VERSION 5.8 ;
BUSBITCHARS "[]" ;
DIVIDERCHAR "/" ;
UNITS
    DATABASE MICRONS 1000 ;
END UNITS

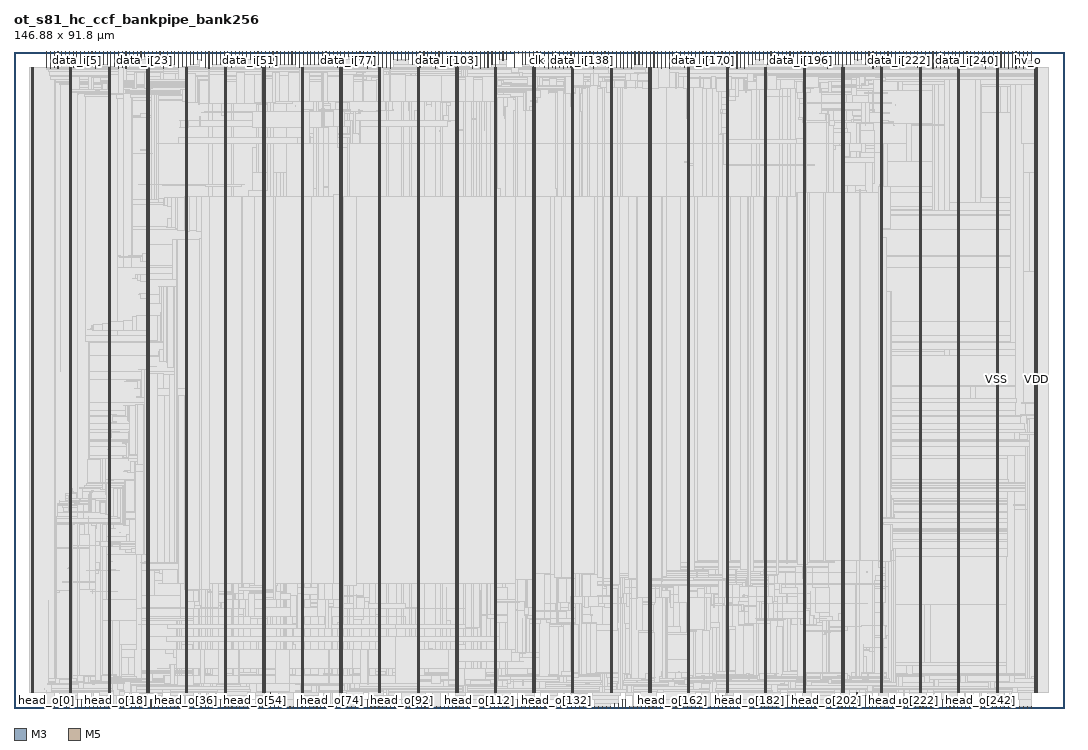
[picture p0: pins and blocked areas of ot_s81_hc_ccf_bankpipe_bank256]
MACRO ot_s81_hc_ccf_bankpipe_bank256
  FOREIGN ot_s81_hc_ccf_bankpipe_bank256 0 0 ;
  CLASS BLOCK ;
  SIZE 146.88 BY 91.8 ;
  PIN clk
    DIRECTION INPUT ;
    USE SIGNAL ;
    PORT
      LAYER M3 ;
        RECT  73.152 91.656 73.17 91.8 ;
    END
    PORT
      LAYER M3 ;
        RECT  73.152 91.579 73.17 91.692 ;
    END
  END clk
  PIN data_i[0]
    DIRECTION INPUT ;
    USE SIGNAL ;
    PORT
      LAYER M5 ;
        RECT  6.144 91.608 6.168 91.8 ;
    END
    PORT
      LAYER M5 ;
        RECT  6.144 89.509 6.168 91.664 ;
    END
  END data_i[0]
  PIN data_i[100]
    DIRECTION INPUT ;
    USE SIGNAL ;
    PORT
      LAYER M5 ;
        RECT  58.896 91.608 58.92 91.8 ;
    END
    PORT
      LAYER M5 ;
        RECT  58.896 89.509 58.92 91.664 ;
    END
  END data_i[100]
  PIN data_i[101]
    DIRECTION INPUT ;
    USE SIGNAL ;
    PORT
      LAYER M3 ;
        RECT  59.436 91.656 59.454 91.8 ;
    END
    PORT
      LAYER M3 ;
        RECT  59.436 90.077 59.454 91.692 ;
    END
  END data_i[101]
  PIN data_i[102]
    DIRECTION INPUT ;
    USE SIGNAL ;
    PORT
      LAYER M5 ;
        RECT  59.952 91.608 59.976 91.8 ;
    END
    PORT
      LAYER M5 ;
        RECT  59.952 90.037 59.976 91.664 ;
    END
  END data_i[102]
  PIN data_i[103]
    DIRECTION INPUT ;
    USE SIGNAL ;
    PORT
      LAYER M3 ;
        RECT  60.516 91.656 60.534 91.8 ;
    END
    PORT
      LAYER M3 ;
        RECT  60.516 90.653 60.534 91.692 ;
    END
  END data_i[103]
  PIN data_i[104]
    DIRECTION INPUT ;
    USE SIGNAL ;
    PORT
      LAYER M5 ;
        RECT  61.008 91.608 61.032 91.8 ;
    END
    PORT
      LAYER M5 ;
        RECT  61.008 90.613 61.032 91.664 ;
    END
  END data_i[104]
  PIN data_i[105]
    DIRECTION INPUT ;
    USE SIGNAL ;
    PORT
      LAYER M3 ;
        RECT  61.56 91.656 61.578 91.8 ;
    END
    PORT
      LAYER M3 ;
        RECT  61.56 90.653 61.578 91.692 ;
    END
  END data_i[105]
  PIN data_i[106]
    DIRECTION INPUT ;
    USE SIGNAL ;
    PORT
      LAYER M5 ;
        RECT  62.064 91.608 62.088 91.8 ;
    END
    PORT
      LAYER M5 ;
        RECT  62.064 89.663 62.088 91.664 ;
    END
  END data_i[106]
  PIN data_i[107]
    DIRECTION INPUT ;
    USE SIGNAL ;
    PORT
      LAYER M3 ;
        RECT  62.604 91.656 62.622 91.8 ;
    END
    PORT
      LAYER M3 ;
        RECT  62.604 90.077 62.622 91.692 ;
    END
  END data_i[107]
  PIN data_i[108]
    DIRECTION INPUT ;
    USE SIGNAL ;
    PORT
      LAYER M5 ;
        RECT  63.12 91.608 63.144 91.8 ;
    END
    PORT
      LAYER M5 ;
        RECT  63.12 90.037 63.144 91.664 ;
    END
  END data_i[108]
  PIN data_i[109]
    DIRECTION INPUT ;
    USE SIGNAL ;
    PORT
      LAYER M3 ;
        RECT  63.684 91.656 63.702 91.8 ;
    END
    PORT
      LAYER M3 ;
        RECT  63.684 90.077 63.702 91.692 ;
    END
  END data_i[109]
  PIN data_i[10]
    DIRECTION INPUT ;
    USE SIGNAL ;
    PORT
      LAYER M5 ;
        RECT  11.424 91.608 11.448 91.8 ;
    END
    PORT
      LAYER M5 ;
        RECT  11.424 89.509 11.448 91.664 ;
    END
  END data_i[10]
  PIN data_i[110]
    DIRECTION INPUT ;
    USE SIGNAL ;
    PORT
      LAYER M5 ;
        RECT  64.176 91.608 64.2 91.8 ;
    END
    PORT
      LAYER M5 ;
        RECT  64.176 89.509 64.2 91.664 ;
    END
  END data_i[110]
  PIN data_i[111]
    DIRECTION INPUT ;
    USE SIGNAL ;
    PORT
      LAYER M3 ;
        RECT  64.728 91.656 64.746 91.8 ;
    END
    PORT
      LAYER M3 ;
        RECT  64.728 89.549 64.746 91.692 ;
    END
  END data_i[111]
  PIN data_i[112]
    DIRECTION INPUT ;
    USE SIGNAL ;
    PORT
      LAYER M5 ;
        RECT  65.232 91.608 65.256 91.8 ;
    END
    PORT
      LAYER M5 ;
        RECT  65.232 89.509 65.256 91.664 ;
    END
  END data_i[112]
  PIN data_i[113]
    DIRECTION INPUT ;
    USE SIGNAL ;
    PORT
      LAYER M3 ;
        RECT  65.772 91.656 65.79 91.8 ;
    END
    PORT
      LAYER M3 ;
        RECT  65.772 89.549 65.79 91.692 ;
    END
  END data_i[113]
  PIN data_i[114]
    DIRECTION INPUT ;
    USE SIGNAL ;
    PORT
      LAYER M5 ;
        RECT  66.288 91.608 66.312 91.8 ;
    END
    PORT
      LAYER M5 ;
        RECT  66.288 89.663 66.312 91.664 ;
    END
  END data_i[114]
  PIN data_i[115]
    DIRECTION INPUT ;
    USE SIGNAL ;
    PORT
      LAYER M3 ;
        RECT  66.852 91.656 66.87 91.8 ;
    END
    PORT
      LAYER M3 ;
        RECT  66.852 90.077 66.87 91.692 ;
    END
  END data_i[115]
  PIN data_i[116]
    DIRECTION INPUT ;
    USE SIGNAL ;
    PORT
      LAYER M5 ;
        RECT  67.344 91.608 67.368 91.8 ;
    END
    PORT
      LAYER M5 ;
        RECT  67.344 89.663 67.368 91.664 ;
    END
  END data_i[116]
  PIN data_i[117]
    DIRECTION INPUT ;
    USE SIGNAL ;
    PORT
      LAYER M3 ;
        RECT  67.896 91.656 67.914 91.8 ;
    END
    PORT
      LAYER M3 ;
        RECT  67.896 90.653 67.914 91.692 ;
    END
  END data_i[117]
  PIN data_i[118]
    DIRECTION INPUT ;
    USE SIGNAL ;
    PORT
      LAYER M5 ;
        RECT  68.4 91.608 68.424 91.8 ;
    END
    PORT
      LAYER M5 ;
        RECT  68.4 90.613 68.424 91.664 ;
    END
  END data_i[118]
  PIN data_i[119]
    DIRECTION INPUT ;
    USE SIGNAL ;
    PORT
      LAYER M3 ;
        RECT  68.94 91.656 68.958 91.8 ;
    END
    PORT
      LAYER M3 ;
        RECT  68.94 90.653 68.958 91.692 ;
    END
  END data_i[119]
  PIN data_i[11]
    DIRECTION INPUT ;
    USE SIGNAL ;
    PORT
      LAYER M3 ;
        RECT  11.952 91.656 11.97 91.8 ;
    END
    PORT
      LAYER M3 ;
        RECT  11.952 90.077 11.97 91.692 ;
    END
  END data_i[11]
  PIN data_i[120]
    DIRECTION INPUT ;
    USE SIGNAL ;
    PORT
      LAYER M5 ;
        RECT  69.456 91.608 69.48 91.8 ;
    END
    PORT
      LAYER M5 ;
        RECT  69.456 91.619 69.48 91.664 ;
    END
  END data_i[120]
  PIN data_i[121]
    DIRECTION INPUT ;
    USE SIGNAL ;
    PORT
      LAYER M3 ;
        RECT  69.984 91.656 70.002 91.8 ;
    END
    PORT
      LAYER M3 ;
        RECT  69.984 89.549 70.002 91.692 ;
    END
  END data_i[121]
  PIN data_i[122]
    DIRECTION INPUT ;
    USE SIGNAL ;
    PORT
      LAYER M5 ;
        RECT  70.512 91.608 70.536 91.8 ;
    END
    PORT
      LAYER M5 ;
        RECT  70.512 91.619 70.536 91.664 ;
    END
  END data_i[122]
  PIN data_i[123]
    DIRECTION INPUT ;
    USE SIGNAL ;
    PORT
      LAYER M3 ;
        RECT  71.064 91.656 71.082 91.8 ;
    END
    PORT
      LAYER M3 ;
        RECT  71.064 90.077 71.082 91.692 ;
    END
  END data_i[123]
  PIN data_i[124]
    DIRECTION INPUT ;
    USE SIGNAL ;
    PORT
      LAYER M5 ;
        RECT  71.568 91.608 71.592 91.8 ;
    END
    PORT
      LAYER M5 ;
        RECT  71.568 90.037 71.592 91.664 ;
    END
  END data_i[124]
  PIN data_i[125]
    DIRECTION INPUT ;
    USE SIGNAL ;
    PORT
      LAYER M3 ;
        RECT  72.108 91.656 72.126 91.8 ;
    END
    PORT
      LAYER M3 ;
        RECT  72.108 90.077 72.126 91.692 ;
    END
  END data_i[125]
  PIN data_i[126]
    DIRECTION INPUT ;
    USE SIGNAL ;
    PORT
      LAYER M5 ;
        RECT  72.624 91.608 72.648 91.8 ;
    END
    PORT
      LAYER M5 ;
        RECT  72.624 89.663 72.648 91.664 ;
    END
  END data_i[126]
  PIN data_i[127]
    DIRECTION INPUT ;
    USE SIGNAL ;
    PORT
      LAYER M5 ;
        RECT  73.68 91.608 73.704 91.8 ;
    END
    PORT
      LAYER M5 ;
        RECT  73.68 90.613 73.704 91.664 ;
    END
  END data_i[127]
  PIN data_i[128]
    DIRECTION INPUT ;
    USE SIGNAL ;
    PORT
      LAYER M3 ;
        RECT  74.232 91.656 74.25 91.8 ;
    END
    PORT
      LAYER M3 ;
        RECT  74.232 89.549 74.25 91.692 ;
    END
  END data_i[128]
  PIN data_i[129]
    DIRECTION INPUT ;
    USE SIGNAL ;
    PORT
      LAYER M5 ;
        RECT  74.736 91.608 74.76 91.8 ;
    END
    PORT
      LAYER M5 ;
        RECT  74.736 89.509 74.76 91.664 ;
    END
  END data_i[129]
  PIN data_i[12]
    DIRECTION INPUT ;
    USE SIGNAL ;
    PORT
      LAYER M5 ;
        RECT  12.48 91.608 12.504 91.8 ;
    END
    PORT
      LAYER M5 ;
        RECT  12.48 90.037 12.504 91.664 ;
    END
  END data_i[12]
  PIN data_i[130]
    DIRECTION INPUT ;
    USE SIGNAL ;
    PORT
      LAYER M3 ;
        RECT  75.276 91.656 75.294 91.8 ;
    END
    PORT
      LAYER M3 ;
        RECT  75.276 89.549 75.294 91.692 ;
    END
  END data_i[130]
  PIN data_i[131]
    DIRECTION INPUT ;
    USE SIGNAL ;
    PORT
      LAYER M5 ;
        RECT  75.792 91.608 75.816 91.8 ;
    END
    PORT
      LAYER M5 ;
        RECT  75.792 89.509 75.816 91.664 ;
    END
  END data_i[131]
  PIN data_i[132]
    DIRECTION INPUT ;
    USE SIGNAL ;
    PORT
      LAYER M3 ;
        RECT  76.32 91.656 76.338 91.8 ;
    END
    PORT
      LAYER M3 ;
        RECT  76.32 89.549 76.338 91.692 ;
    END
  END data_i[132]
  PIN data_i[133]
    DIRECTION INPUT ;
    USE SIGNAL ;
    PORT
      LAYER M5 ;
        RECT  76.848 91.608 76.872 91.8 ;
    END
    PORT
      LAYER M5 ;
        RECT  76.848 89.509 76.872 91.664 ;
    END
  END data_i[133]
  PIN data_i[134]
    DIRECTION INPUT ;
    USE SIGNAL ;
    PORT
      LAYER M3 ;
        RECT  77.4 91.656 77.418 91.8 ;
    END
    PORT
      LAYER M3 ;
        RECT  77.4 89.657 77.418 91.692 ;
    END
  END data_i[134]
  PIN data_i[135]
    DIRECTION INPUT ;
    USE SIGNAL ;
    PORT
      LAYER M5 ;
        RECT  77.904 91.608 77.928 91.8 ;
    END
    PORT
      LAYER M5 ;
        RECT  77.904 89.663 77.928 91.664 ;
    END
  END data_i[135]
  PIN data_i[136]
    DIRECTION INPUT ;
    USE SIGNAL ;
    PORT
      LAYER M3 ;
        RECT  78.444 91.656 78.462 91.8 ;
    END
    PORT
      LAYER M3 ;
        RECT  78.444 90.077 78.462 91.692 ;
    END
  END data_i[136]
  PIN data_i[137]
    DIRECTION INPUT ;
    USE SIGNAL ;
    PORT
      LAYER M5 ;
        RECT  78.96 91.608 78.984 91.8 ;
    END
    PORT
      LAYER M5 ;
        RECT  78.96 90.037 78.984 91.664 ;
    END
  END data_i[137]
  PIN data_i[138]
    DIRECTION INPUT ;
    USE SIGNAL ;
    PORT
      LAYER M3 ;
        RECT  79.488 91.656 79.506 91.8 ;
    END
    PORT
      LAYER M3 ;
        RECT  79.488 90.077 79.506 91.692 ;
    END
  END data_i[138]
  PIN data_i[139]
    DIRECTION INPUT ;
    USE SIGNAL ;
    PORT
      LAYER M5 ;
        RECT  80.016 91.608 80.04 91.8 ;
    END
    PORT
      LAYER M5 ;
        RECT  80.016 90.037 80.04 91.664 ;
    END
  END data_i[139]
  PIN data_i[13]
    DIRECTION INPUT ;
    USE SIGNAL ;
    PORT
      LAYER M3 ;
        RECT  13.032 91.656 13.05 91.8 ;
    END
    PORT
      LAYER M3 ;
        RECT  13.032 90.077 13.05 91.692 ;
    END
  END data_i[13]
  PIN data_i[140]
    DIRECTION INPUT ;
    USE SIGNAL ;
    PORT
      LAYER M3 ;
        RECT  80.568 91.656 80.586 91.8 ;
    END
    PORT
      LAYER M3 ;
        RECT  80.568 90.077 80.586 91.692 ;
    END
  END data_i[140]
  PIN data_i[141]
    DIRECTION INPUT ;
    USE SIGNAL ;
    PORT
      LAYER M5 ;
        RECT  81.072 91.608 81.096 91.8 ;
    END
    PORT
      LAYER M5 ;
        RECT  81.072 89.509 81.096 91.664 ;
    END
  END data_i[141]
  PIN data_i[142]
    DIRECTION INPUT ;
    USE SIGNAL ;
    PORT
      LAYER M3 ;
        RECT  81.612 91.656 81.63 91.8 ;
    END
    PORT
      LAYER M3 ;
        RECT  81.612 90.077 81.63 91.692 ;
    END
  END data_i[142]
  PIN data_i[143]
    DIRECTION INPUT ;
    USE SIGNAL ;
    PORT
      LAYER M5 ;
        RECT  82.128 91.608 82.152 91.8 ;
    END
    PORT
      LAYER M5 ;
        RECT  82.128 90.037 82.152 91.664 ;
    END
  END data_i[143]
  PIN data_i[144]
    DIRECTION INPUT ;
    USE SIGNAL ;
    PORT
      LAYER M3 ;
        RECT  82.656 91.656 82.674 91.8 ;
    END
    PORT
      LAYER M3 ;
        RECT  82.656 90.077 82.674 91.692 ;
    END
  END data_i[144]
  PIN data_i[145]
    DIRECTION INPUT ;
    USE SIGNAL ;
    PORT
      LAYER M5 ;
        RECT  83.184 91.608 83.208 91.8 ;
    END
    PORT
      LAYER M5 ;
        RECT  83.184 89.663 83.208 91.664 ;
    END
  END data_i[145]
  PIN data_i[146]
    DIRECTION INPUT ;
    USE SIGNAL ;
    PORT
      LAYER M3 ;
        RECT  83.736 91.656 83.754 91.8 ;
    END
    PORT
      LAYER M3 ;
        RECT  83.736 89.657 83.754 91.692 ;
    END
  END data_i[146]
  PIN data_i[147]
    DIRECTION INPUT ;
    USE SIGNAL ;
    PORT
      LAYER M5 ;
        RECT  84.24 91.608 84.264 91.8 ;
    END
    PORT
      LAYER M5 ;
        RECT  84.24 89.663 84.264 91.664 ;
    END
  END data_i[147]
  PIN data_i[148]
    DIRECTION INPUT ;
    USE SIGNAL ;
    PORT
      LAYER M3 ;
        RECT  84.78 91.656 84.798 91.8 ;
    END
    PORT
      LAYER M3 ;
        RECT  84.78 89.549 84.798 91.692 ;
    END
  END data_i[148]
  PIN data_i[149]
    DIRECTION INPUT ;
    USE SIGNAL ;
    PORT
      LAYER M5 ;
        RECT  85.296 91.608 85.32 91.8 ;
    END
    PORT
      LAYER M5 ;
        RECT  85.296 89.509 85.32 91.664 ;
    END
  END data_i[149]
  PIN data_i[14]
    DIRECTION INPUT ;
    USE SIGNAL ;
    PORT
      LAYER M5 ;
        RECT  13.536 91.608 13.56 91.8 ;
    END
    PORT
      LAYER M5 ;
        RECT  13.536 89.749 13.56 91.664 ;
    END
  END data_i[14]
  PIN data_i[150]
    DIRECTION INPUT ;
    USE SIGNAL ;
    PORT
      LAYER M3 ;
        RECT  85.824 91.656 85.842 91.8 ;
    END
    PORT
      LAYER M3 ;
        RECT  85.824 89.549 85.842 91.692 ;
    END
  END data_i[150]
  PIN data_i[151]
    DIRECTION INPUT ;
    USE SIGNAL ;
    PORT
      LAYER M5 ;
        RECT  86.352 91.608 86.376 91.8 ;
    END
    PORT
      LAYER M5 ;
        RECT  86.352 89.509 86.376 91.664 ;
    END
  END data_i[151]
  PIN data_i[152]
    DIRECTION INPUT ;
    USE SIGNAL ;
    PORT
      LAYER M3 ;
        RECT  86.868 91.656 86.886 91.8 ;
    END
    PORT
      LAYER M3 ;
        RECT  86.868 90.077 86.886 91.692 ;
    END
  END data_i[152]
  PIN data_i[153]
    DIRECTION INPUT ;
    USE SIGNAL ;
    PORT
      LAYER M5 ;
        RECT  87.408 91.608 87.432 91.8 ;
    END
    PORT
      LAYER M5 ;
        RECT  87.408 90.037 87.432 91.664 ;
    END
  END data_i[153]
  PIN data_i[154]
    DIRECTION INPUT ;
    USE SIGNAL ;
    PORT
      LAYER M3 ;
        RECT  87.948 91.656 87.966 91.8 ;
    END
    PORT
      LAYER M3 ;
        RECT  87.948 90.077 87.966 91.692 ;
    END
  END data_i[154]
  PIN data_i[155]
    DIRECTION INPUT ;
    USE SIGNAL ;
    PORT
      LAYER M5 ;
        RECT  88.464 91.608 88.488 91.8 ;
    END
    PORT
      LAYER M5 ;
        RECT  88.464 89.663 88.488 91.664 ;
    END
  END data_i[155]
  PIN data_i[156]
    DIRECTION INPUT ;
    USE SIGNAL ;
    PORT
      LAYER M3 ;
        RECT  88.992 91.656 89.01 91.8 ;
    END
    PORT
      LAYER M3 ;
        RECT  88.992 89.657 89.01 91.692 ;
    END
  END data_i[156]
  PIN data_i[157]
    DIRECTION INPUT ;
    USE SIGNAL ;
    PORT
      LAYER M5 ;
        RECT  89.52 91.608 89.544 91.8 ;
    END
    PORT
      LAYER M5 ;
        RECT  89.52 89.663 89.544 91.664 ;
    END
  END data_i[157]
  PIN data_i[158]
    DIRECTION INPUT ;
    USE SIGNAL ;
    PORT
      LAYER M3 ;
        RECT  90.036 91.656 90.054 91.8 ;
    END
    PORT
      LAYER M3 ;
        RECT  90.036 89.549 90.054 91.692 ;
    END
  END data_i[158]
  PIN data_i[159]
    DIRECTION INPUT ;
    USE SIGNAL ;
    PORT
      LAYER M5 ;
        RECT  90.576 91.608 90.6 91.8 ;
    END
    PORT
      LAYER M5 ;
        RECT  90.576 89.509 90.6 91.664 ;
    END
  END data_i[159]
  PIN data_i[15]
    DIRECTION INPUT ;
    USE SIGNAL ;
    PORT
      LAYER M3 ;
        RECT  14.076 91.656 14.094 91.8 ;
    END
    PORT
      LAYER M3 ;
        RECT  14.076 89.789 14.094 91.692 ;
    END
  END data_i[15]
  PIN data_i[160]
    DIRECTION INPUT ;
    USE SIGNAL ;
    PORT
      LAYER M3 ;
        RECT  91.116 91.656 91.134 91.8 ;
    END
    PORT
      LAYER M3 ;
        RECT  91.116 89.549 91.134 91.692 ;
    END
  END data_i[160]
  PIN data_i[161]
    DIRECTION INPUT ;
    USE SIGNAL ;
    PORT
      LAYER M5 ;
        RECT  91.632 91.608 91.656 91.8 ;
    END
    PORT
      LAYER M5 ;
        RECT  91.632 89.509 91.656 91.664 ;
    END
  END data_i[161]
  PIN data_i[162]
    DIRECTION INPUT ;
    USE SIGNAL ;
    PORT
      LAYER M3 ;
        RECT  92.16 91.656 92.178 91.8 ;
    END
    PORT
      LAYER M3 ;
        RECT  92.16 90.077 92.178 91.692 ;
    END
  END data_i[162]
  PIN data_i[163]
    DIRECTION INPUT ;
    USE SIGNAL ;
    PORT
      LAYER M5 ;
        RECT  92.688 91.608 92.712 91.8 ;
    END
    PORT
      LAYER M5 ;
        RECT  92.688 90.037 92.712 91.664 ;
    END
  END data_i[163]
  PIN data_i[164]
    DIRECTION INPUT ;
    USE SIGNAL ;
    PORT
      LAYER M3 ;
        RECT  93.204 91.656 93.222 91.8 ;
    END
    PORT
      LAYER M3 ;
        RECT  93.204 90.077 93.222 91.692 ;
    END
  END data_i[164]
  PIN data_i[165]
    DIRECTION INPUT ;
    USE SIGNAL ;
    PORT
      LAYER M5 ;
        RECT  93.744 91.608 93.768 91.8 ;
    END
    PORT
      LAYER M5 ;
        RECT  93.744 89.663 93.768 91.664 ;
    END
  END data_i[165]
  PIN data_i[166]
    DIRECTION INPUT ;
    USE SIGNAL ;
    PORT
      LAYER M3 ;
        RECT  94.284 91.656 94.302 91.8 ;
    END
    PORT
      LAYER M3 ;
        RECT  94.284 90.077 94.302 91.692 ;
    END
  END data_i[166]
  PIN data_i[167]
    DIRECTION INPUT ;
    USE SIGNAL ;
    PORT
      LAYER M5 ;
        RECT  94.8 91.608 94.824 91.8 ;
    END
    PORT
      LAYER M5 ;
        RECT  94.8 90.037 94.824 91.664 ;
    END
  END data_i[167]
  PIN data_i[168]
    DIRECTION INPUT ;
    USE SIGNAL ;
    PORT
      LAYER M3 ;
        RECT  95.328 91.656 95.346 91.8 ;
    END
    PORT
      LAYER M3 ;
        RECT  95.328 90.077 95.346 91.692 ;
    END
  END data_i[168]
  PIN data_i[169]
    DIRECTION INPUT ;
    USE SIGNAL ;
    PORT
      LAYER M5 ;
        RECT  95.856 91.608 95.88 91.8 ;
    END
    PORT
      LAYER M5 ;
        RECT  95.856 89.509 95.88 91.664 ;
    END
  END data_i[169]
  PIN data_i[16]
    DIRECTION INPUT ;
    USE SIGNAL ;
    PORT
      LAYER M5 ;
        RECT  14.592 91.608 14.616 91.8 ;
    END
    PORT
      LAYER M5 ;
        RECT  14.592 89.509 14.616 91.664 ;
    END
  END data_i[16]
  PIN data_i[170]
    DIRECTION INPUT ;
    USE SIGNAL ;
    PORT
      LAYER M3 ;
        RECT  96.372 91.656 96.39 91.8 ;
    END
    PORT
      LAYER M3 ;
        RECT  96.372 90.653 96.39 91.692 ;
    END
  END data_i[170]
  PIN data_i[171]
    DIRECTION INPUT ;
    USE SIGNAL ;
    PORT
      LAYER M5 ;
        RECT  96.912 91.608 96.936 91.8 ;
    END
    PORT
      LAYER M5 ;
        RECT  96.912 90.613 96.936 91.664 ;
    END
  END data_i[171]
  PIN data_i[172]
    DIRECTION INPUT ;
    USE SIGNAL ;
    PORT
      LAYER M3 ;
        RECT  97.452 91.656 97.47 91.8 ;
    END
    PORT
      LAYER M3 ;
        RECT  97.452 90.653 97.47 91.692 ;
    END
  END data_i[172]
  PIN data_i[173]
    DIRECTION INPUT ;
    USE SIGNAL ;
    PORT
      LAYER M5 ;
        RECT  97.968 91.608 97.992 91.8 ;
    END
    PORT
      LAYER M5 ;
        RECT  97.968 90.037 97.992 91.664 ;
    END
  END data_i[173]
  PIN data_i[174]
    DIRECTION INPUT ;
    USE SIGNAL ;
    PORT
      LAYER M3 ;
        RECT  98.496 91.656 98.514 91.8 ;
    END
    PORT
      LAYER M3 ;
        RECT  98.496 90.077 98.514 91.692 ;
    END
  END data_i[174]
  PIN data_i[175]
    DIRECTION INPUT ;
    USE SIGNAL ;
    PORT
      LAYER M5 ;
        RECT  99.024 91.608 99.048 91.8 ;
    END
    PORT
      LAYER M5 ;
        RECT  99.024 90.037 99.048 91.664 ;
    END
  END data_i[175]
  PIN data_i[176]
    DIRECTION INPUT ;
    USE SIGNAL ;
    PORT
      LAYER M3 ;
        RECT  99.54 91.656 99.558 91.8 ;
    END
    PORT
      LAYER M3 ;
        RECT  99.54 90.077 99.558 91.692 ;
    END
  END data_i[176]
  PIN data_i[177]
    DIRECTION INPUT ;
    USE SIGNAL ;
    PORT
      LAYER M5 ;
        RECT  100.08 91.608 100.104 91.8 ;
    END
    PORT
      LAYER M5 ;
        RECT  100.08 89.663 100.104 91.664 ;
    END
  END data_i[177]
  PIN data_i[178]
    DIRECTION INPUT ;
    USE SIGNAL ;
    PORT
      LAYER M3 ;
        RECT  100.62 91.656 100.638 91.8 ;
    END
    PORT
      LAYER M3 ;
        RECT  100.62 89.549 100.638 91.692 ;
    END
  END data_i[178]
  PIN data_i[179]
    DIRECTION INPUT ;
    USE SIGNAL ;
    PORT
      LAYER M5 ;
        RECT  101.136 91.608 101.16 91.8 ;
    END
    PORT
      LAYER M5 ;
        RECT  101.136 89.509 101.16 91.664 ;
    END
  END data_i[179]
  PIN data_i[17]
    DIRECTION INPUT ;
    USE SIGNAL ;
    PORT
      LAYER M3 ;
        RECT  15.12 91.656 15.138 91.8 ;
    END
    PORT
      LAYER M3 ;
        RECT  15.12 89.549 15.138 91.692 ;
    END
  END data_i[17]
  PIN data_i[180]
    DIRECTION INPUT ;
    USE SIGNAL ;
    PORT
      LAYER M3 ;
        RECT  101.664 91.656 101.682 91.8 ;
    END
    PORT
      LAYER M3 ;
        RECT  101.664 89.549 101.682 91.692 ;
    END
  END data_i[180]
  PIN data_i[181]
    DIRECTION INPUT ;
    USE SIGNAL ;
    PORT
      LAYER M5 ;
        RECT  102.192 91.608 102.216 91.8 ;
    END
    PORT
      LAYER M5 ;
        RECT  102.192 89.509 102.216 91.664 ;
    END
  END data_i[181]
  PIN data_i[182]
    DIRECTION INPUT ;
    USE SIGNAL ;
    PORT
      LAYER M3 ;
        RECT  102.708 91.656 102.726 91.8 ;
    END
    PORT
      LAYER M3 ;
        RECT  102.708 90.077 102.726 91.692 ;
    END
  END data_i[182]
  PIN data_i[183]
    DIRECTION INPUT ;
    USE SIGNAL ;
    PORT
      LAYER M5 ;
        RECT  103.248 91.608 103.272 91.8 ;
    END
    PORT
      LAYER M5 ;
        RECT  103.248 90.037 103.272 91.664 ;
    END
  END data_i[183]
  PIN data_i[184]
    DIRECTION INPUT ;
    USE SIGNAL ;
    PORT
      LAYER M3 ;
        RECT  103.752 91.656 103.77 91.8 ;
    END
    PORT
      LAYER M3 ;
        RECT  103.752 90.653 103.77 91.692 ;
    END
  END data_i[184]
  PIN data_i[185]
    DIRECTION INPUT ;
    USE SIGNAL ;
    PORT
      LAYER M5 ;
        RECT  104.304 91.608 104.328 91.8 ;
    END
    PORT
      LAYER M5 ;
        RECT  104.304 90.613 104.328 91.664 ;
    END
  END data_i[185]
  PIN data_i[186]
    DIRECTION INPUT ;
    USE SIGNAL ;
    PORT
      LAYER M3 ;
        RECT  104.832 91.656 104.85 91.8 ;
    END
    PORT
      LAYER M3 ;
        RECT  104.832 90.653 104.85 91.692 ;
    END
  END data_i[186]
  PIN data_i[187]
    DIRECTION INPUT ;
    USE SIGNAL ;
    PORT
      LAYER M5 ;
        RECT  105.36 91.608 105.384 91.8 ;
    END
    PORT
      LAYER M5 ;
        RECT  105.36 90.037 105.384 91.664 ;
    END
  END data_i[187]
  PIN data_i[188]
    DIRECTION INPUT ;
    USE SIGNAL ;
    PORT
      LAYER M3 ;
        RECT  105.876 91.656 105.894 91.8 ;
    END
    PORT
      LAYER M3 ;
        RECT  105.876 90.077 105.894 91.692 ;
    END
  END data_i[188]
  PIN data_i[189]
    DIRECTION INPUT ;
    USE SIGNAL ;
    PORT
      LAYER M5 ;
        RECT  106.416 91.608 106.44 91.8 ;
    END
    PORT
      LAYER M5 ;
        RECT  106.416 90.037 106.44 91.664 ;
    END
  END data_i[189]
  PIN data_i[18]
    DIRECTION INPUT ;
    USE SIGNAL ;
    PORT
      LAYER M5 ;
        RECT  15.648 91.608 15.672 91.8 ;
    END
    PORT
      LAYER M5 ;
        RECT  15.648 89.509 15.672 91.664 ;
    END
  END data_i[18]
  PIN data_i[190]
    DIRECTION INPUT ;
    USE SIGNAL ;
    PORT
      LAYER M3 ;
        RECT  106.92 91.656 106.938 91.8 ;
    END
    PORT
      LAYER M3 ;
        RECT  106.92 90.077 106.938 91.692 ;
    END
  END data_i[190]
  PIN data_i[191]
    DIRECTION INPUT ;
    USE SIGNAL ;
    PORT
      LAYER M5 ;
        RECT  107.472 91.608 107.496 91.8 ;
    END
    PORT
      LAYER M5 ;
        RECT  107.472 90.037 107.496 91.664 ;
    END
  END data_i[191]
  PIN data_i[192]
    DIRECTION INPUT ;
    USE SIGNAL ;
    PORT
      LAYER M3 ;
        RECT  108 91.656 108.018 91.8 ;
    END
    PORT
      LAYER M3 ;
        RECT  108 90.077 108.018 91.692 ;
    END
  END data_i[192]
  PIN data_i[193]
    DIRECTION INPUT ;
    USE SIGNAL ;
    PORT
      LAYER M5 ;
        RECT  108.528 91.608 108.552 91.8 ;
    END
    PORT
      LAYER M5 ;
        RECT  108.528 90.037 108.552 91.664 ;
    END
  END data_i[193]
  PIN data_i[194]
    DIRECTION INPUT ;
    USE SIGNAL ;
    PORT
      LAYER M3 ;
        RECT  109.044 91.656 109.062 91.8 ;
    END
    PORT
      LAYER M3 ;
        RECT  109.044 90.077 109.062 91.692 ;
    END
  END data_i[194]
  PIN data_i[195]
    DIRECTION INPUT ;
    USE SIGNAL ;
    PORT
      LAYER M5 ;
        RECT  109.584 91.608 109.608 91.8 ;
    END
    PORT
      LAYER M5 ;
        RECT  109.584 89.663 109.608 91.664 ;
    END
  END data_i[195]
  PIN data_i[196]
    DIRECTION INPUT ;
    USE SIGNAL ;
    PORT
      LAYER M3 ;
        RECT  110.088 91.656 110.106 91.8 ;
    END
    PORT
      LAYER M3 ;
        RECT  110.088 91.181 110.106 91.692 ;
    END
  END data_i[196]
  PIN data_i[197]
    DIRECTION INPUT ;
    USE SIGNAL ;
    PORT
      LAYER M5 ;
        RECT  110.64 91.608 110.664 91.8 ;
    END
    PORT
      LAYER M5 ;
        RECT  110.64 91.141 110.664 91.664 ;
    END
  END data_i[197]
  PIN data_i[198]
    DIRECTION INPUT ;
    USE SIGNAL ;
    PORT
      LAYER M3 ;
        RECT  111.168 91.656 111.186 91.8 ;
    END
    PORT
      LAYER M3 ;
        RECT  111.168 91.181 111.186 91.692 ;
    END
  END data_i[198]
  PIN data_i[199]
    DIRECTION INPUT ;
    USE SIGNAL ;
    PORT
      LAYER M5 ;
        RECT  111.696 91.608 111.72 91.8 ;
    END
    PORT
      LAYER M5 ;
        RECT  111.696 90.037 111.72 91.664 ;
    END
  END data_i[199]
  PIN data_i[19]
    DIRECTION INPUT ;
    USE SIGNAL ;
    PORT
      LAYER M3 ;
        RECT  16.2 91.656 16.218 91.8 ;
    END
    PORT
      LAYER M3 ;
        RECT  16.2 90.077 16.218 91.692 ;
    END
  END data_i[19]
  PIN data_i[1]
    DIRECTION INPUT ;
    USE SIGNAL ;
    PORT
      LAYER M3 ;
        RECT  6.696 91.656 6.714 91.8 ;
    END
    PORT
      LAYER M3 ;
        RECT  6.696 90.077 6.714 91.692 ;
    END
  END data_i[1]
  PIN data_i[200]
    DIRECTION INPUT ;
    USE SIGNAL ;
    PORT
      LAYER M3 ;
        RECT  112.212 91.656 112.23 91.8 ;
    END
    PORT
      LAYER M3 ;
        RECT  112.212 90.077 112.23 91.692 ;
    END
  END data_i[200]
  PIN data_i[201]
    DIRECTION INPUT ;
    USE SIGNAL ;
    PORT
      LAYER M5 ;
        RECT  112.752 91.608 112.776 91.8 ;
    END
    PORT
      LAYER M5 ;
        RECT  112.752 90.037 112.776 91.664 ;
    END
  END data_i[201]
  PIN data_i[202]
    DIRECTION INPUT ;
    USE SIGNAL ;
    PORT
      LAYER M3 ;
        RECT  113.256 91.656 113.274 91.8 ;
    END
    PORT
      LAYER M3 ;
        RECT  113.256 90.077 113.274 91.692 ;
    END
  END data_i[202]
  PIN data_i[203]
    DIRECTION INPUT ;
    USE SIGNAL ;
    PORT
      LAYER M5 ;
        RECT  113.808 91.608 113.832 91.8 ;
    END
    PORT
      LAYER M5 ;
        RECT  113.808 89.509 113.832 91.664 ;
    END
  END data_i[203]
  PIN data_i[204]
    DIRECTION INPUT ;
    USE SIGNAL ;
    PORT
      LAYER M3 ;
        RECT  114.336 91.656 114.354 91.8 ;
    END
    PORT
      LAYER M3 ;
        RECT  114.336 90.077 114.354 91.692 ;
    END
  END data_i[204]
  PIN data_i[205]
    DIRECTION INPUT ;
    USE SIGNAL ;
    PORT
      LAYER M5 ;
        RECT  114.864 91.608 114.888 91.8 ;
    END
    PORT
      LAYER M5 ;
        RECT  114.864 90.037 114.888 91.664 ;
    END
  END data_i[205]
  PIN data_i[206]
    DIRECTION INPUT ;
    USE SIGNAL ;
    PORT
      LAYER M3 ;
        RECT  115.38 91.656 115.398 91.8 ;
    END
    PORT
      LAYER M3 ;
        RECT  115.38 90.077 115.398 91.692 ;
    END
  END data_i[206]
  PIN data_i[207]
    DIRECTION INPUT ;
    USE SIGNAL ;
    PORT
      LAYER M5 ;
        RECT  115.92 91.608 115.944 91.8 ;
    END
    PORT
      LAYER M5 ;
        RECT  115.92 89.663 115.944 91.664 ;
    END
  END data_i[207]
  PIN data_i[208]
    DIRECTION INPUT ;
    USE SIGNAL ;
    PORT
      LAYER M3 ;
        RECT  116.424 91.656 116.442 91.8 ;
    END
    PORT
      LAYER M3 ;
        RECT  116.424 90.077 116.442 91.692 ;
    END
  END data_i[208]
  PIN data_i[209]
    DIRECTION INPUT ;
    USE SIGNAL ;
    PORT
      LAYER M5 ;
        RECT  116.976 91.608 117 91.8 ;
    END
    PORT
      LAYER M5 ;
        RECT  116.976 90.037 117 91.664 ;
    END
  END data_i[209]
  PIN data_i[20]
    DIRECTION INPUT ;
    USE SIGNAL ;
    PORT
      LAYER M5 ;
        RECT  16.704 91.608 16.728 91.8 ;
    END
    PORT
      LAYER M5 ;
        RECT  16.704 90.037 16.728 91.664 ;
    END
  END data_i[20]
  PIN data_i[210]
    DIRECTION INPUT ;
    USE SIGNAL ;
    PORT
      LAYER M3 ;
        RECT  117.504 91.656 117.522 91.8 ;
    END
    PORT
      LAYER M3 ;
        RECT  117.504 90.653 117.522 91.692 ;
    END
  END data_i[210]
  PIN data_i[211]
    DIRECTION INPUT ;
    USE SIGNAL ;
    PORT
      LAYER M5 ;
        RECT  118.032 91.608 118.056 91.8 ;
    END
    PORT
      LAYER M5 ;
        RECT  118.032 90.613 118.056 91.664 ;
    END
  END data_i[211]
  PIN data_i[212]
    DIRECTION INPUT ;
    USE SIGNAL ;
    PORT
      LAYER M3 ;
        RECT  118.548 91.656 118.566 91.8 ;
    END
    PORT
      LAYER M3 ;
        RECT  118.548 90.653 118.566 91.692 ;
    END
  END data_i[212]
  PIN data_i[213]
    DIRECTION INPUT ;
    USE SIGNAL ;
    PORT
      LAYER M5 ;
        RECT  119.088 91.608 119.112 91.8 ;
    END
    PORT
      LAYER M5 ;
        RECT  119.088 90.037 119.112 91.664 ;
    END
  END data_i[213]
  PIN data_i[214]
    DIRECTION INPUT ;
    USE SIGNAL ;
    PORT
      LAYER M3 ;
        RECT  119.592 91.656 119.61 91.8 ;
    END
    PORT
      LAYER M3 ;
        RECT  119.592 90.077 119.61 91.692 ;
    END
  END data_i[214]
  PIN data_i[215]
    DIRECTION INPUT ;
    USE SIGNAL ;
    PORT
      LAYER M5 ;
        RECT  120.144 91.608 120.168 91.8 ;
    END
    PORT
      LAYER M5 ;
        RECT  120.144 89.509 120.168 91.664 ;
    END
  END data_i[215]
  PIN data_i[216]
    DIRECTION INPUT ;
    USE SIGNAL ;
    PORT
      LAYER M3 ;
        RECT  120.672 91.656 120.69 91.8 ;
    END
    PORT
      LAYER M3 ;
        RECT  120.672 89.789 120.69 91.692 ;
    END
  END data_i[216]
  PIN data_i[217]
    DIRECTION INPUT ;
    USE SIGNAL ;
    PORT
      LAYER M5 ;
        RECT  121.2 91.608 121.224 91.8 ;
    END
    PORT
      LAYER M5 ;
        RECT  121.2 89.663 121.224 91.664 ;
    END
  END data_i[217]
  PIN data_i[218]
    DIRECTION INPUT ;
    USE SIGNAL ;
    PORT
      LAYER M3 ;
        RECT  121.716 91.656 121.734 91.8 ;
    END
    PORT
      LAYER M3 ;
        RECT  121.716 90.077 121.734 91.692 ;
    END
  END data_i[218]
  PIN data_i[219]
    DIRECTION INPUT ;
    USE SIGNAL ;
    PORT
      LAYER M5 ;
        RECT  122.256 91.608 122.28 91.8 ;
    END
    PORT
      LAYER M5 ;
        RECT  122.256 90.037 122.28 91.664 ;
    END
  END data_i[219]
  PIN data_i[21]
    DIRECTION INPUT ;
    USE SIGNAL ;
    PORT
      LAYER M3 ;
        RECT  17.244 91.656 17.262 91.8 ;
    END
    PORT
      LAYER M3 ;
        RECT  17.244 90.653 17.262 91.692 ;
    END
  END data_i[21]
  PIN data_i[220]
    DIRECTION INPUT ;
    USE SIGNAL ;
    PORT
      LAYER M3 ;
        RECT  122.76 91.656 122.778 91.8 ;
    END
    PORT
      LAYER M3 ;
        RECT  122.76 90.077 122.778 91.692 ;
    END
  END data_i[220]
  PIN data_i[221]
    DIRECTION INPUT ;
    USE SIGNAL ;
    PORT
      LAYER M5 ;
        RECT  123.312 91.608 123.336 91.8 ;
    END
    PORT
      LAYER M5 ;
        RECT  123.312 89.509 123.336 91.664 ;
    END
  END data_i[221]
  PIN data_i[222]
    DIRECTION INPUT ;
    USE SIGNAL ;
    PORT
      LAYER M3 ;
        RECT  123.804 91.656 123.822 91.8 ;
    END
    PORT
      LAYER M3 ;
        RECT  123.804 90.653 123.822 91.692 ;
    END
  END data_i[222]
  PIN data_i[223]
    DIRECTION INPUT ;
    USE SIGNAL ;
    PORT
      LAYER M5 ;
        RECT  124.368 91.608 124.392 91.8 ;
    END
    PORT
      LAYER M5 ;
        RECT  124.368 90.613 124.392 91.664 ;
    END
  END data_i[223]
  PIN data_i[224]
    DIRECTION INPUT ;
    USE SIGNAL ;
    PORT
      LAYER M3 ;
        RECT  124.884 91.656 124.902 91.8 ;
    END
    PORT
      LAYER M3 ;
        RECT  124.884 90.653 124.902 91.692 ;
    END
  END data_i[224]
  PIN data_i[225]
    DIRECTION INPUT ;
    USE SIGNAL ;
    PORT
      LAYER M5 ;
        RECT  125.376 91.608 125.4 91.8 ;
    END
    PORT
      LAYER M5 ;
        RECT  125.376 90.037 125.4 91.664 ;
    END
  END data_i[225]
  PIN data_i[226]
    DIRECTION INPUT ;
    USE SIGNAL ;
    PORT
      LAYER M3 ;
        RECT  125.928 91.656 125.946 91.8 ;
    END
    PORT
      LAYER M3 ;
        RECT  125.928 90.077 125.946 91.692 ;
    END
  END data_i[226]
  PIN data_i[227]
    DIRECTION INPUT ;
    USE SIGNAL ;
    PORT
      LAYER M5 ;
        RECT  126.432 91.608 126.456 91.8 ;
    END
    PORT
      LAYER M5 ;
        RECT  126.432 89.663 126.456 91.664 ;
    END
  END data_i[227]
  PIN data_i[228]
    DIRECTION INPUT ;
    USE SIGNAL ;
    PORT
      LAYER M3 ;
        RECT  126.972 91.656 126.99 91.8 ;
    END
    PORT
      LAYER M3 ;
        RECT  126.972 90.077 126.99 91.692 ;
    END
  END data_i[228]
  PIN data_i[229]
    DIRECTION INPUT ;
    USE SIGNAL ;
    PORT
      LAYER M5 ;
        RECT  127.488 91.608 127.512 91.8 ;
    END
    PORT
      LAYER M5 ;
        RECT  127.488 90.037 127.512 91.664 ;
    END
  END data_i[229]
  PIN data_i[22]
    DIRECTION INPUT ;
    USE SIGNAL ;
    PORT
      LAYER M5 ;
        RECT  17.76 91.608 17.784 91.8 ;
    END
    PORT
      LAYER M5 ;
        RECT  17.76 90.613 17.784 91.664 ;
    END
  END data_i[22]
  PIN data_i[230]
    DIRECTION INPUT ;
    USE SIGNAL ;
    PORT
      LAYER M3 ;
        RECT  128.052 91.656 128.07 91.8 ;
    END
    PORT
      LAYER M3 ;
        RECT  128.052 90.077 128.07 91.692 ;
    END
  END data_i[230]
  PIN data_i[231]
    DIRECTION INPUT ;
    USE SIGNAL ;
    PORT
      LAYER M5 ;
        RECT  128.544 91.608 128.568 91.8 ;
    END
    PORT
      LAYER M5 ;
        RECT  128.544 89.509 128.568 91.664 ;
    END
  END data_i[231]
  PIN data_i[232]
    DIRECTION INPUT ;
    USE SIGNAL ;
    PORT
      LAYER M3 ;
        RECT  129.096 91.656 129.114 91.8 ;
    END
    PORT
      LAYER M3 ;
        RECT  129.096 89.549 129.114 91.692 ;
    END
  END data_i[232]
  PIN data_i[233]
    DIRECTION INPUT ;
    USE SIGNAL ;
    PORT
      LAYER M5 ;
        RECT  129.6 91.608 129.624 91.8 ;
    END
    PORT
      LAYER M5 ;
        RECT  129.6 89.509 129.624 91.664 ;
    END
  END data_i[233]
  PIN data_i[234]
    DIRECTION INPUT ;
    USE SIGNAL ;
    PORT
      LAYER M3 ;
        RECT  130.14 91.656 130.158 91.8 ;
    END
    PORT
      LAYER M3 ;
        RECT  130.14 89.549 130.158 91.692 ;
    END
  END data_i[234]
  PIN data_i[235]
    DIRECTION INPUT ;
    USE SIGNAL ;
    PORT
      LAYER M5 ;
        RECT  130.656 91.608 130.68 91.8 ;
    END
    PORT
      LAYER M5 ;
        RECT  130.656 89.509 130.68 91.664 ;
    END
  END data_i[235]
  PIN data_i[236]
    DIRECTION INPUT ;
    USE SIGNAL ;
    PORT
      LAYER M3 ;
        RECT  131.22 91.656 131.238 91.8 ;
    END
    PORT
      LAYER M3 ;
        RECT  131.22 90.077 131.238 91.692 ;
    END
  END data_i[236]
  PIN data_i[237]
    DIRECTION INPUT ;
    USE SIGNAL ;
    PORT
      LAYER M5 ;
        RECT  131.712 91.608 131.736 91.8 ;
    END
    PORT
      LAYER M5 ;
        RECT  131.712 90.037 131.736 91.664 ;
    END
  END data_i[237]
  PIN data_i[238]
    DIRECTION INPUT ;
    USE SIGNAL ;
    PORT
      LAYER M3 ;
        RECT  132.264 91.656 132.282 91.8 ;
    END
    PORT
      LAYER M3 ;
        RECT  132.264 90.077 132.282 91.692 ;
    END
  END data_i[238]
  PIN data_i[239]
    DIRECTION INPUT ;
    USE SIGNAL ;
    PORT
      LAYER M5 ;
        RECT  132.768 91.608 132.792 91.8 ;
    END
    PORT
      LAYER M5 ;
        RECT  132.768 89.663 132.792 91.664 ;
    END
  END data_i[239]
  PIN data_i[23]
    DIRECTION INPUT ;
    USE SIGNAL ;
    PORT
      LAYER M3 ;
        RECT  18.288 91.656 18.306 91.8 ;
    END
    PORT
      LAYER M3 ;
        RECT  18.288 91.181 18.306 91.692 ;
    END
  END data_i[23]
  PIN data_i[240]
    DIRECTION INPUT ;
    USE SIGNAL ;
    PORT
      LAYER M3 ;
        RECT  133.308 91.656 133.326 91.8 ;
    END
    PORT
      LAYER M3 ;
        RECT  133.308 90.077 133.326 91.692 ;
    END
  END data_i[240]
  PIN data_i[241]
    DIRECTION INPUT ;
    USE SIGNAL ;
    PORT
      LAYER M5 ;
        RECT  133.824 91.608 133.848 91.8 ;
    END
    PORT
      LAYER M5 ;
        RECT  133.824 90.037 133.848 91.664 ;
    END
  END data_i[241]
  PIN data_i[242]
    DIRECTION INPUT ;
    USE SIGNAL ;
    PORT
      LAYER M3 ;
        RECT  134.388 91.656 134.406 91.8 ;
    END
    PORT
      LAYER M3 ;
        RECT  134.388 90.077 134.406 91.692 ;
    END
  END data_i[242]
  PIN data_i[243]
    DIRECTION INPUT ;
    USE SIGNAL ;
    PORT
      LAYER M5 ;
        RECT  134.88 91.608 134.904 91.8 ;
    END
    PORT
      LAYER M5 ;
        RECT  134.88 90.037 134.904 91.664 ;
    END
  END data_i[243]
  PIN data_i[244]
    DIRECTION INPUT ;
    USE SIGNAL ;
    PORT
      LAYER M3 ;
        RECT  135.432 91.656 135.45 91.8 ;
    END
    PORT
      LAYER M3 ;
        RECT  135.432 90.077 135.45 91.692 ;
    END
  END data_i[244]
  PIN data_i[245]
    DIRECTION INPUT ;
    USE SIGNAL ;
    PORT
      LAYER M5 ;
        RECT  135.936 91.608 135.96 91.8 ;
    END
    PORT
      LAYER M5 ;
        RECT  135.936 89.509 135.96 91.664 ;
    END
  END data_i[245]
  PIN data_i[246]
    DIRECTION INPUT ;
    USE SIGNAL ;
    PORT
      LAYER M3 ;
        RECT  136.476 91.656 136.494 91.8 ;
    END
    PORT
      LAYER M3 ;
        RECT  136.476 90.077 136.494 91.692 ;
    END
  END data_i[246]
  PIN data_i[247]
    DIRECTION INPUT ;
    USE SIGNAL ;
    PORT
      LAYER M5 ;
        RECT  136.992 91.608 137.016 91.8 ;
    END
    PORT
      LAYER M5 ;
        RECT  136.992 90.037 137.016 91.664 ;
    END
  END data_i[247]
  PIN data_i[248]
    DIRECTION INPUT ;
    USE SIGNAL ;
    PORT
      LAYER M3 ;
        RECT  137.556 91.656 137.574 91.8 ;
    END
    PORT
      LAYER M3 ;
        RECT  137.556 90.077 137.574 91.692 ;
    END
  END data_i[248]
  PIN data_i[249]
    DIRECTION INPUT ;
    USE SIGNAL ;
    PORT
      LAYER M5 ;
        RECT  138.048 91.608 138.072 91.8 ;
    END
    PORT
      LAYER M5 ;
        RECT  138.048 89.663 138.072 91.664 ;
    END
  END data_i[249]
  PIN data_i[24]
    DIRECTION INPUT ;
    USE SIGNAL ;
    PORT
      LAYER M5 ;
        RECT  18.816 91.608 18.84 91.8 ;
    END
    PORT
      LAYER M5 ;
        RECT  18.816 91.141 18.84 91.664 ;
    END
  END data_i[24]
  PIN data_i[250]
    DIRECTION INPUT ;
    USE SIGNAL ;
    PORT
      LAYER M3 ;
        RECT  138.6 91.656 138.618 91.8 ;
    END
    PORT
      LAYER M3 ;
        RECT  138.6 89.549 138.618 91.692 ;
    END
  END data_i[250]
  PIN data_i[251]
    DIRECTION INPUT ;
    USE SIGNAL ;
    PORT
      LAYER M5 ;
        RECT  139.104 91.608 139.128 91.8 ;
    END
    PORT
      LAYER M5 ;
        RECT  139.104 89.509 139.128 91.664 ;
    END
  END data_i[251]
  PIN data_i[252]
    DIRECTION INPUT ;
    USE SIGNAL ;
    PORT
      LAYER M3 ;
        RECT  139.644 91.656 139.662 91.8 ;
    END
    PORT
      LAYER M3 ;
        RECT  139.644 89.549 139.662 91.692 ;
    END
  END data_i[252]
  PIN data_i[253]
    DIRECTION INPUT ;
    USE SIGNAL ;
    PORT
      LAYER M5 ;
        RECT  140.16 91.608 140.184 91.8 ;
    END
    PORT
      LAYER M5 ;
        RECT  140.16 89.509 140.184 91.664 ;
    END
  END data_i[253]
  PIN data_i[254]
    DIRECTION INPUT ;
    USE SIGNAL ;
    PORT
      LAYER M3 ;
        RECT  140.688 91.656 140.706 91.8 ;
    END
    PORT
      LAYER M3 ;
        RECT  140.688 89.549 140.706 91.692 ;
    END
  END data_i[254]
  PIN data_i[255]
    DIRECTION INPUT ;
    USE SIGNAL ;
    PORT
      LAYER M5 ;
        RECT  141.216 91.608 141.24 91.8 ;
    END
    PORT
      LAYER M5 ;
        RECT  141.216 89.509 141.24 91.664 ;
    END
  END data_i[255]
  PIN data_i[25]
    DIRECTION INPUT ;
    USE SIGNAL ;
    PORT
      LAYER M3 ;
        RECT  19.332 91.656 19.35 91.8 ;
    END
    PORT
      LAYER M3 ;
        RECT  19.332 91.181 19.35 91.692 ;
    END
  END data_i[25]
  PIN data_i[26]
    DIRECTION INPUT ;
    USE SIGNAL ;
    PORT
      LAYER M5 ;
        RECT  19.872 91.608 19.896 91.8 ;
    END
    PORT
      LAYER M5 ;
        RECT  19.872 90.037 19.896 91.664 ;
    END
  END data_i[26]
  PIN data_i[27]
    DIRECTION INPUT ;
    USE SIGNAL ;
    PORT
      LAYER M3 ;
        RECT  20.412 91.656 20.43 91.8 ;
    END
    PORT
      LAYER M3 ;
        RECT  20.412 90.077 20.43 91.692 ;
    END
  END data_i[27]
  PIN data_i[28]
    DIRECTION INPUT ;
    USE SIGNAL ;
    PORT
      LAYER M5 ;
        RECT  20.928 91.608 20.952 91.8 ;
    END
    PORT
      LAYER M5 ;
        RECT  20.928 89.509 20.952 91.664 ;
    END
  END data_i[28]
  PIN data_i[29]
    DIRECTION INPUT ;
    USE SIGNAL ;
    PORT
      LAYER M3 ;
        RECT  21.456 91.656 21.474 91.8 ;
    END
    PORT
      LAYER M3 ;
        RECT  21.456 90.077 21.474 91.692 ;
    END
  END data_i[29]
  PIN data_i[2]
    DIRECTION INPUT ;
    USE SIGNAL ;
    PORT
      LAYER M5 ;
        RECT  7.2 91.608 7.224 91.8 ;
    END
    PORT
      LAYER M5 ;
        RECT  7.2 90.037 7.224 91.664 ;
    END
  END data_i[2]
  PIN data_i[30]
    DIRECTION INPUT ;
    USE SIGNAL ;
    PORT
      LAYER M5 ;
        RECT  21.984 91.608 22.008 91.8 ;
    END
    PORT
      LAYER M5 ;
        RECT  21.984 90.037 22.008 91.664 ;
    END
  END data_i[30]
  PIN data_i[31]
    DIRECTION INPUT ;
    USE SIGNAL ;
    PORT
      LAYER M3 ;
        RECT  22.5 91.656 22.518 91.8 ;
    END
    PORT
      LAYER M3 ;
        RECT  22.5 90.077 22.518 91.692 ;
    END
  END data_i[31]
  PIN data_i[32]
    DIRECTION INPUT ;
    USE SIGNAL ;
    PORT
      LAYER M5 ;
        RECT  23.04 91.608 23.064 91.8 ;
    END
    PORT
      LAYER M5 ;
        RECT  23.04 89.663 23.064 91.664 ;
    END
  END data_i[32]
  PIN data_i[33]
    DIRECTION INPUT ;
    USE SIGNAL ;
    PORT
      LAYER M3 ;
        RECT  23.58 91.656 23.598 91.8 ;
    END
    PORT
      LAYER M3 ;
        RECT  23.58 89.789 23.598 91.692 ;
    END
  END data_i[33]
  PIN data_i[34]
    DIRECTION INPUT ;
    USE SIGNAL ;
    PORT
      LAYER M5 ;
        RECT  24.096 91.608 24.12 91.8 ;
    END
    PORT
      LAYER M5 ;
        RECT  24.096 89.663 24.12 91.664 ;
    END
  END data_i[34]
  PIN data_i[35]
    DIRECTION INPUT ;
    USE SIGNAL ;
    PORT
      LAYER M3 ;
        RECT  24.624 91.656 24.642 91.8 ;
    END
    PORT
      LAYER M3 ;
        RECT  24.624 90.077 24.642 91.692 ;
    END
  END data_i[35]
  PIN data_i[36]
    DIRECTION INPUT ;
    USE SIGNAL ;
    PORT
      LAYER M5 ;
        RECT  25.152 91.608 25.176 91.8 ;
    END
    PORT
      LAYER M5 ;
        RECT  25.152 90.037 25.176 91.664 ;
    END
  END data_i[36]
  PIN data_i[37]
    DIRECTION INPUT ;
    USE SIGNAL ;
    PORT
      LAYER M3 ;
        RECT  25.668 91.656 25.686 91.8 ;
    END
    PORT
      LAYER M3 ;
        RECT  25.668 90.653 25.686 91.692 ;
    END
  END data_i[37]
  PIN data_i[38]
    DIRECTION INPUT ;
    USE SIGNAL ;
    PORT
      LAYER M5 ;
        RECT  26.208 91.608 26.232 91.8 ;
    END
    PORT
      LAYER M5 ;
        RECT  26.208 90.613 26.232 91.664 ;
    END
  END data_i[38]
  PIN data_i[39]
    DIRECTION INPUT ;
    USE SIGNAL ;
    PORT
      LAYER M3 ;
        RECT  26.748 91.656 26.766 91.8 ;
    END
    PORT
      LAYER M3 ;
        RECT  26.748 89.549 26.766 91.692 ;
    END
  END data_i[39]
  PIN data_i[3]
    DIRECTION INPUT ;
    USE SIGNAL ;
    PORT
      LAYER M3 ;
        RECT  7.74 91.656 7.758 91.8 ;
    END
    PORT
      LAYER M3 ;
        RECT  7.74 90.077 7.758 91.692 ;
    END
  END data_i[3]
  PIN data_i[40]
    DIRECTION INPUT ;
    USE SIGNAL ;
    PORT
      LAYER M5 ;
        RECT  27.264 91.608 27.288 91.8 ;
    END
    PORT
      LAYER M5 ;
        RECT  27.264 89.509 27.288 91.664 ;
    END
  END data_i[40]
  PIN data_i[41]
    DIRECTION INPUT ;
    USE SIGNAL ;
    PORT
      LAYER M3 ;
        RECT  27.792 91.656 27.81 91.8 ;
    END
    PORT
      LAYER M3 ;
        RECT  27.792 90.077 27.81 91.692 ;
    END
  END data_i[41]
  PIN data_i[42]
    DIRECTION INPUT ;
    USE SIGNAL ;
    PORT
      LAYER M5 ;
        RECT  28.32 91.608 28.344 91.8 ;
    END
    PORT
      LAYER M5 ;
        RECT  28.32 90.037 28.344 91.664 ;
    END
  END data_i[42]
  PIN data_i[43]
    DIRECTION INPUT ;
    USE SIGNAL ;
    PORT
      LAYER M3 ;
        RECT  28.836 91.656 28.854 91.8 ;
    END
    PORT
      LAYER M3 ;
        RECT  28.836 90.077 28.854 91.692 ;
    END
  END data_i[43]
  PIN data_i[44]
    DIRECTION INPUT ;
    USE SIGNAL ;
    PORT
      LAYER M5 ;
        RECT  29.376 91.608 29.4 91.8 ;
    END
    PORT
      LAYER M5 ;
        RECT  29.376 90.037 29.4 91.664 ;
    END
  END data_i[44]
  PIN data_i[45]
    DIRECTION INPUT ;
    USE SIGNAL ;
    PORT
      LAYER M3 ;
        RECT  29.916 91.656 29.934 91.8 ;
    END
    PORT
      LAYER M3 ;
        RECT  29.916 90.077 29.934 91.692 ;
    END
  END data_i[45]
  PIN data_i[46]
    DIRECTION INPUT ;
    USE SIGNAL ;
    PORT
      LAYER M5 ;
        RECT  30.432 91.608 30.456 91.8 ;
    END
    PORT
      LAYER M5 ;
        RECT  30.432 89.663 30.456 91.664 ;
    END
  END data_i[46]
  PIN data_i[47]
    DIRECTION INPUT ;
    USE SIGNAL ;
    PORT
      LAYER M3 ;
        RECT  30.96 91.656 30.978 91.8 ;
    END
    PORT
      LAYER M3 ;
        RECT  30.96 90.077 30.978 91.692 ;
    END
  END data_i[47]
  PIN data_i[48]
    DIRECTION INPUT ;
    USE SIGNAL ;
    PORT
      LAYER M5 ;
        RECT  31.488 91.608 31.512 91.8 ;
    END
    PORT
      LAYER M5 ;
        RECT  31.488 90.037 31.512 91.664 ;
    END
  END data_i[48]
  PIN data_i[49]
    DIRECTION INPUT ;
    USE SIGNAL ;
    PORT
      LAYER M3 ;
        RECT  32.004 91.656 32.022 91.8 ;
    END
    PORT
      LAYER M3 ;
        RECT  32.004 90.653 32.022 91.692 ;
    END
  END data_i[49]
  PIN data_i[4]
    DIRECTION INPUT ;
    USE SIGNAL ;
    PORT
      LAYER M5 ;
        RECT  8.256 91.608 8.28 91.8 ;
    END
    PORT
      LAYER M5 ;
        RECT  8.256 89.663 8.28 91.664 ;
    END
  END data_i[4]
  PIN data_i[50]
    DIRECTION INPUT ;
    USE SIGNAL ;
    PORT
      LAYER M5 ;
        RECT  32.544 91.608 32.568 91.8 ;
    END
    PORT
      LAYER M5 ;
        RECT  32.544 90.613 32.568 91.664 ;
    END
  END data_i[50]
  PIN data_i[51]
    DIRECTION INPUT ;
    USE SIGNAL ;
    PORT
      LAYER M3 ;
        RECT  33.084 91.656 33.102 91.8 ;
    END
    PORT
      LAYER M3 ;
        RECT  33.084 90.653 33.102 91.692 ;
    END
  END data_i[51]
  PIN data_i[52]
    DIRECTION INPUT ;
    USE SIGNAL ;
    PORT
      LAYER M5 ;
        RECT  33.6 91.608 33.624 91.8 ;
    END
    PORT
      LAYER M5 ;
        RECT  33.6 90.037 33.624 91.664 ;
    END
  END data_i[52]
  PIN data_i[53]
    DIRECTION INPUT ;
    USE SIGNAL ;
    PORT
      LAYER M3 ;
        RECT  34.128 91.656 34.146 91.8 ;
    END
    PORT
      LAYER M3 ;
        RECT  34.128 90.077 34.146 91.692 ;
    END
  END data_i[53]
  PIN data_i[54]
    DIRECTION INPUT ;
    USE SIGNAL ;
    PORT
      LAYER M5 ;
        RECT  34.656 91.608 34.68 91.8 ;
    END
    PORT
      LAYER M5 ;
        RECT  34.656 89.663 34.68 91.664 ;
    END
  END data_i[54]
  PIN data_i[55]
    DIRECTION INPUT ;
    USE SIGNAL ;
    PORT
      LAYER M3 ;
        RECT  35.172 91.656 35.19 91.8 ;
    END
    PORT
      LAYER M3 ;
        RECT  35.172 89.657 35.19 91.692 ;
    END
  END data_i[55]
  PIN data_i[56]
    DIRECTION INPUT ;
    USE SIGNAL ;
    PORT
      LAYER M5 ;
        RECT  35.712 91.608 35.736 91.8 ;
    END
    PORT
      LAYER M5 ;
        RECT  35.712 89.663 35.736 91.664 ;
    END
  END data_i[56]
  PIN data_i[57]
    DIRECTION INPUT ;
    USE SIGNAL ;
    PORT
      LAYER M3 ;
        RECT  36.216 91.656 36.234 91.8 ;
    END
    PORT
      LAYER M3 ;
        RECT  36.216 90.077 36.234 91.692 ;
    END
  END data_i[57]
  PIN data_i[58]
    DIRECTION INPUT ;
    USE SIGNAL ;
    PORT
      LAYER M5 ;
        RECT  36.768 91.608 36.792 91.8 ;
    END
    PORT
      LAYER M5 ;
        RECT  36.768 90.037 36.792 91.664 ;
    END
  END data_i[58]
  PIN data_i[59]
    DIRECTION INPUT ;
    USE SIGNAL ;
    PORT
      LAYER M3 ;
        RECT  37.296 91.656 37.314 91.8 ;
    END
    PORT
      LAYER M3 ;
        RECT  37.296 90.077 37.314 91.692 ;
    END
  END data_i[59]
  PIN data_i[5]
    DIRECTION INPUT ;
    USE SIGNAL ;
    PORT
      LAYER M3 ;
        RECT  8.784 91.656 8.802 91.8 ;
    END
    PORT
      LAYER M3 ;
        RECT  8.784 90.077 8.802 91.692 ;
    END
  END data_i[5]
  PIN data_i[60]
    DIRECTION INPUT ;
    USE SIGNAL ;
    PORT
      LAYER M5 ;
        RECT  37.824 91.608 37.848 91.8 ;
    END
    PORT
      LAYER M5 ;
        RECT  37.824 90.037 37.848 91.664 ;
    END
  END data_i[60]
  PIN data_i[61]
    DIRECTION INPUT ;
    USE SIGNAL ;
    PORT
      LAYER M3 ;
        RECT  38.34 91.656 38.358 91.8 ;
    END
    PORT
      LAYER M3 ;
        RECT  38.34 90.077 38.358 91.692 ;
    END
  END data_i[61]
  PIN data_i[62]
    DIRECTION INPUT ;
    USE SIGNAL ;
    PORT
      LAYER M5 ;
        RECT  38.88 91.608 38.904 91.8 ;
    END
    PORT
      LAYER M5 ;
        RECT  38.88 90.037 38.904 91.664 ;
    END
  END data_i[62]
  PIN data_i[63]
    DIRECTION INPUT ;
    USE SIGNAL ;
    PORT
      LAYER M3 ;
        RECT  39.384 91.656 39.402 91.8 ;
    END
    PORT
      LAYER M3 ;
        RECT  39.384 90.077 39.402 91.692 ;
    END
  END data_i[63]
  PIN data_i[64]
    DIRECTION INPUT ;
    USE SIGNAL ;
    PORT
      LAYER M5 ;
        RECT  39.936 91.608 39.96 91.8 ;
    END
    PORT
      LAYER M5 ;
        RECT  39.936 89.663 39.96 91.664 ;
    END
  END data_i[64]
  PIN data_i[65]
    DIRECTION INPUT ;
    USE SIGNAL ;
    PORT
      LAYER M3 ;
        RECT  40.464 91.656 40.482 91.8 ;
    END
    PORT
      LAYER M3 ;
        RECT  40.464 90.077 40.482 91.692 ;
    END
  END data_i[65]
  PIN data_i[66]
    DIRECTION INPUT ;
    USE SIGNAL ;
    PORT
      LAYER M5 ;
        RECT  40.992 91.608 41.016 91.8 ;
    END
    PORT
      LAYER M5 ;
        RECT  40.992 90.037 41.016 91.664 ;
    END
  END data_i[66]
  PIN data_i[67]
    DIRECTION INPUT ;
    USE SIGNAL ;
    PORT
      LAYER M3 ;
        RECT  41.508 91.656 41.526 91.8 ;
    END
    PORT
      LAYER M3 ;
        RECT  41.508 90.077 41.526 91.692 ;
    END
  END data_i[67]
  PIN data_i[68]
    DIRECTION INPUT ;
    USE SIGNAL ;
    PORT
      LAYER M5 ;
        RECT  42.048 91.608 42.072 91.8 ;
    END
    PORT
      LAYER M5 ;
        RECT  42.048 90.037 42.072 91.664 ;
    END
  END data_i[68]
  PIN data_i[69]
    DIRECTION INPUT ;
    USE SIGNAL ;
    PORT
      LAYER M3 ;
        RECT  42.552 91.656 42.57 91.8 ;
    END
    PORT
      LAYER M3 ;
        RECT  42.552 90.077 42.57 91.692 ;
    END
  END data_i[69]
  PIN data_i[6]
    DIRECTION INPUT ;
    USE SIGNAL ;
    PORT
      LAYER M5 ;
        RECT  9.312 91.608 9.336 91.8 ;
    END
    PORT
      LAYER M5 ;
        RECT  9.312 90.037 9.336 91.664 ;
    END
  END data_i[6]
  PIN data_i[70]
    DIRECTION INPUT ;
    USE SIGNAL ;
    PORT
      LAYER M5 ;
        RECT  43.104 91.608 43.128 91.8 ;
    END
    PORT
      LAYER M5 ;
        RECT  43.104 90.037 43.128 91.664 ;
    END
  END data_i[70]
  PIN data_i[71]
    DIRECTION INPUT ;
    USE SIGNAL ;
    PORT
      LAYER M3 ;
        RECT  43.632 91.656 43.65 91.8 ;
    END
    PORT
      LAYER M3 ;
        RECT  43.632 90.077 43.65 91.692 ;
    END
  END data_i[71]
  PIN data_i[72]
    DIRECTION INPUT ;
    USE SIGNAL ;
    PORT
      LAYER M5 ;
        RECT  44.16 91.608 44.184 91.8 ;
    END
    PORT
      LAYER M5 ;
        RECT  44.16 90.037 44.184 91.664 ;
    END
  END data_i[72]
  PIN data_i[73]
    DIRECTION INPUT ;
    USE SIGNAL ;
    PORT
      LAYER M3 ;
        RECT  44.676 91.656 44.694 91.8 ;
    END
    PORT
      LAYER M3 ;
        RECT  44.676 90.077 44.694 91.692 ;
    END
  END data_i[73]
  PIN data_i[74]
    DIRECTION INPUT ;
    USE SIGNAL ;
    PORT
      LAYER M5 ;
        RECT  45.216 91.608 45.24 91.8 ;
    END
    PORT
      LAYER M5 ;
        RECT  45.216 89.663 45.24 91.664 ;
    END
  END data_i[74]
  PIN data_i[75]
    DIRECTION INPUT ;
    USE SIGNAL ;
    PORT
      LAYER M3 ;
        RECT  45.72 91.656 45.738 91.8 ;
    END
    PORT
      LAYER M3 ;
        RECT  45.72 90.653 45.738 91.692 ;
    END
  END data_i[75]
  PIN data_i[76]
    DIRECTION INPUT ;
    USE SIGNAL ;
    PORT
      LAYER M5 ;
        RECT  46.272 91.608 46.296 91.8 ;
    END
    PORT
      LAYER M5 ;
        RECT  46.272 90.613 46.296 91.664 ;
    END
  END data_i[76]
  PIN data_i[77]
    DIRECTION INPUT ;
    USE SIGNAL ;
    PORT
      LAYER M3 ;
        RECT  46.8 91.656 46.818 91.8 ;
    END
    PORT
      LAYER M3 ;
        RECT  46.8 91.181 46.818 91.692 ;
    END
  END data_i[77]
  PIN data_i[78]
    DIRECTION INPUT ;
    USE SIGNAL ;
    PORT
      LAYER M5 ;
        RECT  47.328 91.608 47.352 91.8 ;
    END
    PORT
      LAYER M5 ;
        RECT  47.328 91.141 47.352 91.664 ;
    END
  END data_i[78]
  PIN data_i[79]
    DIRECTION INPUT ;
    USE SIGNAL ;
    PORT
      LAYER M3 ;
        RECT  47.844 91.656 47.862 91.8 ;
    END
    PORT
      LAYER M3 ;
        RECT  47.844 91.181 47.862 91.692 ;
    END
  END data_i[79]
  PIN data_i[7]
    DIRECTION INPUT ;
    USE SIGNAL ;
    PORT
      LAYER M3 ;
        RECT  9.864 91.656 9.882 91.8 ;
    END
    PORT
      LAYER M3 ;
        RECT  9.864 90.077 9.882 91.692 ;
    END
  END data_i[7]
  PIN data_i[80]
    DIRECTION INPUT ;
    USE SIGNAL ;
    PORT
      LAYER M5 ;
        RECT  48.384 91.608 48.408 91.8 ;
    END
    PORT
      LAYER M5 ;
        RECT  48.384 90.037 48.408 91.664 ;
    END
  END data_i[80]
  PIN data_i[81]
    DIRECTION INPUT ;
    USE SIGNAL ;
    PORT
      LAYER M3 ;
        RECT  48.888 91.656 48.906 91.8 ;
    END
    PORT
      LAYER M3 ;
        RECT  48.888 90.077 48.906 91.692 ;
    END
  END data_i[81]
  PIN data_i[82]
    DIRECTION INPUT ;
    USE SIGNAL ;
    PORT
      LAYER M5 ;
        RECT  49.44 91.608 49.464 91.8 ;
    END
    PORT
      LAYER M5 ;
        RECT  49.44 89.509 49.464 91.664 ;
    END
  END data_i[82]
  PIN data_i[83]
    DIRECTION INPUT ;
    USE SIGNAL ;
    PORT
      LAYER M3 ;
        RECT  49.968 91.656 49.986 91.8 ;
    END
    PORT
      LAYER M3 ;
        RECT  49.968 90.077 49.986 91.692 ;
    END
  END data_i[83]
  PIN data_i[84]
    DIRECTION INPUT ;
    USE SIGNAL ;
    PORT
      LAYER M5 ;
        RECT  50.496 91.608 50.52 91.8 ;
    END
    PORT
      LAYER M5 ;
        RECT  50.496 90.037 50.52 91.664 ;
    END
  END data_i[84]
  PIN data_i[85]
    DIRECTION INPUT ;
    USE SIGNAL ;
    PORT
      LAYER M3 ;
        RECT  51.012 91.656 51.03 91.8 ;
    END
    PORT
      LAYER M3 ;
        RECT  51.012 90.077 51.03 91.692 ;
    END
  END data_i[85]
  PIN data_i[86]
    DIRECTION INPUT ;
    USE SIGNAL ;
    PORT
      LAYER M5 ;
        RECT  51.552 91.608 51.576 91.8 ;
    END
    PORT
      LAYER M5 ;
        RECT  51.552 89.663 51.576 91.664 ;
    END
  END data_i[86]
  PIN data_i[87]
    DIRECTION INPUT ;
    USE SIGNAL ;
    PORT
      LAYER M3 ;
        RECT  52.056 91.656 52.074 91.8 ;
    END
    PORT
      LAYER M3 ;
        RECT  52.056 89.549 52.074 91.692 ;
    END
  END data_i[87]
  PIN data_i[88]
    DIRECTION INPUT ;
    USE SIGNAL ;
    PORT
      LAYER M5 ;
        RECT  52.608 91.608 52.632 91.8 ;
    END
    PORT
      LAYER M5 ;
        RECT  52.608 89.509 52.632 91.664 ;
    END
  END data_i[88]
  PIN data_i[89]
    DIRECTION INPUT ;
    USE SIGNAL ;
    PORT
      LAYER M3 ;
        RECT  53.1 91.656 53.118 91.8 ;
    END
    PORT
      LAYER M3 ;
        RECT  53.1 90.653 53.118 91.692 ;
    END
  END data_i[89]
  PIN data_i[8]
    DIRECTION INPUT ;
    USE SIGNAL ;
    PORT
      LAYER M5 ;
        RECT  10.368 91.608 10.392 91.8 ;
    END
    PORT
      LAYER M5 ;
        RECT  10.368 90.037 10.392 91.664 ;
    END
  END data_i[8]
  PIN data_i[90]
    DIRECTION INPUT ;
    USE SIGNAL ;
    PORT
      LAYER M5 ;
        RECT  53.664 91.608 53.688 91.8 ;
    END
    PORT
      LAYER M5 ;
        RECT  53.664 90.613 53.688 91.664 ;
    END
  END data_i[90]
  PIN data_i[91]
    DIRECTION INPUT ;
    USE SIGNAL ;
    PORT
      LAYER M3 ;
        RECT  54.18 91.656 54.198 91.8 ;
    END
    PORT
      LAYER M3 ;
        RECT  54.18 90.653 54.198 91.692 ;
    END
  END data_i[91]
  PIN data_i[92]
    DIRECTION INPUT ;
    USE SIGNAL ;
    PORT
      LAYER M5 ;
        RECT  54.72 91.608 54.744 91.8 ;
    END
    PORT
      LAYER M5 ;
        RECT  54.72 90.613 54.744 91.664 ;
    END
  END data_i[92]
  PIN data_i[93]
    DIRECTION INPUT ;
    USE SIGNAL ;
    PORT
      LAYER M3 ;
        RECT  55.224 91.656 55.242 91.8 ;
    END
    PORT
      LAYER M3 ;
        RECT  55.224 90.653 55.242 91.692 ;
    END
  END data_i[93]
  PIN data_i[94]
    DIRECTION INPUT ;
    USE SIGNAL ;
    PORT
      LAYER M5 ;
        RECT  55.776 91.608 55.8 91.8 ;
    END
    PORT
      LAYER M5 ;
        RECT  55.776 90.037 55.8 91.664 ;
    END
  END data_i[94]
  PIN data_i[95]
    DIRECTION INPUT ;
    USE SIGNAL ;
    PORT
      LAYER M3 ;
        RECT  56.268 91.656 56.286 91.8 ;
    END
    PORT
      LAYER M3 ;
        RECT  56.268 90.077 56.286 91.692 ;
    END
  END data_i[95]
  PIN data_i[96]
    DIRECTION INPUT ;
    USE SIGNAL ;
    PORT
      LAYER M5 ;
        RECT  56.784 91.608 56.808 91.8 ;
    END
    PORT
      LAYER M5 ;
        RECT  56.784 89.663 56.808 91.664 ;
    END
  END data_i[96]
  PIN data_i[97]
    DIRECTION INPUT ;
    USE SIGNAL ;
    PORT
      LAYER M3 ;
        RECT  57.348 91.656 57.366 91.8 ;
    END
    PORT
      LAYER M3 ;
        RECT  57.348 90.077 57.366 91.692 ;
    END
  END data_i[97]
  PIN data_i[98]
    DIRECTION INPUT ;
    USE SIGNAL ;
    PORT
      LAYER M5 ;
        RECT  57.84 91.608 57.864 91.8 ;
    END
    PORT
      LAYER M5 ;
        RECT  57.84 90.037 57.864 91.664 ;
    END
  END data_i[98]
  PIN data_i[99]
    DIRECTION INPUT ;
    USE SIGNAL ;
    PORT
      LAYER M3 ;
        RECT  58.392 91.656 58.41 91.8 ;
    END
    PORT
      LAYER M3 ;
        RECT  58.392 90.077 58.41 91.692 ;
    END
  END data_i[99]
  PIN data_i[9]
    DIRECTION INPUT ;
    USE SIGNAL ;
    PORT
      LAYER M3 ;
        RECT  10.908 91.656 10.926 91.8 ;
    END
    PORT
      LAYER M3 ;
        RECT  10.908 90.077 10.926 91.692 ;
    END
  END data_i[9]
  PIN head_o[0]
    DIRECTION OUTPUT ;
    USE SIGNAL ;
    PORT
      LAYER M3 ;
        RECT  4.572 0 4.59 0.144 ;
    END
    PORT
      LAYER M3 ;
        RECT  4.572 0.108 4.59 0.187 ;
    END
  END head_o[0]
  PIN head_o[100]
    DIRECTION OUTPUT ;
    USE SIGNAL ;
    PORT
      LAYER M3 ;
        RECT  58.572 0 58.59 0.144 ;
    END
    PORT
      LAYER M3 ;
        RECT  58.572 0.108 58.59 0.187 ;
    END
  END head_o[100]
  PIN head_o[101]
    DIRECTION OUTPUT ;
    USE SIGNAL ;
    PORT
      LAYER M5 ;
        RECT  59.136 0 59.16 0.192 ;
    END
    PORT
      LAYER M5 ;
        RECT  59.136 0.144 59.16 0.227 ;
    END
  END head_o[101]
  PIN head_o[102]
    DIRECTION OUTPUT ;
    USE SIGNAL ;
    PORT
      LAYER M3 ;
        RECT  59.652 0 59.67 0.144 ;
    END
    PORT
      LAYER M3 ;
        RECT  59.652 0.108 59.67 0.187 ;
    END
  END head_o[102]
  PIN head_o[103]
    DIRECTION OUTPUT ;
    USE SIGNAL ;
    PORT
      LAYER M5 ;
        RECT  60.192 0 60.216 0.192 ;
    END
    PORT
      LAYER M5 ;
        RECT  60.192 0.144 60.216 1.187 ;
    END
  END head_o[103]
  PIN head_o[104]
    DIRECTION OUTPUT ;
    USE SIGNAL ;
    PORT
      LAYER M3 ;
        RECT  60.732 0 60.75 0.144 ;
    END
    PORT
      LAYER M3 ;
        RECT  60.732 0.108 60.75 1.147 ;
    END
  END head_o[104]
  PIN head_o[105]
    DIRECTION OUTPUT ;
    USE SIGNAL ;
    PORT
      LAYER M5 ;
        RECT  61.296 0 61.32 0.192 ;
    END
    PORT
      LAYER M5 ;
        RECT  61.296 0.144 61.32 1.187 ;
    END
  END head_o[105]
  PIN head_o[106]
    DIRECTION OUTPUT ;
    USE SIGNAL ;
    PORT
      LAYER M3 ;
        RECT  61.812 0 61.83 0.144 ;
    END
    PORT
      LAYER M3 ;
        RECT  61.812 0.108 61.83 0.187 ;
    END
  END head_o[106]
  PIN head_o[107]
    DIRECTION OUTPUT ;
    USE SIGNAL ;
    PORT
      LAYER M5 ;
        RECT  62.352 0 62.376 0.192 ;
    END
    PORT
      LAYER M5 ;
        RECT  62.352 0.144 62.376 0.227 ;
    END
  END head_o[107]
  PIN head_o[108]
    DIRECTION OUTPUT ;
    USE SIGNAL ;
    PORT
      LAYER M3 ;
        RECT  62.892 0 62.91 0.144 ;
    END
    PORT
      LAYER M3 ;
        RECT  62.892 0.108 62.91 0.187 ;
    END
  END head_o[108]
  PIN head_o[109]
    DIRECTION OUTPUT ;
    USE SIGNAL ;
    PORT
      LAYER M5 ;
        RECT  63.456 0 63.48 0.192 ;
    END
    PORT
      LAYER M5 ;
        RECT  63.456 0.144 63.48 1.187 ;
    END
  END head_o[109]
  PIN head_o[10]
    DIRECTION OUTPUT ;
    USE SIGNAL ;
    PORT
      LAYER M3 ;
        RECT  9.972 0 9.99 0.144 ;
    END
    PORT
      LAYER M3 ;
        RECT  9.972 0.108 9.99 1.147 ;
    END
  END head_o[10]
  PIN head_o[110]
    DIRECTION OUTPUT ;
    USE SIGNAL ;
    PORT
      LAYER M3 ;
        RECT  63.972 0 63.99 0.144 ;
    END
    PORT
      LAYER M3 ;
        RECT  63.972 0.108 63.99 0.187 ;
    END
  END head_o[110]
  PIN head_o[111]
    DIRECTION OUTPUT ;
    USE SIGNAL ;
    PORT
      LAYER M5 ;
        RECT  64.512 0 64.536 0.192 ;
    END
    PORT
      LAYER M5 ;
        RECT  64.512 0.144 64.536 0.227 ;
    END
  END head_o[111]
  PIN head_o[112]
    DIRECTION OUTPUT ;
    USE SIGNAL ;
    PORT
      LAYER M3 ;
        RECT  65.052 0 65.07 0.144 ;
    END
    PORT
      LAYER M3 ;
        RECT  65.052 0.108 65.07 0.187 ;
    END
  END head_o[112]
  PIN head_o[113]
    DIRECTION OUTPUT ;
    USE SIGNAL ;
    PORT
      LAYER M5 ;
        RECT  65.616 0 65.64 0.192 ;
    END
    PORT
      LAYER M5 ;
        RECT  65.616 0.144 65.64 0.227 ;
    END
  END head_o[113]
  PIN head_o[114]
    DIRECTION OUTPUT ;
    USE SIGNAL ;
    PORT
      LAYER M3 ;
        RECT  66.132 0 66.15 0.144 ;
    END
    PORT
      LAYER M3 ;
        RECT  66.132 0.108 66.15 0.187 ;
    END
  END head_o[114]
  PIN head_o[115]
    DIRECTION OUTPUT ;
    USE SIGNAL ;
    PORT
      LAYER M5 ;
        RECT  66.672 0 66.696 0.192 ;
    END
    PORT
      LAYER M5 ;
        RECT  66.672 0.144 66.696 1.763 ;
    END
  END head_o[115]
  PIN head_o[116]
    DIRECTION OUTPUT ;
    USE SIGNAL ;
    PORT
      LAYER M3 ;
        RECT  67.212 0 67.23 0.144 ;
    END
    PORT
      LAYER M3 ;
        RECT  67.212 0.108 67.23 1.723 ;
    END
  END head_o[116]
  PIN head_o[117]
    DIRECTION OUTPUT ;
    USE SIGNAL ;
    PORT
      LAYER M5 ;
        RECT  67.776 0 67.8 0.192 ;
    END
    PORT
      LAYER M5 ;
        RECT  67.776 0.144 67.8 1.187 ;
    END
  END head_o[117]
  PIN head_o[118]
    DIRECTION OUTPUT ;
    USE SIGNAL ;
    PORT
      LAYER M3 ;
        RECT  68.292 0 68.31 0.144 ;
    END
    PORT
      LAYER M3 ;
        RECT  68.292 0.108 68.31 0.187 ;
    END
  END head_o[118]
  PIN head_o[119]
    DIRECTION OUTPUT ;
    USE SIGNAL ;
    PORT
      LAYER M5 ;
        RECT  68.832 0 68.856 0.192 ;
    END
    PORT
      LAYER M5 ;
        RECT  68.832 0.144 68.856 0.227 ;
    END
  END head_o[119]
  PIN head_o[11]
    DIRECTION OUTPUT ;
    USE SIGNAL ;
    PORT
      LAYER M5 ;
        RECT  10.512 0 10.536 0.192 ;
    END
    PORT
      LAYER M5 ;
        RECT  10.512 0.144 10.536 1.187 ;
    END
  END head_o[11]
  PIN head_o[120]
    DIRECTION OUTPUT ;
    USE SIGNAL ;
    PORT
      LAYER M3 ;
        RECT  69.372 0 69.39 0.144 ;
    END
    PORT
      LAYER M3 ;
        RECT  69.372 0.108 69.39 0.187 ;
    END
  END head_o[120]
  PIN head_o[121]
    DIRECTION OUTPUT ;
    USE SIGNAL ;
    PORT
      LAYER M5 ;
        RECT  69.936 0 69.96 0.192 ;
    END
    PORT
      LAYER M5 ;
        RECT  69.936 0.144 69.96 1.187 ;
    END
  END head_o[121]
  PIN head_o[122]
    DIRECTION OUTPUT ;
    USE SIGNAL ;
    PORT
      LAYER M3 ;
        RECT  70.452 0 70.47 0.144 ;
    END
    PORT
      LAYER M3 ;
        RECT  70.452 0.108 70.47 1.147 ;
    END
  END head_o[122]
  PIN head_o[123]
    DIRECTION OUTPUT ;
    USE SIGNAL ;
    PORT
      LAYER M5 ;
        RECT  70.992 0 71.016 0.192 ;
    END
    PORT
      LAYER M5 ;
        RECT  70.992 0.144 71.016 0.227 ;
    END
  END head_o[123]
  PIN head_o[124]
    DIRECTION OUTPUT ;
    USE SIGNAL ;
    PORT
      LAYER M3 ;
        RECT  71.532 0 71.55 0.144 ;
    END
    PORT
      LAYER M3 ;
        RECT  71.532 0.108 71.55 0.187 ;
    END
  END head_o[124]
  PIN head_o[125]
    DIRECTION OUTPUT ;
    USE SIGNAL ;
    PORT
      LAYER M5 ;
        RECT  72.096 0 72.12 0.192 ;
    END
    PORT
      LAYER M5 ;
        RECT  72.096 0.144 72.12 1.187 ;
    END
  END head_o[125]
  PIN head_o[126]
    DIRECTION OUTPUT ;
    USE SIGNAL ;
    PORT
      LAYER M3 ;
        RECT  72.612 0 72.63 0.144 ;
    END
    PORT
      LAYER M3 ;
        RECT  72.612 0.108 72.63 0.139 ;
    END
    PORT
      LAYER M3 ;
        RECT  72.612 0.139 72.774 0.167 ;
    END
  END head_o[126]
  PIN head_o[127]
    DIRECTION OUTPUT ;
    USE SIGNAL ;
    PORT
      LAYER M5 ;
        RECT  73.152 0 73.176 0.192 ;
    END
    PORT
      LAYER M5 ;
        RECT  73.152 0.144 73.176 1.187 ;
    END
  END head_o[127]
  PIN head_o[128]
    DIRECTION OUTPUT ;
    USE SIGNAL ;
    PORT
      LAYER M3 ;
        RECT  73.692 0 73.71 0.144 ;
    END
    PORT
      LAYER M3 ;
        RECT  73.692 0.108 73.71 1.147 ;
    END
  END head_o[128]
  PIN head_o[129]
    DIRECTION OUTPUT ;
    USE SIGNAL ;
    PORT
      LAYER M5 ;
        RECT  74.256 0 74.28 0.192 ;
    END
    PORT
      LAYER M5 ;
        RECT  74.256 0.144 74.28 1.187 ;
    END
  END head_o[129]
  PIN head_o[12]
    DIRECTION OUTPUT ;
    USE SIGNAL ;
    PORT
      LAYER M3 ;
        RECT  11.052 0 11.07 0.144 ;
    END
    PORT
      LAYER M3 ;
        RECT  11.052 0.108 11.07 1.147 ;
    END
  END head_o[12]
  PIN head_o[130]
    DIRECTION OUTPUT ;
    USE SIGNAL ;
    PORT
      LAYER M3 ;
        RECT  74.772 0 74.79 0.144 ;
    END
    PORT
      LAYER M3 ;
        RECT  74.772 0.108 74.79 1.147 ;
    END
  END head_o[130]
  PIN head_o[131]
    DIRECTION OUTPUT ;
    USE SIGNAL ;
    PORT
      LAYER M5 ;
        RECT  75.312 0 75.336 0.192 ;
    END
    PORT
      LAYER M5 ;
        RECT  75.312 0.144 75.336 0.227 ;
    END
  END head_o[131]
  PIN head_o[132]
    DIRECTION OUTPUT ;
    USE SIGNAL ;
    PORT
      LAYER M3 ;
        RECT  75.852 0 75.87 0.144 ;
    END
    PORT
      LAYER M3 ;
        RECT  75.852 0.108 75.87 0.187 ;
    END
  END head_o[132]
  PIN head_o[133]
    DIRECTION OUTPUT ;
    USE SIGNAL ;
    PORT
      LAYER M5 ;
        RECT  76.416 0 76.44 0.192 ;
    END
    PORT
      LAYER M5 ;
        RECT  76.416 0.144 76.44 1.187 ;
    END
  END head_o[133]
  PIN head_o[134]
    DIRECTION OUTPUT ;
    USE SIGNAL ;
    PORT
      LAYER M3 ;
        RECT  76.932 0 76.95 0.144 ;
    END
    PORT
      LAYER M3 ;
        RECT  76.932 0.108 76.95 1.147 ;
    END
  END head_o[134]
  PIN head_o[135]
    DIRECTION OUTPUT ;
    USE SIGNAL ;
    PORT
      LAYER M5 ;
        RECT  77.472 0 77.496 0.192 ;
    END
    PORT
      LAYER M5 ;
        RECT  77.472 0.144 77.496 1.187 ;
    END
  END head_o[135]
  PIN head_o[136]
    DIRECTION OUTPUT ;
    USE SIGNAL ;
    PORT
      LAYER M3 ;
        RECT  78.012 0 78.03 0.144 ;
    END
    PORT
      LAYER M3 ;
        RECT  78.012 0.108 78.03 1.147 ;
    END
  END head_o[136]
  PIN head_o[137]
    DIRECTION OUTPUT ;
    USE SIGNAL ;
    PORT
      LAYER M5 ;
        RECT  78.576 0 78.6 0.192 ;
    END
    PORT
      LAYER M5 ;
        RECT  78.576 0.144 78.6 1.187 ;
    END
  END head_o[137]
  PIN head_o[138]
    DIRECTION OUTPUT ;
    USE SIGNAL ;
    PORT
      LAYER M3 ;
        RECT  79.092 0 79.11 0.144 ;
    END
    PORT
      LAYER M3 ;
        RECT  79.092 0.108 79.11 0.187 ;
    END
  END head_o[138]
  PIN head_o[139]
    DIRECTION OUTPUT ;
    USE SIGNAL ;
    PORT
      LAYER M5 ;
        RECT  79.632 0 79.656 0.192 ;
    END
    PORT
      LAYER M5 ;
        RECT  79.632 0.144 79.656 0.227 ;
    END
  END head_o[139]
  PIN head_o[13]
    DIRECTION OUTPUT ;
    USE SIGNAL ;
    PORT
      LAYER M5 ;
        RECT  11.616 0 11.64 0.192 ;
    END
    PORT
      LAYER M5 ;
        RECT  11.616 0.144 11.64 1.187 ;
    END
  END head_o[13]
  PIN head_o[140]
    DIRECTION OUTPUT ;
    USE SIGNAL ;
    PORT
      LAYER M3 ;
        RECT  80.172 0 80.19 0.144 ;
    END
    PORT
      LAYER M3 ;
        RECT  80.172 0.108 80.19 0.187 ;
    END
  END head_o[140]
  PIN head_o[141]
    DIRECTION OUTPUT ;
    USE SIGNAL ;
    PORT
      LAYER M5 ;
        RECT  80.736 0 80.76 0.192 ;
    END
    PORT
      LAYER M5 ;
        RECT  80.736 0.144 80.76 1.187 ;
    END
  END head_o[141]
  PIN head_o[142]
    DIRECTION OUTPUT ;
    USE SIGNAL ;
    PORT
      LAYER M3 ;
        RECT  81.252 0 81.27 0.144 ;
    END
    PORT
      LAYER M3 ;
        RECT  81.252 0.108 81.27 0.187 ;
    END
  END head_o[142]
  PIN head_o[143]
    DIRECTION OUTPUT ;
    USE SIGNAL ;
    PORT
      LAYER M5 ;
        RECT  81.792 0 81.816 0.192 ;
    END
    PORT
      LAYER M5 ;
        RECT  81.792 0.144 81.816 0.227 ;
    END
  END head_o[143]
  PIN head_o[144]
    DIRECTION OUTPUT ;
    USE SIGNAL ;
    PORT
      LAYER M3 ;
        RECT  82.332 0 82.35 0.144 ;
    END
    PORT
      LAYER M3 ;
        RECT  82.332 0.108 82.35 0.187 ;
    END
  END head_o[144]
  PIN head_o[145]
    DIRECTION OUTPUT ;
    USE SIGNAL ;
    PORT
      LAYER M5 ;
        RECT  82.896 0 82.92 0.192 ;
    END
    PORT
      LAYER M5 ;
        RECT  82.896 0.144 82.92 0.227 ;
    END
  END head_o[145]
  PIN head_o[146]
    DIRECTION OUTPUT ;
    USE SIGNAL ;
    PORT
      LAYER M3 ;
        RECT  83.412 0 83.43 0.144 ;
    END
    PORT
      LAYER M3 ;
        RECT  83.412 0.108 83.43 0.187 ;
    END
  END head_o[146]
  PIN head_o[147]
    DIRECTION OUTPUT ;
    USE SIGNAL ;
    PORT
      LAYER M5 ;
        RECT  83.952 0 83.976 0.192 ;
    END
    PORT
      LAYER M5 ;
        RECT  83.952 0.144 83.976 0.611 ;
    END
  END head_o[147]
  PIN head_o[148]
    DIRECTION OUTPUT ;
    USE SIGNAL ;
    PORT
      LAYER M3 ;
        RECT  84.492 0 84.51 0.144 ;
    END
    PORT
      LAYER M3 ;
        RECT  84.492 0.108 84.51 0.571 ;
    END
  END head_o[148]
  PIN head_o[149]
    DIRECTION OUTPUT ;
    USE SIGNAL ;
    PORT
      LAYER M5 ;
        RECT  85.056 0 85.08 0.192 ;
    END
    PORT
      LAYER M5 ;
        RECT  85.056 0.144 85.08 1.187 ;
    END
  END head_o[149]
  PIN head_o[14]
    DIRECTION OUTPUT ;
    USE SIGNAL ;
    PORT
      LAYER M3 ;
        RECT  12.132 0 12.15 0.144 ;
    END
    PORT
      LAYER M3 ;
        RECT  12.132 0.108 12.15 1.147 ;
    END
  END head_o[14]
  PIN head_o[150]
    DIRECTION OUTPUT ;
    USE SIGNAL ;
    PORT
      LAYER M3 ;
        RECT  85.572 0 85.59 0.144 ;
    END
    PORT
      LAYER M3 ;
        RECT  85.572 0.108 85.59 1.147 ;
    END
  END head_o[150]
  PIN head_o[151]
    DIRECTION OUTPUT ;
    USE SIGNAL ;
    PORT
      LAYER M5 ;
        RECT  86.112 0 86.136 0.192 ;
    END
    PORT
      LAYER M5 ;
        RECT  86.112 0.144 86.136 0.227 ;
    END
  END head_o[151]
  PIN head_o[152]
    DIRECTION OUTPUT ;
    USE SIGNAL ;
    PORT
      LAYER M3 ;
        RECT  86.652 0 86.67 0.144 ;
    END
    PORT
      LAYER M3 ;
        RECT  86.652 0.108 86.67 0.187 ;
    END
  END head_o[152]
  PIN head_o[153]
    DIRECTION OUTPUT ;
    USE SIGNAL ;
    PORT
      LAYER M5 ;
        RECT  87.216 0 87.24 0.192 ;
    END
    PORT
      LAYER M5 ;
        RECT  87.216 0.144 87.24 0.227 ;
    END
  END head_o[153]
  PIN head_o[154]
    DIRECTION OUTPUT ;
    USE SIGNAL ;
    PORT
      LAYER M3 ;
        RECT  87.732 0 87.75 0.144 ;
    END
    PORT
      LAYER M3 ;
        RECT  87.732 0.108 87.75 0.187 ;
    END
  END head_o[154]
  PIN head_o[155]
    DIRECTION OUTPUT ;
    USE SIGNAL ;
    PORT
      LAYER M5 ;
        RECT  88.272 0 88.296 0.192 ;
    END
    PORT
      LAYER M5 ;
        RECT  88.272 0.144 88.296 1.187 ;
    END
  END head_o[155]
  PIN head_o[156]
    DIRECTION OUTPUT ;
    USE SIGNAL ;
    PORT
      LAYER M3 ;
        RECT  88.812 0 88.83 0.144 ;
    END
    PORT
      LAYER M3 ;
        RECT  88.812 0.108 88.83 0.139 ;
    END
    PORT
      LAYER M3 ;
        RECT  88.74 0.139 88.83 0.187 ;
    END
  END head_o[156]
  PIN head_o[157]
    DIRECTION OUTPUT ;
    USE SIGNAL ;
    PORT
      LAYER M5 ;
        RECT  89.376 0 89.4 0.192 ;
    END
    PORT
      LAYER M5 ;
        RECT  89.376 0.144 89.4 0.227 ;
    END
  END head_o[157]
  PIN head_o[158]
    DIRECTION OUTPUT ;
    USE SIGNAL ;
    PORT
      LAYER M3 ;
        RECT  89.892 0 89.91 0.144 ;
    END
    PORT
      LAYER M3 ;
        RECT  89.892 0.108 89.91 0.187 ;
    END
  END head_o[158]
  PIN head_o[159]
    DIRECTION OUTPUT ;
    USE SIGNAL ;
    PORT
      LAYER M5 ;
        RECT  90.432 0 90.456 0.192 ;
    END
    PORT
      LAYER M5 ;
        RECT  90.432 0.144 90.456 1.187 ;
    END
  END head_o[159]
  PIN head_o[15]
    DIRECTION OUTPUT ;
    USE SIGNAL ;
    PORT
      LAYER M5 ;
        RECT  12.672 0 12.696 0.192 ;
    END
    PORT
      LAYER M5 ;
        RECT  12.672 0.144 12.696 0.227 ;
    END
  END head_o[15]
  PIN head_o[160]
    DIRECTION OUTPUT ;
    USE SIGNAL ;
    PORT
      LAYER M3 ;
        RECT  90.972 0 90.99 0.144 ;
    END
    PORT
      LAYER M3 ;
        RECT  90.972 0.108 90.99 0.187 ;
    END
  END head_o[160]
  PIN head_o[161]
    DIRECTION OUTPUT ;
    USE SIGNAL ;
    PORT
      LAYER M5 ;
        RECT  91.536 0 91.56 0.192 ;
    END
    PORT
      LAYER M5 ;
        RECT  91.536 0.144 91.56 0.227 ;
    END
  END head_o[161]
  PIN head_o[162]
    DIRECTION OUTPUT ;
    USE SIGNAL ;
    PORT
      LAYER M3 ;
        RECT  92.052 0 92.07 0.144 ;
    END
    PORT
      LAYER M3 ;
        RECT  92.052 0.108 92.07 0.187 ;
    END
  END head_o[162]
  PIN head_o[163]
    DIRECTION OUTPUT ;
    USE SIGNAL ;
    PORT
      LAYER M5 ;
        RECT  92.592 0 92.616 0.192 ;
    END
    PORT
      LAYER M5 ;
        RECT  92.592 0.144 92.616 0.227 ;
    END
  END head_o[163]
  PIN head_o[164]
    DIRECTION OUTPUT ;
    USE SIGNAL ;
    PORT
      LAYER M3 ;
        RECT  93.132 0 93.15 0.144 ;
    END
    PORT
      LAYER M3 ;
        RECT  93.132 0.108 93.15 0.187 ;
    END
  END head_o[164]
  PIN head_o[165]
    DIRECTION OUTPUT ;
    USE SIGNAL ;
    PORT
      LAYER M5 ;
        RECT  93.696 0 93.72 0.192 ;
    END
    PORT
      LAYER M5 ;
        RECT  93.696 0.144 93.72 0.227 ;
    END
  END head_o[165]
  PIN head_o[166]
    DIRECTION OUTPUT ;
    USE SIGNAL ;
    PORT
      LAYER M3 ;
        RECT  94.212 0 94.23 0.144 ;
    END
    PORT
      LAYER M3 ;
        RECT  94.212 0.108 94.23 0.187 ;
    END
  END head_o[166]
  PIN head_o[167]
    DIRECTION OUTPUT ;
    USE SIGNAL ;
    PORT
      LAYER M5 ;
        RECT  94.752 0 94.776 0.192 ;
    END
    PORT
      LAYER M5 ;
        RECT  94.752 0.144 94.776 0.227 ;
    END
  END head_o[167]
  PIN head_o[168]
    DIRECTION OUTPUT ;
    USE SIGNAL ;
    PORT
      LAYER M3 ;
        RECT  95.292 0 95.31 0.144 ;
    END
    PORT
      LAYER M3 ;
        RECT  95.292 0.108 95.31 0.187 ;
    END
  END head_o[168]
  PIN head_o[169]
    DIRECTION OUTPUT ;
    USE SIGNAL ;
    PORT
      LAYER M5 ;
        RECT  95.856 0 95.88 0.192 ;
    END
    PORT
      LAYER M5 ;
        RECT  95.856 0.144 95.88 0.227 ;
    END
  END head_o[169]
  PIN head_o[16]
    DIRECTION OUTPUT ;
    USE SIGNAL ;
    PORT
      LAYER M3 ;
        RECT  13.212 0 13.23 0.144 ;
    END
    PORT
      LAYER M3 ;
        RECT  13.212 0.108 13.23 0.187 ;
    END
  END head_o[16]
  PIN head_o[170]
    DIRECTION OUTPUT ;
    USE SIGNAL ;
    PORT
      LAYER M3 ;
        RECT  96.372 0 96.39 0.144 ;
    END
    PORT
      LAYER M3 ;
        RECT  96.372 0.108 96.39 0.187 ;
    END
  END head_o[170]
  PIN head_o[171]
    DIRECTION OUTPUT ;
    USE SIGNAL ;
    PORT
      LAYER M5 ;
        RECT  96.912 0 96.936 0.192 ;
    END
    PORT
      LAYER M5 ;
        RECT  96.912 0.144 96.936 0.227 ;
    END
  END head_o[171]
  PIN head_o[172]
    DIRECTION OUTPUT ;
    USE SIGNAL ;
    PORT
      LAYER M3 ;
        RECT  97.452 0 97.47 0.144 ;
    END
    PORT
      LAYER M3 ;
        RECT  97.452 0.108 97.47 0.187 ;
    END
  END head_o[172]
  PIN head_o[173]
    DIRECTION OUTPUT ;
    USE SIGNAL ;
    PORT
      LAYER M5 ;
        RECT  98.016 0 98.04 0.192 ;
    END
    PORT
      LAYER M5 ;
        RECT  98.016 0.144 98.04 1.187 ;
    END
  END head_o[173]
  PIN head_o[174]
    DIRECTION OUTPUT ;
    USE SIGNAL ;
    PORT
      LAYER M3 ;
        RECT  98.532 0 98.55 0.144 ;
    END
    PORT
      LAYER M3 ;
        RECT  98.532 0.108 98.55 1.147 ;
    END
  END head_o[174]
  PIN head_o[175]
    DIRECTION OUTPUT ;
    USE SIGNAL ;
    PORT
      LAYER M5 ;
        RECT  99.072 0 99.096 0.192 ;
    END
    PORT
      LAYER M5 ;
        RECT  99.072 0.144 99.096 1.763 ;
    END
  END head_o[175]
  PIN head_o[176]
    DIRECTION OUTPUT ;
    USE SIGNAL ;
    PORT
      LAYER M3 ;
        RECT  99.612 0 99.63 0.144 ;
    END
    PORT
      LAYER M3 ;
        RECT  99.612 0.108 99.63 0.139 ;
    END
    PORT
      LAYER M3 ;
        RECT  99.54 0.139 99.63 0.167 ;
    END
  END head_o[176]
  PIN head_o[177]
    DIRECTION OUTPUT ;
    USE SIGNAL ;
    PORT
      LAYER M5 ;
        RECT  100.176 0 100.2 0.192 ;
    END
    PORT
      LAYER M5 ;
        RECT  100.176 0.144 100.2 1.187 ;
    END
  END head_o[177]
  PIN head_o[178]
    DIRECTION OUTPUT ;
    USE SIGNAL ;
    PORT
      LAYER M3 ;
        RECT  100.692 0 100.71 0.144 ;
    END
    PORT
      LAYER M3 ;
        RECT  100.692 0.108 100.71 1.147 ;
    END
  END head_o[178]
  PIN head_o[179]
    DIRECTION OUTPUT ;
    USE SIGNAL ;
    PORT
      LAYER M5 ;
        RECT  101.232 0 101.256 0.192 ;
    END
    PORT
      LAYER M5 ;
        RECT  101.232 0.144 101.256 1.187 ;
    END
  END head_o[179]
  PIN head_o[17]
    DIRECTION OUTPUT ;
    USE SIGNAL ;
    PORT
      LAYER M5 ;
        RECT  13.776 0 13.8 0.192 ;
    END
    PORT
      LAYER M5 ;
        RECT  13.776 0.144 13.8 0.227 ;
    END
  END head_o[17]
  PIN head_o[180]
    DIRECTION OUTPUT ;
    USE SIGNAL ;
    PORT
      LAYER M3 ;
        RECT  101.772 0 101.79 0.144 ;
    END
    PORT
      LAYER M3 ;
        RECT  101.772 0.108 101.79 0.187 ;
    END
  END head_o[180]
  PIN head_o[181]
    DIRECTION OUTPUT ;
    USE SIGNAL ;
    PORT
      LAYER M5 ;
        RECT  102.336 0 102.36 0.192 ;
    END
    PORT
      LAYER M5 ;
        RECT  102.336 0.144 102.36 0.227 ;
    END
  END head_o[181]
  PIN head_o[182]
    DIRECTION OUTPUT ;
    USE SIGNAL ;
    PORT
      LAYER M3 ;
        RECT  102.852 0 102.87 0.144 ;
    END
    PORT
      LAYER M3 ;
        RECT  102.852 0.108 102.87 0.187 ;
    END
  END head_o[182]
  PIN head_o[183]
    DIRECTION OUTPUT ;
    USE SIGNAL ;
    PORT
      LAYER M5 ;
        RECT  103.392 0 103.416 0.192 ;
    END
    PORT
      LAYER M5 ;
        RECT  103.392 0.144 103.416 0.227 ;
    END
  END head_o[183]
  PIN head_o[184]
    DIRECTION OUTPUT ;
    USE SIGNAL ;
    PORT
      LAYER M3 ;
        RECT  103.932 0 103.95 0.144 ;
    END
    PORT
      LAYER M3 ;
        RECT  103.932 0.108 103.95 0.187 ;
    END
  END head_o[184]
  PIN head_o[185]
    DIRECTION OUTPUT ;
    USE SIGNAL ;
    PORT
      LAYER M5 ;
        RECT  104.496 0 104.52 0.192 ;
    END
    PORT
      LAYER M5 ;
        RECT  104.496 0.144 104.52 0.227 ;
    END
  END head_o[185]
  PIN head_o[186]
    DIRECTION OUTPUT ;
    USE SIGNAL ;
    PORT
      LAYER M3 ;
        RECT  105.012 0 105.03 0.144 ;
    END
    PORT
      LAYER M3 ;
        RECT  105.012 0.108 105.03 0.187 ;
    END
  END head_o[186]
  PIN head_o[187]
    DIRECTION OUTPUT ;
    USE SIGNAL ;
    PORT
      LAYER M5 ;
        RECT  105.552 0 105.576 0.192 ;
    END
    PORT
      LAYER M5 ;
        RECT  105.552 0.144 105.576 0.227 ;
    END
  END head_o[187]
  PIN head_o[188]
    DIRECTION OUTPUT ;
    USE SIGNAL ;
    PORT
      LAYER M3 ;
        RECT  106.092 0 106.11 0.144 ;
    END
    PORT
      LAYER M3 ;
        RECT  106.092 0.108 106.11 0.187 ;
    END
  END head_o[188]
  PIN head_o[189]
    DIRECTION OUTPUT ;
    USE SIGNAL ;
    PORT
      LAYER M5 ;
        RECT  106.656 0 106.68 0.192 ;
    END
    PORT
      LAYER M5 ;
        RECT  106.656 0.144 106.68 0.227 ;
    END
  END head_o[189]
  PIN head_o[18]
    DIRECTION OUTPUT ;
    USE SIGNAL ;
    PORT
      LAYER M3 ;
        RECT  14.292 0 14.31 0.144 ;
    END
    PORT
      LAYER M3 ;
        RECT  14.292 0.108 14.31 0.187 ;
    END
  END head_o[18]
  PIN head_o[190]
    DIRECTION OUTPUT ;
    USE SIGNAL ;
    PORT
      LAYER M3 ;
        RECT  107.172 0 107.19 0.144 ;
    END
    PORT
      LAYER M3 ;
        RECT  107.172 0.108 107.19 0.187 ;
    END
  END head_o[190]
  PIN head_o[191]
    DIRECTION OUTPUT ;
    USE SIGNAL ;
    PORT
      LAYER M5 ;
        RECT  107.712 0 107.736 0.192 ;
    END
    PORT
      LAYER M5 ;
        RECT  107.712 0.144 107.736 1.763 ;
    END
  END head_o[191]
  PIN head_o[192]
    DIRECTION OUTPUT ;
    USE SIGNAL ;
    PORT
      LAYER M3 ;
        RECT  108.252 0 108.27 0.144 ;
    END
    PORT
      LAYER M3 ;
        RECT  108.252 0.108 108.27 1.723 ;
    END
  END head_o[192]
  PIN head_o[193]
    DIRECTION OUTPUT ;
    USE SIGNAL ;
    PORT
      LAYER M5 ;
        RECT  108.816 0 108.84 0.192 ;
    END
    PORT
      LAYER M5 ;
        RECT  108.816 0.144 108.84 1.187 ;
    END
  END head_o[193]
  PIN head_o[194]
    DIRECTION OUTPUT ;
    USE SIGNAL ;
    PORT
      LAYER M3 ;
        RECT  109.332 0 109.35 0.144 ;
    END
    PORT
      LAYER M3 ;
        RECT  109.332 0.108 109.35 1.147 ;
    END
  END head_o[194]
  PIN head_o[195]
    DIRECTION OUTPUT ;
    USE SIGNAL ;
    PORT
      LAYER M5 ;
        RECT  109.872 0 109.896 0.192 ;
    END
    PORT
      LAYER M5 ;
        RECT  109.872 0.144 109.896 1.187 ;
    END
  END head_o[195]
  PIN head_o[196]
    DIRECTION OUTPUT ;
    USE SIGNAL ;
    PORT
      LAYER M3 ;
        RECT  110.412 0 110.43 0.144 ;
    END
    PORT
      LAYER M3 ;
        RECT  110.412 0.108 110.43 0.571 ;
    END
  END head_o[196]
  PIN head_o[197]
    DIRECTION OUTPUT ;
    USE SIGNAL ;
    PORT
      LAYER M5 ;
        RECT  110.976 0 111 0.192 ;
    END
    PORT
      LAYER M5 ;
        RECT  110.976 0.144 111 0.611 ;
    END
  END head_o[197]
  PIN head_o[198]
    DIRECTION OUTPUT ;
    USE SIGNAL ;
    PORT
      LAYER M3 ;
        RECT  111.492 0 111.51 0.144 ;
    END
    PORT
      LAYER M3 ;
        RECT  111.492 0.108 111.51 0.571 ;
    END
  END head_o[198]
  PIN head_o[199]
    DIRECTION OUTPUT ;
    USE SIGNAL ;
    PORT
      LAYER M5 ;
        RECT  112.032 0 112.056 0.192 ;
    END
    PORT
      LAYER M5 ;
        RECT  112.032 0.144 112.056 1.187 ;
    END
  END head_o[199]
  PIN head_o[19]
    DIRECTION OUTPUT ;
    USE SIGNAL ;
    PORT
      LAYER M5 ;
        RECT  14.832 0 14.856 0.192 ;
    END
    PORT
      LAYER M5 ;
        RECT  14.832 0.144 14.856 0.227 ;
    END
  END head_o[19]
  PIN head_o[1]
    DIRECTION OUTPUT ;
    USE SIGNAL ;
    PORT
      LAYER M5 ;
        RECT  5.136 0 5.16 0.192 ;
    END
    PORT
      LAYER M5 ;
        RECT  5.136 0.144 5.16 0.227 ;
    END
  END head_o[1]
  PIN head_o[200]
    DIRECTION OUTPUT ;
    USE SIGNAL ;
    PORT
      LAYER M3 ;
        RECT  112.572 0 112.59 0.144 ;
    END
    PORT
      LAYER M3 ;
        RECT  112.572 0.108 112.59 0.187 ;
    END
  END head_o[200]
  PIN head_o[201]
    DIRECTION OUTPUT ;
    USE SIGNAL ;
    PORT
      LAYER M5 ;
        RECT  113.136 0 113.16 0.192 ;
    END
    PORT
      LAYER M5 ;
        RECT  113.136 0.144 113.16 0.227 ;
    END
  END head_o[201]
  PIN head_o[202]
    DIRECTION OUTPUT ;
    USE SIGNAL ;
    PORT
      LAYER M3 ;
        RECT  113.652 0 113.67 0.144 ;
    END
    PORT
      LAYER M3 ;
        RECT  113.652 0.108 113.67 0.187 ;
    END
  END head_o[202]
  PIN head_o[203]
    DIRECTION OUTPUT ;
    USE SIGNAL ;
    PORT
      LAYER M5 ;
        RECT  114.192 0 114.216 0.192 ;
    END
    PORT
      LAYER M5 ;
        RECT  114.192 0.144 114.216 0.227 ;
    END
  END head_o[203]
  PIN head_o[204]
    DIRECTION OUTPUT ;
    USE SIGNAL ;
    PORT
      LAYER M3 ;
        RECT  114.732 0 114.75 0.144 ;
    END
    PORT
      LAYER M3 ;
        RECT  114.732 0.108 114.75 0.187 ;
    END
  END head_o[204]
  PIN head_o[205]
    DIRECTION OUTPUT ;
    USE SIGNAL ;
    PORT
      LAYER M5 ;
        RECT  115.296 0 115.32 0.192 ;
    END
    PORT
      LAYER M5 ;
        RECT  115.296 0.144 115.32 0.227 ;
    END
  END head_o[205]
  PIN head_o[206]
    DIRECTION OUTPUT ;
    USE SIGNAL ;
    PORT
      LAYER M3 ;
        RECT  115.812 0 115.83 0.144 ;
    END
    PORT
      LAYER M3 ;
        RECT  115.812 0.108 115.83 0.187 ;
    END
  END head_o[206]
  PIN head_o[207]
    DIRECTION OUTPUT ;
    USE SIGNAL ;
    PORT
      LAYER M5 ;
        RECT  116.352 0 116.376 0.192 ;
    END
    PORT
      LAYER M5 ;
        RECT  116.352 0.144 116.376 0.611 ;
    END
  END head_o[207]
  PIN head_o[208]
    DIRECTION OUTPUT ;
    USE SIGNAL ;
    PORT
      LAYER M3 ;
        RECT  116.892 0 116.91 0.144 ;
    END
    PORT
      LAYER M3 ;
        RECT  116.892 0.108 116.91 0.571 ;
    END
  END head_o[208]
  PIN head_o[209]
    DIRECTION OUTPUT ;
    USE SIGNAL ;
    PORT
      LAYER M5 ;
        RECT  117.456 0 117.48 0.192 ;
    END
    PORT
      LAYER M5 ;
        RECT  117.456 0.144 117.48 0.323 ;
    END
  END head_o[209]
  PIN head_o[20]
    DIRECTION OUTPUT ;
    USE SIGNAL ;
    PORT
      LAYER M3 ;
        RECT  15.372 0 15.39 0.144 ;
    END
    PORT
      LAYER M3 ;
        RECT  15.372 0.108 15.39 0.187 ;
    END
  END head_o[20]
  PIN head_o[210]
    DIRECTION OUTPUT ;
    USE SIGNAL ;
    PORT
      LAYER M3 ;
        RECT  117.972 0 117.99 0.144 ;
    END
    PORT
      LAYER M3 ;
        RECT  117.972 0.108 117.99 0.139 ;
    END
    PORT
      LAYER M3 ;
        RECT  117.9 0.139 117.99 2.101 ;
    END
  END head_o[210]
  PIN head_o[211]
    DIRECTION OUTPUT ;
    USE SIGNAL ;
    PORT
      LAYER M5 ;
        RECT  118.512 0 118.536 0.192 ;
    END
    PORT
      LAYER M5 ;
        RECT  118.512 0.144 118.536 1.763 ;
    END
  END head_o[211]
  PIN head_o[212]
    DIRECTION OUTPUT ;
    USE SIGNAL ;
    PORT
      LAYER M3 ;
        RECT  119.052 0 119.07 0.144 ;
    END
    PORT
      LAYER M3 ;
        RECT  119.052 0.108 119.07 1.723 ;
    END
  END head_o[212]
  PIN head_o[213]
    DIRECTION OUTPUT ;
    USE SIGNAL ;
    PORT
      LAYER M5 ;
        RECT  119.616 0 119.64 0.192 ;
    END
    PORT
      LAYER M5 ;
        RECT  119.616 0.144 119.64 1.187 ;
    END
  END head_o[213]
  PIN head_o[214]
    DIRECTION OUTPUT ;
    USE SIGNAL ;
    PORT
      LAYER M3 ;
        RECT  120.132 0 120.15 0.144 ;
    END
    PORT
      LAYER M3 ;
        RECT  120.132 0.108 120.15 1.147 ;
    END
  END head_o[214]
  PIN head_o[215]
    DIRECTION OUTPUT ;
    USE SIGNAL ;
    PORT
      LAYER M5 ;
        RECT  120.672 0 120.696 0.192 ;
    END
    PORT
      LAYER M5 ;
        RECT  120.672 0.144 120.696 1.187 ;
    END
  END head_o[215]
  PIN head_o[216]
    DIRECTION OUTPUT ;
    USE SIGNAL ;
    PORT
      LAYER M3 ;
        RECT  121.212 0 121.23 0.144 ;
    END
    PORT
      LAYER M3 ;
        RECT  121.212 0.108 121.23 0.187 ;
    END
  END head_o[216]
  PIN head_o[217]
    DIRECTION OUTPUT ;
    USE SIGNAL ;
    PORT
      LAYER M5 ;
        RECT  121.776 0 121.8 0.192 ;
    END
    PORT
      LAYER M5 ;
        RECT  121.776 0.144 121.8 0.227 ;
    END
  END head_o[217]
  PIN head_o[218]
    DIRECTION OUTPUT ;
    USE SIGNAL ;
    PORT
      LAYER M3 ;
        RECT  122.292 0 122.31 0.144 ;
    END
    PORT
      LAYER M3 ;
        RECT  122.292 0.108 122.31 0.187 ;
    END
  END head_o[218]
  PIN head_o[219]
    DIRECTION OUTPUT ;
    USE SIGNAL ;
    PORT
      LAYER M5 ;
        RECT  122.832 0 122.856 0.192 ;
    END
    PORT
      LAYER M5 ;
        RECT  122.832 0.144 122.856 1.187 ;
    END
  END head_o[219]
  PIN head_o[21]
    DIRECTION OUTPUT ;
    USE SIGNAL ;
    PORT
      LAYER M5 ;
        RECT  15.936 0 15.96 0.192 ;
    END
    PORT
      LAYER M5 ;
        RECT  15.936 0.144 15.96 1.187 ;
    END
  END head_o[21]
  PIN head_o[220]
    DIRECTION OUTPUT ;
    USE SIGNAL ;
    PORT
      LAYER M3 ;
        RECT  123.372 0 123.39 0.144 ;
    END
    PORT
      LAYER M3 ;
        RECT  123.372 0.108 123.39 1.147 ;
    END
  END head_o[220]
  PIN head_o[221]
    DIRECTION OUTPUT ;
    USE SIGNAL ;
    PORT
      LAYER M5 ;
        RECT  123.936 0 123.96 0.192 ;
    END
    PORT
      LAYER M5 ;
        RECT  123.936 0.144 123.96 1.187 ;
    END
  END head_o[221]
  PIN head_o[222]
    DIRECTION OUTPUT ;
    USE SIGNAL ;
    PORT
      LAYER M3 ;
        RECT  124.452 0 124.47 0.144 ;
    END
    PORT
      LAYER M3 ;
        RECT  124.452 0.108 124.47 0.139 ;
    END
    PORT
      LAYER M3 ;
        RECT  124.452 0.139 124.542 0.167 ;
    END
  END head_o[222]
  PIN head_o[223]
    DIRECTION OUTPUT ;
    USE SIGNAL ;
    PORT
      LAYER M5 ;
        RECT  124.992 0 125.016 0.192 ;
    END
    PORT
      LAYER M5 ;
        RECT  124.992 0.144 125.016 0.611 ;
    END
  END head_o[223]
  PIN head_o[224]
    DIRECTION OUTPUT ;
    USE SIGNAL ;
    PORT
      LAYER M3 ;
        RECT  125.532 0 125.55 0.144 ;
    END
    PORT
      LAYER M3 ;
        RECT  125.532 0.108 125.55 0.187 ;
    END
  END head_o[224]
  PIN head_o[225]
    DIRECTION OUTPUT ;
    USE SIGNAL ;
    PORT
      LAYER M5 ;
        RECT  126.096 0 126.12 0.192 ;
    END
    PORT
      LAYER M5 ;
        RECT  126.096 0.144 126.12 0.227 ;
    END
  END head_o[225]
  PIN head_o[226]
    DIRECTION OUTPUT ;
    USE SIGNAL ;
    PORT
      LAYER M3 ;
        RECT  126.612 0 126.63 0.144 ;
    END
    PORT
      LAYER M3 ;
        RECT  126.612 0.108 126.63 0.139 ;
    END
    PORT
      LAYER M3 ;
        RECT  126.612 0.139 126.774 0.187 ;
    END
  END head_o[226]
  PIN head_o[227]
    DIRECTION OUTPUT ;
    USE SIGNAL ;
    PORT
      LAYER M5 ;
        RECT  127.152 0 127.176 0.192 ;
    END
    PORT
      LAYER M5 ;
        RECT  127.152 0.144 127.176 0.227 ;
    END
  END head_o[227]
  PIN head_o[228]
    DIRECTION OUTPUT ;
    USE SIGNAL ;
    PORT
      LAYER M3 ;
        RECT  127.692 0 127.71 0.144 ;
    END
    PORT
      LAYER M3 ;
        RECT  127.692 0.108 127.71 0.187 ;
    END
  END head_o[228]
  PIN head_o[229]
    DIRECTION OUTPUT ;
    USE SIGNAL ;
    PORT
      LAYER M5 ;
        RECT  128.256 0 128.28 0.192 ;
    END
    PORT
      LAYER M5 ;
        RECT  128.256 0.144 128.28 0.227 ;
    END
  END head_o[229]
  PIN head_o[22]
    DIRECTION OUTPUT ;
    USE SIGNAL ;
    PORT
      LAYER M3 ;
        RECT  16.452 0 16.47 0.144 ;
    END
    PORT
      LAYER M3 ;
        RECT  16.452 0.108 16.47 1.147 ;
    END
  END head_o[22]
  PIN head_o[230]
    DIRECTION OUTPUT ;
    USE SIGNAL ;
    PORT
      LAYER M3 ;
        RECT  128.772 0 128.79 0.144 ;
    END
    PORT
      LAYER M3 ;
        RECT  128.772 0.108 128.79 0.187 ;
    END
  END head_o[230]
  PIN head_o[231]
    DIRECTION OUTPUT ;
    USE SIGNAL ;
    PORT
      LAYER M5 ;
        RECT  129.312 0 129.336 0.192 ;
    END
    PORT
      LAYER M5 ;
        RECT  129.312 0.144 129.336 1.187 ;
    END
  END head_o[231]
  PIN head_o[232]
    DIRECTION OUTPUT ;
    USE SIGNAL ;
    PORT
      LAYER M3 ;
        RECT  129.852 0 129.87 0.144 ;
    END
    PORT
      LAYER M3 ;
        RECT  129.852 0.108 129.87 1.147 ;
    END
  END head_o[232]
  PIN head_o[233]
    DIRECTION OUTPUT ;
    USE SIGNAL ;
    PORT
      LAYER M5 ;
        RECT  130.416 0 130.44 0.192 ;
    END
    PORT
      LAYER M5 ;
        RECT  130.416 0.144 130.44 1.187 ;
    END
  END head_o[233]
  PIN head_o[234]
    DIRECTION OUTPUT ;
    USE SIGNAL ;
    PORT
      LAYER M3 ;
        RECT  130.932 0 130.95 0.144 ;
    END
    PORT
      LAYER M3 ;
        RECT  130.932 0.108 130.95 0.571 ;
    END
  END head_o[234]
  PIN head_o[235]
    DIRECTION OUTPUT ;
    USE SIGNAL ;
    PORT
      LAYER M5 ;
        RECT  131.472 0 131.496 0.192 ;
    END
    PORT
      LAYER M5 ;
        RECT  131.472 0.144 131.496 0.611 ;
    END
  END head_o[235]
  PIN head_o[236]
    DIRECTION OUTPUT ;
    USE SIGNAL ;
    PORT
      LAYER M3 ;
        RECT  132.012 0 132.03 0.144 ;
    END
    PORT
      LAYER M3 ;
        RECT  132.012 0.108 132.03 0.571 ;
    END
  END head_o[236]
  PIN head_o[237]
    DIRECTION OUTPUT ;
    USE SIGNAL ;
    PORT
      LAYER M5 ;
        RECT  132.576 0 132.6 0.192 ;
    END
    PORT
      LAYER M5 ;
        RECT  132.576 0.144 132.6 1.187 ;
    END
  END head_o[237]
  PIN head_o[238]
    DIRECTION OUTPUT ;
    USE SIGNAL ;
    PORT
      LAYER M3 ;
        RECT  133.092 0 133.11 0.144 ;
    END
    PORT
      LAYER M3 ;
        RECT  133.092 0.108 133.11 1.147 ;
    END
  END head_o[238]
  PIN head_o[239]
    DIRECTION OUTPUT ;
    USE SIGNAL ;
    PORT
      LAYER M5 ;
        RECT  133.632 0 133.656 0.192 ;
    END
    PORT
      LAYER M5 ;
        RECT  133.632 0.144 133.656 1.187 ;
    END
  END head_o[239]
  PIN head_o[23]
    DIRECTION OUTPUT ;
    USE SIGNAL ;
    PORT
      LAYER M5 ;
        RECT  16.992 0 17.016 0.192 ;
    END
    PORT
      LAYER M5 ;
        RECT  16.992 0.144 17.016 1.187 ;
    END
  END head_o[23]
  PIN head_o[240]
    DIRECTION OUTPUT ;
    USE SIGNAL ;
    PORT
      LAYER M3 ;
        RECT  134.172 0 134.19 0.144 ;
    END
    PORT
      LAYER M3 ;
        RECT  134.172 0.108 134.19 1.147 ;
    END
  END head_o[240]
  PIN head_o[241]
    DIRECTION OUTPUT ;
    USE SIGNAL ;
    PORT
      LAYER M5 ;
        RECT  134.736 0 134.76 0.192 ;
    END
    PORT
      LAYER M5 ;
        RECT  134.736 0.144 134.76 0.227 ;
    END
  END head_o[241]
  PIN head_o[242]
    DIRECTION OUTPUT ;
    USE SIGNAL ;
    PORT
      LAYER M3 ;
        RECT  135.252 0 135.27 0.144 ;
    END
    PORT
      LAYER M3 ;
        RECT  135.252 0.108 135.27 0.187 ;
    END
  END head_o[242]
  PIN head_o[243]
    DIRECTION OUTPUT ;
    USE SIGNAL ;
    PORT
      LAYER M5 ;
        RECT  135.792 0 135.816 0.192 ;
    END
    PORT
      LAYER M5 ;
        RECT  135.792 0.144 135.816 0.227 ;
    END
  END head_o[243]
  PIN head_o[244]
    DIRECTION OUTPUT ;
    USE SIGNAL ;
    PORT
      LAYER M3 ;
        RECT  136.332 0 136.35 0.144 ;
    END
    PORT
      LAYER M3 ;
        RECT  136.332 0.108 136.35 0.187 ;
    END
  END head_o[244]
  PIN head_o[245]
    DIRECTION OUTPUT ;
    USE SIGNAL ;
    PORT
      LAYER M5 ;
        RECT  136.896 0 136.92 0.192 ;
    END
    PORT
      LAYER M5 ;
        RECT  136.896 0.144 136.92 0.227 ;
    END
  END head_o[245]
  PIN head_o[246]
    DIRECTION OUTPUT ;
    USE SIGNAL ;
    PORT
      LAYER M3 ;
        RECT  137.412 0 137.43 0.144 ;
    END
    PORT
      LAYER M3 ;
        RECT  137.412 0.108 137.43 0.187 ;
    END
  END head_o[246]
  PIN head_o[247]
    DIRECTION OUTPUT ;
    USE SIGNAL ;
    PORT
      LAYER M5 ;
        RECT  137.952 0 137.976 0.192 ;
    END
    PORT
      LAYER M5 ;
        RECT  137.952 0.144 137.976 0.227 ;
    END
  END head_o[247]
  PIN head_o[248]
    DIRECTION OUTPUT ;
    USE SIGNAL ;
    PORT
      LAYER M3 ;
        RECT  138.492 0 138.51 0.144 ;
    END
    PORT
      LAYER M3 ;
        RECT  138.492 0.108 138.51 0.187 ;
    END
  END head_o[248]
  PIN head_o[249]
    DIRECTION OUTPUT ;
    USE SIGNAL ;
    PORT
      LAYER M5 ;
        RECT  139.056 0 139.08 0.192 ;
    END
    PORT
      LAYER M5 ;
        RECT  139.056 0.144 139.08 1.187 ;
    END
  END head_o[249]
  PIN head_o[24]
    DIRECTION OUTPUT ;
    USE SIGNAL ;
    PORT
      LAYER M3 ;
        RECT  17.532 0 17.55 0.144 ;
    END
    PORT
      LAYER M3 ;
        RECT  17.532 0.108 17.55 0.187 ;
    END
  END head_o[24]
  PIN head_o[250]
    DIRECTION OUTPUT ;
    USE SIGNAL ;
    PORT
      LAYER M3 ;
        RECT  139.572 0 139.59 0.144 ;
    END
    PORT
      LAYER M3 ;
        RECT  139.572 0.108 139.59 1.147 ;
    END
  END head_o[250]
  PIN head_o[251]
    DIRECTION OUTPUT ;
    USE SIGNAL ;
    PORT
      LAYER M5 ;
        RECT  140.112 0 140.136 0.192 ;
    END
    PORT
      LAYER M5 ;
        RECT  140.112 0.144 140.136 1.187 ;
    END
  END head_o[251]
  PIN head_o[252]
    DIRECTION OUTPUT ;
    USE SIGNAL ;
    PORT
      LAYER M3 ;
        RECT  140.652 0 140.67 0.144 ;
    END
    PORT
      LAYER M3 ;
        RECT  140.652 0.108 140.67 0.187 ;
    END
  END head_o[252]
  PIN head_o[253]
    DIRECTION OUTPUT ;
    USE SIGNAL ;
    PORT
      LAYER M5 ;
        RECT  141.216 0 141.24 0.192 ;
    END
    PORT
      LAYER M5 ;
        RECT  141.216 0.144 141.24 0.227 ;
    END
  END head_o[253]
  PIN head_o[254]
    DIRECTION OUTPUT ;
    USE SIGNAL ;
    PORT
      LAYER M3 ;
        RECT  141.732 0 141.75 0.144 ;
    END
    PORT
      LAYER M3 ;
        RECT  141.732 0.108 141.75 0.187 ;
    END
  END head_o[254]
  PIN head_o[255]
    DIRECTION OUTPUT ;
    USE SIGNAL ;
    PORT
      LAYER M5 ;
        RECT  142.272 0 142.296 0.192 ;
    END
    PORT
      LAYER M5 ;
        RECT  142.272 0.144 142.296 0.227 ;
    END
  END head_o[255]
  PIN head_o[25]
    DIRECTION OUTPUT ;
    USE SIGNAL ;
    PORT
      LAYER M5 ;
        RECT  18.096 0 18.12 0.192 ;
    END
    PORT
      LAYER M5 ;
        RECT  18.096 0.144 18.12 0.227 ;
    END
  END head_o[25]
  PIN head_o[26]
    DIRECTION OUTPUT ;
    USE SIGNAL ;
    PORT
      LAYER M3 ;
        RECT  18.612 0 18.63 0.144 ;
    END
    PORT
      LAYER M3 ;
        RECT  18.612 0.108 18.63 0.187 ;
    END
  END head_o[26]
  PIN head_o[27]
    DIRECTION OUTPUT ;
    USE SIGNAL ;
    PORT
      LAYER M5 ;
        RECT  19.152 0 19.176 0.192 ;
    END
    PORT
      LAYER M5 ;
        RECT  19.152 0.144 19.176 1.187 ;
    END
  END head_o[27]
  PIN head_o[28]
    DIRECTION OUTPUT ;
    USE SIGNAL ;
    PORT
      LAYER M3 ;
        RECT  19.692 0 19.71 0.144 ;
    END
    PORT
      LAYER M3 ;
        RECT  19.692 0.108 19.71 1.147 ;
    END
  END head_o[28]
  PIN head_o[29]
    DIRECTION OUTPUT ;
    USE SIGNAL ;
    PORT
      LAYER M5 ;
        RECT  20.256 0 20.28 0.192 ;
    END
    PORT
      LAYER M5 ;
        RECT  20.256 0.144 20.28 1.187 ;
    END
  END head_o[29]
  PIN head_o[2]
    DIRECTION OUTPUT ;
    USE SIGNAL ;
    PORT
      LAYER M3 ;
        RECT  5.652 0 5.67 0.144 ;
    END
    PORT
      LAYER M3 ;
        RECT  5.652 0.108 5.67 0.187 ;
    END
  END head_o[2]
  PIN head_o[30]
    DIRECTION OUTPUT ;
    USE SIGNAL ;
    PORT
      LAYER M3 ;
        RECT  20.772 0 20.79 0.144 ;
    END
    PORT
      LAYER M3 ;
        RECT  20.772 0.108 20.79 1.147 ;
    END
  END head_o[30]
  PIN head_o[31]
    DIRECTION OUTPUT ;
    USE SIGNAL ;
    PORT
      LAYER M5 ;
        RECT  21.312 0 21.336 0.192 ;
    END
    PORT
      LAYER M5 ;
        RECT  21.312 0.144 21.336 1.187 ;
    END
  END head_o[31]
  PIN head_o[32]
    DIRECTION OUTPUT ;
    USE SIGNAL ;
    PORT
      LAYER M3 ;
        RECT  21.852 0 21.87 0.144 ;
    END
    PORT
      LAYER M3 ;
        RECT  21.852 0.108 21.87 0.187 ;
    END
  END head_o[32]
  PIN head_o[33]
    DIRECTION OUTPUT ;
    USE SIGNAL ;
    PORT
      LAYER M5 ;
        RECT  22.416 0 22.44 0.192 ;
    END
    PORT
      LAYER M5 ;
        RECT  22.416 0.144 22.44 0.227 ;
    END
  END head_o[33]
  PIN head_o[34]
    DIRECTION OUTPUT ;
    USE SIGNAL ;
    PORT
      LAYER M3 ;
        RECT  22.932 0 22.95 0.144 ;
    END
    PORT
      LAYER M3 ;
        RECT  22.932 0.108 22.95 0.187 ;
    END
  END head_o[34]
  PIN head_o[35]
    DIRECTION OUTPUT ;
    USE SIGNAL ;
    PORT
      LAYER M5 ;
        RECT  23.472 0 23.496 0.192 ;
    END
    PORT
      LAYER M5 ;
        RECT  23.472 0.144 23.496 0.227 ;
    END
  END head_o[35]
  PIN head_o[36]
    DIRECTION OUTPUT ;
    USE SIGNAL ;
    PORT
      LAYER M3 ;
        RECT  24.012 0 24.03 0.144 ;
    END
    PORT
      LAYER M3 ;
        RECT  24.012 0.108 24.03 0.187 ;
    END
  END head_o[36]
  PIN head_o[37]
    DIRECTION OUTPUT ;
    USE SIGNAL ;
    PORT
      LAYER M5 ;
        RECT  24.576 0 24.6 0.192 ;
    END
    PORT
      LAYER M5 ;
        RECT  24.576 0.144 24.6 0.227 ;
    END
  END head_o[37]
  PIN head_o[38]
    DIRECTION OUTPUT ;
    USE SIGNAL ;
    PORT
      LAYER M3 ;
        RECT  25.092 0 25.11 0.144 ;
    END
    PORT
      LAYER M3 ;
        RECT  25.092 0.108 25.11 0.187 ;
    END
  END head_o[38]
  PIN head_o[39]
    DIRECTION OUTPUT ;
    USE SIGNAL ;
    PORT
      LAYER M5 ;
        RECT  25.632 0 25.656 0.192 ;
    END
    PORT
      LAYER M5 ;
        RECT  25.632 0.144 25.656 1.187 ;
    END
  END head_o[39]
  PIN head_o[3]
    DIRECTION OUTPUT ;
    USE SIGNAL ;
    PORT
      LAYER M5 ;
        RECT  6.192 0 6.216 0.192 ;
    END
    PORT
      LAYER M5 ;
        RECT  6.192 0.144 6.216 1.187 ;
    END
  END head_o[3]
  PIN head_o[40]
    DIRECTION OUTPUT ;
    USE SIGNAL ;
    PORT
      LAYER M3 ;
        RECT  26.172 0 26.19 0.144 ;
    END
    PORT
      LAYER M3 ;
        RECT  26.172 0.108 26.19 0.139 ;
    END
    PORT
      LAYER M3 ;
        RECT  26.1 0.139 26.19 0.167 ;
    END
  END head_o[40]
  PIN head_o[41]
    DIRECTION OUTPUT ;
    USE SIGNAL ;
    PORT
      LAYER M5 ;
        RECT  26.736 0 26.76 0.192 ;
    END
    PORT
      LAYER M5 ;
        RECT  26.736 0.144 26.76 1.187 ;
    END
  END head_o[41]
  PIN head_o[42]
    DIRECTION OUTPUT ;
    USE SIGNAL ;
    PORT
      LAYER M3 ;
        RECT  27.252 0 27.27 0.144 ;
    END
    PORT
      LAYER M3 ;
        RECT  27.252 0.108 27.27 1.147 ;
    END
  END head_o[42]
  PIN head_o[43]
    DIRECTION OUTPUT ;
    USE SIGNAL ;
    PORT
      LAYER M5 ;
        RECT  27.792 0 27.816 0.192 ;
    END
    PORT
      LAYER M5 ;
        RECT  27.792 0.144 27.816 1.187 ;
    END
  END head_o[43]
  PIN head_o[44]
    DIRECTION OUTPUT ;
    USE SIGNAL ;
    PORT
      LAYER M3 ;
        RECT  28.332 0 28.35 0.144 ;
    END
    PORT
      LAYER M3 ;
        RECT  28.332 0.108 28.35 1.147 ;
    END
  END head_o[44]
  PIN head_o[45]
    DIRECTION OUTPUT ;
    USE SIGNAL ;
    PORT
      LAYER M5 ;
        RECT  28.896 0 28.92 0.192 ;
    END
    PORT
      LAYER M5 ;
        RECT  28.896 0.144 28.92 1.187 ;
    END
  END head_o[45]
  PIN head_o[46]
    DIRECTION OUTPUT ;
    USE SIGNAL ;
    PORT
      LAYER M3 ;
        RECT  29.412 0 29.43 0.144 ;
    END
    PORT
      LAYER M3 ;
        RECT  29.412 0.108 29.43 0.139 ;
    END
    PORT
      LAYER M3 ;
        RECT  29.412 0.139 29.574 0.167 ;
    END
  END head_o[46]
  PIN head_o[47]
    DIRECTION OUTPUT ;
    USE SIGNAL ;
    PORT
      LAYER M5 ;
        RECT  29.952 0 29.976 0.192 ;
    END
    PORT
      LAYER M5 ;
        RECT  29.952 0.144 29.976 0.227 ;
    END
  END head_o[47]
  PIN head_o[48]
    DIRECTION OUTPUT ;
    USE SIGNAL ;
    PORT
      LAYER M3 ;
        RECT  30.492 0 30.51 0.144 ;
    END
    PORT
      LAYER M3 ;
        RECT  30.492 0.108 30.51 0.187 ;
    END
  END head_o[48]
  PIN head_o[49]
    DIRECTION OUTPUT ;
    USE SIGNAL ;
    PORT
      LAYER M5 ;
        RECT  31.056 0 31.08 0.192 ;
    END
    PORT
      LAYER M5 ;
        RECT  31.056 0.144 31.08 0.227 ;
    END
  END head_o[49]
  PIN head_o[4]
    DIRECTION OUTPUT ;
    USE SIGNAL ;
    PORT
      LAYER M3 ;
        RECT  6.732 0 6.75 0.144 ;
    END
    PORT
      LAYER M3 ;
        RECT  6.732 0.108 6.75 1.147 ;
    END
  END head_o[4]
  PIN head_o[50]
    DIRECTION OUTPUT ;
    USE SIGNAL ;
    PORT
      LAYER M3 ;
        RECT  31.572 0 31.59 0.144 ;
    END
    PORT
      LAYER M3 ;
        RECT  31.572 0.108 31.59 0.187 ;
    END
  END head_o[50]
  PIN head_o[51]
    DIRECTION OUTPUT ;
    USE SIGNAL ;
    PORT
      LAYER M5 ;
        RECT  32.112 0 32.136 0.192 ;
    END
    PORT
      LAYER M5 ;
        RECT  32.112 0.144 32.136 0.227 ;
    END
  END head_o[51]
  PIN head_o[52]
    DIRECTION OUTPUT ;
    USE SIGNAL ;
    PORT
      LAYER M3 ;
        RECT  32.652 0 32.67 0.144 ;
    END
    PORT
      LAYER M3 ;
        RECT  32.652 0.108 32.67 0.187 ;
    END
  END head_o[52]
  PIN head_o[53]
    DIRECTION OUTPUT ;
    USE SIGNAL ;
    PORT
      LAYER M5 ;
        RECT  33.216 0 33.24 0.192 ;
    END
    PORT
      LAYER M5 ;
        RECT  33.216 0.144 33.24 1.187 ;
    END
  END head_o[53]
  PIN head_o[54]
    DIRECTION OUTPUT ;
    USE SIGNAL ;
    PORT
      LAYER M3 ;
        RECT  33.732 0 33.75 0.144 ;
    END
    PORT
      LAYER M3 ;
        RECT  33.732 0.108 33.75 0.187 ;
    END
  END head_o[54]
  PIN head_o[55]
    DIRECTION OUTPUT ;
    USE SIGNAL ;
    PORT
      LAYER M5 ;
        RECT  34.272 0 34.296 0.192 ;
    END
    PORT
      LAYER M5 ;
        RECT  34.272 0.144 34.296 0.227 ;
    END
  END head_o[55]
  PIN head_o[56]
    DIRECTION OUTPUT ;
    USE SIGNAL ;
    PORT
      LAYER M3 ;
        RECT  34.812 0 34.83 0.144 ;
    END
    PORT
      LAYER M3 ;
        RECT  34.812 0.108 34.83 0.187 ;
    END
  END head_o[56]
  PIN head_o[57]
    DIRECTION OUTPUT ;
    USE SIGNAL ;
    PORT
      LAYER M5 ;
        RECT  35.376 0 35.4 0.192 ;
    END
    PORT
      LAYER M5 ;
        RECT  35.376 0.144 35.4 0.323 ;
    END
  END head_o[57]
  PIN head_o[58]
    DIRECTION OUTPUT ;
    USE SIGNAL ;
    PORT
      LAYER M3 ;
        RECT  35.892 0 35.91 0.144 ;
    END
    PORT
      LAYER M3 ;
        RECT  35.892 0.108 35.91 0.139 ;
    END
    PORT
      LAYER M3 ;
        RECT  35.82 0.139 35.91 2.101 ;
    END
  END head_o[58]
  PIN head_o[59]
    DIRECTION OUTPUT ;
    USE SIGNAL ;
    PORT
      LAYER M5 ;
        RECT  36.432 0 36.456 0.192 ;
    END
    PORT
      LAYER M5 ;
        RECT  36.432 0.144 36.456 1.187 ;
    END
  END head_o[59]
  PIN head_o[5]
    DIRECTION OUTPUT ;
    USE SIGNAL ;
    PORT
      LAYER M5 ;
        RECT  7.296 0 7.32 0.192 ;
    END
    PORT
      LAYER M5 ;
        RECT  7.296 0.144 7.32 1.187 ;
    END
  END head_o[5]
  PIN head_o[60]
    DIRECTION OUTPUT ;
    USE SIGNAL ;
    PORT
      LAYER M3 ;
        RECT  36.972 0 36.99 0.144 ;
    END
    PORT
      LAYER M3 ;
        RECT  36.972 0.108 36.99 1.147 ;
    END
  END head_o[60]
  PIN head_o[61]
    DIRECTION OUTPUT ;
    USE SIGNAL ;
    PORT
      LAYER M5 ;
        RECT  37.536 0 37.56 0.192 ;
    END
    PORT
      LAYER M5 ;
        RECT  37.536 0.144 37.56 1.187 ;
    END
  END head_o[61]
  PIN head_o[62]
    DIRECTION OUTPUT ;
    USE SIGNAL ;
    PORT
      LAYER M3 ;
        RECT  38.052 0 38.07 0.144 ;
    END
    PORT
      LAYER M3 ;
        RECT  38.052 0.108 38.07 0.187 ;
    END
  END head_o[62]
  PIN head_o[63]
    DIRECTION OUTPUT ;
    USE SIGNAL ;
    PORT
      LAYER M5 ;
        RECT  38.592 0 38.616 0.192 ;
    END
    PORT
      LAYER M5 ;
        RECT  38.592 0.144 38.616 0.227 ;
    END
  END head_o[63]
  PIN head_o[64]
    DIRECTION OUTPUT ;
    USE SIGNAL ;
    PORT
      LAYER M3 ;
        RECT  39.132 0 39.15 0.144 ;
    END
    PORT
      LAYER M3 ;
        RECT  39.132 0.108 39.15 0.187 ;
    END
  END head_o[64]
  PIN head_o[65]
    DIRECTION OUTPUT ;
    USE SIGNAL ;
    PORT
      LAYER M5 ;
        RECT  39.696 0 39.72 0.192 ;
    END
    PORT
      LAYER M5 ;
        RECT  39.696 0.144 39.72 1.187 ;
    END
  END head_o[65]
  PIN head_o[66]
    DIRECTION OUTPUT ;
    USE SIGNAL ;
    PORT
      LAYER M3 ;
        RECT  40.212 0 40.23 0.144 ;
    END
    PORT
      LAYER M3 ;
        RECT  40.212 0.108 40.23 0.139 ;
    END
    PORT
      LAYER M3 ;
        RECT  40.212 0.139 40.374 0.167 ;
    END
  END head_o[66]
  PIN head_o[67]
    DIRECTION OUTPUT ;
    USE SIGNAL ;
    PORT
      LAYER M5 ;
        RECT  40.752 0 40.776 0.192 ;
    END
    PORT
      LAYER M5 ;
        RECT  40.752 0.144 40.776 0.611 ;
    END
  END head_o[67]
  PIN head_o[68]
    DIRECTION OUTPUT ;
    USE SIGNAL ;
    PORT
      LAYER M3 ;
        RECT  41.292 0 41.31 0.144 ;
    END
    PORT
      LAYER M3 ;
        RECT  41.292 0.108 41.31 0.187 ;
    END
  END head_o[68]
  PIN head_o[69]
    DIRECTION OUTPUT ;
    USE SIGNAL ;
    PORT
      LAYER M5 ;
        RECT  41.856 0 41.88 0.192 ;
    END
    PORT
      LAYER M5 ;
        RECT  41.856 0.144 41.88 0.227 ;
    END
  END head_o[69]
  PIN head_o[6]
    DIRECTION OUTPUT ;
    USE SIGNAL ;
    PORT
      LAYER M3 ;
        RECT  7.812 0 7.83 0.144 ;
    END
    PORT
      LAYER M3 ;
        RECT  7.812 0.108 7.83 1.147 ;
    END
  END head_o[6]
  PIN head_o[70]
    DIRECTION OUTPUT ;
    USE SIGNAL ;
    PORT
      LAYER M3 ;
        RECT  42.372 0 42.39 0.144 ;
    END
    PORT
      LAYER M3 ;
        RECT  42.372 0.108 42.39 0.187 ;
    END
  END head_o[70]
  PIN head_o[71]
    DIRECTION OUTPUT ;
    USE SIGNAL ;
    PORT
      LAYER M5 ;
        RECT  42.912 0 42.936 0.192 ;
    END
    PORT
      LAYER M5 ;
        RECT  42.912 0.144 42.936 1.187 ;
    END
  END head_o[71]
  PIN head_o[72]
    DIRECTION OUTPUT ;
    USE SIGNAL ;
    PORT
      LAYER M3 ;
        RECT  43.452 0 43.47 0.144 ;
    END
    PORT
      LAYER M3 ;
        RECT  43.452 0.108 43.47 1.147 ;
    END
  END head_o[72]
  PIN head_o[73]
    DIRECTION OUTPUT ;
    USE SIGNAL ;
    PORT
      LAYER M5 ;
        RECT  44.016 0 44.04 0.192 ;
    END
    PORT
      LAYER M5 ;
        RECT  44.016 0.144 44.04 0.227 ;
    END
  END head_o[73]
  PIN head_o[74]
    DIRECTION OUTPUT ;
    USE SIGNAL ;
    PORT
      LAYER M3 ;
        RECT  44.532 0 44.55 0.144 ;
    END
    PORT
      LAYER M3 ;
        RECT  44.532 0.108 44.55 0.187 ;
    END
  END head_o[74]
  PIN head_o[75]
    DIRECTION OUTPUT ;
    USE SIGNAL ;
    PORT
      LAYER M5 ;
        RECT  45.072 0 45.096 0.192 ;
    END
    PORT
      LAYER M5 ;
        RECT  45.072 0.144 45.096 0.611 ;
    END
  END head_o[75]
  PIN head_o[76]
    DIRECTION OUTPUT ;
    USE SIGNAL ;
    PORT
      LAYER M3 ;
        RECT  45.612 0 45.63 0.144 ;
    END
    PORT
      LAYER M3 ;
        RECT  45.612 0.108 45.63 0.139 ;
    END
    PORT
      LAYER M3 ;
        RECT  45.612 0.139 45.774 0.571 ;
    END
  END head_o[76]
  PIN head_o[77]
    DIRECTION OUTPUT ;
    USE SIGNAL ;
    PORT
      LAYER M5 ;
        RECT  46.176 0 46.2 0.192 ;
    END
    PORT
      LAYER M5 ;
        RECT  46.176 0.144 46.2 0.227 ;
    END
  END head_o[77]
  PIN head_o[78]
    DIRECTION OUTPUT ;
    USE SIGNAL ;
    PORT
      LAYER M3 ;
        RECT  46.692 0 46.71 0.144 ;
    END
    PORT
      LAYER M3 ;
        RECT  46.692 0.108 46.71 0.187 ;
    END
  END head_o[78]
  PIN head_o[79]
    DIRECTION OUTPUT ;
    USE SIGNAL ;
    PORT
      LAYER M5 ;
        RECT  47.232 0 47.256 0.192 ;
    END
    PORT
      LAYER M5 ;
        RECT  47.232 0.144 47.256 0.227 ;
    END
  END head_o[79]
  PIN head_o[7]
    DIRECTION OUTPUT ;
    USE SIGNAL ;
    PORT
      LAYER M5 ;
        RECT  8.352 0 8.376 0.192 ;
    END
    PORT
      LAYER M5 ;
        RECT  8.352 0.144 8.376 1.187 ;
    END
  END head_o[7]
  PIN head_o[80]
    DIRECTION OUTPUT ;
    USE SIGNAL ;
    PORT
      LAYER M3 ;
        RECT  47.772 0 47.79 0.144 ;
    END
    PORT
      LAYER M3 ;
        RECT  47.772 0.108 47.79 0.187 ;
    END
  END head_o[80]
  PIN head_o[81]
    DIRECTION OUTPUT ;
    USE SIGNAL ;
    PORT
      LAYER M5 ;
        RECT  48.336 0 48.36 0.192 ;
    END
    PORT
      LAYER M5 ;
        RECT  48.336 0.144 48.36 1.187 ;
    END
  END head_o[81]
  PIN head_o[82]
    DIRECTION OUTPUT ;
    USE SIGNAL ;
    PORT
      LAYER M3 ;
        RECT  48.852 0 48.87 0.144 ;
    END
    PORT
      LAYER M3 ;
        RECT  48.852 0.108 48.87 1.147 ;
    END
  END head_o[82]
  PIN head_o[83]
    DIRECTION OUTPUT ;
    USE SIGNAL ;
    PORT
      LAYER M5 ;
        RECT  49.392 0 49.416 0.192 ;
    END
    PORT
      LAYER M5 ;
        RECT  49.392 0.144 49.416 1.187 ;
    END
  END head_o[83]
  PIN head_o[84]
    DIRECTION OUTPUT ;
    USE SIGNAL ;
    PORT
      LAYER M3 ;
        RECT  49.932 0 49.95 0.144 ;
    END
    PORT
      LAYER M3 ;
        RECT  49.932 0.108 49.95 0.187 ;
    END
  END head_o[84]
  PIN head_o[85]
    DIRECTION OUTPUT ;
    USE SIGNAL ;
    PORT
      LAYER M5 ;
        RECT  50.496 0 50.52 0.192 ;
    END
    PORT
      LAYER M5 ;
        RECT  50.496 0.144 50.52 0.227 ;
    END
  END head_o[85]
  PIN head_o[86]
    DIRECTION OUTPUT ;
    USE SIGNAL ;
    PORT
      LAYER M3 ;
        RECT  51.012 0 51.03 0.144 ;
    END
    PORT
      LAYER M3 ;
        RECT  51.012 0.108 51.03 0.139 ;
    END
    PORT
      LAYER M3 ;
        RECT  51.012 0.139 51.174 0.187 ;
    END
  END head_o[86]
  PIN head_o[87]
    DIRECTION OUTPUT ;
    USE SIGNAL ;
    PORT
      LAYER M5 ;
        RECT  51.552 0 51.576 0.192 ;
    END
    PORT
      LAYER M5 ;
        RECT  51.552 0.144 51.576 0.227 ;
    END
  END head_o[87]
  PIN head_o[88]
    DIRECTION OUTPUT ;
    USE SIGNAL ;
    PORT
      LAYER M3 ;
        RECT  52.092 0 52.11 0.144 ;
    END
    PORT
      LAYER M3 ;
        RECT  52.092 0.108 52.11 0.187 ;
    END
  END head_o[88]
  PIN head_o[89]
    DIRECTION OUTPUT ;
    USE SIGNAL ;
    PORT
      LAYER M5 ;
        RECT  52.656 0 52.68 0.192 ;
    END
    PORT
      LAYER M5 ;
        RECT  52.656 0.144 52.68 1.187 ;
    END
  END head_o[89]
  PIN head_o[8]
    DIRECTION OUTPUT ;
    USE SIGNAL ;
    PORT
      LAYER M3 ;
        RECT  8.892 0 8.91 0.144 ;
    END
    PORT
      LAYER M3 ;
        RECT  8.892 0.108 8.91 1.147 ;
    END
  END head_o[8]
  PIN head_o[90]
    DIRECTION OUTPUT ;
    USE SIGNAL ;
    PORT
      LAYER M3 ;
        RECT  53.172 0 53.19 0.144 ;
    END
    PORT
      LAYER M3 ;
        RECT  53.172 0.108 53.19 1.147 ;
    END
  END head_o[90]
  PIN head_o[91]
    DIRECTION OUTPUT ;
    USE SIGNAL ;
    PORT
      LAYER M5 ;
        RECT  53.712 0 53.736 0.192 ;
    END
    PORT
      LAYER M5 ;
        RECT  53.712 0.144 53.736 1.187 ;
    END
  END head_o[91]
  PIN head_o[92]
    DIRECTION OUTPUT ;
    USE SIGNAL ;
    PORT
      LAYER M3 ;
        RECT  54.252 0 54.27 0.144 ;
    END
    PORT
      LAYER M3 ;
        RECT  54.252 0.108 54.27 0.187 ;
    END
  END head_o[92]
  PIN head_o[93]
    DIRECTION OUTPUT ;
    USE SIGNAL ;
    PORT
      LAYER M5 ;
        RECT  54.816 0 54.84 0.192 ;
    END
    PORT
      LAYER M5 ;
        RECT  54.816 0.144 54.84 0.227 ;
    END
  END head_o[93]
  PIN head_o[94]
    DIRECTION OUTPUT ;
    USE SIGNAL ;
    PORT
      LAYER M3 ;
        RECT  55.332 0 55.35 0.144 ;
    END
    PORT
      LAYER M3 ;
        RECT  55.332 0.108 55.35 0.187 ;
    END
  END head_o[94]
  PIN head_o[95]
    DIRECTION OUTPUT ;
    USE SIGNAL ;
    PORT
      LAYER M5 ;
        RECT  55.872 0 55.896 0.192 ;
    END
    PORT
      LAYER M5 ;
        RECT  55.872 0.144 55.896 0.611 ;
    END
  END head_o[95]
  PIN head_o[96]
    DIRECTION OUTPUT ;
    USE SIGNAL ;
    PORT
      LAYER M3 ;
        RECT  56.412 0 56.43 0.144 ;
    END
    PORT
      LAYER M3 ;
        RECT  56.412 0.108 56.43 0.571 ;
    END
  END head_o[96]
  PIN head_o[97]
    DIRECTION OUTPUT ;
    USE SIGNAL ;
    PORT
      LAYER M5 ;
        RECT  56.976 0 57 0.192 ;
    END
    PORT
      LAYER M5 ;
        RECT  56.976 0.144 57 1.187 ;
    END
  END head_o[97]
  PIN head_o[98]
    DIRECTION OUTPUT ;
    USE SIGNAL ;
    PORT
      LAYER M3 ;
        RECT  57.492 0 57.51 0.144 ;
    END
    PORT
      LAYER M3 ;
        RECT  57.492 0.108 57.51 1.147 ;
    END
  END head_o[98]
  PIN head_o[99]
    DIRECTION OUTPUT ;
    USE SIGNAL ;
    PORT
      LAYER M5 ;
        RECT  58.032 0 58.056 0.192 ;
    END
    PORT
      LAYER M5 ;
        RECT  58.032 0.144 58.056 1.763 ;
    END
  END head_o[99]
  PIN head_o[9]
    DIRECTION OUTPUT ;
    USE SIGNAL ;
    PORT
      LAYER M5 ;
        RECT  9.456 0 9.48 0.192 ;
    END
    PORT
      LAYER M5 ;
        RECT  9.456 0.144 9.48 1.187 ;
    END
  END head_o[9]
  PIN hv_o
    DIRECTION OUTPUT ;
    USE SIGNAL ;
    PORT
      LAYER M3 ;
        RECT  141.768 91.656 141.786 91.8 ;
    END
    PORT
      LAYER M3 ;
        RECT  141.768 90.605 141.786 91.692 ;
    END
  END hv_o
  PIN ovf_o
    DIRECTION OUTPUT ;
    USE SIGNAL ;
    PORT
      LAYER M5 ;
        RECT  142.272 91.608 142.296 91.8 ;
    END
    PORT
      LAYER M5 ;
        RECT  142.272 90.565 142.296 91.664 ;
    END
  END ovf_o
  PIN pop_i
    DIRECTION INPUT ;
    USE SIGNAL ;
    PORT
      LAYER M5 ;
        RECT  5.088 91.608 5.112 91.8 ;
    END
    PORT
      LAYER M5 ;
        RECT  5.088 89.509 5.112 91.664 ;
    END
  END pop_i
  PIN push_i
    DIRECTION INPUT ;
    USE SIGNAL ;
    PORT
      LAYER M3 ;
        RECT  5.616 91.656 5.634 91.8 ;
    END
    PORT
      LAYER M3 ;
        RECT  5.616 89.549 5.634 91.692 ;
    END
  END push_i
  PIN srs
    DIRECTION INPUT ;
    USE SIGNAL ;
    PORT
      LAYER M3 ;
        RECT  4.572 91.656 4.59 91.8 ;
    END
    PORT
      LAYER M3 ;
        RECT  4.572 89.549 4.59 91.692 ;
    END
  END srs
  PIN VDD
    DIRECTION INOUT ;
    USE POWER ;
    PORT
      LAYER M5 ;
        RECT  142.992 2.151 143.112 89.649 ;
        RECT  137.592 2.151 137.712 89.649 ;
        RECT  132.192 2.151 132.312 89.649 ;
        RECT  126.792 2.151 126.912 89.649 ;
        RECT  121.392 2.151 121.512 89.649 ;
        RECT  115.992 2.151 116.112 89.649 ;
        RECT  110.592 2.151 110.712 89.649 ;
        RECT  105.192 2.151 105.312 89.649 ;
        RECT  99.792 2.151 99.912 89.649 ;
        RECT  94.392 2.151 94.512 89.649 ;
        RECT  88.992 2.151 89.112 89.649 ;
        RECT  83.592 2.151 83.712 89.649 ;
        RECT  78.192 2.151 78.312 89.649 ;
        RECT  72.792 2.151 72.912 89.649 ;
        RECT  67.392 2.151 67.512 89.649 ;
        RECT  61.992 2.151 62.112 89.649 ;
        RECT  56.592 2.151 56.712 89.649 ;
        RECT  51.192 2.151 51.312 89.649 ;
        RECT  45.792 2.151 45.912 89.649 ;
        RECT  40.392 2.151 40.512 89.649 ;
        RECT  34.992 2.151 35.112 89.649 ;
        RECT  29.592 2.151 29.712 89.649 ;
        RECT  24.192 2.151 24.312 89.649 ;
        RECT  18.792 2.151 18.912 89.649 ;
        RECT  13.392 2.151 13.512 89.649 ;
        RECT  7.992 2.151 8.112 89.649 ;
        RECT  2.592 2.151 2.712 89.649 ;
    END
  END VDD
  PIN VSS
    DIRECTION INOUT ;
    USE GROUND ;
    PORT
      LAYER M5 ;
        RECT  142.8 2.137 142.92 89.663 ;
        RECT  137.4 2.137 137.52 89.663 ;
        RECT  132 2.137 132.12 89.663 ;
        RECT  126.6 2.137 126.72 89.663 ;
        RECT  121.2 2.137 121.32 89.663 ;
        RECT  115.8 2.137 115.92 89.663 ;
        RECT  110.4 2.137 110.52 89.663 ;
        RECT  105 2.137 105.12 89.663 ;
        RECT  99.6 2.137 99.72 89.663 ;
        RECT  94.2 2.137 94.32 89.663 ;
        RECT  88.8 2.137 88.92 89.663 ;
        RECT  83.4 2.137 83.52 89.663 ;
        RECT  78 2.137 78.12 89.663 ;
        RECT  72.6 2.137 72.72 89.663 ;
        RECT  67.2 2.137 67.32 89.663 ;
        RECT  61.8 2.137 61.92 89.663 ;
        RECT  56.4 2.137 56.52 89.663 ;
        RECT  51 2.137 51.12 89.663 ;
        RECT  45.6 2.137 45.72 89.663 ;
        RECT  40.2 2.137 40.32 89.663 ;
        RECT  34.8 2.137 34.92 89.663 ;
        RECT  29.4 2.137 29.52 89.663 ;
        RECT  24 2.137 24.12 89.663 ;
        RECT  18.6 2.137 18.72 89.663 ;
        RECT  13.2 2.137 13.32 89.663 ;
        RECT  7.8 2.137 7.92 89.663 ;
        RECT  2.4 2.137 2.52 89.663 ;
    END
  END VSS
  # OT_OBS_CLOSED layer=M5 d_um=1.536 added=349
  OBS
    LAYER RVTN ;
     RECT  2.16 2.16 144.72 2.295 ;
     RECT  2.16 2.565 144.72 2.835 ;
     RECT  2.16 3.105 144.72 3.375 ;
     RECT  2.16 3.645 144.72 3.915 ;
     RECT  2.16 4.185 144.72 4.455 ;
     RECT  2.16 4.725 144.72 4.995 ;
     RECT  2.16 5.265 144.72 5.535 ;
     RECT  2.16 5.805 144.72 6.075 ;
     RECT  2.16 6.345 144.72 6.615 ;
     RECT  2.16 6.885 144.72 7.155 ;
     RECT  2.16 7.425 144.72 7.695 ;
     RECT  2.16 7.965 144.72 8.235 ;
     RECT  2.16 8.505 144.72 8.775 ;
     RECT  2.16 9.045 144.72 9.315 ;
     RECT  2.16 9.585 144.72 9.855 ;
     RECT  2.16 10.125 144.72 10.395 ;
     RECT  2.16 10.665 144.72 10.935 ;
     RECT  2.16 11.205 144.72 11.475 ;
     RECT  2.16 11.745 144.72 12.015 ;
     RECT  2.16 12.285 144.72 12.555 ;
     RECT  2.16 12.825 144.72 13.095 ;
     RECT  2.16 13.365 144.72 13.635 ;
     RECT  2.16 13.905 144.72 14.175 ;
     RECT  2.16 14.445 144.72 14.715 ;
     RECT  2.16 14.985 144.72 15.255 ;
     RECT  2.16 15.525 144.72 15.795 ;
     RECT  2.16 16.065 144.72 16.335 ;
     RECT  2.16 16.605 144.72 16.875 ;
     RECT  2.16 17.145 144.72 17.415 ;
     RECT  2.16 17.685 144.72 17.955 ;
     RECT  2.16 18.225 144.72 18.495 ;
     RECT  2.16 18.765 144.72 19.035 ;
     RECT  2.16 19.305 144.72 19.575 ;
     RECT  2.16 19.845 144.72 20.115 ;
     RECT  2.16 20.385 144.72 20.655 ;
     RECT  2.16 20.925 144.72 21.195 ;
     RECT  2.16 21.465 144.72 21.735 ;
     RECT  2.16 22.005 144.72 22.275 ;
     RECT  2.16 22.545 144.72 22.815 ;
     RECT  2.16 23.085 144.72 23.355 ;
     RECT  2.16 23.625 144.72 23.76 ;
     RECT  2.16 23.76 24.732 23.895 ;
     RECT  123.66 23.76 144.72 23.895 ;
     RECT  2.16 24.165 24.732 24.435 ;
     RECT  123.66 24.165 144.72 24.435 ;
     RECT  2.16 24.705 24.732 24.975 ;
     RECT  123.66 24.705 144.72 24.975 ;
     RECT  2.16 25.245 24.732 25.515 ;
     RECT  123.66 25.245 144.72 25.515 ;
     RECT  2.16 25.785 24.732 26.055 ;
     RECT  123.66 25.785 144.72 26.055 ;
     RECT  2.16 26.325 24.732 26.595 ;
     RECT  123.66 26.325 144.72 26.595 ;
     RECT  2.16 26.865 24.732 27.135 ;
     RECT  123.66 26.865 144.72 27.135 ;
     RECT  2.16 27.405 24.732 27.675 ;
     RECT  123.66 27.405 144.72 27.675 ;
     RECT  2.16 27.945 24.732 28.215 ;
     RECT  123.66 27.945 144.72 28.215 ;
     RECT  2.16 28.485 24.732 28.755 ;
     RECT  123.66 28.485 144.72 28.755 ;
     RECT  2.16 29.025 24.732 29.295 ;
     RECT  123.66 29.025 144.72 29.295 ;
     RECT  2.16 29.565 24.732 29.835 ;
     RECT  123.66 29.565 144.72 29.835 ;
     RECT  2.16 30.105 24.732 30.375 ;
     RECT  123.66 30.105 144.72 30.375 ;
     RECT  2.16 30.645 24.732 30.915 ;
     RECT  123.66 30.645 144.72 30.915 ;
     RECT  2.16 31.185 24.732 31.455 ;
     RECT  123.66 31.185 144.72 31.455 ;
     RECT  2.16 31.725 24.732 31.995 ;
     RECT  123.66 31.725 144.72 31.995 ;
     RECT  2.16 32.265 24.732 32.535 ;
     RECT  123.66 32.265 144.72 32.535 ;
     RECT  2.16 32.805 24.732 33.075 ;
     RECT  123.66 32.805 144.72 33.075 ;
     RECT  2.16 33.345 24.732 33.615 ;
     RECT  123.66 33.345 144.72 33.615 ;
     RECT  2.16 33.885 24.732 34.155 ;
     RECT  123.66 33.885 144.72 34.155 ;
     RECT  2.16 34.425 24.732 34.695 ;
     RECT  123.66 34.425 144.72 34.695 ;
     RECT  2.16 34.965 24.732 35.235 ;
     RECT  123.66 34.965 144.72 35.235 ;
     RECT  2.16 35.505 24.732 35.775 ;
     RECT  123.66 35.505 144.72 35.775 ;
     RECT  2.16 36.045 24.732 36.315 ;
     RECT  123.66 36.045 144.72 36.315 ;
     RECT  2.16 36.585 24.732 36.855 ;
     RECT  123.66 36.585 144.72 36.855 ;
     RECT  2.16 37.125 24.732 37.395 ;
     RECT  123.66 37.125 144.72 37.395 ;
     RECT  2.16 37.665 24.732 37.935 ;
     RECT  123.66 37.665 144.72 37.935 ;
     RECT  2.16 38.205 24.732 38.475 ;
     RECT  123.66 38.205 144.72 38.475 ;
     RECT  2.16 38.745 24.732 39.015 ;
     RECT  123.66 38.745 144.72 39.015 ;
     RECT  2.16 39.285 24.732 39.555 ;
     RECT  123.66 39.285 144.72 39.555 ;
     RECT  2.16 39.825 24.732 40.095 ;
     RECT  123.66 39.825 144.72 40.095 ;
     RECT  2.16 40.365 24.732 40.635 ;
     RECT  123.66 40.365 144.72 40.635 ;
     RECT  2.16 40.905 24.732 41.175 ;
     RECT  123.66 40.905 144.72 41.175 ;
     RECT  2.16 41.445 24.732 41.715 ;
     RECT  123.66 41.445 144.72 41.715 ;
     RECT  2.16 41.985 24.732 42.255 ;
     RECT  123.66 41.985 144.72 42.255 ;
     RECT  2.16 42.525 24.732 42.795 ;
     RECT  123.66 42.525 144.72 42.795 ;
     RECT  2.16 43.065 24.732 43.335 ;
     RECT  123.66 43.065 144.72 43.335 ;
     RECT  2.16 43.605 24.732 43.875 ;
     RECT  123.66 43.605 144.72 43.875 ;
     RECT  2.16 44.145 24.732 44.415 ;
     RECT  123.66 44.145 144.72 44.415 ;
     RECT  2.16 44.685 24.732 44.955 ;
     RECT  123.66 44.685 144.72 44.955 ;
     RECT  2.16 45.225 24.732 45.495 ;
     RECT  123.66 45.225 144.72 45.495 ;
     RECT  2.16 45.765 24.732 46.035 ;
     RECT  123.66 45.765 144.72 46.035 ;
     RECT  2.16 46.305 24.732 46.575 ;
     RECT  123.66 46.305 144.72 46.575 ;
     RECT  2.16 46.845 24.732 47.115 ;
     RECT  123.66 46.845 144.72 47.115 ;
     RECT  2.16 47.385 24.732 47.655 ;
     RECT  123.66 47.385 144.72 47.655 ;
     RECT  2.16 47.925 24.732 48.195 ;
     RECT  123.66 47.925 144.72 48.195 ;
     RECT  2.16 48.465 24.732 48.735 ;
     RECT  123.66 48.465 144.72 48.735 ;
     RECT  2.16 49.005 24.732 49.275 ;
     RECT  123.66 49.005 144.72 49.275 ;
     RECT  2.16 49.545 24.732 49.815 ;
     RECT  123.66 49.545 144.72 49.815 ;
     RECT  2.16 50.085 24.732 50.355 ;
     RECT  123.66 50.085 144.72 50.355 ;
     RECT  2.16 50.625 24.732 50.895 ;
     RECT  123.66 50.625 144.72 50.895 ;
     RECT  2.16 51.165 24.732 51.435 ;
     RECT  123.66 51.165 144.72 51.435 ;
     RECT  2.16 51.705 24.732 51.975 ;
     RECT  123.66 51.705 144.72 51.975 ;
     RECT  2.16 52.245 24.732 52.515 ;
     RECT  123.66 52.245 144.72 52.515 ;
     RECT  2.16 52.785 24.732 53.055 ;
     RECT  123.66 52.785 144.72 53.055 ;
     RECT  2.16 53.325 24.732 53.595 ;
     RECT  123.66 53.325 144.72 53.595 ;
     RECT  2.16 53.865 24.732 54.135 ;
     RECT  123.66 53.865 144.72 54.135 ;
     RECT  2.16 54.405 24.732 54.675 ;
     RECT  123.66 54.405 144.72 54.675 ;
     RECT  2.16 54.945 24.732 55.215 ;
     RECT  123.66 54.945 144.72 55.215 ;
     RECT  2.16 55.485 24.732 55.755 ;
     RECT  123.66 55.485 144.72 55.755 ;
     RECT  2.16 56.025 24.732 56.295 ;
     RECT  123.66 56.025 144.72 56.295 ;
     RECT  2.16 56.565 24.732 56.835 ;
     RECT  123.66 56.565 144.72 56.835 ;
     RECT  2.16 57.105 24.732 57.375 ;
     RECT  123.66 57.105 144.72 57.375 ;
     RECT  2.16 57.645 24.732 57.915 ;
     RECT  123.66 57.645 144.72 57.915 ;
     RECT  2.16 58.185 24.732 58.455 ;
     RECT  123.66 58.185 144.72 58.455 ;
     RECT  2.16 58.725 24.732 58.995 ;
     RECT  123.66 58.725 144.72 58.995 ;
     RECT  2.16 59.265 24.732 59.535 ;
     RECT  123.66 59.265 144.72 59.535 ;
     RECT  2.16 59.805 24.732 60.075 ;
     RECT  123.66 59.805 144.72 60.075 ;
     RECT  2.16 60.345 24.732 60.615 ;
     RECT  123.66 60.345 144.72 60.615 ;
     RECT  2.16 60.885 24.732 61.155 ;
     RECT  123.66 60.885 144.72 61.155 ;
     RECT  2.16 61.425 24.732 61.695 ;
     RECT  123.66 61.425 144.72 61.695 ;
     RECT  2.16 61.965 24.732 62.235 ;
     RECT  123.66 61.965 144.72 62.235 ;
     RECT  2.16 62.505 24.732 62.775 ;
     RECT  123.66 62.505 144.72 62.775 ;
     RECT  2.16 63.045 24.732 63.315 ;
     RECT  123.66 63.045 144.72 63.315 ;
     RECT  2.16 63.585 24.732 63.855 ;
     RECT  123.66 63.585 144.72 63.855 ;
     RECT  2.16 64.125 24.732 64.395 ;
     RECT  123.66 64.125 144.72 64.395 ;
     RECT  2.16 64.665 24.732 64.935 ;
     RECT  123.66 64.665 144.72 64.935 ;
     RECT  2.16 65.205 24.732 65.475 ;
     RECT  123.66 65.205 144.72 65.475 ;
     RECT  2.16 65.745 24.732 66.015 ;
     RECT  123.66 65.745 144.72 66.015 ;
     RECT  2.16 66.285 24.732 66.555 ;
     RECT  123.66 66.285 144.72 66.555 ;
     RECT  2.16 66.825 24.732 67.095 ;
     RECT  123.66 66.825 144.72 67.095 ;
     RECT  2.16 67.365 24.732 67.635 ;
     RECT  123.66 67.365 144.72 67.635 ;
     RECT  2.16 67.905 24.732 68.175 ;
     RECT  123.66 67.905 144.72 68.175 ;
     RECT  2.16 68.445 24.732 68.715 ;
     RECT  123.66 68.445 144.72 68.715 ;
     RECT  2.16 68.985 24.732 69.12 ;
     RECT  123.66 68.985 144.72 69.12 ;
     RECT  2.16 69.12 144.72 69.255 ;
     RECT  2.16 69.525 144.72 69.795 ;
     RECT  2.16 70.065 144.72 70.335 ;
     RECT  2.16 70.605 144.72 70.875 ;
     RECT  2.16 71.145 144.72 71.415 ;
     RECT  2.16 71.685 144.72 71.955 ;
     RECT  2.16 72.225 144.72 72.495 ;
     RECT  2.16 72.765 144.72 73.035 ;
     RECT  2.16 73.305 144.72 73.575 ;
     RECT  2.16 73.845 144.72 74.115 ;
     RECT  2.16 74.385 144.72 74.655 ;
     RECT  2.16 74.925 144.72 75.195 ;
     RECT  2.16 75.465 144.72 75.735 ;
     RECT  2.16 76.005 144.72 76.275 ;
     RECT  2.16 76.545 144.72 76.815 ;
     RECT  2.16 77.085 144.72 77.355 ;
     RECT  2.16 77.625 144.72 77.895 ;
     RECT  2.16 78.165 144.72 78.435 ;
     RECT  2.16 78.705 144.72 78.975 ;
     RECT  2.16 79.245 144.72 79.515 ;
     RECT  2.16 79.785 144.72 80.055 ;
     RECT  2.16 80.325 144.72 80.595 ;
     RECT  2.16 80.865 144.72 81.135 ;
     RECT  2.16 81.405 144.72 81.675 ;
     RECT  2.16 81.945 144.72 82.215 ;
     RECT  2.16 82.485 144.72 82.755 ;
     RECT  2.16 83.025 144.72 83.295 ;
     RECT  2.16 83.565 144.72 83.835 ;
     RECT  2.16 84.105 144.72 84.375 ;
     RECT  2.16 84.645 144.72 84.915 ;
     RECT  2.16 85.185 144.72 85.455 ;
     RECT  2.16 85.725 144.72 85.995 ;
     RECT  2.16 86.265 144.72 86.535 ;
     RECT  2.16 86.805 144.72 87.075 ;
     RECT  2.16 87.345 144.72 87.615 ;
     RECT  2.16 87.885 144.72 88.155 ;
     RECT  2.16 88.425 144.72 88.695 ;
     RECT  2.16 88.965 144.72 89.235 ;
     RECT  2.16 89.505 144.72 89.64 ;
    LAYER RVTP ;
     RECT  2.16 2.295 144.72 2.565 ;
     RECT  2.16 2.835 144.72 3.105 ;
     RECT  2.16 3.375 144.72 3.645 ;
     RECT  2.16 3.915 144.72 4.185 ;
     RECT  2.16 4.455 144.72 4.725 ;
     RECT  2.16 4.995 144.72 5.265 ;
     RECT  2.16 5.535 144.72 5.805 ;
     RECT  2.16 6.075 144.72 6.345 ;
     RECT  2.16 6.615 144.72 6.885 ;
     RECT  2.16 7.155 144.72 7.425 ;
     RECT  2.16 7.695 144.72 7.965 ;
     RECT  2.16 8.235 144.72 8.505 ;
     RECT  2.16 8.775 144.72 9.045 ;
     RECT  2.16 9.315 144.72 9.585 ;
     RECT  2.16 9.855 144.72 10.125 ;
     RECT  2.16 10.395 144.72 10.665 ;
     RECT  2.16 10.935 144.72 11.205 ;
     RECT  2.16 11.475 144.72 11.745 ;
     RECT  2.16 12.015 144.72 12.285 ;
     RECT  2.16 12.555 144.72 12.825 ;
     RECT  2.16 13.095 144.72 13.365 ;
     RECT  2.16 13.635 144.72 13.905 ;
     RECT  2.16 14.175 144.72 14.445 ;
     RECT  2.16 14.715 144.72 14.985 ;
     RECT  2.16 15.255 144.72 15.525 ;
     RECT  2.16 15.795 144.72 16.065 ;
     RECT  2.16 16.335 144.72 16.605 ;
     RECT  2.16 16.875 144.72 17.145 ;
     RECT  2.16 17.415 144.72 17.685 ;
     RECT  2.16 17.955 144.72 18.225 ;
     RECT  2.16 18.495 144.72 18.765 ;
     RECT  2.16 19.035 144.72 19.305 ;
     RECT  2.16 19.575 144.72 19.845 ;
     RECT  2.16 20.115 144.72 20.385 ;
     RECT  2.16 20.655 144.72 20.925 ;
     RECT  2.16 21.195 144.72 21.465 ;
     RECT  2.16 21.735 144.72 22.005 ;
     RECT  2.16 22.275 144.72 22.545 ;
     RECT  2.16 22.815 144.72 23.085 ;
     RECT  2.16 23.355 144.72 23.625 ;
     RECT  2.16 23.895 24.732 24.165 ;
     RECT  123.66 23.895 144.72 24.165 ;
     RECT  2.16 24.435 24.732 24.705 ;
     RECT  123.66 24.435 144.72 24.705 ;
     RECT  2.16 24.975 24.732 25.245 ;
     RECT  123.66 24.975 144.72 25.245 ;
     RECT  2.16 25.515 24.732 25.785 ;
     RECT  123.66 25.515 144.72 25.785 ;
     RECT  2.16 26.055 24.732 26.325 ;
     RECT  123.66 26.055 144.72 26.325 ;
     RECT  2.16 26.595 24.732 26.865 ;
     RECT  123.66 26.595 144.72 26.865 ;
     RECT  2.16 27.135 24.732 27.405 ;
     RECT  123.66 27.135 144.72 27.405 ;
     RECT  2.16 27.675 24.732 27.945 ;
     RECT  123.66 27.675 144.72 27.945 ;
     RECT  2.16 28.215 24.732 28.485 ;
     RECT  123.66 28.215 144.72 28.485 ;
     RECT  2.16 28.755 24.732 29.025 ;
     RECT  123.66 28.755 144.72 29.025 ;
     RECT  2.16 29.295 24.732 29.565 ;
     RECT  123.66 29.295 144.72 29.565 ;
     RECT  2.16 29.835 24.732 30.105 ;
     RECT  123.66 29.835 144.72 30.105 ;
     RECT  2.16 30.375 24.732 30.645 ;
     RECT  123.66 30.375 144.72 30.645 ;
     RECT  2.16 30.915 24.732 31.185 ;
     RECT  123.66 30.915 144.72 31.185 ;
     RECT  2.16 31.455 24.732 31.725 ;
     RECT  123.66 31.455 144.72 31.725 ;
     RECT  2.16 31.995 24.732 32.265 ;
     RECT  123.66 31.995 144.72 32.265 ;
     RECT  2.16 32.535 24.732 32.805 ;
     RECT  123.66 32.535 144.72 32.805 ;
     RECT  2.16 33.075 24.732 33.345 ;
     RECT  123.66 33.075 144.72 33.345 ;
     RECT  2.16 33.615 24.732 33.885 ;
     RECT  123.66 33.615 144.72 33.885 ;
     RECT  2.16 34.155 24.732 34.425 ;
     RECT  123.66 34.155 144.72 34.425 ;
     RECT  2.16 34.695 24.732 34.965 ;
     RECT  123.66 34.695 144.72 34.965 ;
     RECT  2.16 35.235 24.732 35.505 ;
     RECT  123.66 35.235 144.72 35.505 ;
     RECT  2.16 35.775 24.732 36.045 ;
     RECT  123.66 35.775 144.72 36.045 ;
     RECT  2.16 36.315 24.732 36.585 ;
     RECT  123.66 36.315 144.72 36.585 ;
     RECT  2.16 36.855 24.732 37.125 ;
     RECT  123.66 36.855 144.72 37.125 ;
     RECT  2.16 37.395 24.732 37.665 ;
     RECT  123.66 37.395 144.72 37.665 ;
     RECT  2.16 37.935 24.732 38.205 ;
     RECT  123.66 37.935 144.72 38.205 ;
     RECT  2.16 38.475 24.732 38.745 ;
     RECT  123.66 38.475 144.72 38.745 ;
     RECT  2.16 39.015 24.732 39.285 ;
     RECT  123.66 39.015 144.72 39.285 ;
     RECT  2.16 39.555 24.732 39.825 ;
     RECT  123.66 39.555 144.72 39.825 ;
     RECT  2.16 40.095 24.732 40.365 ;
     RECT  123.66 40.095 144.72 40.365 ;
     RECT  2.16 40.635 24.732 40.905 ;
     RECT  123.66 40.635 144.72 40.905 ;
     RECT  2.16 41.175 24.732 41.445 ;
     RECT  123.66 41.175 144.72 41.445 ;
     RECT  2.16 41.715 24.732 41.985 ;
     RECT  123.66 41.715 144.72 41.985 ;
     RECT  2.16 42.255 24.732 42.525 ;
     RECT  123.66 42.255 144.72 42.525 ;
     RECT  2.16 42.795 24.732 43.065 ;
     RECT  123.66 42.795 144.72 43.065 ;
     RECT  2.16 43.335 24.732 43.605 ;
     RECT  123.66 43.335 144.72 43.605 ;
     RECT  2.16 43.875 24.732 44.145 ;
     RECT  123.66 43.875 144.72 44.145 ;
     RECT  2.16 44.415 24.732 44.685 ;
     RECT  123.66 44.415 144.72 44.685 ;
     RECT  2.16 44.955 24.732 45.225 ;
     RECT  123.66 44.955 144.72 45.225 ;
     RECT  2.16 45.495 24.732 45.765 ;
     RECT  123.66 45.495 144.72 45.765 ;
     RECT  2.16 46.035 24.732 46.305 ;
     RECT  123.66 46.035 144.72 46.305 ;
     RECT  2.16 46.575 24.732 46.845 ;
     RECT  123.66 46.575 144.72 46.845 ;
     RECT  2.16 47.115 24.732 47.385 ;
     RECT  123.66 47.115 144.72 47.385 ;
     RECT  2.16 47.655 24.732 47.925 ;
     RECT  123.66 47.655 144.72 47.925 ;
     RECT  2.16 48.195 24.732 48.465 ;
     RECT  123.66 48.195 144.72 48.465 ;
     RECT  2.16 48.735 24.732 49.005 ;
     RECT  123.66 48.735 144.72 49.005 ;
     RECT  2.16 49.275 24.732 49.545 ;
     RECT  123.66 49.275 144.72 49.545 ;
     RECT  2.16 49.815 24.732 50.085 ;
     RECT  123.66 49.815 144.72 50.085 ;
     RECT  2.16 50.355 24.732 50.625 ;
     RECT  123.66 50.355 144.72 50.625 ;
     RECT  2.16 50.895 24.732 51.165 ;
     RECT  123.66 50.895 144.72 51.165 ;
     RECT  2.16 51.435 24.732 51.705 ;
     RECT  123.66 51.435 144.72 51.705 ;
     RECT  2.16 51.975 24.732 52.245 ;
     RECT  123.66 51.975 144.72 52.245 ;
     RECT  2.16 52.515 24.732 52.785 ;
     RECT  123.66 52.515 144.72 52.785 ;
     RECT  2.16 53.055 24.732 53.325 ;
     RECT  123.66 53.055 144.72 53.325 ;
     RECT  2.16 53.595 24.732 53.865 ;
     RECT  123.66 53.595 144.72 53.865 ;
     RECT  2.16 54.135 24.732 54.405 ;
     RECT  123.66 54.135 144.72 54.405 ;
     RECT  2.16 54.675 24.732 54.945 ;
     RECT  123.66 54.675 144.72 54.945 ;
     RECT  2.16 55.215 24.732 55.485 ;
     RECT  123.66 55.215 144.72 55.485 ;
     RECT  2.16 55.755 24.732 56.025 ;
     RECT  123.66 55.755 144.72 56.025 ;
     RECT  2.16 56.295 24.732 56.565 ;
     RECT  123.66 56.295 144.72 56.565 ;
     RECT  2.16 56.835 24.732 57.105 ;
     RECT  123.66 56.835 144.72 57.105 ;
     RECT  2.16 57.375 24.732 57.645 ;
     RECT  123.66 57.375 144.72 57.645 ;
     RECT  2.16 57.915 24.732 58.185 ;
     RECT  123.66 57.915 144.72 58.185 ;
     RECT  2.16 58.455 24.732 58.725 ;
     RECT  123.66 58.455 144.72 58.725 ;
     RECT  2.16 58.995 24.732 59.265 ;
     RECT  123.66 58.995 144.72 59.265 ;
     RECT  2.16 59.535 24.732 59.805 ;
     RECT  123.66 59.535 144.72 59.805 ;
     RECT  2.16 60.075 24.732 60.345 ;
     RECT  123.66 60.075 144.72 60.345 ;
     RECT  2.16 60.615 24.732 60.885 ;
     RECT  123.66 60.615 144.72 60.885 ;
     RECT  2.16 61.155 24.732 61.425 ;
     RECT  123.66 61.155 144.72 61.425 ;
     RECT  2.16 61.695 24.732 61.965 ;
     RECT  123.66 61.695 144.72 61.965 ;
     RECT  2.16 62.235 24.732 62.505 ;
     RECT  123.66 62.235 144.72 62.505 ;
     RECT  2.16 62.775 24.732 63.045 ;
     RECT  123.66 62.775 144.72 63.045 ;
     RECT  2.16 63.315 24.732 63.585 ;
     RECT  123.66 63.315 144.72 63.585 ;
     RECT  2.16 63.855 24.732 64.125 ;
     RECT  123.66 63.855 144.72 64.125 ;
     RECT  2.16 64.395 24.732 64.665 ;
     RECT  123.66 64.395 144.72 64.665 ;
     RECT  2.16 64.935 24.732 65.205 ;
     RECT  123.66 64.935 144.72 65.205 ;
     RECT  2.16 65.475 24.732 65.745 ;
     RECT  123.66 65.475 144.72 65.745 ;
     RECT  2.16 66.015 24.732 66.285 ;
     RECT  123.66 66.015 144.72 66.285 ;
     RECT  2.16 66.555 24.732 66.825 ;
     RECT  123.66 66.555 144.72 66.825 ;
     RECT  2.16 67.095 24.732 67.365 ;
     RECT  123.66 67.095 144.72 67.365 ;
     RECT  2.16 67.635 24.732 67.905 ;
     RECT  123.66 67.635 144.72 67.905 ;
     RECT  2.16 68.175 24.732 68.445 ;
     RECT  123.66 68.175 144.72 68.445 ;
     RECT  2.16 68.715 24.732 68.985 ;
     RECT  123.66 68.715 144.72 68.985 ;
     RECT  2.16 69.255 144.72 69.525 ;
     RECT  2.16 69.795 144.72 70.065 ;
     RECT  2.16 70.335 144.72 70.605 ;
     RECT  2.16 70.875 144.72 71.145 ;
     RECT  2.16 71.415 144.72 71.685 ;
     RECT  2.16 71.955 144.72 72.225 ;
     RECT  2.16 72.495 144.72 72.765 ;
     RECT  2.16 73.035 144.72 73.305 ;
     RECT  2.16 73.575 144.72 73.845 ;
     RECT  2.16 74.115 144.72 74.385 ;
     RECT  2.16 74.655 144.72 74.925 ;
     RECT  2.16 75.195 144.72 75.465 ;
     RECT  2.16 75.735 144.72 76.005 ;
     RECT  2.16 76.275 144.72 76.545 ;
     RECT  2.16 76.815 144.72 77.085 ;
     RECT  2.16 77.355 144.72 77.625 ;
     RECT  2.16 77.895 144.72 78.165 ;
     RECT  2.16 78.435 144.72 78.705 ;
     RECT  2.16 78.975 144.72 79.245 ;
     RECT  2.16 79.515 144.72 79.785 ;
     RECT  2.16 80.055 144.72 80.325 ;
     RECT  2.16 80.595 144.72 80.865 ;
     RECT  2.16 81.135 144.72 81.405 ;
     RECT  2.16 81.675 144.72 81.945 ;
     RECT  2.16 82.215 144.72 82.485 ;
     RECT  2.16 82.755 144.72 83.025 ;
     RECT  2.16 83.295 144.72 83.565 ;
     RECT  2.16 83.835 144.72 84.105 ;
     RECT  2.16 84.375 144.72 84.645 ;
     RECT  2.16 84.915 144.72 85.185 ;
     RECT  2.16 85.455 144.72 85.725 ;
     RECT  2.16 85.995 144.72 86.265 ;
     RECT  2.16 86.535 144.72 86.805 ;
     RECT  2.16 87.075 144.72 87.345 ;
     RECT  2.16 87.615 144.72 87.885 ;
     RECT  2.16 88.155 144.72 88.425 ;
     RECT  2.16 88.695 144.72 88.965 ;
     RECT  2.16 89.235 144.72 89.505 ;
    LAYER M1 ;
     RECT  2.16 2.151 144.72 23.769 ;
     RECT  26.784 25.92 121.608 66.984 ;
     RECT  2.16 23.769 24.732 69.111 ;
     RECT  123.66 23.769 144.72 69.111 ;
     RECT  2.16 69.111 144.72 89.649 ;
    LAYER M2 ;
     RECT  2.16 2.151 5.647 89.649 ;
     RECT  5.647 2.106 5.855 89.649 ;
     RECT  5.855 2.151 7.807 89.649 ;
     RECT  7.807 1.728 7.979 89.649 ;
     RECT  7.979 2.151 8.887 89.649 ;
     RECT  8.887 2.106 10.391 89.649 ;
     RECT  10.391 2.151 12.127 89.649 ;
     RECT  12.127 1.728 12.335 89.649 ;
     RECT  12.335 2.151 13.207 89.649 ;
     RECT  13.207 1.728 14.819 89.649 ;
     RECT  14.819 2.151 16.447 89.649 ;
     RECT  16.447 2.106 17.771 89.649 ;
     RECT  17.771 2.151 18.607 89.649 ;
     RECT  18.607 2.07 19.687 89.649 ;
     RECT  19.687 1.728 19.931 89.649 ;
     RECT  19.931 2.151 21.847 89.649 ;
     RECT  21.847 1.728 22.199 89.649 ;
     RECT  22.199 2.151 22.927 89.649 ;
     RECT  22.927 1.728 23.171 89.649 ;
     RECT  23.171 2.151 24.007 89.649 ;
     RECT  24.007 1.728 24.179 89.649 ;
     RECT  24.179 2.151 24.732 89.649 ;
     RECT  24.732 2.151 24.791 31.482 ;
     RECT  24.732 34.056 24.791 34.182 ;
     RECT  24.732 62.208 24.791 62.226 ;
     RECT  24.732 42.192 24.863 42.21 ;
     RECT  24.732 45.306 24.899 45.324 ;
     RECT  24.732 66.636 25.079 89.649 ;
     RECT  24.791 2.151 25.087 30.636 ;
     RECT  25.087 2.106 25.115 30.636 ;
     RECT  24.732 36.558 25.115 39.204 ;
     RECT  24.732 57.276 25.295 58.986 ;
     RECT  24.791 31.464 25.331 31.482 ;
     RECT  24.732 44.226 25.367 44.244 ;
     RECT  24.732 40.032 25.403 41.094 ;
     RECT  25.115 36.864 25.483 39.204 ;
     RECT  25.403 40.032 25.483 40.734 ;
     RECT  24.732 60.696 25.547 60.714 ;
     RECT  24.732 52.722 25.555 52.812 ;
     RECT  24.732 63.054 25.555 63.072 ;
     RECT  25.483 36.864 25.583 40.734 ;
     RECT  25.115 29.916 25.619 30.636 ;
     RECT  25.583 36.864 25.619 39.204 ;
     RECT  25.555 50.751 25.655 50.769 ;
     RECT  25.555 52.722 25.655 52.884 ;
     RECT  25.555 63.054 25.655 63.189 ;
     RECT  25.619 36.864 25.691 38.934 ;
     RECT  25.583 40.032 25.691 40.734 ;
     RECT  25.619 30.618 25.735 30.636 ;
     RECT  24.732 64.791 25.763 64.809 ;
     RECT  25.295 58.968 25.799 58.986 ;
     RECT  25.115 2.106 25.871 29.016 ;
     RECT  25.871 2.106 25.907 28.512 ;
     RECT  25.907 2.106 25.943 27.162 ;
     RECT  25.907 28.026 25.943 28.512 ;
     RECT  25.295 57.276 25.951 58.176 ;
     RECT  24.732 49.284 25.979 49.302 ;
     RECT  25.951 56.961 26.015 58.176 ;
     RECT  25.735 30.618 26.051 30.789 ;
     RECT  24.791 34.164 26.051 34.182 ;
     RECT  25.951 56.151 26.051 56.169 ;
     RECT  26.095 0.144 26.195 0.162 ;
     RECT  25.943 2.106 26.195 27.009 ;
     RECT  26.195 2.151 26.784 27.009 ;
     RECT  25.943 28.026 26.784 28.044 ;
     RECT  26.051 30.69 26.784 30.789 ;
     RECT  25.691 36.864 26.784 36.882 ;
     RECT  25.691 37.836 26.784 38.934 ;
     RECT  25.691 40.716 26.784 40.734 ;
     RECT  26.015 57.582 26.784 58.176 ;
     RECT  26.311 60.354 26.784 60.372 ;
     RECT  25.655 63.054 26.784 63.072 ;
     RECT  25.771 63.936 26.784 63.954 ;
     RECT  25.079 67.032 26.784 89.649 ;
     RECT  26.784 2.151 27.247 89.649 ;
     RECT  27.247 2.106 27.707 89.649 ;
     RECT  29.407 0.144 29.579 0.162 ;
     RECT  27.707 2.151 30.487 89.649 ;
     RECT  30.487 1.728 30.731 89.649 ;
     RECT  30.731 2.151 34.195 89.649 ;
     RECT  34.195 2.106 34.807 89.649 ;
     RECT  34.807 1.728 34.979 89.649 ;
     RECT  34.979 2.151 35.815 89.649 ;
     RECT  35.815 0.144 35.915 0.162 ;
     RECT  35.815 2.106 37.319 89.649 ;
     RECT  37.319 2.151 38.047 89.649 ;
     RECT  38.047 1.728 38.183 89.649 ;
     RECT  40.207 0.144 40.379 0.162 ;
     RECT  38.183 2.151 42.367 89.649 ;
     RECT  42.367 1.728 42.575 89.649 ;
     RECT  42.575 2.151 45.715 89.649 ;
     RECT  45.607 0.144 45.779 0.162 ;
     RECT  45.715 2.151 45.815 89.766 ;
     RECT  45.815 2.151 46.687 89.649 ;
     RECT  46.687 2.106 46.895 89.649 ;
     RECT  46.895 2.151 50.935 89.649 ;
     RECT  50.935 2.151 51.035 89.73 ;
     RECT  51.007 0.144 51.179 0.162 ;
     RECT  51.035 2.151 52.087 89.649 ;
     RECT  52.087 1.728 52.403 89.649 ;
     RECT  52.403 2.151 54.247 89.649 ;
     RECT  54.247 1.728 54.455 89.649 ;
     RECT  54.455 2.151 55.327 89.649 ;
     RECT  55.327 1.728 55.535 89.649 ;
     RECT  55.535 2.151 56.407 89.649 ;
     RECT  56.407 2.07 56.759 89.649 ;
     RECT  56.759 2.151 57.487 89.649 ;
     RECT  57.487 2.106 58.919 89.649 ;
     RECT  58.919 2.151 59.647 89.649 ;
     RECT  59.647 2.106 59.999 89.649 ;
     RECT  59.999 2.151 61.807 89.649 ;
     RECT  61.807 1.728 62.051 89.649 ;
     RECT  62.051 2.151 62.887 89.649 ;
     RECT  62.887 1.728 63.203 89.649 ;
     RECT  63.203 2.151 63.967 89.649 ;
     RECT  63.967 1.728 64.211 89.649 ;
     RECT  64.211 2.151 65.047 89.649 ;
     RECT  65.047 1.728 65.363 89.649 ;
     RECT  65.363 2.151 66.127 89.649 ;
     RECT  66.127 1.728 66.695 89.649 ;
     RECT  66.695 2.07 67.631 89.649 ;
     RECT  67.631 2.106 68.711 89.649 ;
     RECT  68.711 2.151 70.447 89.649 ;
     RECT  70.447 2.106 71.527 89.649 ;
     RECT  71.527 1.728 71.735 89.649 ;
     RECT  72.607 0.144 72.779 0.162 ;
     RECT  71.735 2.151 75.847 89.649 ;
     RECT  75.847 1.728 76.055 89.649 ;
     RECT  76.055 2.151 76.927 89.649 ;
     RECT  76.927 2.106 78.007 89.649 ;
     RECT  78.007 2.07 78.215 89.649 ;
     RECT  78.215 2.151 79.087 89.649 ;
     RECT  79.087 2.106 79.439 89.649 ;
     RECT  79.439 2.151 80.167 89.649 ;
     RECT  80.167 2.106 80.483 89.649 ;
     RECT  80.483 2.151 82.327 89.649 ;
     RECT  82.327 1.728 82.643 89.649 ;
     RECT  82.643 2.151 83.407 89.649 ;
     RECT  83.407 2.07 84.487 89.649 ;
     RECT  84.487 1.728 84.803 89.649 ;
     RECT  84.803 2.151 85.163 89.649 ;
     RECT  85.163 2.151 85.567 23.922 ;
     RECT  85.567 1.728 85.811 23.922 ;
     RECT  85.811 2.151 86.351 23.922 ;
     RECT  88.735 0.144 88.835 0.162 ;
     RECT  86.351 2.151 91.147 23.814 ;
     RECT  91.147 2.151 91.327 23.85 ;
     RECT  85.163 24.786 91.327 89.649 ;
     RECT  91.327 2.151 94.171 89.649 ;
     RECT  94.171 2.151 94.207 89.73 ;
     RECT  94.207 2.07 94.307 89.73 ;
     RECT  94.307 2.07 95.099 89.649 ;
     RECT  95.099 2.151 96.367 89.649 ;
     RECT  96.367 1.728 96.827 89.649 ;
     RECT  96.827 2.106 97.655 89.649 ;
     RECT  97.655 2.151 98.527 89.649 ;
     RECT  98.527 2.106 99.167 89.649 ;
     RECT  99.535 0.144 99.635 0.162 ;
     RECT  99.167 2.151 103.927 89.649 ;
     RECT  103.927 1.728 104.243 89.649 ;
     RECT  104.243 2.151 105.007 89.649 ;
     RECT  105.007 1.728 105.323 89.649 ;
     RECT  105.323 2.151 108.247 89.649 ;
     RECT  108.247 2.106 108.599 89.649 ;
     RECT  108.599 2.151 109.327 89.649 ;
     RECT  109.327 2.106 110.407 89.649 ;
     RECT  110.407 2.07 110.831 89.649 ;
     RECT  110.831 2.151 113.647 89.649 ;
     RECT  113.647 1.728 113.999 89.649 ;
     RECT  113.999 2.151 115.807 89.649 ;
     RECT  115.807 1.728 116.123 89.649 ;
     RECT  116.123 2.151 117.895 89.649 ;
     RECT  117.895 0.144 117.995 0.162 ;
     RECT  117.895 2.106 118.319 89.649 ;
     RECT  118.319 2.151 120.127 89.649 ;
     RECT  120.127 2.106 121.207 89.649 ;
     RECT  121.207 1.728 121.379 89.649 ;
     RECT  121.379 2.151 121.608 89.649 ;
     RECT  121.608 36.594 121.955 36.684 ;
     RECT  121.608 2.151 122.287 25.884 ;
     RECT  121.608 30.114 122.467 34.884 ;
     RECT  121.955 36.666 122.467 36.684 ;
     RECT  122.359 26.802 122.495 26.82 ;
     RECT  122.467 29.808 122.503 34.884 ;
     RECT  121.608 40.032 122.539 65.844 ;
     RECT  121.608 67.032 122.539 89.649 ;
     RECT  122.539 40.032 122.575 66.006 ;
     RECT  122.539 66.834 122.575 89.649 ;
     RECT  122.287 2.106 122.791 25.884 ;
     RECT  122.359 27.612 122.791 27.63 ;
     RECT  122.503 29.808 122.791 35.424 ;
     RECT  122.791 27.612 122.863 27.774 ;
     RECT  122.791 29.808 122.935 35.874 ;
     RECT  122.791 2.106 123.071 26.514 ;
     RECT  121.608 38.214 123.115 39.204 ;
     RECT  122.575 40.032 123.115 89.649 ;
     RECT  122.935 29.07 123.511 35.874 ;
     RECT  123.071 2.151 123.66 26.514 ;
     RECT  122.863 27.576 123.66 27.774 ;
     RECT  123.511 28.926 123.66 35.874 ;
     RECT  122.467 36.666 123.66 37.224 ;
     RECT  123.115 38.214 123.66 89.649 ;
     RECT  124.447 0.144 124.547 0.162 ;
     RECT  126.607 0.144 126.779 0.162 ;
     RECT  123.66 2.151 128.767 89.649 ;
     RECT  128.767 2.106 130.055 89.649 ;
     RECT  130.055 2.151 130.927 89.649 ;
     RECT  130.927 2.106 131.899 89.649 ;
     RECT  131.899 1.728 132.035 89.649 ;
     RECT  132.035 2.151 133.087 89.649 ;
     RECT  133.087 2.106 133.547 89.649 ;
     RECT  133.547 2.151 135.247 89.649 ;
     RECT  135.247 2.106 136.327 89.649 ;
     RECT  136.327 1.728 136.535 89.649 ;
     RECT  136.535 2.151 137.407 89.649 ;
     RECT  137.407 1.728 137.939 89.649 ;
     RECT  137.939 2.151 141.727 89.649 ;
     RECT  141.727 2.106 142.043 89.649 ;
     RECT  142.043 2.151 144.72 89.649 ;
    LAYER M3 ;
     RECT  29.556 0.167 29.574 0.187 ;
     RECT  40.356 0.167 40.374 0.571 ;
     RECT  41.292 0.187 42.39 0.571 ;
     RECT  54.252 0.187 55.35 0.571 ;
     RECT  81.252 0.187 83.43 0.571 ;
     RECT  115.596 0.187 115.83 0.571 ;
     RECT  125.532 0.187 127.71 0.571 ;
     RECT  17.532 0.187 18.63 1.147 ;
     RECT  26.1 0.167 26.118 1.147 ;
     RECT  29.556 0.187 30.51 1.147 ;
     RECT  38.052 0.187 39.15 1.147 ;
     RECT  40.356 0.571 42.39 1.147 ;
     RECT  46.548 0.187 47.79 1.147 ;
     RECT  49.932 0.187 52.11 1.147 ;
     RECT  54.252 0.571 56.43 1.147 ;
     RECT  61.812 0.187 62.91 1.147 ;
     RECT  63.972 0.187 66.15 1.147 ;
     RECT  68.292 0.187 69.39 1.147 ;
     RECT  72.756 0.167 72.774 1.147 ;
     RECT  75.744 0.187 75.87 1.147 ;
     RECT  79.092 0.187 80.19 1.147 ;
     RECT  81.252 0.571 84.51 1.147 ;
     RECT  87.588 0.187 87.75 1.147 ;
     RECT  88.74 0.187 89.91 1.147 ;
     RECT  90.972 0.187 95.31 1.147 ;
     RECT  101.772 0.187 107.19 1.147 ;
     RECT  110.412 0.571 111.51 1.147 ;
     RECT  112.572 0.187 113.67 1.147 ;
     RECT  121.212 0.187 122.31 1.147 ;
     RECT  124.524 0.167 124.542 1.147 ;
     RECT  130.932 0.571 132.03 1.147 ;
     RECT  140.652 0.187 142.29 1.147 ;
     RECT  6.408 1.147 7.83 1.723 ;
     RECT  8.64 1.147 8.91 1.723 ;
     RECT  12.024 1.147 12.15 1.723 ;
     RECT  12.888 0.187 13.23 1.723 ;
     RECT  13.968 0.187 14.31 1.723 ;
     RECT  15.12 0.187 15.39 1.723 ;
     RECT  19.656 1.147 19.71 1.723 ;
     RECT  20.628 1.147 20.79 1.723 ;
     RECT  21.852 0.187 22.95 1.723 ;
     RECT  23.796 0.187 24.03 1.723 ;
     RECT  24.84 0.187 25.11 1.723 ;
     RECT  29.376 1.147 30.51 1.723 ;
     RECT  31.248 0.187 32.67 1.723 ;
     RECT  33.732 0.187 34.83 1.723 ;
     RECT  40.104 1.147 42.39 1.723 ;
     RECT  49.608 1.147 52.11 1.723 ;
     RECT  53.028 1.147 53.19 1.723 ;
     RECT  61.704 1.147 62.91 1.723 ;
     RECT  63.936 1.147 66.15 1.723 ;
     RECT  68.04 1.147 69.39 1.723 ;
     RECT  71.208 0.187 71.55 1.723 ;
     RECT  72.396 1.147 72.774 1.723 ;
     RECT  74.772 1.147 75.87 1.723 ;
     RECT  80.964 1.147 84.51 1.723 ;
     RECT  85.536 1.147 85.59 1.723 ;
     RECT  86.508 0.187 86.67 1.723 ;
     RECT  99.54 0.167 99.558 1.723 ;
     RECT  100.476 1.147 100.71 1.723 ;
     RECT  109.08 1.147 109.35 1.723 ;
     RECT  112.356 1.147 113.67 1.723 ;
     RECT  114.516 0.187 114.75 1.723 ;
     RECT  119.916 1.147 120.15 1.723 ;
     RECT  136.116 0.187 136.35 1.723 ;
     RECT  137.196 0.187 137.43 1.723 ;
     RECT  138.24 0.187 138.51 1.723 ;
     RECT  12.024 1.723 15.39 1.751 ;
     RECT  21.852 1.723 25.11 1.751 ;
     RECT  49.608 1.723 53.19 1.751 ;
     RECT  17.496 1.147 18.63 2.065 ;
     RECT  19.656 1.723 20.79 2.065 ;
     RECT  77.868 1.147 78.03 2.065 ;
     RECT  78.876 1.147 80.19 2.065 ;
     RECT  4.572 0.187 5.67 2.101 ;
     RECT  6.408 1.723 8.91 2.101 ;
     RECT  9.828 1.147 9.99 2.101 ;
     RECT  10.836 1.147 11.07 2.101 ;
     RECT  16.2 1.147 16.47 2.101 ;
     RECT  17.496 2.065 20.79 2.101 ;
     RECT  25.848 1.147 26.118 2.101 ;
     RECT  26.928 1.147 27.27 2.101 ;
     RECT  28.188 1.147 28.35 2.101 ;
     RECT  36.936 1.147 39.15 2.101 ;
     RECT  54.144 1.147 57.51 2.101 ;
     RECT  58.572 0.187 59.67 2.101 ;
     RECT  60.48 1.147 60.75 2.101 ;
     RECT  70.416 1.147 70.47 2.101 ;
     RECT  71.208 1.723 72.774 2.101 ;
     RECT  76.932 1.147 76.986 2.101 ;
     RECT  77.868 2.065 80.19 2.101 ;
     RECT  80.964 1.723 84.798 2.101 ;
     RECT  96.228 0.187 97.47 2.101 ;
     RECT  98.424 1.147 98.55 2.101 ;
     RECT  99.54 1.723 100.71 2.101 ;
     RECT  108.252 1.723 109.35 2.101 ;
     RECT  110.268 1.147 111.51 2.101 ;
     RECT  119.052 1.723 120.15 2.101 ;
     RECT  120.996 1.147 122.31 2.101 ;
     RECT  123.336 1.147 123.39 2.101 ;
     RECT  128.556 0.187 128.79 2.101 ;
     RECT  129.744 1.147 132.03 2.101 ;
     RECT  132.984 1.147 133.11 2.101 ;
     RECT  133.956 1.147 134.19 2.101 ;
     RECT  135 0.187 135.27 2.101 ;
     RECT  136.116 1.723 138.51 2.101 ;
     RECT  16.2 2.101 20.79 2.129 ;
     RECT  128.556 2.101 132.03 2.143 ;
     RECT  140.544 1.147 142.29 2.143 ;
     RECT  4.572 2.101 11.07 2.191 ;
     RECT  21.924 1.751 25.11 2.191 ;
     RECT  25.848 2.101 26.19 2.191 ;
     RECT  26.928 2.101 28.35 2.191 ;
     RECT  43.344 1.147 43.47 2.191 ;
     RECT  44.28 0.187 44.55 2.191 ;
     RECT  52.38 1.751 53.19 2.191 ;
     RECT  54.144 2.101 60.75 2.191 ;
     RECT  61.704 1.723 63.198 2.191 ;
     RECT  63.936 1.723 69.39 2.191 ;
     RECT  74.772 1.723 76.05 2.191 ;
     RECT  76.932 2.101 84.798 2.191 ;
     RECT  85.536 1.723 86.67 2.191 ;
     RECT  96.228 2.101 97.65 2.191 ;
     RECT  98.424 2.101 100.71 2.191 ;
     RECT  128.556 2.143 132.105 2.191 ;
     RECT  132.984 2.101 134.19 2.191 ;
     RECT  135 2.101 138.51 2.191 ;
     RECT  125.316 0.571 127.71 2.218 ;
     RECT  4.572 2.191 11.142 2.219 ;
     RECT  16.2 2.129 16.362 2.219 ;
     RECT  33.732 1.723 34.974 2.219 ;
     RECT  35.82 2.101 39.15 2.219 ;
     RECT  40.104 1.723 42.57 2.219 ;
     RECT  61.704 2.191 69.39 2.219 ;
     RECT  74.772 2.191 86.85 2.219 ;
     RECT  96.084 2.191 100.71 2.219 ;
     RECT  101.556 1.147 107.19 2.219 ;
     RECT  40.104 2.219 41.67 2.227 ;
     RECT  101.556 2.219 106.038 2.227 ;
     RECT  112.356 1.723 114.75 2.227 ;
     RECT  140.544 2.143 142.905 2.227 ;
     RECT  21.924 2.191 28.35 2.263 ;
     RECT  33.876 2.219 34.974 2.263 ;
     RECT  35.82 2.219 38.502 2.263 ;
     RECT  43.344 2.191 44.55 2.263 ;
     RECT  46.548 1.147 48.87 2.263 ;
     RECT  49.608 1.751 51.642 2.263 ;
     RECT  52.38 2.191 60.75 2.263 ;
     RECT  61.704 2.219 62.73 2.263 ;
     RECT  73.584 1.147 73.71 2.263 ;
     RECT  74.772 2.219 81.846 2.263 ;
     RECT  86.652 2.219 86.85 2.263 ;
     RECT  87.588 1.147 89.91 2.263 ;
     RECT  90.828 1.147 95.31 2.263 ;
     RECT  96.084 2.219 97.254 2.263 ;
     RECT  98.064 2.219 100.71 2.263 ;
     RECT  101.448 2.227 106.038 2.263 ;
     RECT  106.776 2.219 107.19 2.263 ;
     RECT  108.252 2.101 111.51 2.263 ;
     RECT  112.248 2.227 114.75 2.263 ;
     RECT  128.556 2.191 138.51 2.263 ;
     RECT  139.248 1.147 139.59 2.263 ;
     RECT  106.776 2.263 107.262 2.291 ;
     RECT  119.052 2.101 122.31 2.291 ;
     RECT  5.256 2.219 11.142 2.335 ;
     RECT  12.024 1.751 13.986 2.335 ;
     RECT  14.76 1.751 15.39 2.335 ;
     RECT  70.416 2.101 72.774 2.335 ;
     RECT  120.276 2.291 122.31 2.335 ;
     RECT  123.048 2.101 123.39 2.335 ;
     RECT  29.376 1.723 32.67 2.371 ;
     RECT  40.032 2.227 41.67 2.371 ;
     RECT  42.732 2.263 44.55 2.371 ;
     RECT  45.468 0.571 45.774 2.371 ;
     RECT  63.468 2.219 69.39 2.371 ;
     RECT  70.272 2.335 72.774 2.371 ;
     RECT  86.652 2.263 89.91 2.371 ;
     RECT  128.556 2.263 139.59 2.371 ;
     RECT  2.415 2.143 2.505 2.413 ;
     RECT  42.732 2.371 45.774 2.413 ;
     RECT  46.548 2.263 51.642 2.413 ;
     RECT  63.468 2.371 72.774 2.413 ;
     RECT  73.584 2.263 81.846 2.413 ;
     RECT  140.436 2.227 142.905 2.413 ;
     RECT  120.276 2.335 123.39 2.461 ;
     RECT  4.5 2.335 4.518 2.489 ;
     RECT  5.256 2.335 13.986 2.489 ;
     RECT  14.76 2.335 15.462 2.489 ;
     RECT  39.348 2.371 41.67 2.489 ;
     RECT  42.732 2.413 51.642 2.489 ;
     RECT  98.064 2.263 106.038 2.489 ;
     RECT  29.376 2.371 33.102 2.525 ;
     RECT  90.828 2.263 97.254 2.525 ;
     RECT  82.584 2.219 85.698 2.561 ;
     RECT  108.252 2.263 114.75 2.596 ;
     RECT  14.76 2.489 15.282 2.605 ;
     RECT  17.136 2.129 20.79 2.605 ;
     RECT  21.924 2.263 28.53 2.605 ;
     RECT  86.652 2.371 90.054 2.605 ;
     RECT  90.828 2.525 94.986 2.605 ;
     RECT  106.812 2.291 107.262 2.605 ;
     RECT  108.252 2.596 114.786 2.605 ;
     RECT  115.596 0.571 116.91 2.605 ;
     RECT  124.452 1.147 124.542 2.605 ;
     RECT  125.316 2.218 127.746 2.605 ;
     RECT  128.556 2.371 139.626 2.605 ;
     RECT  17.136 2.605 28.53 2.641 ;
     RECT  29.376 2.525 32.922 2.641 ;
     RECT  46.908 2.489 51.642 2.641 ;
     RECT  52.38 2.263 62.73 2.641 ;
     RECT  106.812 2.605 114.786 2.641 ;
     RECT  115.596 2.605 117.018 2.641 ;
     RECT  117.9 2.101 118.314 2.641 ;
     RECT  119.052 2.291 119.394 2.641 ;
     RECT  120.276 2.461 123.426 2.641 ;
     RECT  124.452 2.605 139.698 2.641 ;
     RECT  63.468 2.413 81.846 2.669 ;
     RECT  4.284 2.641 4.302 2.759 ;
     RECT  5.256 2.489 13.734 2.759 ;
     RECT  46.908 2.641 62.73 2.759 ;
     RECT  63.468 2.669 73.602 2.759 ;
     RECT  95.868 2.525 97.254 2.759 ;
     RECT  98.136 2.489 105.93 2.759 ;
     RECT  106.812 2.641 119.394 2.759 ;
     RECT  120.276 2.641 139.698 2.759 ;
     RECT  137.16 2.759 139.698 2.803 ;
     RECT  140.436 2.413 143.097 2.803 ;
     RECT  17.136 2.641 32.922 2.939 ;
     RECT  86.652 2.605 94.986 2.939 ;
     RECT  120.276 2.759 136.386 2.939 ;
     RECT  74.34 2.669 81.846 3.001 ;
     RECT  82.584 2.561 84.33 3.001 ;
     RECT  17.136 2.939 31.734 3.029 ;
     RECT  48.348 2.759 62.73 3.029 ;
     RECT  63.468 2.759 69.102 3.029 ;
     RECT  74.34 3.001 84.33 3.029 ;
     RECT  124.272 2.939 136.386 3.029 ;
     RECT  16.308 2.219 16.362 3.145 ;
     RECT  17.136 3.029 25.686 3.145 ;
     RECT  40.032 2.489 41.67 3.145 ;
     RECT  42.732 2.489 46.17 3.145 ;
     RECT  85.104 2.561 85.698 3.145 ;
     RECT  86.652 2.939 91.494 3.145 ;
     RECT  106.812 2.759 108.342 3.145 ;
     RECT  109.332 2.759 119.394 3.181 ;
     RECT  120.276 2.939 123.498 3.181 ;
     RECT  60.84 3.029 62.73 3.211 ;
     RECT  63.468 3.029 67.662 3.211 ;
     RECT  16.308 3.145 25.686 3.271 ;
     RECT  98.208 2.759 105.93 3.271 ;
     RECT  106.74 3.145 108.342 3.271 ;
     RECT  28.26 3.029 31.734 3.299 ;
     RECT  74.34 3.029 82.278 3.299 ;
     RECT  5.256 2.759 9.018 3.307 ;
     RECT  40.032 3.145 46.17 3.335 ;
     RECT  60.84 3.211 67.662 3.335 ;
     RECT  85.104 3.145 91.494 3.335 ;
     RECT  40.032 3.335 43.434 3.343 ;
     RECT  14.544 2.605 15.282 3.379 ;
     RECT  33.876 2.263 38.502 3.379 ;
     RECT  39.384 3.343 43.434 3.379 ;
     RECT  83.088 3.029 84.33 3.403 ;
     RECT  44.172 3.335 46.17 3.407 ;
     RECT  9.756 2.759 13.734 3.415 ;
     RECT  14.544 3.379 15.462 3.415 ;
     RECT  33.876 3.379 43.434 3.415 ;
     RECT  4.68 3.307 9.018 3.437 ;
     RECT  92.412 2.939 94.986 3.451 ;
     RECT  96.228 2.759 97.254 3.451 ;
     RECT  4.824 3.437 9.018 3.541 ;
     RECT  9.756 3.415 15.462 3.541 ;
     RECT  92.412 3.451 95.022 3.541 ;
     RECT  96.228 3.451 97.398 3.541 ;
     RECT  4.824 3.541 15.462 3.569 ;
     RECT  85.32 3.335 91.494 3.569 ;
     RECT  109.332 3.181 123.498 3.569 ;
     RECT  124.272 3.029 128.574 3.569 ;
     RECT  129.348 3.029 136.386 3.569 ;
     RECT  16.236 3.271 25.686 3.605 ;
     RECT  29.34 3.299 31.734 3.605 ;
     RECT  74.34 3.299 82.17 3.605 ;
     RECT  137.16 2.803 143.097 3.605 ;
     RECT  4.824 3.569 9.918 3.641 ;
     RECT  44.208 3.407 46.17 3.649 ;
     RECT  47.052 2.759 47.574 3.649 ;
     RECT  133.416 3.569 136.386 3.649 ;
     RECT  137.16 3.605 139.194 3.649 ;
     RECT  10.728 3.569 15.462 3.685 ;
     RECT  16.236 3.605 22.59 3.685 ;
     RECT  32.544 2.939 32.922 3.685 ;
     RECT  44.208 3.649 47.574 3.685 ;
     RECT  48.348 3.029 60.102 3.685 ;
     RECT  69.912 2.759 73.53 3.685 ;
     RECT  74.34 3.605 76.374 3.685 ;
     RECT  90.36 3.569 91.494 3.685 ;
     RECT  92.412 3.541 97.398 3.685 ;
     RECT  98.208 3.271 108.342 3.685 ;
     RECT  109.332 3.569 122.562 3.685 ;
     RECT  31.356 3.605 31.734 3.721 ;
     RECT  32.544 3.685 32.994 3.721 ;
     RECT  33.84 3.415 43.434 3.721 ;
     RECT  90.36 3.685 122.562 3.749 ;
     RECT  23.328 3.605 25.686 3.773 ;
     RECT  63.9 3.335 67.662 3.811 ;
     RECT  68.4 3.029 69.102 3.811 ;
     RECT  10.728 3.685 22.59 3.839 ;
     RECT  31.356 3.721 43.434 3.839 ;
     RECT  44.208 3.685 60.102 3.839 ;
     RECT  77.256 3.605 82.17 3.839 ;
     RECT  85.32 3.569 89.586 3.839 ;
     RECT  90.36 3.749 122.526 3.839 ;
     RECT  52.884 3.839 60.102 3.847 ;
     RECT  60.84 3.335 63.126 3.847 ;
     RECT  46.908 3.839 52.11 3.875 ;
     RECT  23.364 3.773 25.686 3.883 ;
     RECT  26.496 3.029 27.486 3.883 ;
     RECT  128.088 3.569 128.574 3.955 ;
     RECT  129.348 3.569 132.462 3.955 ;
     RECT  12.204 3.839 22.59 3.983 ;
     RECT  23.364 3.883 27.522 3.991 ;
     RECT  28.26 3.299 28.602 3.991 ;
     RECT  63.9 3.811 69.102 3.991 ;
     RECT  69.912 3.685 76.374 3.991 ;
     RECT  4.824 3.641 8.802 4.109 ;
     RECT  12.24 3.983 22.59 4.109 ;
     RECT  85.356 3.839 89.586 4.109 ;
     RECT  90.36 3.839 122.49 4.109 ;
     RECT  5.76 4.109 8.802 4.145 ;
     RECT  91.404 4.109 122.418 4.145 ;
     RECT  139.968 3.605 143.097 4.145 ;
     RECT  5.76 4.145 8.19 4.157 ;
     RECT  91.404 4.145 121.986 4.181 ;
     RECT  31.392 3.839 43.434 4.225 ;
     RECT  44.208 3.839 46.098 4.225 ;
     RECT  83.088 3.403 84.546 4.225 ;
     RECT  31.392 4.225 46.098 4.301 ;
     RECT  93.384 4.181 121.986 4.301 ;
     RECT  63.9 3.991 76.374 4.351 ;
     RECT  77.256 3.839 82.098 4.351 ;
     RECT  12.24 4.109 17.118 4.379 ;
     RECT  31.392 4.301 46.062 4.379 ;
     RECT  46.908 3.875 52.038 4.379 ;
     RECT  63.9 4.351 82.098 4.379 ;
     RECT  95.292 4.301 121.986 4.379 ;
     RECT  123.336 3.569 123.498 4.379 ;
     RECT  142.308 4.145 143.097 4.379 ;
     RECT  63.9 4.379 73.566 4.387 ;
     RECT  123.372 4.379 123.498 4.387 ;
     RECT  124.272 3.569 127.35 4.387 ;
     RECT  74.412 4.379 76.266 4.397 ;
     RECT  12.24 4.379 17.01 4.415 ;
     RECT  40.176 4.379 46.062 4.415 ;
     RECT  52.884 3.847 63.126 4.415 ;
     RECT  63.864 4.387 73.566 4.415 ;
     RECT  90.36 4.109 90.666 4.415 ;
     RECT  107.424 4.379 116.478 4.415 ;
     RECT  9.684 3.641 9.918 4.423 ;
     RECT  10.728 3.839 11.43 4.423 ;
     RECT  77.076 4.379 82.098 4.451 ;
     RECT  117.216 4.379 121.986 4.451 ;
     RECT  23.364 3.991 28.602 4.487 ;
     RECT  57.456 4.415 63.126 4.487 ;
     RECT  63.864 4.415 73.53 4.493 ;
     RECT  9.684 4.423 11.43 4.495 ;
     RECT  123.372 4.387 127.35 4.495 ;
     RECT  128.088 3.955 132.462 4.495 ;
     RECT  133.416 3.649 139.194 4.495 ;
     RECT  25.884 4.487 28.602 4.523 ;
     RECT  61.776 4.487 63.126 4.531 ;
     RECT  63.864 4.493 64.062 4.531 ;
     RECT  123.372 4.495 139.194 4.531 ;
     RECT  139.968 4.145 141.534 4.531 ;
     RECT  9 4.495 11.43 4.541 ;
     RECT  12.24 4.415 14.274 4.541 ;
     RECT  64.872 4.493 73.53 4.541 ;
     RECT  74.772 4.397 76.266 4.541 ;
     RECT  77.22 4.451 82.098 4.559 ;
     RECT  98.064 4.379 106.65 4.559 ;
     RECT  25.884 4.523 27.774 4.649 ;
     RECT  43.344 4.415 46.062 4.649 ;
     RECT  46.908 4.379 49.734 4.649 ;
     RECT  50.508 4.379 52.038 4.649 ;
     RECT  61.776 4.531 64.062 4.649 ;
     RECT  68.688 4.541 73.53 4.649 ;
     RECT  77.796 4.559 82.098 4.649 ;
     RECT  85.356 4.109 86.238 4.649 ;
     RECT  98.064 4.559 103.446 4.649 ;
     RECT  107.424 4.415 109.602 4.649 ;
     RECT  15.012 4.415 16.794 4.685 ;
     RECT  31.392 4.379 39.402 4.685 ;
     RECT  40.215 4.415 42.606 4.685 ;
     RECT  46.908 4.649 48.69 4.685 ;
     RECT  57.456 4.487 61.002 4.685 ;
     RECT  63.972 4.649 63.99 4.685 ;
     RECT  64.872 4.541 67.914 4.685 ;
     RECT  74.772 4.541 76.122 4.685 ;
     RECT  12.384 4.541 14.274 4.721 ;
     RECT  123.372 4.531 141.534 4.721 ;
     RECT  57.492 4.685 61.002 4.757 ;
     RECT  80.064 4.649 82.098 4.765 ;
     RECT  83.016 4.225 84.546 4.765 ;
     RECT  25.884 4.649 27.522 4.793 ;
     RECT  118.584 4.451 121.986 4.793 ;
     RECT  125.676 4.721 141.534 4.793 ;
     RECT  28.584 4.523 28.602 4.801 ;
     RECT  29.34 3.605 30.546 4.801 ;
     RECT  85.356 4.649 86.13 4.801 ;
     RECT  25.884 4.793 27.45 4.829 ;
     RECT  43.344 4.649 44.55 4.829 ;
     RECT  47.34 4.685 48.582 4.829 ;
     RECT  95.292 4.379 97.29 4.829 ;
     RECT  110.415 4.415 116.478 4.829 ;
     RECT  123.372 4.721 124.938 4.829 ;
     RECT  80.064 4.765 84.546 4.877 ;
     RECT  85.32 4.801 86.13 4.877 ;
     RECT  104.184 4.559 106.65 4.877 ;
     RECT  17.892 4.109 22.59 4.891 ;
     RECT  23.364 4.487 25.038 4.891 ;
     RECT  31.392 4.685 33.858 4.919 ;
     RECT  61.776 4.649 63.162 4.919 ;
     RECT  77.796 4.649 78.966 4.919 ;
     RECT  110.415 4.829 116.097 4.919 ;
     RECT  121.215 4.793 121.986 4.919 ;
     RECT  49.428 4.649 49.734 4.955 ;
     RECT  52.884 4.415 56.697 4.955 ;
     RECT  57.564 4.757 61.002 4.955 ;
     RECT  91.404 4.181 92.502 4.955 ;
     RECT  110.415 4.919 113.274 4.955 ;
     RECT  117.216 4.451 117.702 4.955 ;
     RECT  118.584 4.793 120.402 4.955 ;
     RECT  121.215 4.919 121.878 4.955 ;
     RECT  81.396 4.877 84.546 5.027 ;
     RECT  118.584 4.955 119.322 5.027 ;
     RECT  17.892 4.891 25.038 5.029 ;
     RECT  91.476 4.955 92.502 5.029 ;
     RECT  93.384 4.301 94.554 5.029 ;
     RECT  50.58 4.649 51.966 5.063 ;
     RECT  17.856 5.029 25.038 5.069 ;
     RECT  107.568 4.649 109.602 5.069 ;
     RECT  90.54 4.415 90.666 5.117 ;
     RECT  98.208 4.649 100.926 5.117 ;
     RECT  108.576 5.069 109.602 5.189 ;
     RECT  99.504 5.117 100.926 5.225 ;
     RECT  17.892 5.069 25.038 5.261 ;
     RECT  34.704 4.685 37.854 5.369 ;
     RECT  121.215 4.955 121.698 5.459 ;
     RECT  56.16 4.955 56.697 5.701 ;
     RECT  55.908 5.701 56.697 5.707 ;
     RECT  28.584 4.801 30.546 5.729 ;
     RECT  55.908 5.707 56.79 5.741 ;
     RECT  56.16 5.741 56.79 5.837 ;
     RECT  123.372 4.829 124.902 5.971 ;
     RECT  125.676 4.793 138.87 5.971 ;
     RECT  123.372 5.971 138.87 6.305 ;
     RECT  30.528 5.729 30.546 6.523 ;
     RECT  31.392 4.919 32.094 6.523 ;
     RECT  30.528 6.523 32.094 6.653 ;
     RECT  91.476 5.029 94.554 6.817 ;
     RECT  41.544 4.685 42.606 6.845 ;
     RECT  15.012 4.685 15.102 7.123 ;
     RECT  15.984 4.685 16.794 7.123 ;
     RECT  69.048 4.649 73.53 7.133 ;
     RECT  118.836 5.027 119.322 7.151 ;
     RECT  58.032 4.955 61.002 7.691 ;
     RECT  71.1 7.133 73.53 7.709 ;
     RECT  120.384 4.955 120.402 7.861 ;
     RECT  56.16 5.837 56.697 7.867 ;
     RECT  59.976 7.691 61.002 7.901 ;
     RECT  119.664 7.861 120.402 7.901 ;
     RECT  60.444 7.901 61.002 7.933 ;
     RECT  61.815 4.919 63.162 7.933 ;
     RECT  56.16 7.867 56.79 7.997 ;
     RECT  60.444 7.933 63.162 7.997 ;
     RECT  118.836 7.151 118.854 8.041 ;
     RECT  118.836 8.041 119.466 8.159 ;
     RECT  69.048 7.133 70.182 8.237 ;
     RECT  15.012 7.123 16.794 8.239 ;
     RECT  58.032 7.691 58.59 8.267 ;
     RECT  118.836 8.159 119.322 8.525 ;
     RECT  52.884 4.955 54.81 8.539 ;
     RECT  15.012 8.239 17.154 8.815 ;
     RECT  61.815 7.997 63.162 8.843 ;
     RECT  118.836 8.525 118.854 8.843 ;
     RECT  23.472 5.261 25.038 8.851 ;
     RECT  39.024 4.685 39.402 8.879 ;
     RECT  52.668 8.539 54.81 8.909 ;
     RECT  58.032 8.267 58.05 9.419 ;
     RECT  121.215 5.459 121.497 9.739 ;
     RECT  64.872 4.685 65.322 9.751 ;
     RECT  121.215 9.739 122.022 9.779 ;
     RECT  64.836 9.751 65.322 9.821 ;
     RECT  120.384 7.901 120.402 9.931 ;
     RECT  121.215 9.779 121.497 9.931 ;
     RECT  52.884 8.909 54.81 10.049 ;
     RECT  33.12 4.919 33.858 10.057 ;
     RECT  34.704 5.369 36.774 10.057 ;
     RECT  66.06 4.685 67.914 10.061 ;
     RECT  120.384 9.931 121.497 10.205 ;
     RECT  43.38 4.829 43.434 10.319 ;
     RECT  91.404 6.817 94.554 10.319 ;
     RECT  66.06 10.061 66.078 10.589 ;
     RECT  87.3 4.109 89.586 10.589 ;
     RECT  91.44 10.319 94.554 10.589 ;
     RECT  94.068 10.589 94.554 10.705 ;
     RECT  95.292 4.829 95.31 10.705 ;
     RECT  110.415 4.955 113.094 10.741 ;
     RECT  114.084 4.919 116.097 10.741 ;
     RECT  110.415 10.741 116.097 10.781 ;
     RECT  81.468 5.027 84.546 10.859 ;
     RECT  87.3 10.589 89.514 10.859 ;
     RECT  94.068 10.705 95.526 10.859 ;
     RECT  96.264 4.829 97.29 10.859 ;
     RECT  94.14 10.859 95.526 10.975 ;
     RECT  96.264 10.859 96.57 10.975 ;
     RECT  99.504 5.225 100.134 10.975 ;
     RECT  100.908 5.225 100.926 10.975 ;
     RECT  53.496 10.049 54.81 11.101 ;
     RECT  33.12 10.057 36.774 11.129 ;
     RECT  84.42 10.859 84.546 11.129 ;
     RECT  85.572 4.877 86.13 11.129 ;
     RECT  90.648 5.117 90.666 11.129 ;
     RECT  53.28 11.101 54.81 11.165 ;
     RECT  53.496 11.165 54.81 11.201 ;
     RECT  64.872 9.821 65.322 11.213 ;
     RECT  97.452 10.975 97.47 11.245 ;
     RECT  98.208 5.117 98.658 11.245 ;
     RECT  114.084 10.781 116.097 11.275 ;
     RECT  121.215 10.205 121.497 11.275 ;
     RECT  114.084 11.275 116.406 11.315 ;
     RECT  121.215 11.275 121.842 11.315 ;
     RECT  33.12 11.129 35.406 11.399 ;
     RECT  91.44 10.589 93.186 11.399 ;
     RECT  99.504 10.975 100.926 11.399 ;
     RECT  114.084 11.315 116.226 11.399 ;
     RECT  121.215 11.315 121.626 11.399 ;
     RECT  106.632 4.877 106.65 11.407 ;
     RECT  107.568 5.069 107.586 11.407 ;
     RECT  74.952 4.685 76.122 11.419 ;
     RECT  106.632 11.407 107.586 11.435 ;
     RECT  102.024 4.649 103.446 11.515 ;
     RECT  110.415 10.781 113.094 11.515 ;
     RECT  118.584 11.419 118.602 11.549 ;
     RECT  77.796 4.919 78.93 11.669 ;
     RECT  81.468 10.859 83.697 11.669 ;
     RECT  101.376 11.515 103.446 11.669 ;
     RECT  108.612 5.189 109.602 11.669 ;
     RECT  63.108 8.843 63.162 11.693 ;
     RECT  74.952 11.419 76.626 11.713 ;
     RECT  77.796 11.669 78.606 11.713 ;
     RECT  39.024 8.879 39.078 11.785 ;
     RECT  40.215 4.685 40.626 11.785 ;
     RECT  80.064 4.877 80.658 11.785 ;
     RECT  81.468 11.669 81.486 11.785 ;
     RECT  85.572 11.129 86.058 11.785 ;
     RECT  72.072 7.709 73.53 11.821 ;
     RECT  80.064 11.785 81.486 11.821 ;
     RECT  102.132 11.669 103.446 11.821 ;
     RECT  104.184 4.877 105.786 11.821 ;
     RECT  74.952 11.713 78.606 11.849 ;
     RECT  102.132 11.821 105.786 11.849 ;
     RECT  45.288 4.649 46.062 11.939 ;
     RECT  76.068 11.849 78.606 11.939 ;
     RECT  79.488 11.821 81.486 11.939 ;
     RECT  97.452 11.245 98.658 11.939 ;
     RECT  110.415 11.515 113.13 11.939 ;
     RECT  43.416 10.319 43.434 11.947 ;
     RECT  44.352 4.829 44.55 11.947 ;
     RECT  67.215 10.061 67.914 11.947 ;
     RECT  69.048 8.237 69.066 11.947 ;
     RECT  74.952 11.849 75.006 11.947 ;
     RECT  84.42 11.129 84.438 11.947 ;
     RECT  12.384 4.721 13.77 12.253 ;
     RECT  14.688 8.815 17.154 12.253 ;
     RECT  112.716 11.939 113.13 12.253 ;
     RECT  114.084 11.399 116.097 12.253 ;
     RECT  60.444 7.997 61.002 12.281 ;
     RECT  112.716 12.253 116.097 12.281 ;
     RECT  17.892 5.261 22.698 12.289 ;
     RECT  23.472 8.851 25.146 12.289 ;
     RECT  103.824 11.849 105.786 12.289 ;
     RECT  106.776 11.435 107.586 12.289 ;
     RECT  37.656 5.369 37.854 12.317 ;
     RECT  47.448 4.829 48.582 12.325 ;
     RECT  72.072 11.821 73.674 12.361 ;
     RECT  74.52 11.947 75.006 12.361 ;
     RECT  103.824 12.289 107.586 12.361 ;
     RECT  17.892 12.289 25.146 12.479 ;
     RECT  71.1 7.709 71.118 12.479 ;
     RECT  76.104 11.939 78.606 12.479 ;
     RECT  103.824 12.361 107.946 12.479 ;
     RECT  72.072 12.361 75.006 12.515 ;
     RECT  103.824 12.479 106.794 12.515 ;
     RECT  33.12 11.399 33.138 12.523 ;
     RECT  34.092 11.399 35.406 12.523 ;
     RECT  66.276 12.487 66.294 12.523 ;
     RECT  72.072 12.515 72.897 12.523 ;
     RECT  107.568 12.479 107.946 12.523 ;
     RECT  108.792 11.669 109.602 12.523 ;
     RECT  103.824 12.515 105.498 12.557 ;
     RECT  25.884 4.829 25.938 12.749 ;
     RECT  41.544 6.845 42.534 12.749 ;
     RECT  66.24 12.523 66.294 12.749 ;
     RECT  54.468 11.201 54.81 12.797 ;
     RECT  54.468 12.797 54.486 12.821 ;
     RECT  112.716 12.281 114.462 12.821 ;
     RECT  66.276 12.749 66.294 12.901 ;
     RECT  67.215 11.947 69.066 12.901 ;
     RECT  71.892 12.523 72.897 12.901 ;
     RECT  110.415 11.939 111.978 12.941 ;
     RECT  65.304 11.213 65.322 12.955 ;
     RECT  65.304 12.955 65.43 13.019 ;
     RECT  65.304 13.019 65.322 13.051 ;
     RECT  33.12 12.523 35.406 13.063 ;
     RECT  36.144 11.129 36.774 13.063 ;
     RECT  50.58 5.063 51.297 13.063 ;
     RECT  66.276 12.901 69.066 13.085 ;
     RECT  71.424 12.901 72.897 13.085 ;
     RECT  65.088 13.051 65.322 13.091 ;
     RECT  31.392 6.653 32.094 13.127 ;
     RECT  79.488 11.939 80.766 13.127 ;
     RECT  33.084 13.063 36.774 13.171 ;
     RECT  39.024 11.785 40.626 13.289 ;
     RECT  115.344 12.281 116.097 13.289 ;
     RECT  112.716 12.821 114.102 13.369 ;
     RECT  120.384 10.205 120.402 13.405 ;
     RECT  121.215 11.399 121.497 13.405 ;
     RECT  76.14 12.479 77.238 13.525 ;
     RECT  43.416 11.947 44.55 13.531 ;
     RECT  71.892 13.085 72.897 13.531 ;
     RECT  74.16 12.515 75.006 13.531 ;
     RECT  75.852 13.525 77.238 13.531 ;
     RECT  101.376 11.669 101.394 13.531 ;
     RECT  102.132 11.849 102.798 13.531 ;
     RECT  107.568 12.523 109.602 13.531 ;
     RECT  110.415 12.941 111.438 13.531 ;
     RECT  71.892 13.531 77.238 13.565 ;
     RECT  33.048 13.171 36.774 13.567 ;
     RECT  71.892 13.565 75.33 13.568 ;
     RECT  107.568 13.531 111.438 13.568 ;
     RECT  70.164 8.237 70.182 13.579 ;
     RECT  32.904 13.567 36.774 13.613 ;
     RECT  73.656 13.568 75.33 13.613 ;
     RECT  43.344 13.531 44.55 13.639 ;
     RECT  33.228 13.613 36.774 13.661 ;
     RECT  70.164 13.579 70.47 13.829 ;
     RECT  63.108 11.693 63.126 13.949 ;
     RECT  17.892 12.479 23.274 13.963 ;
     RECT  24.015 12.479 25.146 13.963 ;
     RECT  45.615 11.939 46.062 13.963 ;
     RECT  110.415 13.568 111.438 13.973 ;
     RECT  71.892 13.568 72.897 13.981 ;
     RECT  56.16 7.997 56.697 13.997 ;
     RECT  17.892 13.963 25.146 14.009 ;
     RECT  45.504 13.963 46.062 14.009 ;
     RECT  71.82 13.981 72.897 14.045 ;
     RECT  76.14 13.565 77.238 14.059 ;
     RECT  78.015 12.479 78.606 14.059 ;
     RECT  24.015 14.009 25.146 14.179 ;
     RECT  25.884 12.749 25.902 14.179 ;
     RECT  41.544 12.749 42.462 14.215 ;
     RECT  43.344 13.639 44.73 14.215 ;
     RECT  24.015 14.179 25.902 14.341 ;
     RECT  24.015 14.341 26.118 14.381 ;
     RECT  97.452 11.939 98.55 14.395 ;
     RECT  99.576 11.399 100.53 14.395 ;
     RECT  87.984 10.859 89.478 14.521 ;
     RECT  123.372 6.305 127.314 14.521 ;
     RECT  128.196 6.305 138.87 14.521 ;
     RECT  31.464 13.127 32.094 14.587 ;
     RECT  45.615 14.009 46.062 14.587 ;
     RECT  74.16 13.613 75.006 14.587 ;
     RECT  104.616 12.557 105.498 14.635 ;
     RECT  106.308 12.515 106.794 14.635 ;
     RECT  31.464 14.587 32.202 14.639 ;
     RECT  41.544 14.215 44.73 14.639 ;
     RECT  45.615 14.587 46.098 14.639 ;
     RECT  74.16 14.587 75.33 14.639 ;
     RECT  97.452 14.395 100.53 14.675 ;
     RECT  104.616 14.635 106.794 14.675 ;
     RECT  99.396 14.675 100.53 14.717 ;
     RECT  41.544 14.639 42.642 14.72 ;
     RECT  28.584 5.729 29.79 14.731 ;
     RECT  30.528 6.653 30.546 14.731 ;
     RECT  120.384 13.405 121.497 14.755 ;
     RECT  39.636 13.289 40.626 14.779 ;
     RECT  87.984 14.521 89.55 14.779 ;
     RECT  76.14 14.059 78.606 14.819 ;
     RECT  87.984 14.779 89.73 14.819 ;
     RECT  47.448 12.325 48.942 14.827 ;
     RECT  49.68 4.955 49.734 14.827 ;
     RECT  67.215 13.085 69.066 14.827 ;
     RECT  70.164 13.829 70.182 14.827 ;
     RECT  47.448 14.827 49.734 14.881 ;
     RECT  87.12 10.975 87.138 14.881 ;
     RECT  103.824 12.557 103.842 14.881 ;
     RECT  104.616 14.675 105.498 14.881 ;
     RECT  84.42 11.947 84.582 14.909 ;
     RECT  87.048 14.881 87.138 14.909 ;
     RECT  87.984 14.819 89.478 14.909 ;
     RECT  101.376 13.531 102.798 14.909 ;
     RECT  103.824 14.881 105.498 14.909 ;
     RECT  106.308 14.675 106.794 14.909 ;
     RECT  24.015 14.381 25.902 14.957 ;
     RECT  67.215 14.827 70.686 14.957 ;
     RECT  4.824 4.109 4.842 15.089 ;
     RECT  78.015 14.819 78.606 15.151 ;
     RECT  79.488 13.127 80.694 15.151 ;
     RECT  12.384 12.253 17.154 15.179 ;
     RECT  67.215 14.957 70.182 15.179 ;
     RECT  43.416 14.639 44.73 15.197 ;
     RECT  67.215 15.179 69.426 15.215 ;
     RECT  87.984 14.909 89.406 15.389 ;
     RECT  33.552 13.661 36.774 15.403 ;
     RECT  37.764 12.317 37.854 15.403 ;
     RECT  47.448 14.881 49.77 15.437 ;
     RECT  84.492 14.909 84.582 15.448 ;
     RECT  85.464 11.785 86.058 15.448 ;
     RECT  39.6 14.779 40.626 15.449 ;
     RECT  78.015 15.151 80.694 15.485 ;
     RECT  84.492 15.448 86.058 15.485 ;
     RECT  82.26 11.669 83.697 15.547 ;
     RECT  106.38 14.909 106.794 15.565 ;
     RECT  107.568 13.568 109.602 15.565 ;
     RECT  85.464 15.485 86.058 15.601 ;
     RECT  87.048 14.909 87.066 15.601 ;
     RECT  37.764 15.403 38.322 15.643 ;
     RECT  47.448 15.437 48.942 15.643 ;
     RECT  93.132 11.399 93.15 15.685 ;
     RECT  94.14 10.975 96.57 15.685 ;
     RECT  17.892 14.009 23.274 15.719 ;
     RECT  37.764 15.643 38.466 15.719 ;
     RECT  47.268 15.643 48.942 15.719 ;
     RECT  81.684 15.547 83.697 15.719 ;
     RECT  93.132 15.685 96.57 15.725 ;
     RECT  37.764 15.719 38.106 15.728 ;
     RECT  93.132 15.725 93.402 15.787 ;
     RECT  28.584 14.731 30.546 15.835 ;
     RECT  39.636 15.449 40.626 15.835 ;
     RECT  41.544 14.72 42.426 15.835 ;
     RECT  94.14 15.725 96.57 15.871 ;
     RECT  97.452 14.675 98.55 15.871 ;
     RECT  93.024 15.787 93.402 15.899 ;
     RECT  28.584 15.835 30.618 15.961 ;
     RECT  31.464 14.639 32.094 15.961 ;
     RECT  28.584 15.961 32.094 16.013 ;
     RECT  85.464 15.601 87.066 16.013 ;
     RECT  94.14 15.871 98.55 16.013 ;
     RECT  27.108 4.829 27.45 16.105 ;
     RECT  27.108 16.105 27.486 16.219 ;
     RECT  32.976 15.403 36.774 16.219 ;
     RECT  37.764 15.728 37.854 16.219 ;
     RECT  27.108 16.219 27.666 16.259 ;
     RECT  32.976 16.219 37.854 16.259 ;
     RECT  111.42 13.973 111.438 16.259 ;
     RECT  28.584 16.013 30.618 16.295 ;
     RECT  93.06 15.899 93.402 16.301 ;
     RECT  24.015 14.957 25.146 16.375 ;
     RECT  25.884 14.957 25.902 16.375 ;
     RECT  31.464 16.013 32.094 16.375 ;
     RECT  32.976 16.259 36.774 16.375 ;
     RECT  65.304 13.091 65.322 16.439 ;
     RECT  93.132 16.301 93.402 16.459 ;
     RECT  94.14 16.013 96.642 16.459 ;
     RECT  27.108 16.259 27.486 16.529 ;
     RECT  9.216 4.541 11.43 16.565 ;
     RECT  27.108 16.529 27.378 16.589 ;
     RECT  82.26 15.719 83.697 16.681 ;
     RECT  84.492 15.485 84.582 16.681 ;
     RECT  87.984 15.389 89.334 16.747 ;
     RECT  30.528 16.295 30.618 16.771 ;
     RECT  120.384 14.755 121.842 16.771 ;
     RECT  85.464 16.013 86.058 16.795 ;
     RECT  87.048 16.013 87.066 16.795 ;
     RECT  31.464 16.375 36.774 16.799 ;
     RECT  39.636 15.835 42.426 16.799 ;
     RECT  106.38 15.565 109.602 16.799 ;
     RECT  85.464 16.795 87.066 16.835 ;
     RECT  107.568 16.799 109.602 16.835 ;
     RECT  112.176 13.369 114.102 16.843 ;
     RECT  67.215 15.215 69.066 16.871 ;
     RECT  107.568 16.835 109.314 16.871 ;
     RECT  111.744 16.843 114.102 16.871 ;
     RECT  90.684 11.245 90.702 16.879 ;
     RECT  91.44 11.399 92.214 16.879 ;
     RECT  60.444 12.281 60.462 16.907 ;
     RECT  45.615 14.639 46.062 16.915 ;
     RECT  87.048 16.835 87.066 16.951 ;
     RECT  93.132 16.459 96.642 16.951 ;
     RECT  97.452 16.013 98.55 16.951 ;
     RECT  101.448 14.909 102.798 16.951 ;
     RECT  103.896 14.909 105.498 16.951 ;
     RECT  120.384 16.771 121.914 16.951 ;
     RECT  120.384 16.951 122.274 17.021 ;
     RECT  87.984 16.747 89.73 17.035 ;
     RECT  90.684 16.879 92.214 17.035 ;
     RECT  82.26 16.681 84.582 17.083 ;
     RECT  87.984 17.035 92.214 17.083 ;
     RECT  93.132 16.951 98.55 17.083 ;
     RECT  32.904 16.799 36.774 17.113 ;
     RECT  87.048 16.951 87.138 17.221 ;
     RECT  87.984 17.083 98.55 17.221 ;
     RECT  81.684 17.083 84.582 17.275 ;
     RECT  99.576 14.717 100.53 17.311 ;
     RECT  101.448 16.951 105.498 17.311 ;
     RECT  110.415 13.973 110.697 17.311 ;
     RECT  81.684 17.275 84.69 17.339 ;
     RECT  27.108 16.589 27.198 17.347 ;
     RECT  110.304 17.311 110.697 17.357 ;
     RECT  45.54 16.915 46.062 17.375 ;
     RECT  117.684 4.955 117.702 17.411 ;
     RECT  70.164 15.179 70.182 17.453 ;
     RECT  31.464 16.799 32.094 17.581 ;
     RECT  32.904 17.113 36.846 17.581 ;
     RECT  81.684 17.339 83.697 17.645 ;
     RECT  37.764 16.259 37.854 17.761 ;
     RECT  19.656 15.719 23.274 17.851 ;
     RECT  24.015 16.375 25.902 17.851 ;
     RECT  31.464 17.581 36.846 17.851 ;
     RECT  37.764 17.761 38.106 17.851 ;
     RECT  87.048 17.221 98.55 17.851 ;
     RECT  99.576 17.311 105.498 17.851 ;
     RECT  120.384 17.021 121.842 17.879 ;
     RECT  19.656 17.851 25.902 17.888 ;
     RECT  30.528 16.771 30.69 17.947 ;
     RECT  31.464 17.851 38.106 17.947 ;
     RECT  28.584 16.295 29.79 17.959 ;
     RECT  30.528 17.947 38.106 17.959 ;
     RECT  85.464 16.835 86.058 17.959 ;
     RECT  87.048 17.851 105.498 17.959 ;
     RECT  76.14 14.819 77.238 18.121 ;
     RECT  78.015 15.485 78.606 18.121 ;
     RECT  82.26 17.645 83.697 18.121 ;
     RECT  84.492 17.339 84.69 18.121 ;
     RECT  110.415 17.357 110.697 18.157 ;
     RECT  28.584 17.959 38.106 18.301 ;
     RECT  82.26 18.121 84.69 18.301 ;
     RECT  85.464 17.959 105.498 18.301 ;
     RECT  26.712 17.347 27.198 18.379 ;
     RECT  24.015 17.888 25.902 18.421 ;
     RECT  26.712 18.379 27.558 18.421 ;
     RECT  24.015 18.421 27.558 18.427 ;
     RECT  43.416 15.197 44.55 18.499 ;
     RECT  120.528 17.879 121.842 18.527 ;
     RECT  82.26 18.301 105.498 18.535 ;
     RECT  106.38 16.799 106.794 18.535 ;
     RECT  53.496 11.201 53.514 18.563 ;
     RECT  24.015 18.427 27.63 18.571 ;
     RECT  28.584 18.301 38.79 18.571 ;
     RECT  24.015 18.571 38.79 18.661 ;
     RECT  39.636 16.799 40.626 18.661 ;
     RECT  74.16 14.639 75.006 18.661 ;
     RECT  43.416 18.499 44.622 18.667 ;
     RECT  79.488 15.485 80.694 18.697 ;
     RECT  45.615 17.375 46.062 18.769 ;
     RECT  47.448 15.719 48.942 18.797 ;
     RECT  24.015 18.661 40.626 18.805 ;
     RECT  41.544 16.799 42.426 18.805 ;
     RECT  76.14 18.121 78.606 18.805 ;
     RECT  79.488 18.697 81.27 18.805 ;
     RECT  121.215 18.527 121.842 18.805 ;
     RECT  11.412 16.565 11.43 18.811 ;
     RECT  43.236 18.667 44.622 18.811 ;
     RECT  45.615 18.769 46.458 18.811 ;
     RECT  74.16 18.661 75.078 18.841 ;
     RECT  76.14 18.805 81.27 18.841 ;
     RECT  82.26 18.535 106.794 18.841 ;
     RECT  43.236 18.811 46.458 18.967 ;
     RECT  117.756 18.931 117.774 18.989 ;
     RECT  19.656 17.888 23.274 19.003 ;
     RECT  24.015 18.805 42.426 19.003 ;
     RECT  119.304 18.997 119.322 19.037 ;
     RECT  74.16 18.841 106.794 19.099 ;
     RECT  43.2 18.967 46.458 19.111 ;
     RECT  47.448 18.797 47.538 19.111 ;
     RECT  74.16 19.099 107.19 19.111 ;
     RECT  107.928 16.871 109.314 19.111 ;
     RECT  19.656 19.003 42.426 19.265 ;
     RECT  17.892 15.719 18.897 19.291 ;
     RECT  19.656 19.265 30.726 19.291 ;
     RECT  11.412 18.811 11.754 19.345 ;
     RECT  31.464 19.265 42.426 19.471 ;
     RECT  43.2 19.111 47.538 19.471 ;
     RECT  48.564 18.797 48.942 19.471 ;
     RECT  49.716 15.437 49.77 19.471 ;
     RECT  110.232 18.157 110.697 19.507 ;
     RECT  31.464 19.471 47.538 19.543 ;
     RECT  48.564 19.471 49.77 19.543 ;
     RECT  110.232 19.507 110.79 19.615 ;
     RECT  111.744 16.871 113.994 19.615 ;
     RECT  61.815 8.843 62.097 19.651 ;
     RECT  66.276 13.085 66.294 19.651 ;
     RECT  67.215 16.871 68.346 19.651 ;
     RECT  121.215 18.805 121.914 19.651 ;
     RECT  74.16 19.111 109.314 19.723 ;
     RECT  73.656 19.723 109.314 19.741 ;
     RECT  110.232 19.615 113.994 19.741 ;
     RECT  73.656 19.741 113.994 19.769 ;
     RECT  61.815 19.651 62.73 19.819 ;
     RECT  65.484 19.885 65.502 19.921 ;
     RECT  66.276 19.651 68.346 19.921 ;
     RECT  54.72 19.819 54.738 19.949 ;
     RECT  61.815 19.819 62.766 19.949 ;
     RECT  65.484 19.921 68.346 19.949 ;
     RECT  70.704 19.507 70.722 20.155 ;
     RECT  17.892 19.291 30.726 20.191 ;
     RECT  31.464 19.543 49.77 20.191 ;
     RECT  50.508 13.063 51.297 20.191 ;
     RECT  65.664 19.949 68.346 20.191 ;
     RECT  11.412 19.345 12.006 20.309 ;
     RECT  74.016 19.769 113.994 20.309 ;
     RECT  77.544 20.309 113.994 20.353 ;
     RECT  70.704 20.155 71.046 20.389 ;
     RECT  77.544 20.353 114.246 20.389 ;
     RECT  70.308 20.389 71.046 20.425 ;
     RECT  56.415 13.997 56.697 20.443 ;
     RECT  77.544 20.389 114.822 20.453 ;
     RECT  70.164 20.425 71.046 20.461 ;
     RECT  71.892 14.045 72.897 20.461 ;
     RECT  56.304 20.443 56.697 20.489 ;
     RECT  70.164 20.461 72.897 20.539 ;
     RECT  120.888 19.651 121.914 20.539 ;
     RECT  65.664 20.191 68.922 20.551 ;
     RECT  69.912 20.539 73.17 20.551 ;
     RECT  120.888 20.539 122.634 20.579 ;
     RECT  65.664 20.551 73.17 20.623 ;
     RECT  65.664 20.623 73.242 20.731 ;
     RECT  74.016 20.309 76.806 20.731 ;
     RECT  65.664 20.731 76.806 20.857 ;
     RECT  77.868 20.453 114.822 20.921 ;
     RECT  65.592 20.857 76.806 20.965 ;
     RECT  109.764 20.921 114.822 21.199 ;
     RECT  61.815 19.949 62.097 21.211 ;
     RECT  115.815 13.289 116.097 21.235 ;
     RECT  123.372 14.521 138.87 21.235 ;
     RECT  65.556 20.965 76.806 21.259 ;
     RECT  77.868 20.921 108.918 21.259 ;
     RECT  61.815 21.211 62.73 21.271 ;
     RECT  115.704 21.235 116.097 21.433 ;
     RECT  61.815 21.271 62.766 21.461 ;
     RECT  65.556 21.259 108.918 21.505 ;
     RECT  61.815 21.461 62.73 21.533 ;
     RECT  12.924 15.179 17.154 21.541 ;
     RECT  17.892 20.191 51.297 21.541 ;
     RECT  120.888 20.579 121.914 21.541 ;
     RECT  56.415 20.489 56.697 21.631 ;
     RECT  109.764 21.199 114.858 21.643 ;
     RECT  65.376 21.505 108.918 21.667 ;
     RECT  109.656 21.643 114.858 21.667 ;
     RECT  115.668 21.433 116.097 21.667 ;
     RECT  118.656 21.259 118.674 21.667 ;
     RECT  56.304 21.631 56.697 21.677 ;
     RECT  118.62 21.667 118.674 21.703 ;
     RECT  119.7 21.643 119.718 21.703 ;
     RECT  65.376 21.667 114.858 21.739 ;
     RECT  115.668 21.667 116.55 21.739 ;
     RECT  64.584 21.067 64.602 21.811 ;
     RECT  65.376 21.739 117.198 21.811 ;
     RECT  118.548 21.703 119.718 21.901 ;
     RECT  120.888 21.541 122.634 21.901 ;
     RECT  118.476 21.901 119.718 22.009 ;
     RECT  118.476 22.009 119.862 22.045 ;
     RECT  120.636 21.901 122.634 22.045 ;
     RECT  118.476 22.045 122.634 22.073 ;
     RECT  118.584 22.073 122.634 22.235 ;
     RECT  119.628 22.235 122.634 22.243 ;
     RECT  123.372 21.235 139.014 22.243 ;
     RECT  9.216 16.565 10.53 22.315 ;
     RECT  64.584 21.811 117.198 22.315 ;
     RECT  5.904 4.157 8.19 22.351 ;
     RECT  8.964 22.315 10.53 22.351 ;
     RECT  64.584 22.315 117.594 22.379 ;
     RECT  109.908 22.379 117.594 22.445 ;
     RECT  5.904 22.351 10.53 22.469 ;
     RECT  109.908 22.445 117.486 22.469 ;
     RECT  61.815 21.533 62.097 22.507 ;
     RECT  12.924 21.541 51.297 22.585 ;
     RECT  56.415 21.677 56.697 22.603 ;
     RECT  12.312 22.585 51.297 22.613 ;
     RECT  12.312 22.613 43.902 22.621 ;
     RECT  61.815 22.507 62.73 22.637 ;
     RECT  56.304 22.603 56.697 22.649 ;
     RECT  8.964 22.469 10.53 22.739 ;
     RECT  9.144 22.739 10.53 22.781 ;
     RECT  12.168 22.621 43.902 22.811 ;
     RECT  110.016 22.469 117.486 22.811 ;
     RECT  63.756 22.783 63.774 22.819 ;
     RECT  12.168 22.811 37.098 23.009 ;
     RECT  44.928 22.613 51.297 23.009 ;
     RECT  63.684 22.819 63.774 23.009 ;
     RECT  112.104 22.811 117.486 23.009 ;
     RECT  64.584 22.379 109.134 23.045 ;
     RECT  112.104 23.009 117.378 23.045 ;
     RECT  12.924 23.009 37.098 23.081 ;
     RECT  69.336 23.045 109.134 23.081 ;
     RECT  64.584 23.045 68.526 23.089 ;
     RECT  44.964 23.009 49.842 23.117 ;
     RECT  69.336 23.081 109.062 23.117 ;
     RECT  69.336 23.117 109.026 23.123 ;
     RECT  63.756 23.009 63.774 23.125 ;
     RECT  64.548 23.089 68.526 23.125 ;
     RECT  87.624 23.123 109.026 23.153 ;
     RECT  12.168 23.009 12.186 23.165 ;
     RECT  31.968 23.081 37.098 23.189 ;
     RECT  87.696 23.153 109.026 23.189 ;
     RECT  110.016 22.811 111.186 23.189 ;
     RECT  93.384 23.189 109.026 23.213 ;
     RECT  11.412 20.309 11.43 23.251 ;
     RECT  118.584 22.235 118.89 23.251 ;
     RECT  119.628 22.243 139.014 23.251 ;
     RECT  110.196 23.189 111.186 23.261 ;
     RECT  32.04 23.189 37.098 23.279 ;
     RECT  37.872 22.811 43.902 23.279 ;
     RECT  48.564 23.117 49.842 23.279 ;
     RECT  63.756 23.125 68.526 23.279 ;
     RECT  11.412 23.251 12.042 23.309 ;
     RECT  44.964 23.117 47.826 23.309 ;
     RECT  110.196 23.261 111.15 23.309 ;
     RECT  37.908 23.279 43.902 23.315 ;
     RECT  112.104 23.045 117.234 23.315 ;
     RECT  118.584 23.251 139.014 23.315 ;
     RECT  12.924 23.081 31.194 23.351 ;
     RECT  64.404 23.279 68.526 23.351 ;
     RECT  69.336 23.123 86.778 23.351 ;
     RECT  93.384 23.213 105.39 23.351 ;
     RECT  106.2 23.213 109.026 23.351 ;
     RECT  70.344 23.351 86.778 23.357 ;
     RECT  87.696 23.189 92.646 23.357 ;
     RECT  40.176 23.315 43.902 23.359 ;
     RECT  32.076 23.279 37.098 23.387 ;
     RECT  45.036 23.309 47.826 23.387 ;
     RECT  48.564 23.279 49.734 23.387 ;
     RECT  69.336 23.351 69.606 23.387 ;
     RECT  106.308 23.351 108.954 23.387 ;
     RECT  45.216 23.387 47.826 23.405 ;
     RECT  34.632 23.387 35.19 23.423 ;
     RECT  45.216 23.405 46.494 23.423 ;
     RECT  48.636 23.387 49.734 23.423 ;
     RECT  65.412 23.351 68.526 23.423 ;
     RECT  88.668 23.357 92.574 23.459 ;
     RECT  93.384 23.351 103.986 23.459 ;
     RECT  106.308 23.387 108.054 23.459 ;
     RECT  28.692 23.351 31.194 23.501 ;
     RECT  50.58 23.009 51.297 23.507 ;
     RECT  56.415 22.649 56.697 23.507 ;
     RECT  61.815 22.637 62.694 23.507 ;
     RECT  66.42 23.423 67.497 23.507 ;
     RECT  37.908 23.315 39.366 23.549 ;
     RECT  40.176 23.359 43.974 23.549 ;
     RECT  45.324 23.423 46.494 23.549 ;
     RECT  48.744 23.423 49.734 23.549 ;
     RECT  65.412 23.423 65.682 23.549 ;
     RECT  68.256 23.423 68.526 23.549 ;
     RECT  70.344 23.357 71.226 23.549 ;
     RECT  72.576 23.357 86.778 23.549 ;
     RECT  104.76 23.351 105.39 23.549 ;
     RECT  107.676 23.459 108.054 23.549 ;
     RECT  112.14 23.315 117.234 23.549 ;
     RECT  120.708 23.315 139.014 23.549 ;
     RECT  62.676 23.507 62.694 23.557 ;
     RECT  34.704 23.423 35.19 23.585 ;
     RECT  35.964 23.387 37.098 23.585 ;
     RECT  38.808 23.549 39.366 23.585 ;
     RECT  40.176 23.549 41.238 23.585 ;
     RECT  45.615 23.549 46.386 23.585 ;
     RECT  48.744 23.549 48.762 23.585 ;
     RECT  50.58 23.507 51.105 23.585 ;
     RECT  88.704 23.459 92.574 23.585 ;
     RECT  93.6 23.459 103.986 23.585 ;
     RECT  118.584 23.315 119.898 23.585 ;
     RECT  28.692 23.501 30.654 23.597 ;
     RECT  32.076 23.387 33.894 23.597 ;
     RECT  35.964 23.585 37.062 23.597 ;
     RECT  40.176 23.585 40.59 23.597 ;
     RECT  101.7 23.585 103.986 23.597 ;
     RECT  42.66 23.549 43.974 23.621 ;
     RECT  118.62 23.585 119.898 23.621 ;
     RECT  35.964 23.597 36.666 23.657 ;
     RECT  62.676 23.557 62.73 23.665 ;
     RECT  47.376 23.405 47.826 23.666 ;
     RECT  36.324 23.657 36.666 23.693 ;
     RECT  37.908 23.549 38.07 23.693 ;
     RECT  42.66 23.621 43.578 23.693 ;
     RECT  72.576 23.549 76.122 23.693 ;
     RECT  77.544 23.549 86.778 23.693 ;
     RECT  93.6 23.585 100.962 23.693 ;
     RECT  105.015 23.549 105.39 23.693 ;
     RECT  112.14 23.549 117.126 23.693 ;
     RECT  36.396 23.693 36.666 23.729 ;
     RECT  38.808 23.585 38.826 23.729 ;
     RECT  47.376 23.666 47.79 23.729 ;
     RECT  105.015 23.693 105.354 23.729 ;
     RECT  36.396 23.729 36.414 23.741 ;
     RECT  47.628 23.729 47.79 23.741 ;
     RECT  90.36 23.585 92.574 23.741 ;
     RECT  103.608 23.597 103.986 23.741 ;
     RECT  106.308 23.459 106.902 23.741 ;
     RECT  112.14 23.693 116.586 23.741 ;
     RECT  28.692 23.597 30.15 23.777 ;
     RECT  40.176 23.597 40.305 23.777 ;
     RECT  45.615 23.585 46.314 23.777 ;
     RECT  51.015 23.585 51.105 23.777 ;
     RECT  61.815 23.507 61.905 23.777 ;
     RECT  77.544 23.693 79.65 23.777 ;
     RECT  105.015 23.729 105.105 23.777 ;
     RECT  33.084 23.597 33.822 23.789 ;
     RECT  56.415 23.507 56.61 23.791 ;
     RECT  28.692 23.777 29.358 23.819 ;
     RECT  33.084 23.789 33.57 23.819 ;
     RECT  34.704 23.585 35.082 23.819 ;
     RECT  47.772 23.741 47.79 23.819 ;
     RECT  62.676 23.665 62.766 23.819 ;
     RECT  66.42 23.507 67.482 23.819 ;
     RECT  107.712 23.549 108.054 23.819 ;
     RECT  34.704 23.819 35.01 23.837 ;
     RECT  56.304 23.791 56.61 23.837 ;
     RECT  66.42 23.819 67.41 23.837 ;
     RECT  74.16 23.693 76.122 23.837 ;
     RECT  78.66 23.777 79.65 23.837 ;
     RECT  97.92 23.693 100.962 23.837 ;
     RECT  110.304 23.309 111.15 23.837 ;
     RECT  29.088 23.819 29.214 23.855 ;
     RECT  70.704 23.549 71.226 23.855 ;
     RECT  74.16 23.837 75.258 23.855 ;
     RECT  77.544 23.777 77.562 23.855 ;
     RECT  80.496 23.693 83.574 23.855 ;
     RECT  103.608 23.741 103.77 23.855 ;
     RECT  112.14 23.741 113.814 23.855 ;
     RECT  74.7 23.855 75.258 23.885 ;
     RECT  82.476 23.855 83.574 23.885 ;
     RECT  66.42 23.837 66.726 23.891 ;
     RECT  68.328 23.549 68.526 23.891 ;
     RECT  78.66 23.837 78.714 23.891 ;
     RECT  80.496 23.855 81.738 23.891 ;
     RECT  101.7 23.597 102.726 23.891 ;
     RECT  114.552 23.741 116.586 23.891 ;
     RECT  118.62 23.621 119.862 23.891 ;
     RECT  37.908 23.693 37.998 23.927 ;
     RECT  49.716 23.549 49.734 23.927 ;
     RECT  84.636 23.693 86.778 23.927 ;
     RECT  90.648 23.741 92.574 23.927 ;
     RECT  93.6 23.693 96.93 23.927 ;
     RECT  101.7 23.891 101.79 23.927 ;
     RECT  114.552 23.891 116.37 23.927 ;
     RECT  86.652 23.927 86.778 23.933 ;
     RECT  90.648 23.927 91.638 23.933 ;
     RECT  118.656 23.891 119.862 23.933 ;
     RECT  12.924 23.351 27.918 23.981 ;
     RECT  80.496 23.891 80.982 23.981 ;
     RECT  83.556 23.885 83.574 23.981 ;
     RECT  88.704 23.585 89.514 23.981 ;
     RECT  94.824 23.927 96.858 23.981 ;
     RECT  99.936 23.837 100.962 23.981 ;
     RECT  40.176 23.777 40.194 23.999 ;
     RECT  33.372 23.819 33.498 24.044 ;
     RECT  114.696 23.927 116.37 24.161 ;
     RECT  30.132 23.777 30.15 24.173 ;
     RECT  114.696 24.161 115.002 24.197 ;
     RECT  79.632 23.837 79.65 24.221 ;
     RECT  82.584 23.885 82.674 24.221 ;
     RECT  9.216 22.781 10.53 24.233 ;
     RECT  84.636 23.927 85.878 24.233 ;
     RECT  91.332 23.933 91.602 24.233 ;
     RECT  71.208 23.855 71.226 24.269 ;
     RECT  72.576 23.693 73.314 24.269 ;
     RECT  106.308 23.741 106.866 24.269 ;
     RECT  76.104 23.837 76.122 24.314 ;
     RECT  106.308 24.269 106.326 24.314 ;
     RECT  43.488 23.693 43.506 24.359 ;
     RECT  108.9 23.387 108.954 24.359 ;
     RECT  111.132 23.837 111.15 24.395 ;
     RECT  65.412 23.549 65.502 24.413 ;
     RECT  119.088 23.933 119.862 24.427 ;
     RECT  120.852 23.549 139.014 24.427 ;
     RECT  46.296 23.777 46.314 24.431 ;
     RECT  108.9 24.359 108.918 24.431 ;
     RECT  32.076 23.597 32.274 24.467 ;
     RECT  112.14 23.855 112.95 24.467 ;
     RECT  72.576 24.269 72.81 24.503 ;
     RECT  113.796 23.855 113.814 24.503 ;
     RECT  78.66 23.891 78.678 24.509 ;
     RECT  82.656 24.221 82.674 24.509 ;
     RECT  86.652 23.933 86.67 24.509 ;
     RECT  112.14 24.467 112.158 24.511 ;
     RECT  68.328 23.891 68.346 24.539 ;
     RECT  97.92 23.837 98.874 24.539 ;
     RECT  66.708 23.891 66.726 24.653 ;
     RECT  102.708 23.891 102.726 24.737 ;
     RECT  119.088 24.427 139.014 24.745 ;
     RECT  80.496 23.981 80.514 24.749 ;
     RECT  118.584 24.745 139.014 24.797 ;
     RECT  115.992 24.161 116.37 24.809 ;
     RECT  98.352 24.539 98.874 24.845 ;
     RECT  111.96 24.511 112.158 24.845 ;
     RECT  81.72 23.891 81.738 24.854 ;
     RECT  99.936 23.981 99.954 24.854 ;
     RECT  96.372 23.981 96.858 24.893 ;
     RECT  100.764 23.981 100.962 24.899 ;
     RECT  96.732 24.893 96.75 24.941 ;
     RECT  100.944 24.899 100.962 24.971 ;
     RECT  118.584 24.797 119.718 24.971 ;
     RECT  74.7 23.885 75.042 24.989 ;
     RECT  98.352 24.845 98.37 24.989 ;
     RECT  64.404 23.351 64.422 25.003 ;
     RECT  65.412 24.413 65.43 25.003 ;
     RECT  64.404 25.003 65.43 25.007 ;
     RECT  64.404 25.007 64.962 25.037 ;
     RECT  120.456 24.797 139.014 25.037 ;
     RECT  103.752 23.855 103.77 25.043 ;
     RECT  64.944 25.037 64.962 25.079 ;
     RECT  112.932 24.467 112.95 25.079 ;
     RECT  118.656 24.971 119.718 25.079 ;
     RECT  120.852 25.037 139.014 25.079 ;
     RECT  29.124 25.015 29.142 25.085 ;
     RECT  120.852 25.079 120.87 25.124 ;
     RECT  11.412 23.309 11.43 25.141 ;
     RECT  11.412 25.141 11.538 25.555 ;
     RECT  114.696 24.197 114.714 25.555 ;
     RECT  114.012 25.555 114.714 25.591 ;
     RECT  31.356 25.591 31.374 25.627 ;
     RECT  5.904 22.469 8.19 25.675 ;
     RECT  9.216 24.233 9.81 25.681 ;
     RECT  12.924 23.981 27.342 25.681 ;
     RECT  5.904 25.675 8.442 25.861 ;
     RECT  9.18 25.681 9.81 25.861 ;
     RECT  10.8 25.555 11.538 25.861 ;
     RECT  12.384 25.681 27.342 25.861 ;
     RECT  5.904 25.861 27.342 25.92 ;
     RECT  30.78 25.627 31.374 25.92 ;
     RECT  32.256 24.467 32.274 25.92 ;
     RECT  33.372 24.044 33.39 25.92 ;
     RECT  35.892 25.555 35.91 25.92 ;
     RECT  42.66 23.693 42.678 25.92 ;
     RECT  62.676 23.819 62.694 25.92 ;
     RECT  72.576 24.503 72.594 25.92 ;
     RECT  74.7 24.989 74.718 25.92 ;
     RECT  84.636 24.233 84.654 25.92 ;
     RECT  85.86 24.233 85.878 25.92 ;
     RECT  87.696 23.357 87.714 25.92 ;
     RECT  88.776 23.981 89.514 25.92 ;
     RECT  91.584 24.233 91.602 25.92 ;
     RECT  92.556 23.927 92.574 25.92 ;
     RECT  93.6 23.927 94.05 25.92 ;
     RECT  94.824 23.981 95.418 25.92 ;
     RECT  108.036 23.819 108.054 25.92 ;
     RECT  112.14 24.845 112.158 25.92 ;
     RECT  114.012 25.591 115.182 25.92 ;
     RECT  116.208 24.809 116.226 25.92 ;
     RECT  119.088 25.079 119.718 25.92 ;
     RECT  121.644 25.079 139.014 25.92 ;
     RECT  5.904 25.92 139.014 26.491 ;
     RECT  5.76 26.491 139.014 26.519 ;
     RECT  5.76 26.519 8.838 26.555 ;
     RECT  5.904 26.555 8.838 26.789 ;
     RECT  6.084 26.789 8.838 27.301 ;
     RECT  9.684 26.519 139.014 27.301 ;
     RECT  6.084 27.301 139.014 27.329 ;
     RECT  6.948 27.329 139.014 27.509 ;
     RECT  139.968 4.793 141.534 27.739 ;
     RECT  139.968 27.739 141.714 27.779 ;
     RECT  6.948 27.509 8.946 28.111 ;
     RECT  6.084 27.329 6.102 28.291 ;
     RECT  6.84 28.111 8.946 28.291 ;
     RECT  139.968 27.779 141.534 28.291 ;
     RECT  139.788 28.291 141.534 28.445 ;
     RECT  6.084 28.291 8.946 28.453 ;
     RECT  9.684 27.509 139.014 28.453 ;
     RECT  6.084 28.453 139.014 28.589 ;
     RECT  6.408 28.589 139.014 28.949 ;
     RECT  6.408 28.949 6.426 28.985 ;
     RECT  7.2 28.949 139.014 29.057 ;
     RECT  7.272 29.057 139.014 29.255 ;
     RECT  7.272 29.255 8.694 30.065 ;
     RECT  7.815 30.065 8.694 30.101 ;
     RECT  9.576 29.255 139.014 30.235 ;
     RECT  139.968 28.445 141.534 30.235 ;
     RECT  7.815 30.101 8.37 30.299 ;
     RECT  7.815 30.299 8.262 30.335 ;
     RECT  7.815 30.335 8.226 30.677 ;
     RECT  9.576 30.235 141.534 30.685 ;
     RECT  9.18 30.685 141.534 30.839 ;
     RECT  9.792 30.839 141.534 31.109 ;
     RECT  10.116 31.109 141.534 31.415 ;
     RECT  10.332 31.415 141.534 31.559 ;
     RECT  12.78 31.559 139.122 31.949 ;
     RECT  10.332 31.559 12.042 34.799 ;
     RECT  10.584 34.799 12.042 34.933 ;
     RECT  12.78 31.949 139.014 34.933 ;
     RECT  10.584 34.933 139.014 35.323 ;
     RECT  139.968 31.559 141.534 35.323 ;
     RECT  10.584 35.323 141.534 36.625 ;
     RECT  10.584 36.625 142.074 37.319 ;
     RECT  10.584 37.319 141.966 37.355 ;
     RECT  10.584 37.355 141.786 37.589 ;
     RECT  140.724 37.589 141.786 38.281 ;
     RECT  142.815 4.379 143.097 38.281 ;
     RECT  10.584 37.589 139.986 38.515 ;
     RECT  140.724 38.281 143.097 38.515 ;
     RECT  10.584 38.515 143.097 38.543 ;
     RECT  10.584 38.543 141.534 38.939 ;
     RECT  10.584 38.939 141.39 39.785 ;
     RECT  141.696 39.865 141.714 40.297 ;
     RECT  141.696 40.297 141.966 40.441 ;
     RECT  142.815 38.543 143.097 40.441 ;
     RECT  10.584 39.785 140.85 40.711 ;
     RECT  10.584 40.711 140.922 40.865 ;
     RECT  140.832 40.865 140.922 40.981 ;
     RECT  141.696 40.441 143.097 40.981 ;
     RECT  140.832 40.981 143.097 41.099 ;
     RECT  10.584 40.865 140.058 41.611 ;
     RECT  141.516 41.099 143.097 42.601 ;
     RECT  140.94 42.601 143.097 42.719 ;
     RECT  10.584 41.611 140.13 42.727 ;
     RECT  10.584 42.727 140.238 42.749 ;
     RECT  26.496 42.749 140.238 43.259 ;
     RECT  26.496 43.259 133.794 45.019 ;
     RECT  134.532 43.259 140.13 45.019 ;
     RECT  26.496 45.019 140.13 45.053 ;
     RECT  10.584 42.749 25.434 45.917 ;
     RECT  10.584 45.917 25.398 47.131 ;
     RECT  10.584 47.131 25.65 49.279 ;
     RECT  26.784 45.053 140.13 49.307 ;
     RECT  26.784 49.307 130.122 49.867 ;
     RECT  26.712 49.867 130.122 50.093 ;
     RECT  26.784 50.093 130.122 50.125 ;
     RECT  130.86 49.307 140.13 50.125 ;
     RECT  26.784 50.125 140.13 51.089 ;
     RECT  10.584 49.279 25.974 51.163 ;
     RECT  26.784 51.089 139.374 51.163 ;
     RECT  10.584 51.163 139.374 51.331 ;
     RECT  10.008 51.331 139.374 52.169 ;
     RECT  14.508 52.169 139.374 54.043 ;
     RECT  141.228 42.719 143.097 61.079 ;
     RECT  14.436 54.043 139.374 61.619 ;
     RECT  16.38 61.619 139.374 63.205 ;
     RECT  16.056 63.205 139.374 63.245 ;
     RECT  16.596 63.245 139.374 66.984 ;
     RECT  16.596 66.984 27.126 67.397 ;
     RECT  42.768 66.984 43.434 67.565 ;
     RECT  38.772 66.984 38.862 67.661 ;
     RECT  103.752 66.984 103.77 67.771 ;
     RECT  38.844 67.661 38.862 67.805 ;
     RECT  98.604 66.984 98.622 67.805 ;
     RECT  103.14 67.771 103.77 67.805 ;
     RECT  107.028 66.984 107.046 68.059 ;
     RECT  34.452 66.984 34.47 68.107 ;
     RECT  43.308 67.565 43.434 68.143 ;
     RECT  118.44 66.984 118.458 68.143 ;
     RECT  117.72 68.143 118.458 68.755 ;
     RECT  119.304 66.984 119.322 68.755 ;
     RECT  122.256 66.984 139.374 68.953 ;
     RECT  33.336 68.107 33.354 68.971 ;
     RECT  34.2 68.107 34.47 68.971 ;
     RECT  44.676 68.059 44.694 68.971 ;
     RECT  48.024 68.953 48.654 68.971 ;
     RECT  44.676 68.971 45.522 68.989 ;
     RECT  46.44 66.984 46.458 68.989 ;
     RECT  30.78 68.971 30.798 69.101 ;
     RECT  32.76 68.971 34.47 69.101 ;
     RECT  70.704 68.971 70.722 69.101 ;
     RECT  34.452 69.101 34.47 69.103 ;
     RECT  67.392 68.971 67.41 69.103 ;
     RECT  116.532 68.719 116.55 69.103 ;
     RECT  121.932 68.953 139.374 69.103 ;
     RECT  62.748 68.989 62.766 69.115 ;
     RECT  67.215 69.103 67.41 69.115 ;
     RECT  34.452 69.103 34.905 69.151 ;
     RECT  56.415 69.103 56.505 69.151 ;
     RECT  67.215 69.115 68.094 69.151 ;
     RECT  47.232 68.971 48.654 69.179 ;
     RECT  69.048 69.115 69.534 69.179 ;
     RECT  108.828 69.067 108.846 69.179 ;
     RECT  41.256 69.163 41.274 69.187 ;
     RECT  67.104 69.151 68.094 69.187 ;
     RECT  70.74 69.151 70.758 69.197 ;
     RECT  64.836 69.115 64.854 69.211 ;
     RECT  60.768 69.151 60.786 69.251 ;
     RECT  41.04 69.187 41.274 69.293 ;
     RECT  66.456 69.187 68.094 69.295 ;
     RECT  64.404 69.211 64.854 69.307 ;
     RECT  69.12 69.179 69.534 69.307 ;
     RECT  71.604 69.151 71.622 69.307 ;
     RECT  72.615 69.103 72.705 69.307 ;
     RECT  48.384 69.179 48.654 69.323 ;
     RECT  44.676 68.989 46.458 69.331 ;
     RECT  47.232 69.179 47.61 69.331 ;
     RECT  48.384 69.323 48.402 69.341 ;
     RECT  64.404 69.307 64.962 69.359 ;
     RECT  71.244 69.307 72.705 69.359 ;
     RECT  29.415 69.103 29.505 69.373 ;
     RECT  34.452 69.151 35.01 69.373 ;
     RECT  40.215 69.103 40.305 69.373 ;
     RECT  41.04 69.293 41.166 69.373 ;
     RECT  51.015 69.103 51.105 69.373 ;
     RECT  56.304 69.151 56.61 69.373 ;
     RECT  61.815 69.103 61.905 69.373 ;
     RECT  62.712 69.115 62.766 69.373 ;
     RECT  71.496 69.359 72.705 69.373 ;
     RECT  78.015 69.103 78.105 69.373 ;
     RECT  83.415 69.103 83.505 69.373 ;
     RECT  88.815 69.103 88.905 69.373 ;
     RECT  94.215 69.103 94.305 69.373 ;
     RECT  99.615 69.103 99.705 69.373 ;
     RECT  105.015 69.103 105.105 69.373 ;
     RECT  110.415 69.103 110.505 69.373 ;
     RECT  44.676 69.331 47.61 69.389 ;
     RECT  108.612 69.331 108.63 69.389 ;
     RECT  58.788 68.989 58.806 69.449 ;
     RECT  44.676 69.389 47.394 69.485 ;
     RECT  36.468 66.984 36.774 69.529 ;
     RECT  37.908 68.215 37.926 69.547 ;
     RECT  45.504 69.485 47.394 69.557 ;
     RECT  36.396 69.529 36.81 69.581 ;
     RECT  40.215 69.373 41.166 69.581 ;
     RECT  121.215 69.103 139.374 69.593 ;
     RECT  56.304 69.373 56.697 69.601 ;
     RECT  61.815 69.373 62.766 69.601 ;
     RECT  129.384 69.593 139.374 69.629 ;
     RECT  43.308 68.143 43.614 69.643 ;
     RECT  110.415 69.373 110.697 69.685 ;
     RECT  34.452 69.373 35.097 69.691 ;
     RECT  74.592 69.547 74.61 69.691 ;
     RECT  78.015 69.373 78.297 69.691 ;
     RECT  88.815 69.373 89.097 69.691 ;
     RECT  99.615 69.373 99.897 69.691 ;
     RECT  107.028 68.059 107.55 69.691 ;
     RECT  110.304 69.685 110.697 69.691 ;
     RECT  121.215 69.593 128.538 69.691 ;
     RECT  40.215 69.581 41.13 69.719 ;
     RECT  54.72 69.601 54.81 69.719 ;
     RECT  61.815 69.601 62.802 69.719 ;
     RECT  110.304 69.691 110.718 69.725 ;
     RECT  77.904 69.691 78.297 69.727 ;
     RECT  98.676 69.691 98.694 69.727 ;
     RECT  99.504 69.691 99.897 69.727 ;
     RECT  45.504 69.557 46.638 69.728 ;
     RECT  56.304 69.601 56.754 69.728 ;
     RECT  65.988 69.295 68.094 69.728 ;
     RECT  77.904 69.727 78.354 69.728 ;
     RECT  88.704 69.691 89.097 69.728 ;
     RECT  99.504 69.727 99.954 69.728 ;
     RECT  69.12 69.307 69.822 69.791 ;
     RECT  74.592 69.691 74.754 69.791 ;
     RECT  86.688 69.691 86.706 69.791 ;
     RECT  98.604 69.727 98.694 69.791 ;
     RECT  106.668 69.691 107.55 69.791 ;
     RECT  110.415 69.725 110.718 69.791 ;
     RECT  54.72 69.719 54.738 69.827 ;
     RECT  56.415 69.728 56.754 69.827 ;
     RECT  32.76 69.101 33.714 69.835 ;
     RECT  34.452 69.691 35.154 69.835 ;
     RECT  74.592 69.791 74.682 69.863 ;
     RECT  78.015 69.728 78.354 69.863 ;
     RECT  98.604 69.791 98.622 69.863 ;
     RECT  99.615 69.728 99.954 69.863 ;
     RECT  40.215 69.719 41.094 69.899 ;
     RECT  47.376 69.557 47.394 69.899 ;
     RECT  61.815 69.719 62.73 69.899 ;
     RECT  30.852 69.691 30.87 69.989 ;
     RECT  74.592 69.863 74.61 70.097 ;
     RECT  121.104 69.691 128.538 70.169 ;
     RECT  115.815 69.103 116.55 70.231 ;
     RECT  65.988 69.728 66.402 70.295 ;
     RECT  115.815 70.231 116.766 70.301 ;
     RECT  60.696 69.331 60.714 70.331 ;
     RECT  16.596 67.397 26.982 70.375 ;
     RECT  69.516 69.791 69.822 70.403 ;
     RECT  29.415 69.373 29.697 70.459 ;
     RECT  32.76 69.835 35.154 70.501 ;
     RECT  29.415 70.459 29.79 70.637 ;
     RECT  32.76 70.501 35.298 70.637 ;
     RECT  130.86 69.629 139.374 70.709 ;
     RECT  36.72 69.581 36.774 70.747 ;
     RECT  41.328 70.699 41.526 70.771 ;
     RECT  42.264 68.179 42.282 70.771 ;
     RECT  36.216 70.747 36.774 70.843 ;
     RECT  30.888 70.507 30.906 70.939 ;
     RECT  36.108 70.843 36.774 70.939 ;
     RECT  76.86 70.375 76.878 70.951 ;
     RECT  35.928 70.939 36.774 70.979 ;
     RECT  65.988 70.295 66.006 70.979 ;
     RECT  16.596 70.375 27.234 71.069 ;
     RECT  48.456 70.699 48.474 71.069 ;
     RECT  28.26 71.077 28.278 71.117 ;
     RECT  30.78 70.939 30.906 71.117 ;
     RECT  41.328 70.771 42.282 71.219 ;
     RECT  120.06 68.347 120.078 71.221 ;
     RECT  48.204 71.131 48.222 71.249 ;
     RECT  37.764 69.547 37.926 71.311 ;
     RECT  45.615 69.728 46.638 71.311 ;
     RECT  56.415 69.827 56.697 71.311 ;
     RECT  67.215 69.728 68.094 71.311 ;
     RECT  78.015 69.863 78.297 71.311 ;
     RECT  88.815 69.728 89.097 71.311 ;
     RECT  99.615 69.863 99.897 71.311 ;
     RECT  110.415 69.791 110.697 71.311 ;
     RECT  36.288 70.979 36.774 71.339 ;
     RECT  45.504 71.311 46.638 71.357 ;
     RECT  56.304 71.311 56.697 71.357 ;
     RECT  67.104 71.311 68.094 71.357 ;
     RECT  77.904 71.311 78.297 71.357 ;
     RECT  88.704 71.311 89.097 71.357 ;
     RECT  99.504 71.311 99.897 71.357 ;
     RECT  110.304 71.311 110.697 71.357 ;
     RECT  135.252 70.709 139.374 71.453 ;
     RECT  69.804 70.403 69.822 71.491 ;
     RECT  64.728 69.359 64.962 71.519 ;
     RECT  44.676 69.485 44.694 71.837 ;
     RECT  121.215 70.169 128.538 72.121 ;
     RECT  120.888 72.121 128.538 72.173 ;
     RECT  32.76 70.637 35.097 72.391 ;
     RECT  32.76 72.391 35.406 72.419 ;
     RECT  117.72 68.755 119.322 72.419 ;
     RECT  75.996 70.069 76.014 72.661 ;
     RECT  41.868 71.219 42.282 72.689 ;
     RECT  67.215 71.357 68.094 72.689 ;
     RECT  43.308 69.643 43.938 72.841 ;
     RECT  121.215 72.173 128.538 72.955 ;
     RECT  120.996 72.955 128.538 72.959 ;
     RECT  43.236 72.841 43.938 72.995 ;
     RECT  120.996 72.959 121.497 72.995 ;
     RECT  115.815 70.301 116.55 73.111 ;
     RECT  117.72 72.419 119.07 73.111 ;
     RECT  31.824 73.003 31.842 73.201 ;
     RECT  31.824 73.201 32.166 73.229 ;
     RECT  121.14 72.995 121.497 73.229 ;
     RECT  32.148 73.229 32.166 73.277 ;
     RECT  120.06 71.221 120.114 73.381 ;
     RECT  36.288 71.339 36.738 74.929 ;
     RECT  37.764 71.311 38.106 74.929 ;
     RECT  141.228 61.079 142.074 74.929 ;
     RECT  142.815 61.079 143.097 74.929 ;
     RECT  33.336 72.419 35.406 74.957 ;
     RECT  94.215 69.373 94.497 75.835 ;
     RECT  99.615 71.357 99.897 75.928 ;
     RECT  99.615 75.928 99.99 75.965 ;
     RECT  99.615 75.965 99.897 76.081 ;
     RECT  94.215 75.835 95.058 76.199 ;
     RECT  94.215 76.199 94.497 76.315 ;
     RECT  115.815 73.111 119.07 76.315 ;
     RECT  120.06 73.381 120.366 76.315 ;
     RECT  94.104 76.315 94.497 76.397 ;
     RECT  122.22 72.959 128.538 76.469 ;
     RECT  115.815 76.315 120.366 77.009 ;
     RECT  94.215 76.397 94.497 77.161 ;
     RECT  115.815 77.009 117.018 77.161 ;
     RECT  16.596 71.069 19.242 77.515 ;
     RECT  16.596 77.515 19.314 77.555 ;
     RECT  115.776 77.161 117.018 77.791 ;
     RECT  115.776 77.791 117.054 77.837 ;
     RECT  114.588 68.923 114.606 78.061 ;
     RECT  118.44 77.009 120.366 78.205 ;
     RECT  118.08 78.205 120.366 78.269 ;
     RECT  45.615 71.357 46.638 78.367 ;
     RECT  33.336 74.957 33.894 78.395 ;
     RECT  114.588 78.061 114.894 78.619 ;
     RECT  115.776 77.837 117.018 78.619 ;
     RECT  118.224 78.269 120.366 78.629 ;
     RECT  141.228 74.929 143.097 78.907 ;
     RECT  121.215 73.229 121.497 79.015 ;
     RECT  122.22 76.469 124.83 79.015 ;
     RECT  109.152 79.435 109.17 79.475 ;
     RECT  109.476 79.591 109.494 79.661 ;
     RECT  40.215 69.899 40.497 79.681 ;
     RECT  40.212 79.681 40.497 79.723 ;
     RECT  39.96 79.723 40.497 79.781 ;
     RECT  41.868 72.689 41.886 79.819 ;
     RECT  45.288 78.367 46.638 79.819 ;
     RECT  48.456 79.819 48.474 80.221 ;
     RECT  45.288 79.819 47.286 80.249 ;
     RECT  48.204 80.221 48.474 80.249 ;
     RECT  99.18 76.081 99.897 80.257 ;
     RECT  41.4 79.819 41.886 80.329 ;
     RECT  41.328 80.329 41.886 80.381 ;
     RECT  45.288 80.249 47.07 80.381 ;
     RECT  48.204 80.249 48.222 80.381 ;
     RECT  98.856 80.257 99.897 80.381 ;
     RECT  114.588 78.619 117.018 80.519 ;
     RECT  61.815 69.899 62.097 80.761 ;
     RECT  59.544 80.671 59.562 80.789 ;
     RECT  118.44 78.629 120.366 80.789 ;
     RECT  61.815 80.761 62.694 80.861 ;
     RECT  114.588 80.519 116.55 81.059 ;
     RECT  43.308 72.995 43.938 81.163 ;
     RECT  99.036 80.381 99.897 81.211 ;
     RECT  60.624 81.301 60.642 81.341 ;
     RECT  43.236 81.163 43.938 81.445 ;
     RECT  43.056 81.445 43.938 81.485 ;
     RECT  125.568 76.469 128.538 81.547 ;
     RECT  129.384 69.629 130.122 81.547 ;
     RECT  125.568 81.547 130.122 81.599 ;
     RECT  121.215 79.015 124.83 81.715 ;
     RECT  125.568 81.599 128.538 81.715 ;
     RECT  56.415 71.357 56.697 81.751 ;
     RECT  60.444 81.481 60.498 81.751 ;
     RECT  118.44 80.789 120.222 81.751 ;
     RECT  113.688 68.923 113.706 81.985 ;
     RECT  114.588 81.059 116.514 81.985 ;
     RECT  56.16 81.751 56.697 82.021 ;
     RECT  34.815 74.957 35.406 82.111 ;
     RECT  60.084 81.751 60.498 82.111 ;
     RECT  110.415 71.357 110.697 82.111 ;
     RECT  113.688 81.985 116.514 82.139 ;
     RECT  34.704 82.111 35.406 82.157 ;
     RECT  60.084 82.111 61.002 82.157 ;
     RECT  110.415 82.111 110.718 82.205 ;
     RECT  110.415 82.205 110.697 82.255 ;
     RECT  117.972 81.751 120.222 82.255 ;
     RECT  64.728 71.519 64.746 82.291 ;
     RECT  113.688 82.139 113.814 82.291 ;
     RECT  64.188 82.291 64.746 82.409 ;
     RECT  94.176 77.161 94.497 82.525 ;
     RECT  109.764 82.255 110.697 82.637 ;
     RECT  16.596 77.555 19.242 82.651 ;
     RECT  117.468 82.255 120.222 82.679 ;
     RECT  117.468 82.679 119.466 82.831 ;
     RECT  29.415 70.637 29.697 82.921 ;
     RECT  68.652 82.453 68.67 82.921 ;
     RECT  16.452 82.651 19.242 82.949 ;
     RECT  60.084 82.157 60.75 82.949 ;
     RECT  120.204 82.679 120.222 83.035 ;
     RECT  47.808 82.651 47.826 83.101 ;
     RECT  113.544 82.291 113.814 83.101 ;
     RECT  47.592 83.101 47.826 83.165 ;
     RECT  113.364 83.101 113.814 83.179 ;
     RECT  112.86 83.179 113.814 83.219 ;
     RECT  45.288 80.381 46.638 83.227 ;
     RECT  98.928 81.211 99.897 83.227 ;
     RECT  135.288 71.453 139.374 83.255 ;
     RECT  45.144 83.227 47.286 83.323 ;
     RECT  51.015 69.373 51.297 83.467 ;
     RECT  45 83.323 47.286 83.489 ;
     RECT  43.308 81.485 43.938 83.497 ;
     RECT  45 83.489 47.07 83.497 ;
     RECT  48.204 83.227 48.474 83.497 ;
     RECT  50.76 83.467 51.297 83.497 ;
     RECT  64.728 82.409 64.746 83.497 ;
     RECT  79.452 66.984 79.47 83.497 ;
     RECT  55.98 82.021 56.697 83.525 ;
     RECT  69.804 71.491 70.218 83.525 ;
     RECT  50.724 83.497 51.297 83.533 ;
     RECT  71.496 69.373 72.897 83.533 ;
     RECT  64.656 83.497 64.746 83.561 ;
     RECT  71.28 83.533 72.897 83.561 ;
     RECT  43.308 83.497 47.07 83.569 ;
     RECT  48.204 83.497 48.762 83.597 ;
     RECT  113.004 83.219 113.814 83.605 ;
     RECT  114.588 82.139 116.514 83.605 ;
     RECT  50.724 83.533 51.966 83.633 ;
     RECT  41.4 80.381 41.886 83.641 ;
     RECT  53.028 83.563 53.046 83.641 ;
     RECT  113.004 83.605 116.514 83.641 ;
     RECT  117.288 82.831 119.466 83.641 ;
     RECT  120.204 83.035 120.438 83.641 ;
     RECT  52.92 83.641 53.046 83.669 ;
     RECT  42.768 83.569 47.07 83.693 ;
     RECT  48.204 83.597 48.222 83.693 ;
     RECT  40.215 79.781 40.497 83.731 ;
     RECT  41.4 83.641 41.922 83.731 ;
     RECT  42.768 83.693 44.298 83.759 ;
     RECT  98.892 83.227 99.897 83.759 ;
     RECT  113.004 83.641 120.438 83.759 ;
     RECT  113.004 83.759 116.514 83.795 ;
     RECT  68.472 82.921 68.67 84.073 ;
     RECT  78.015 71.357 78.297 84.073 ;
     RECT  72.072 83.561 72.897 84.101 ;
     RECT  43.236 83.759 44.298 84.221 ;
     RECT  39.42 84.181 39.438 84.299 ;
     RECT  60.444 82.949 60.75 84.343 ;
     RECT  33.876 78.395 33.894 84.379 ;
     RECT  34.815 82.157 35.406 84.379 ;
     RECT  98.928 83.759 99.897 84.407 ;
     RECT  57.672 84.307 57.69 84.451 ;
     RECT  58.428 84.109 58.446 84.451 ;
     RECT  43.308 84.221 44.298 84.569 ;
     RECT  36.288 74.929 38.106 84.613 ;
     RECT  38.988 84.577 39.006 84.613 ;
     RECT  33.876 84.379 35.406 84.619 ;
     RECT  109.908 82.637 110.697 84.619 ;
     RECT  60.444 84.343 61.038 84.685 ;
     RECT  29.016 82.921 29.697 84.721 ;
     RECT  45.036 83.693 46.638 84.721 ;
     RECT  72.615 84.101 72.897 84.721 ;
     RECT  36.288 84.613 39.006 84.811 ;
     RECT  56.415 83.525 56.697 84.811 ;
     RECT  67.215 72.689 67.497 84.811 ;
     RECT  29.016 84.721 30.114 84.839 ;
     RECT  36.216 84.811 39.006 84.839 ;
     RECT  52.92 83.669 52.938 84.839 ;
     RECT  72.615 84.721 73.242 84.847 ;
     RECT  56.304 84.811 56.697 84.848 ;
     RECT  57.672 84.451 58.446 84.883 ;
     RECT  16.596 82.949 19.242 84.919 ;
     RECT  72.288 84.847 73.242 84.941 ;
     RECT  20.196 71.069 27.234 84.955 ;
     RECT  28.116 84.883 28.134 84.955 ;
     RECT  40.215 83.731 41.922 84.955 ;
     RECT  45.036 84.721 46.818 84.955 ;
     RECT  56.415 84.848 56.697 85.081 ;
     RECT  57.672 84.883 58.518 85.081 ;
     RECT  32.724 84.991 32.742 85.109 ;
     RECT  56.415 85.081 58.518 85.109 ;
     RECT  59.832 84.685 61.038 85.109 ;
     RECT  30.492 85.117 30.51 85.147 ;
     RECT  31.428 84.847 31.446 85.147 ;
     RECT  55.152 83.605 55.17 85.147 ;
     RECT  20.196 84.955 28.134 85.153 ;
     RECT  29.016 84.839 29.697 85.153 ;
     RECT  45.036 84.955 46.998 85.189 ;
     RECT  70.2 83.525 70.218 85.189 ;
     RECT  63.756 84.991 63.774 85.217 ;
     RECT  109.908 84.619 110.826 85.225 ;
     RECT  64.656 83.561 64.674 85.243 ;
     RECT  14.436 61.619 15.318 85.261 ;
     RECT  44.928 85.189 46.998 85.261 ;
     RECT  68.472 84.073 68.994 85.351 ;
     RECT  69.876 85.189 70.218 85.351 ;
     RECT  98.964 84.407 99.897 85.351 ;
     RECT  58.284 85.109 58.518 85.379 ;
     RECT  72.576 84.941 73.242 85.379 ;
     RECT  100.836 84.955 100.854 85.379 ;
     RECT  33.624 84.619 35.406 85.387 ;
     RECT  61.815 80.861 62.097 85.423 ;
     RECT  16.524 84.919 19.242 85.459 ;
     RECT  40.032 84.955 41.922 85.459 ;
     RECT  72.615 85.379 73.242 85.459 ;
     RECT  58.5 85.379 58.518 85.483 ;
     RECT  68.472 85.351 70.218 85.483 ;
     RECT  71.28 83.561 71.298 85.483 ;
     RECT  58.5 85.483 58.734 85.495 ;
     RECT  10.008 52.169 13.497 85.531 ;
     RECT  50.184 84.955 50.202 85.531 ;
     RECT  20.196 85.153 29.697 85.621 ;
     RECT  30.492 85.147 31.446 85.621 ;
     RECT  117.288 83.759 119.466 85.649 ;
     RECT  43.308 84.569 43.938 85.657 ;
     RECT  44.928 85.261 47.25 85.657 ;
     RECT  51.015 83.633 51.966 85.693 ;
     RECT  52.776 84.847 52.794 85.693 ;
     RECT  9.828 85.531 13.497 85.765 ;
     RECT  14.364 85.261 15.318 85.765 ;
     RECT  16.272 85.459 19.242 85.765 ;
     RECT  20.196 85.621 31.446 85.765 ;
     RECT  51.015 85.693 52.794 85.765 ;
     RECT  64.656 85.243 64.998 85.765 ;
     RECT  65.808 80.761 65.826 85.765 ;
     RECT  113.004 83.795 116.478 85.765 ;
     RECT  8.892 85.765 8.91 85.801 ;
     RECT  16.272 85.765 31.446 85.801 ;
     RECT  33.48 85.387 35.406 85.801 ;
     RECT  36.216 84.839 38.97 85.801 ;
     RECT  40.032 85.459 41.994 85.801 ;
     RECT  43.308 85.657 47.25 85.801 ;
     RECT  50.004 85.531 50.202 85.801 ;
     RECT  51.015 85.765 53.226 85.801 ;
     RECT  58.5 85.495 59.058 85.801 ;
     RECT  59.832 85.109 60.642 85.801 ;
     RECT  61.815 85.423 62.442 85.801 ;
     RECT  58.5 85.801 60.642 85.829 ;
     RECT  42.876 85.801 47.25 85.891 ;
     RECT  48.024 85.153 48.042 85.891 ;
     RECT  33.48 85.801 41.994 85.915 ;
     RECT  42.876 85.891 48.042 85.915 ;
     RECT  60.516 85.829 60.642 85.915 ;
     RECT  61.452 85.801 62.442 85.915 ;
     RECT  50.004 85.801 53.226 85.919 ;
     RECT  79.272 83.497 79.47 85.919 ;
     RECT  8.892 85.801 9.054 85.927 ;
     RECT  9.828 85.765 15.318 85.927 ;
     RECT  8.892 85.927 15.318 85.963 ;
     RECT  16.272 85.801 31.554 85.963 ;
     RECT  63.684 85.225 63.702 85.963 ;
     RECT  77.868 84.073 78.297 85.963 ;
     RECT  33.48 85.915 48.042 85.999 ;
     RECT  49.032 85.891 49.05 85.999 ;
     RECT  76.86 70.951 77.13 86.011 ;
     RECT  77.868 85.963 78.498 86.011 ;
     RECT  7.815 30.677 8.097 86.035 ;
     RECT  8.892 85.963 31.554 86.035 ;
     RECT  64.656 85.765 65.826 86.035 ;
     RECT  66.996 84.811 67.497 86.035 ;
     RECT  68.472 85.483 71.298 86.035 ;
     RECT  109.584 85.225 110.826 86.035 ;
     RECT  33.48 85.999 49.158 86.059 ;
     RECT  50.004 85.919 51.966 86.059 ;
     RECT  83.415 69.373 83.697 86.059 ;
     RECT  76.86 86.011 78.498 86.063 ;
     RECT  7.815 86.035 31.554 86.071 ;
     RECT  74.736 85.927 74.754 86.071 ;
     RECT  75.708 72.661 76.014 86.071 ;
     RECT  56.415 85.109 57.51 86.155 ;
     RECT  109.584 86.035 111.438 86.155 ;
     RECT  113.004 85.765 117.126 86.155 ;
     RECT  33.48 86.059 51.966 86.161 ;
     RECT  52.704 85.919 53.226 86.161 ;
     RECT  7.815 86.071 31.698 86.189 ;
     RECT  54.72 85.147 55.17 86.189 ;
     RECT  76.86 86.063 77.13 86.189 ;
     RECT  112.752 86.155 117.126 86.195 ;
     RECT  63.36 85.963 63.702 86.269 ;
     RECT  64.584 86.035 65.826 86.269 ;
     RECT  66.996 86.035 71.478 86.299 ;
     RECT  98.964 85.351 100.062 86.299 ;
     RECT  32.868 86.161 51.966 86.305 ;
     RECT  60.516 85.915 62.442 86.305 ;
     RECT  63.36 86.269 65.826 86.305 ;
     RECT  74.736 86.071 76.014 86.305 ;
     RECT  15.264 86.189 31.698 86.341 ;
     RECT  32.544 86.305 51.966 86.341 ;
     RECT  56.415 86.155 57.69 86.341 ;
     RECT  58.5 85.829 59.454 86.341 ;
     RECT  60.516 86.305 65.826 86.341 ;
     RECT  66.744 86.299 71.478 86.341 ;
     RECT  72.615 85.459 73.602 86.341 ;
     RECT  74.736 86.305 76.05 86.341 ;
     RECT  76.86 86.189 76.95 86.341 ;
     RECT  117.9 85.649 119.466 86.341 ;
     RECT  120.204 83.759 120.222 86.341 ;
     RECT  98.28 86.299 100.062 86.369 ;
     RECT  121.215 81.715 128.538 86.369 ;
     RECT  56.415 86.341 59.454 86.443 ;
     RECT  102.348 86.059 102.366 86.443 ;
     RECT  103.14 67.805 103.158 86.443 ;
     RECT  7.815 86.189 14.454 86.459 ;
     RECT  102.348 86.443 103.158 86.573 ;
     RECT  54.72 86.189 55.062 86.575 ;
     RECT  60.516 86.341 73.602 86.575 ;
     RECT  74.736 86.341 76.95 86.575 ;
     RECT  52.704 86.161 53.37 86.611 ;
     RECT  54.252 86.575 55.062 86.611 ;
     RECT  56.196 86.443 59.454 86.611 ;
     RECT  98.388 86.369 100.062 86.611 ;
     RECT  100.98 86.443 101.394 86.611 ;
     RECT  105.015 69.373 105.297 86.611 ;
     RECT  79.452 85.919 79.47 86.635 ;
     RECT  88.815 71.357 89.097 86.635 ;
     RECT  94.14 82.525 94.497 86.635 ;
     RECT  96.876 68.923 96.894 86.635 ;
     RECT  98.388 86.611 100.17 86.635 ;
     RECT  100.98 86.611 102.294 86.635 ;
     RECT  105.015 86.611 105.39 86.669 ;
     RECT  85.428 86.635 85.446 86.683 ;
     RECT  96.444 86.635 96.894 86.683 ;
     RECT  105.015 86.669 105.297 86.683 ;
     RECT  107.028 69.791 107.55 86.683 ;
     RECT  60.516 86.575 76.95 86.701 ;
     RECT  81.648 66.984 81.666 86.701 ;
     RECT  109.44 86.155 111.438 86.701 ;
     RECT  56.196 86.611 59.598 86.728 ;
     RECT  60.372 86.701 76.95 86.728 ;
     RECT  109.188 86.701 111.798 86.728 ;
     RECT  88.815 86.635 90.09 86.729 ;
     RECT  98.388 86.635 102.294 86.729 ;
     RECT  106.812 86.683 107.55 86.729 ;
     RECT  117.9 86.341 120.222 86.729 ;
     RECT  93.636 86.635 94.497 86.779 ;
     RECT  15.264 86.341 51.966 86.809 ;
     RECT  52.704 86.611 55.062 86.809 ;
     RECT  7.815 86.459 12.294 86.845 ;
     RECT  77.868 86.063 78.498 86.845 ;
     RECT  79.452 86.635 79.938 86.845 ;
     RECT  112.896 86.195 117.126 86.845 ;
     RECT  56.196 86.728 76.95 86.881 ;
     RECT  77.868 86.845 80.55 86.881 ;
     RECT  81.648 86.701 82.386 86.881 ;
     RECT  87.984 86.635 88.002 86.881 ;
     RECT  93.636 86.779 94.878 86.881 ;
     RECT  135.288 83.255 138.006 86.881 ;
     RECT  139.032 83.255 139.374 86.881 ;
     RECT  15.264 86.809 55.062 86.971 ;
     RECT  55.908 86.881 76.95 86.971 ;
     RECT  77.868 86.881 80.694 86.971 ;
     RECT  112.896 86.845 117.846 86.971 ;
     RECT  15.264 86.971 80.694 86.999 ;
     RECT  92.628 86.635 92.646 86.999 ;
     RECT  98.604 86.729 102.294 86.999 ;
     RECT  108.828 86.728 111.798 87.019 ;
     RECT  15.264 86.999 59.598 87.035 ;
     RECT  81.612 86.881 82.386 87.053 ;
     RECT  106.812 86.729 107.478 87.053 ;
     RECT  108.36 87.019 111.798 87.053 ;
     RECT  80.388 86.999 80.694 87.115 ;
     RECT  80.388 87.115 80.766 87.151 ;
     RECT  81.612 87.053 81.774 87.151 ;
     RECT  83.232 86.059 83.697 87.151 ;
     RECT  85.428 86.683 85.626 87.151 ;
     RECT  86.94 86.635 86.958 87.151 ;
     RECT  93.636 86.881 95.49 87.151 ;
     RECT  96.444 86.683 97.542 87.151 ;
     RECT  104.4 86.683 105.297 87.151 ;
     RECT  106.812 87.053 107.226 87.151 ;
     RECT  109.188 87.053 111.798 87.151 ;
     RECT  124.344 86.369 128.538 87.151 ;
     RECT  129.384 81.599 130.122 87.151 ;
     RECT  140.112 51.089 140.13 87.151 ;
     RECT  140.976 78.907 143.097 87.151 ;
     RECT  13.14 86.459 14.454 87.211 ;
     RECT  15.264 87.035 59.562 87.211 ;
     RECT  83.16 87.151 83.697 87.211 ;
     RECT  85.428 87.151 85.806 87.211 ;
     RECT  86.868 87.151 86.958 87.211 ;
     RECT  87.912 86.881 88.002 87.211 ;
     RECT  88.815 86.729 90.054 87.211 ;
     RECT  93.564 87.151 95.49 87.211 ;
     RECT  96.408 87.151 97.542 87.211 ;
     RECT  103.14 86.573 103.158 87.211 ;
     RECT  104.292 87.151 105.297 87.211 ;
     RECT  109.188 87.151 112.014 87.241 ;
     RECT  112.86 86.971 117.846 87.241 ;
     RECT  135.288 86.881 139.374 87.241 ;
     RECT  140.112 87.151 143.097 87.241 ;
     RECT  60.336 86.999 79.47 87.269 ;
     RECT  92.52 87.151 92.538 87.269 ;
     RECT  118.584 86.729 120.222 87.269 ;
     RECT  6.48 47.083 6.498 87.277 ;
     RECT  7.74 86.845 12.294 87.277 ;
     RECT  60.336 87.269 77.166 87.305 ;
     RECT  118.62 87.269 120.222 87.413 ;
     RECT  6.3 87.277 12.294 87.421 ;
     RECT  13.14 87.211 59.562 87.421 ;
     RECT  91.26 87.211 91.674 87.421 ;
     RECT  103.14 87.211 105.297 87.421 ;
     RECT  106.596 87.151 107.226 87.421 ;
     RECT  93.564 87.211 97.542 87.499 ;
     RECT  84.744 87.211 90.054 87.539 ;
     RECT  103.068 87.421 107.226 87.539 ;
     RECT  6.3 87.421 59.562 87.547 ;
     RECT  98.604 86.999 102.15 87.547 ;
     RECT  5.796 87.547 59.562 87.575 ;
     RECT  5.796 87.575 49.266 87.691 ;
     RECT  91.26 87.421 91.746 87.691 ;
     RECT  93.312 87.499 97.542 87.691 ;
     RECT  98.46 87.547 102.15 87.691 ;
     RECT  121.215 86.369 123.534 87.691 ;
     RECT  124.344 87.151 130.122 87.691 ;
     RECT  91.116 87.691 91.746 87.767 ;
     RECT  82.584 87.211 83.697 87.781 ;
     RECT  84.744 87.539 89.694 87.781 ;
     RECT  93.312 87.691 102.15 87.781 ;
     RECT  92.664 87.781 102.15 87.787 ;
     RECT  108.36 87.053 108.414 87.787 ;
     RECT  50.04 87.575 59.562 87.809 ;
     RECT  103.464 87.539 107.226 87.817 ;
     RECT  82.584 87.781 89.694 87.845 ;
     RECT  77.976 87.269 79.47 87.889 ;
     RECT  80.388 87.151 81.774 87.889 ;
     RECT  56.196 87.809 59.562 87.925 ;
     RECT  60.336 87.305 76.986 87.925 ;
     RECT  121.215 87.691 130.122 87.925 ;
     RECT  130.86 70.709 134.514 87.925 ;
     RECT  135.252 87.241 143.097 87.925 ;
     RECT  5.76 87.691 49.266 87.961 ;
     RECT  82.584 87.845 85.518 87.961 ;
     RECT  103.464 87.817 107.334 87.961 ;
     RECT  108.108 87.787 108.414 87.961 ;
     RECT  109.188 87.241 117.846 87.961 ;
     RECT  118.908 87.413 120.222 87.961 ;
     RECT  121.215 87.925 143.097 87.961 ;
     RECT  92.664 87.787 102.546 88.123 ;
     RECT  50.04 87.809 55.422 88.187 ;
     RECT  103.464 87.961 117.846 88.195 ;
     RECT  56.196 87.925 76.986 88.231 ;
     RECT  77.976 87.889 81.774 88.231 ;
     RECT  82.548 87.961 85.518 88.231 ;
     RECT  90.504 87.767 91.746 88.231 ;
     RECT  92.484 88.123 102.546 88.231 ;
     RECT  103.464 88.195 117.99 88.231 ;
     RECT  103.464 88.231 118.134 88.312 ;
     RECT  118.908 87.961 143.097 88.312 ;
     RECT  56.196 88.231 85.518 88.385 ;
     RECT  5.148 87.961 49.266 88.393 ;
     RECT  50.04 88.187 51.75 88.393 ;
     RECT  5.148 88.393 51.75 88.501 ;
     RECT  103.464 88.312 143.097 88.501 ;
     RECT  103.464 88.501 143.154 88.655 ;
     RECT  52.488 88.187 55.422 88.771 ;
     RECT  56.196 88.385 62.55 88.771 ;
     RECT  63.432 88.385 85.518 88.771 ;
     RECT  86.292 87.845 89.694 88.771 ;
     RECT  90.504 88.231 102.546 88.771 ;
     RECT  103.464 88.655 143.097 88.771 ;
     RECT  4.968 88.501 51.75 89.005 ;
     RECT  52.488 88.771 62.55 89.005 ;
     RECT  4.824 89.005 62.55 89.275 ;
     RECT  63.432 88.771 143.097 89.275 ;
     RECT  4.824 89.275 143.097 89.311 ;
     RECT  2.415 2.413 2.697 89.387 ;
     RECT  4.5 89.311 143.097 89.387 ;
     RECT  4.5 89.387 72.738 89.429 ;
     RECT  73.476 89.387 142.905 89.429 ;
     RECT  4.572 89.429 26.01 89.549 ;
     RECT  26.748 89.429 72.705 89.549 ;
     RECT  74.232 89.429 142.905 89.549 ;
     RECT  2.415 89.387 2.505 89.657 ;
     RECT  6.696 89.549 7.905 89.657 ;
     RECT  30.96 89.549 35.19 89.657 ;
     RECT  40.215 89.549 44.694 89.657 ;
     RECT  45.615 89.549 48.906 89.657 ;
     RECT  49.968 89.549 51.105 89.657 ;
     RECT  53.1 89.549 56.505 89.657 ;
     RECT  71.064 89.549 72.705 89.657 ;
     RECT  77.4 89.549 80.586 89.657 ;
     RECT  83.415 89.549 83.754 89.657 ;
     RECT  88.815 89.549 89.01 89.657 ;
     RECT  96.372 89.549 99.705 89.657 ;
     RECT  123.804 89.549 128.07 89.657 ;
     RECT  141.768 89.549 142.905 89.657 ;
     RECT  94.176 89.549 95.346 89.735 ;
     RECT  11.952 89.549 14.094 89.789 ;
     RECT  23.58 89.549 26.01 89.789 ;
     RECT  59.436 89.549 63.702 89.789 ;
     RECT  71.064 89.657 72.594 89.789 ;
     RECT  120.672 89.549 122.778 89.789 ;
     RECT  6.696 89.657 7.758 90.077 ;
     RECT  8.784 89.549 10.926 90.077 ;
     RECT  11.952 89.789 13.05 90.077 ;
     RECT  16.2 89.549 20.43 90.077 ;
     RECT  21.456 89.549 22.518 90.077 ;
     RECT  24.624 89.789 26.01 90.077 ;
     RECT  27.792 89.549 29.934 90.077 ;
     RECT  30.96 89.657 34.146 90.077 ;
     RECT  36.216 89.549 39.402 90.077 ;
     RECT  40.464 89.657 44.694 90.077 ;
     RECT  45.72 89.657 48.906 90.077 ;
     RECT  49.968 89.657 51.03 90.077 ;
     RECT  53.1 89.657 56.286 90.077 ;
     RECT  57.348 89.549 58.41 90.077 ;
     RECT  59.436 89.789 61.578 90.077 ;
     RECT  62.604 89.789 63.702 90.077 ;
     RECT  66.852 89.549 68.958 90.077 ;
     RECT  71.064 89.789 72.126 90.077 ;
     RECT  78.444 89.657 80.586 90.077 ;
     RECT  81.612 89.549 82.674 90.077 ;
     RECT  86.868 89.549 87.966 90.077 ;
     RECT  92.16 89.549 93.222 90.077 ;
     RECT  94.284 89.735 95.346 90.077 ;
     RECT  96.372 89.657 99.558 90.077 ;
     RECT  102.708 89.549 109.062 90.077 ;
     RECT  110.088 89.549 113.274 90.077 ;
     RECT  114.336 89.549 119.61 90.077 ;
     RECT  121.716 89.789 122.778 90.077 ;
     RECT  123.804 89.657 125.946 90.077 ;
     RECT  126.972 89.657 128.07 90.077 ;
     RECT  131.22 89.549 132.282 90.077 ;
     RECT  133.308 89.549 135.45 90.077 ;
     RECT  136.476 89.549 137.574 90.077 ;
     RECT  141.768 89.657 142.29 90.605 ;
     RECT  17.244 90.077 19.35 90.653 ;
     RECT  25.668 90.077 26.01 90.653 ;
     RECT  32.004 90.077 33.102 90.653 ;
     RECT  45.72 90.077 47.862 90.653 ;
     RECT  53.1 90.077 55.242 90.653 ;
     RECT  60.516 90.077 61.578 90.653 ;
     RECT  67.896 90.077 68.958 90.653 ;
     RECT  73.476 89.429 73.494 90.653 ;
     RECT  96.372 90.077 97.47 90.653 ;
     RECT  103.752 90.077 104.85 90.653 ;
     RECT  117.504 90.077 118.566 90.653 ;
     RECT  123.804 90.077 124.902 90.653 ;
     RECT  18.288 90.653 19.35 91.181 ;
     RECT  46.8 90.653 47.862 91.181 ;
     RECT  110.088 90.077 111.186 91.181 ;
    LAYER M4 ;
     RECT  2.408 2.148 2.512 89.652 ;
     RECT  2.512 2.418 2.704 89.382 ;
     RECT  5.125 0.192 5.321 0.216 ;
     RECT  4.669 3.408 5.749 3.432 ;
     RECT  5.708 26.496 5.795 26.52 ;
     RECT  5.749 16.176 5.965 16.2 ;
     RECT  5.077 89.52 6.179 89.544 ;
     RECT  5.749 3.408 6.371 4.152 ;
     RECT  5.965 16.176 6.371 16.488 ;
     RECT  5.137 88.32 6.397 88.344 ;
     RECT  6.397 88.32 6.833 88.392 ;
     RECT  7.153 90.048 7.237 90.072 ;
     RECT  6.721 17.616 7.429 17.64 ;
     RECT  7.549 28.08 7.585 28.104 ;
     RECT  7.585 28.08 7.649 28.44 ;
     RECT  7.369 29.76 7.649 29.784 ;
     RECT  7.429 19.536 7.669 19.56 ;
     RECT  7.649 28.08 7.669 29.784 ;
     RECT  6.371 3.408 7.808 3.96 ;
     RECT  6.371 16.464 7.808 16.488 ;
     RECT  7.429 17.568 7.808 17.64 ;
     RECT  7.669 19.536 7.808 19.704 ;
     RECT  7.669 27.312 7.808 29.784 ;
     RECT  6.833 88.368 7.808 88.392 ;
     RECT  7.808 2.148 7.912 89.652 ;
     RECT  7.912 2.418 8.104 89.544 ;
     RECT  8.104 26.736 8.281 26.76 ;
     RECT  8.104 89.52 8.332 89.544 ;
     RECT  8.104 25.68 8.483 25.704 ;
     RECT  8.104 28.416 8.525 28.68 ;
     RECT  8.104 3.312 9.059 3.336 ;
     RECT  8.104 86.496 9.107 88.392 ;
     RECT  8.525 28.656 9.157 28.68 ;
     RECT  9.107 86.496 9.173 87.144 ;
     RECT  9.157 28.656 9.203 29.208 ;
     RECT  9.157 30.768 9.244 30.792 ;
     RECT  9.203 29.184 9.245 29.208 ;
     RECT  9.107 88.368 10.105 88.392 ;
     RECT  10.141 25.872 10.364 25.896 ;
     RECT  10.105 88.32 10.393 88.392 ;
     RECT  9.205 90.048 10.403 90.072 ;
     RECT  10.321 28.992 10.405 29.016 ;
     RECT  10.393 87.936 10.429 88.392 ;
     RECT  10.364 25.872 10.451 26.856 ;
     RECT  10.405 28.992 10.465 29.112 ;
     RECT  9.173 86.496 10.465 86.52 ;
     RECT  10.429 87.552 10.465 88.392 ;
     RECT  10.465 86.496 10.469 88.392 ;
     RECT  10.465 27.312 10.537 29.928 ;
     RECT  10.321 52.992 10.681 53.016 ;
     RECT  10.537 27.312 10.739 30.168 ;
     RECT  10.739 27.36 10.789 30.168 ;
     RECT  10.789 27.36 10.793 30.36 ;
     RECT  10.469 86.496 10.865 88.344 ;
     RECT  10.681 52.992 10.897 53.112 ;
     RECT  10.793 27.36 10.901 29.112 ;
     RECT  10.645 16.272 10.925 16.296 ;
     RECT  10.925 15.984 10.94 16.296 ;
     RECT  8.104 4.512 10.979 4.536 ;
     RECT  10.94 15.984 11.009 16.44 ;
     RECT  10.793 30.144 11.009 30.36 ;
     RECT  11.009 16.272 11.027 16.44 ;
     RECT  10.451 25.872 11.027 25.896 ;
     RECT  10.897 52.992 11.041 53.544 ;
     RECT  11.041 52.752 11.077 53.544 ;
     RECT  10.865 86.496 11.081 88.2 ;
     RECT  11.009 30.336 11.189 30.36 ;
     RECT  10.933 3.312 11.297 3.336 ;
     RECT  11.081 86.496 11.365 86.52 ;
     RECT  10.901 27.408 11.369 29.112 ;
     RECT  10.177 19.248 11.413 19.272 ;
     RECT  8.104 17.616 11.459 17.64 ;
     RECT  11.372 89.52 11.459 89.544 ;
     RECT  11.413 18.816 11.765 19.272 ;
     RECT  11.369 27.408 11.981 29.064 ;
     RECT  8.104 22.752 12.013 22.776 ;
     RECT  11.365 86.352 12.017 86.52 ;
     RECT  6.181 1.152 12.053 1.176 ;
     RECT  11.081 87.552 12.053 88.2 ;
     RECT  11.981 27.408 12.085 28.728 ;
     RECT  12.013 22.752 12.133 23.304 ;
     RECT  11.869 30.768 12.157 30.792 ;
     RECT  11.905 3.696 12.188 3.72 ;
     RECT  12.157 30.624 12.325 30.792 ;
     RECT  11.077 52.752 12.373 53.592 ;
     RECT  12.445 90.048 12.529 90.072 ;
     RECT  12.085 27.264 12.769 28.728 ;
     RECT  12.325 30.624 12.769 31.368 ;
     RECT  12.769 27.024 12.949 28.728 ;
     RECT  12.769 29.904 12.949 31.368 ;
     RECT  12.188 3.696 13.208 4.536 ;
     RECT  11.027 16.272 13.208 16.296 ;
     RECT  11.765 19.248 13.208 19.272 ;
     RECT  12.133 22.56 13.208 23.304 ;
     RECT  12.949 27.024 13.208 31.368 ;
     RECT  13.045 36.192 13.208 36.216 ;
     RECT  12.373 52.752 13.208 53.832 ;
     RECT  12.017 86.496 13.208 86.52 ;
     RECT  12.053 87.792 13.208 88.2 ;
     RECT  13.208 2.148 13.312 89.784 ;
     RECT  13.312 2.418 13.504 89.784 ;
     RECT  13.504 89.76 13.571 89.784 ;
     RECT  13.504 22.56 13.645 23.352 ;
     RECT  13.504 37.824 13.66 38.904 ;
     RECT  13.504 39.984 13.709 41.064 ;
     RECT  13.504 20.496 13.715 20.52 ;
     RECT  13.645 22.56 13.715 23.304 ;
     RECT  13.504 4.272 13.907 4.536 ;
     RECT  13.504 25.056 13.907 25.608 ;
     RECT  13.504 31.776 13.907 31.8 ;
     RECT  13.504 26.784 13.961 30.792 ;
     RECT  13.907 25.056 14.243 25.08 ;
     RECT  13.504 19.248 14.249 19.368 ;
     RECT  13.709 39.984 14.291 40.008 ;
     RECT  13.709 41.04 14.329 41.064 ;
     RECT  13.504 16.272 14.531 16.296 ;
     RECT  13.961 26.784 14.54 30.696 ;
     RECT  13.504 86.016 14.581 88.632 ;
     RECT  13.715 23.136 14.773 23.304 ;
     RECT  13.66 38.64 14.789 38.664 ;
     RECT  14.497 63.216 14.821 63.24 ;
     RECT  14.249 19.248 14.825 19.272 ;
     RECT  14.821 63.072 14.861 63.24 ;
     RECT  14.773 22.176 14.867 23.304 ;
     RECT  14.54 26.688 14.893 30.696 ;
     RECT  14.821 24.576 14.905 24.6 ;
     RECT  13.907 4.272 15.011 4.296 ;
     RECT  12.661 0.192 15.149 0.216 ;
     RECT  14.893 25.872 15.181 30.696 ;
     RECT  14.581 86.016 15.251 89.544 ;
     RECT  15.181 25.872 15.253 30.936 ;
     RECT  13.504 52.752 15.289 54.072 ;
     RECT  15.251 86.016 15.293 86.616 ;
     RECT  15.217 35.088 15.349 35.112 ;
     RECT  15.253 25.584 15.404 31.032 ;
     RECT  15.361 33.072 15.445 33.096 ;
     RECT  15.253 40.896 15.469 40.92 ;
     RECT  15.404 25.584 15.491 31.896 ;
     RECT  14.867 22.176 15.541 22.2 ;
     RECT  15.469 40.752 15.541 40.92 ;
     RECT  15.361 42.288 15.541 42.312 ;
     RECT  15.293 86.016 15.617 86.52 ;
     RECT  15.491 25.584 15.635 31.8 ;
     RECT  15.145 37.056 15.649 37.08 ;
     RECT  15.251 87.792 15.683 89.544 ;
     RECT  15.349 35.088 15.685 35.352 ;
     RECT  15.505 45.696 15.685 45.72 ;
     RECT  15.685 35.088 15.721 35.832 ;
     RECT  15.649 36.864 15.721 37.08 ;
     RECT  14.867 23.28 15.757 23.304 ;
     RECT  15.445 33.072 15.901 33.24 ;
     RECT  15.541 40.752 15.932 42.312 ;
     RECT  15.932 40.224 15.973 42.312 ;
     RECT  15.721 35.088 15.98 37.08 ;
     RECT  14.861 63.072 16.028 63.096 ;
     RECT  15.98 34.608 16.045 37.08 ;
     RECT  15.973 38.688 16.045 38.712 ;
     RECT  16.045 34.608 16.067 38.712 ;
     RECT  16.028 63.072 16.115 63.24 ;
     RECT  15.617 86.496 16.115 86.52 ;
     RECT  15.757 23.28 16.117 24.216 ;
     RECT  15.635 25.584 16.117 26.424 ;
     RECT  16.067 35.52 16.117 38.712 ;
     RECT  15.973 40.08 16.117 42.312 ;
     RECT  15.577 3.936 16.201 3.96 ;
     RECT  15.901 32.928 16.364 33.24 ;
     RECT  16.115 63.072 16.369 63.096 ;
     RECT  15.541 21.744 16.501 22.2 ;
     RECT  15.289 52.752 16.513 54.168 ;
     RECT  16.513 52.752 16.585 54.216 ;
     RECT  16.657 90.048 16.741 90.072 ;
     RECT  15.635 27.456 16.789 31.8 ;
     RECT  16.364 32.928 16.789 34.488 ;
     RECT  16.369 63.024 16.837 63.096 ;
     RECT  16.513 86.592 16.837 86.616 ;
     RECT  15.683 87.792 16.837 88.632 ;
     RECT  16.501 21.744 16.933 22.296 ;
     RECT  16.933 21.408 16.981 22.296 ;
     RECT  16.117 23.28 16.981 26.424 ;
     RECT  16.117 35.52 16.981 42.312 ;
     RECT  16.789 27.456 17.027 34.488 ;
     RECT  16.621 60.048 17.029 60.072 ;
     RECT  16.981 21.408 17.053 26.424 ;
     RECT  17.027 27.456 17.053 33.096 ;
     RECT  16.837 86.592 17.075 88.92 ;
     RECT  16.585 52.752 17.089 54.696 ;
     RECT  16.837 44.688 17.221 44.712 ;
     RECT  15.685 45.696 17.221 45.816 ;
     RECT  17.027 34.08 17.276 34.488 ;
     RECT  16.981 35.52 17.276 42.504 ;
     RECT  17.029 60.048 17.324 60.696 ;
     RECT  15.925 1.152 17.525 1.176 ;
     RECT  17.413 57.84 17.593 57.864 ;
     RECT  16.837 62.976 17.629 63.096 ;
     RECT  17.161 43.488 17.653 43.512 ;
     RECT  17.324 59.808 17.66 60.696 ;
     RECT  17.593 57.84 17.701 57.96 ;
     RECT  17.653 43.488 17.737 43.608 ;
     RECT  17.221 44.688 17.737 45.816 ;
     RECT  16.441 82.656 17.749 82.68 ;
     RECT  17.629 90.624 17.795 90.648 ;
     RECT  17.737 43.488 17.809 45.816 ;
     RECT  17.413 47.328 17.809 47.352 ;
     RECT  17.629 3.936 17.9 3.96 ;
     RECT  17.629 62.448 17.917 63.096 ;
     RECT  17.053 21.408 18.061 33.096 ;
     RECT  17.276 34.08 18.061 42.504 ;
     RECT  18.085 0.192 18.173 0.216 ;
     RECT  17.075 87.168 18.241 88.92 ;
     RECT  17.653 20.352 18.277 20.376 ;
     RECT  18.061 21.408 18.277 42.504 ;
     RECT  17.809 43.488 18.277 47.352 ;
     RECT  18.277 21.408 18.469 47.352 ;
     RECT  17.9 3.744 18.608 3.96 ;
     RECT  17.804 5.04 18.608 5.064 ;
     RECT  17.989 8.208 18.608 8.232 ;
     RECT  17.365 11.664 18.608 11.688 ;
     RECT  17.077 13.92 18.608 13.944 ;
     RECT  18.277 20.352 18.608 20.424 ;
     RECT  18.469 21.408 18.608 47.928 ;
     RECT  17.089 52.752 18.608 54.888 ;
     RECT  17.701 57.312 18.608 57.96 ;
     RECT  17.66 59.712 18.608 60.696 ;
     RECT  17.917 62.448 18.608 63.528 ;
     RECT  17.365 73.248 18.608 73.272 ;
     RECT  17.737 78.048 18.608 78.072 ;
     RECT  17.749 82.656 18.608 83.16 ;
     RECT  18.241 86.592 18.608 88.92 ;
     RECT  18.608 2.148 18.712 89.652 ;
     RECT  18.767 91.152 18.865 91.176 ;
     RECT  18.712 2.418 18.904 89.382 ;
     RECT  18.904 56.64 19.001 57.96 ;
     RECT  18.904 86.544 19.043 86.616 ;
     RECT  18.904 3.696 19.331 4.872 ;
     RECT  18.904 77.52 19.331 77.544 ;
     RECT  19.043 86.592 19.433 86.616 ;
     RECT  19.331 4.848 19.715 4.872 ;
     RECT  19.789 90.048 19.907 90.072 ;
     RECT  18.904 47.808 19.955 47.832 ;
     RECT  19.331 3.696 19.973 3.816 ;
     RECT  18.904 51.36 20.005 54.936 ;
     RECT  18.904 20.4 20.045 46.776 ;
     RECT  18.904 49.2 20.257 49.224 ;
     RECT  18.904 70.704 20.257 70.728 ;
     RECT  18.904 13.92 20.293 13.944 ;
     RECT  20.257 49.2 20.329 49.848 ;
     RECT  19.001 56.64 20.341 57.912 ;
     RECT  20.149 58.944 20.341 58.968 ;
     RECT  20.329 48.96 20.365 49.848 ;
     RECT  18.904 19.296 20.389 19.32 ;
     RECT  20.365 48.48 20.401 49.848 ;
     RECT  20.005 51.312 20.509 54.936 ;
     RECT  18.904 88.368 20.509 88.92 ;
     RECT  20.509 51.312 20.617 55.272 ;
     RECT  20.341 56.64 20.617 58.968 ;
     RECT  20.245 17.424 20.821 17.448 ;
     RECT  20.389 18.768 20.821 19.32 ;
     RECT  18.904 73.248 20.821 73.272 ;
     RECT  20.401 48.48 20.869 50.088 ;
     RECT  20.617 51.312 20.869 58.968 ;
     RECT  20.045 44.688 20.873 46.776 ;
     RECT  20.509 87.984 20.876 88.92 ;
     RECT  20.876 87.984 20.963 89.544 ;
     RECT  19.973 3.696 20.965 3.72 ;
     RECT  20.257 70.704 20.965 71.304 ;
     RECT  20.965 3.696 21.013 4.488 ;
     RECT  20.965 70.32 21.061 71.304 ;
     RECT  20.045 20.4 21.085 43.704 ;
     RECT  18.904 8.208 21.205 8.232 ;
     RECT  18.904 10.032 21.397 10.056 ;
     RECT  20.869 48.48 21.397 58.968 ;
     RECT  21.061 70.32 21.409 71.448 ;
     RECT  18.904 11.664 21.493 11.688 ;
     RECT  21.397 48.384 21.493 58.968 ;
     RECT  21.397 67.152 21.493 67.176 ;
     RECT  21.493 67.152 21.541 67.224 ;
     RECT  21.517 68.4 21.541 68.424 ;
     RECT  20.101 5.52 21.733 5.544 ;
     RECT  21.085 20.352 21.733 43.704 ;
     RECT  20.873 44.688 21.733 46.632 ;
     RECT  21.013 3.36 21.877 4.488 ;
     RECT  21.733 5.52 21.877 6.024 ;
     RECT  19.141 1.152 21.953 1.176 ;
     RECT  21.409 70.128 22.021 71.448 ;
     RECT  21.949 90.048 22.033 90.072 ;
     RECT  21.541 67.152 22.057 68.424 ;
     RECT  22.021 69.84 22.057 71.448 ;
     RECT  18.904 61.872 22.165 64.776 ;
     RECT  18.904 60 22.201 60.84 ;
     RECT  22.165 61.872 22.201 65.496 ;
     RECT  21.493 47.664 22.309 58.968 ;
     RECT  21.205 7.68 22.357 8.232 ;
     RECT  21.733 20.352 22.412 46.632 ;
     RECT  22.309 47.616 22.412 58.968 ;
     RECT  21.877 3.312 22.465 6.024 ;
     RECT  22.405 0.192 22.493 0.216 ;
     RECT  22.057 67.152 22.597 71.448 ;
     RECT  20.963 87.984 22.597 88.776 ;
     RECT  22.465 5.472 22.693 6.024 ;
     RECT  22.357 7.104 22.693 8.232 ;
     RECT  22.412 20.352 22.789 58.968 ;
     RECT  22.201 60 22.789 65.496 ;
     RECT  22.465 3.312 22.813 4.488 ;
     RECT  20.821 17.424 22.885 19.32 ;
     RECT  22.789 20.352 22.889 65.496 ;
     RECT  22.597 67.056 22.933 71.448 ;
     RECT  22.597 87.936 22.957 88.776 ;
     RECT  22.885 17.424 22.981 19.368 ;
     RECT  22.889 20.352 22.981 43.704 ;
     RECT  20.101 78.912 23.029 78.936 ;
     RECT  21.229 85.872 23.221 85.896 ;
     RECT  23.125 81.168 23.317 81.192 ;
     RECT  23.173 82.224 23.317 82.248 ;
     RECT  23.221 85.776 23.317 85.896 ;
     RECT  23.317 85.776 23.605 86.52 ;
     RECT  22.933 66.864 23.797 71.448 ;
     RECT  22.981 17.424 23.845 43.704 ;
     RECT  22.813 3.12 24.008 4.488 ;
     RECT  22.693 5.472 24.008 8.232 ;
     RECT  21.397 9.36 24.008 10.056 ;
     RECT  21.493 11.184 24.008 11.688 ;
     RECT  18.904 12.768 24.008 12.792 ;
     RECT  20.293 13.92 24.008 13.992 ;
     RECT  23.845 16.56 24.008 43.704 ;
     RECT  22.889 44.688 24.008 65.496 ;
     RECT  23.797 66.864 24.008 71.496 ;
     RECT  20.821 73.104 24.008 73.272 ;
     RECT  23.029 78.912 24.008 79.752 ;
     RECT  23.317 81.168 24.008 82.248 ;
     RECT  23.605 84.864 24.008 86.52 ;
     RECT  22.957 87.936 24.008 89.544 ;
     RECT  24.008 2.148 24.085 89.652 ;
     RECT  24.085 2.148 24.112 89.784 ;
     RECT  24.112 2.418 24.304 89.784 ;
     RECT  24.304 81.168 24.437 82.152 ;
     RECT  24.304 66.72 24.617 71.496 ;
     RECT  23.461 0.192 24.869 0.216 ;
     RECT  24.304 3.12 25.157 4.488 ;
     RECT  25.081 90.048 25.187 90.072 ;
     RECT  24.304 13.92 25.265 14.952 ;
     RECT  24.304 84.672 25.373 88.728 ;
     RECT  24.617 66.864 25.58 71.496 ;
     RECT  25.373 84.672 25.697 88.392 ;
     RECT  25.697 84.672 25.829 87.816 ;
     RECT  25.829 84.384 25.913 87.816 ;
     RECT  24.304 16.56 25.945 65.592 ;
     RECT  24.437 81.312 25.981 82.152 ;
     RECT  25.981 81.312 26.093 82.68 ;
     RECT  25.157 3.36 26.101 4.488 ;
     RECT  24.304 5.472 26.101 8.232 ;
     RECT  25.265 13.92 26.147 14.376 ;
     RECT  25.945 16.56 26.161 65.688 ;
     RECT  25.58 66.72 26.161 71.496 ;
     RECT  25.981 90.624 26.243 90.648 ;
     RECT  26.293 83.328 26.581 83.352 ;
     RECT  26.101 3.36 26.633 8.232 ;
     RECT  24.304 73.104 26.773 73.272 ;
     RECT  25.913 84.624 27.277 87.816 ;
     RECT  27.253 89.52 27.277 89.544 ;
     RECT  27.277 84.624 27.34 89.544 ;
     RECT  26.161 16.56 27.349 71.496 ;
     RECT  27.349 16.224 27.389 71.496 ;
     RECT  27.389 16.224 27.677 16.248 ;
     RECT  26.633 3.36 28.604 4.488 ;
     RECT  26.633 5.472 28.604 8.232 ;
     RECT  26.147 13.92 28.645 13.992 ;
     RECT  28.645 13.92 28.897 14.376 ;
     RECT  28.897 13.92 29.077 14.76 ;
     RECT  25.621 1.152 29.405 1.176 ;
     RECT  28.604 3.36 29.408 8.232 ;
     RECT  24.304 9.36 29.408 10.056 ;
     RECT  24.304 11.184 29.408 11.688 ;
     RECT  24.304 12.768 29.408 12.792 ;
     RECT  29.077 13.872 29.408 14.76 ;
     RECT  27.389 17.424 29.408 71.496 ;
     RECT  26.773 73.008 29.408 73.272 ;
     RECT  24.304 78.912 29.408 79.752 ;
     RECT  26.093 81.312 29.408 82.152 ;
     RECT  26.581 83.328 29.408 83.496 ;
     RECT  27.34 84.624 29.408 88.632 ;
     RECT  28.213 90.048 29.408 90.072 ;
     RECT  29.408 2.148 29.411 90.072 ;
     RECT  29.411 2.148 29.512 89.652 ;
     RECT  29.512 2.418 29.704 89.544 ;
     RECT  29.704 89.52 30.467 89.544 ;
     RECT  29.704 13.872 30.515 15.192 ;
     RECT  29.704 16.224 30.556 16.248 ;
     RECT  30.515 15.168 30.805 15.192 ;
     RECT  30.805 15.168 31.043 16.008 ;
     RECT  29.704 84.624 31.057 87.672 ;
     RECT  31.057 84.624 31.093 88.248 ;
     RECT  29.704 3.36 31.436 4.488 ;
     RECT  29.704 5.472 31.436 8.232 ;
     RECT  30.515 13.872 31.477 13.944 ;
     RECT  31.043 15.168 31.477 15.24 ;
     RECT  31.436 3.36 31.523 8.232 ;
     RECT  31.453 90.048 31.537 90.072 ;
     RECT  29.704 73.008 31.853 73.272 ;
     RECT  29.704 17.424 31.861 71.496 ;
     RECT  31.861 17.04 31.948 71.496 ;
     RECT  31.093 84.624 32.177 88.872 ;
     RECT  31.853 73.248 32.241 73.272 ;
     RECT  29.941 0.192 32.321 0.216 ;
     RECT  29.704 12.768 32.389 12.792 ;
     RECT  31.477 13.872 32.389 15.24 ;
     RECT  32.461 90.624 32.579 90.648 ;
     RECT  32.677 16.416 32.771 16.44 ;
     RECT  32.389 12.768 32.869 15.24 ;
     RECT  29.704 81.312 33.349 82.152 ;
     RECT  33.349 81.168 33.397 82.152 ;
     RECT  29.704 83.328 33.397 83.496 ;
     RECT  31.948 17.424 33.637 71.496 ;
     RECT  32.177 84.624 33.653 88.68 ;
     RECT  33.589 90.048 33.676 90.072 ;
     RECT  32.869 12.768 33.683 16.008 ;
     RECT  33.205 1.152 34.085 1.176 ;
     RECT  34.261 0.192 34.373 0.216 ;
     RECT  33.653 84.672 34.645 88.68 ;
     RECT  31.523 3.36 34.808 4.488 ;
     RECT  31.523 5.472 34.808 8.232 ;
     RECT  29.704 9.36 34.808 10.056 ;
     RECT  29.704 11.184 34.808 11.688 ;
     RECT  33.683 12.768 34.808 13.944 ;
     RECT  33.683 15.216 34.808 16.008 ;
     RECT  33.637 17.136 34.808 71.496 ;
     RECT  29.704 78.912 34.808 79.752 ;
     RECT  33.397 81.168 34.808 83.496 ;
     RECT  34.645 84.672 34.808 89.544 ;
     RECT  34.808 2.148 34.912 89.652 ;
     RECT  34.912 2.418 35.104 89.544 ;
     RECT  35.104 89.52 35.813 89.544 ;
     RECT  35.365 0.288 35.921 0.312 ;
     RECT  35.104 84.672 36.097 88.104 ;
     RECT  35.104 15.168 36.313 15.432 ;
     RECT  35.104 16.512 36.313 71.496 ;
     RECT  36.097 84.672 36.533 88.92 ;
     RECT  35.104 3.36 36.601 4.488 ;
     RECT  35.104 5.472 36.601 8.232 ;
     RECT  36.313 15.168 36.641 71.496 ;
     RECT  36.533 84.816 37.109 88.92 ;
     RECT  36.641 15.168 37.331 16.248 ;
     RECT  36.421 1.152 37.649 1.176 ;
     RECT  37.109 84.816 38.365 88.44 ;
     RECT  36.601 3.36 38.483 8.232 ;
     RECT  35.104 12.768 38.629 13.992 ;
     RECT  37.331 15.168 38.629 16.008 ;
     RECT  38.581 0.192 38.665 0.216 ;
     RECT  38.629 12.768 38.675 16.008 ;
     RECT  36.637 90.048 38.915 90.072 ;
     RECT  35.104 11.184 39.481 11.688 ;
     RECT  38.675 12.768 39.481 15.72 ;
     RECT  35.104 78.912 39.589 79.752 ;
     RECT  39.481 11.184 39.661 15.72 ;
     RECT  38.365 84.816 39.884 88.92 ;
     RECT  39.685 1.152 40.133 1.176 ;
     RECT  38.483 3.36 40.208 4.488 ;
     RECT  38.483 5.472 40.208 8.232 ;
     RECT  35.104 9.36 40.208 10.056 ;
     RECT  39.661 11.184 40.208 16.008 ;
     RECT  36.641 17.424 40.208 71.496 ;
     RECT  39.589 78.912 40.208 79.848 ;
     RECT  35.104 81.168 40.208 83.496 ;
     RECT  39.884 84.816 40.208 89.544 ;
     RECT  40.208 2.148 40.312 89.652 ;
     RECT  40.312 2.418 40.504 89.652 ;
     RECT  40.741 0.576 40.825 0.6 ;
     RECT  40.504 84.816 41.267 88.92 ;
     RECT  40.504 15.168 41.321 15.864 ;
     RECT  40.504 78.912 41.363 83.496 ;
     RECT  41.363 78.912 41.537 79.896 ;
     RECT  40.504 17.424 41.564 71.496 ;
     RECT  41.564 16.944 41.651 71.496 ;
     RECT  41.845 0.192 41.933 0.216 ;
     RECT  40.504 12.768 42.421 13.992 ;
     RECT  41.321 15.168 42.421 15.192 ;
     RECT  41.267 84.816 43.009 87.672 ;
     RECT  41.267 88.896 43.009 88.92 ;
     RECT  41.363 81.168 43.045 83.496 ;
     RECT  43.045 81.168 43.196 83.832 ;
     RECT  43.009 84.816 43.196 88.92 ;
     RECT  43.196 81.168 43.265 88.92 ;
     RECT  43.265 81.312 43.283 88.92 ;
     RECT  42.901 1.152 43.373 1.176 ;
     RECT  43.283 81.312 43.373 83.832 ;
     RECT  40.504 11.184 43.573 11.688 ;
     RECT  42.421 12.768 43.573 15.192 ;
     RECT  43.283 84.816 43.907 88.92 ;
     RECT  43.573 11.184 43.955 15.192 ;
     RECT  40.504 3.36 44.06 4.488 ;
     RECT  40.504 5.472 44.06 8.232 ;
     RECT  44.06 3.36 44.147 8.232 ;
     RECT  40.849 90.048 44.195 90.072 ;
     RECT  44.005 0.192 44.309 0.216 ;
     RECT  43.955 11.184 44.381 13.992 ;
     RECT  41.651 17.424 44.636 71.496 ;
     RECT  43.373 81.312 44.732 83.496 ;
     RECT  45.061 0.576 45.497 0.6 ;
     RECT  44.636 17.424 45.529 71.832 ;
     RECT  44.147 3.36 45.608 4.488 ;
     RECT  44.147 5.472 45.608 8.232 ;
     RECT  40.504 9.36 45.608 10.056 ;
     RECT  44.381 11.184 45.608 11.688 ;
     RECT  44.381 12.768 45.608 13.992 ;
     RECT  43.955 15.168 45.608 15.192 ;
     RECT  45.529 17.184 45.608 71.832 ;
     RECT  41.537 78.912 45.608 78.936 ;
     RECT  44.732 81.312 45.608 83.688 ;
     RECT  43.907 84.816 45.608 88.392 ;
     RECT  45.164 89.52 45.608 89.544 ;
     RECT  45.608 2.148 45.712 89.652 ;
     RECT  45.712 2.418 45.904 89.382 ;
     RECT  45.904 17.04 46.045 71.496 ;
     RECT  45.904 12.768 46.067 14.664 ;
     RECT  45.904 81.312 46.217 83.496 ;
     RECT  46.069 90.624 46.307 90.648 ;
     RECT  45.904 78.912 46.933 78.936 ;
     RECT  46.217 83.232 47.036 83.496 ;
     RECT  46.933 78.912 47.041 79.848 ;
     RECT  46.217 81.312 47.041 82.152 ;
     RECT  47.036 83.232 47.123 83.688 ;
     RECT  47.041 78.912 47.297 82.152 ;
     RECT  46.165 0.192 47.305 0.216 ;
     RECT  45.904 3.36 47.324 4.488 ;
     RECT  45.904 5.472 47.324 8.232 ;
     RECT  47.221 91.152 47.363 91.176 ;
     RECT  47.324 3.36 47.411 8.232 ;
     RECT  46.067 13.92 47.473 14.664 ;
     RECT  45.904 15.648 47.473 15.672 ;
     RECT  45.904 84.816 47.477 88.68 ;
     RECT  47.297 80.352 47.509 82.152 ;
     RECT  47.123 83.232 47.509 83.496 ;
     RECT  47.509 80.352 47.837 83.496 ;
     RECT  47.473 13.92 47.893 15.672 ;
     RECT  46.045 17.184 47.939 71.496 ;
     RECT  47.477 88.656 47.977 88.68 ;
     RECT  47.893 13.92 47.98 15.912 ;
     RECT  47.837 83.232 48.188 83.496 ;
     RECT  48.188 83.232 48.275 83.688 ;
     RECT  47.297 78.912 48.277 78.936 ;
     RECT  47.837 80.352 48.277 82.152 ;
     RECT  47.411 3.36 48.409 4.488 ;
     RECT  47.411 5.472 48.409 8.232 ;
     RECT  48.277 78.912 48.419 82.152 ;
     RECT  48.301 90.048 48.419 90.072 ;
     RECT  48.419 78.912 48.485 79.848 ;
     RECT  48.275 83.232 48.485 83.496 ;
     RECT  47.477 84.816 48.805 87.672 ;
     RECT  47.977 88.656 48.805 88.92 ;
     RECT  48.805 84.816 48.892 88.92 ;
     RECT  47.98 13.92 49.025 15.432 ;
     RECT  48.892 88.896 49.169 88.92 ;
     RECT  49.388 89.52 49.475 89.544 ;
     RECT  48.409 3.36 49.484 8.232 ;
     RECT  49.484 3.312 49.571 8.232 ;
     RECT  49.025 13.92 49.571 14.856 ;
     RECT  49.571 3.36 49.612 8.232 ;
     RECT  48.325 1.152 49.637 1.176 ;
     RECT  50.453 0.192 50.537 0.216 ;
     RECT  50.461 90.048 50.545 90.072 ;
     RECT  48.892 84.816 50.725 87.816 ;
     RECT  48.485 83.472 50.749 83.496 ;
     RECT  49.612 3.36 51.008 4.488 ;
     RECT  49.612 5.472 51.008 8.232 ;
     RECT  45.904 9.36 51.008 10.056 ;
     RECT  45.904 11.136 51.008 11.688 ;
     RECT  46.067 12.768 51.008 12.792 ;
     RECT  49.571 13.92 51.008 14.664 ;
     RECT  47.939 17.424 51.008 71.496 ;
     RECT  48.485 78.912 51.008 78.936 ;
     RECT  48.419 81.312 51.008 82.152 ;
     RECT  50.749 83.472 51.008 83.592 ;
     RECT  50.725 84.816 51.008 87.864 ;
     RECT  51.008 2.148 51.112 89.652 ;
     RECT  51.112 2.418 51.304 89.544 ;
     RECT  51.304 84.816 51.628 89.544 ;
     RECT  51.541 0.192 51.653 0.216 ;
     RECT  51.628 84.816 52.597 88.632 ;
     RECT  52.597 84.816 52.684 89.544 ;
     RECT  51.304 83.568 53.057 83.592 ;
     RECT  51.304 11.136 53.309 11.688 ;
     RECT  51.304 3.36 53.341 4.488 ;
     RECT  51.304 5.472 53.341 10.056 ;
     RECT  52.645 1.152 54.173 1.176 ;
     RECT  52.684 84.816 54.749 88.632 ;
     RECT  51.304 13.92 54.755 14.664 ;
     RECT  53.521 90.624 54.755 90.648 ;
     RECT  51.304 12.768 54.821 12.792 ;
     RECT  54.805 0.192 54.929 0.216 ;
     RECT  55.753 90.048 55.837 90.072 ;
     RECT  55.861 0.576 55.945 0.6 ;
     RECT  53.341 3.36 56.408 10.056 ;
     RECT  53.309 11.184 56.408 11.688 ;
     RECT  54.755 13.92 56.408 13.992 ;
     RECT  51.304 17.424 56.408 71.496 ;
     RECT  51.304 78.912 56.408 78.936 ;
     RECT  51.304 81.312 56.408 82.152 ;
     RECT  54.749 84.816 56.408 88.488 ;
     RECT  56.408 2.148 56.512 89.652 ;
     RECT  56.512 2.418 56.704 89.544 ;
     RECT  56.704 89.52 56.819 89.544 ;
     RECT  56.965 1.152 57.053 1.176 ;
     RECT  57.805 90.048 57.889 90.072 ;
     RECT  56.704 3.936 58.453 4.488 ;
     RECT  58.021 1.728 58.745 1.752 ;
     RECT  58.813 89.52 58.931 89.544 ;
     RECT  59.125 0.192 59.213 0.216 ;
     RECT  58.453 3.408 59.717 4.488 ;
     RECT  56.704 84.816 59.749 88.488 ;
     RECT  59.857 90.048 59.987 90.072 ;
     RECT  56.704 81.312 60.653 82.152 ;
     RECT  59.717 3.936 60.716 4.488 ;
     RECT  60.716 3.888 60.757 4.488 ;
     RECT  56.704 5.472 60.757 8.232 ;
     RECT  60.757 3.888 60.803 8.232 ;
     RECT  60.937 90.624 61.043 90.648 ;
     RECT  60.181 1.152 61.733 1.176 ;
     RECT  60.803 3.936 61.808 8.232 ;
     RECT  56.704 9.36 61.808 10.056 ;
     RECT  56.704 11.184 61.808 11.688 ;
     RECT  56.704 13.92 61.808 13.944 ;
     RECT  56.704 17.424 61.808 71.496 ;
     RECT  56.704 78.912 61.808 78.936 ;
     RECT  60.653 82.128 61.808 82.152 ;
     RECT  59.749 84.816 61.808 88.536 ;
     RECT  61.808 2.148 61.912 89.652 ;
     RECT  61.912 2.418 62.012 89.652 ;
     RECT  62.012 2.418 62.099 89.784 ;
     RECT  62.099 2.418 62.104 89.382 ;
     RECT  62.341 0.192 62.489 0.216 ;
     RECT  62.104 3.216 62.993 5.496 ;
     RECT  62.104 13.92 63.137 13.944 ;
     RECT  62.104 11.184 63.173 11.688 ;
     RECT  63.097 90.048 63.181 90.072 ;
     RECT  62.104 84.816 63.205 87.864 ;
     RECT  63.445 1.152 63.965 1.176 ;
     RECT  64.105 89.52 64.211 89.544 ;
     RECT  63.205 84.816 64.325 88.344 ;
     RECT  63.173 11.184 64.901 11.208 ;
     RECT  65.077 13.056 65.173 13.08 ;
     RECT  64.325 84.816 65.581 87.912 ;
     RECT  64.501 0.192 65.657 0.216 ;
     RECT  62.993 3.936 65.945 5.496 ;
     RECT  65.173 12.96 66.229 13.08 ;
     RECT  65.945 3.936 66.625 3.96 ;
     RECT  66.661 1.728 67.208 1.752 ;
     RECT  66.625 3.408 67.208 3.96 ;
     RECT  65.945 4.944 67.208 5.496 ;
     RECT  62.104 6.528 67.208 8.232 ;
     RECT  62.104 9.36 67.208 10.056 ;
     RECT  66.229 12.528 67.208 13.08 ;
     RECT  62.104 17.424 67.208 71.496 ;
     RECT  62.104 78.912 67.208 78.936 ;
     RECT  65.581 84.816 67.208 88.392 ;
     RECT  65.221 89.52 67.208 89.544 ;
     RECT  67.208 1.728 67.301 89.652 ;
     RECT  67.301 1.728 67.385 90.072 ;
     RECT  67.385 2.418 67.504 89.382 ;
     RECT  67.504 87.12 67.565 88.392 ;
     RECT  67.504 3.408 67.601 5.496 ;
     RECT  67.601 3.936 67.781 5.496 ;
     RECT  67.765 1.152 68.069 1.176 ;
     RECT  67.565 87.12 68.147 87.816 ;
     RECT  67.781 4.512 68.213 5.496 ;
     RECT  67.504 12.96 68.429 12.984 ;
     RECT  68.317 90.624 68.435 90.648 ;
     RECT  68.147 87.408 68.501 87.816 ;
     RECT  68.821 0.192 68.969 0.216 ;
     RECT  68.857 3.36 69.404 3.384 ;
     RECT  69.397 14.928 69.445 14.952 ;
     RECT  69.404 3.36 69.491 4.296 ;
     RECT  68.501 87.408 69.505 87.432 ;
     RECT  67.504 85.392 69.509 85.752 ;
     RECT  69.505 87.024 69.581 87.432 ;
     RECT  67.504 6.528 69.617 8.232 ;
     RECT  69.445 89.52 69.649 89.544 ;
     RECT  69.491 3.696 70.049 3.72 ;
     RECT  67.504 17.424 70.193 71.496 ;
     RECT  69.925 1.152 70.445 1.176 ;
     RECT  69.649 88.896 70.547 89.544 ;
     RECT  69.445 14.832 70.697 14.952 ;
     RECT  69.617 6.528 70.733 7.704 ;
     RECT  69.509 85.488 70.733 85.512 ;
     RECT  70.547 88.896 70.765 88.92 ;
     RECT  70.549 3.984 71.089 4.008 ;
     RECT  70.765 88.368 71.165 88.92 ;
     RECT  70.981 0.192 71.237 0.216 ;
     RECT  71.089 3.168 71.267 4.008 ;
     RECT  70.733 6.528 71.273 6.552 ;
     RECT  70.441 13.584 71.365 13.608 ;
     RECT  70.697 14.832 71.365 14.856 ;
     RECT  71.365 13.056 71.411 14.856 ;
     RECT  70.733 7.68 71.561 7.704 ;
     RECT  71.521 90.048 71.605 90.072 ;
     RECT  69.581 87.024 71.773 87.192 ;
     RECT  71.165 88.368 71.773 88.392 ;
     RECT  68.213 5.472 71.9 5.496 ;
     RECT  71.411 13.056 71.941 14.04 ;
     RECT  71.267 3.744 72.601 3.768 ;
     RECT  71.9 4.848 72.601 5.496 ;
     RECT  72.601 3.744 72.608 5.496 ;
     RECT  71.941 12.912 72.608 14.04 ;
     RECT  70.193 17.952 72.608 71.496 ;
     RECT  67.504 78.912 72.608 78.936 ;
     RECT  72.277 84.912 72.608 84.936 ;
     RECT  71.773 87.024 72.608 88.392 ;
     RECT  72.565 89.76 72.608 89.784 ;
     RECT  72.608 2.148 72.659 89.784 ;
     RECT  72.659 2.148 72.712 89.652 ;
     RECT  72.712 2.418 72.904 89.382 ;
     RECT  72.904 3.936 73.109 4.152 ;
     RECT  70.165 91.584 73.181 91.608 ;
     RECT  72.904 84.912 73.235 84.936 ;
     RECT  72.904 86.64 73.261 88.392 ;
     RECT  73.261 87.024 73.475 88.392 ;
     RECT  73.465 90.624 73.715 90.648 ;
     RECT  73.475 87.024 73.865 88.152 ;
     RECT  73.109 3.936 74.243 3.96 ;
     RECT  72.904 12.384 74.243 12.504 ;
     RECT  73.865 87.024 74.977 87.72 ;
     RECT  72.904 18.768 75.049 71.496 ;
     RECT  72.085 1.152 75.233 1.176 ;
     RECT  75.049 18.672 75.637 71.496 ;
     RECT  72.904 13.536 75.733 13.608 ;
     RECT  75.301 14.592 75.733 14.616 ;
     RECT  75.301 0.192 75.773 0.216 ;
     RECT  74.243 12.48 75.875 12.504 ;
     RECT  75.733 13.536 75.916 14.616 ;
     RECT  74.977 87.024 75.917 88.104 ;
     RECT  74.401 4.368 75.985 4.392 ;
     RECT  75.916 13.632 76.069 14.616 ;
     RECT  75.985 3.936 76.115 4.392 ;
     RECT  76.069 13.632 76.421 14.808 ;
     RECT  76.237 4.512 76.597 4.536 ;
     RECT  75.637 18.24 76.597 71.496 ;
     RECT  76.597 11.424 76.681 11.448 ;
     RECT  75.917 87.024 76.921 87.624 ;
     RECT  76.921 86.976 76.94 87.624 ;
     RECT  76.94 86.976 76.981 87.72 ;
     RECT  76.981 86.976 77.201 88.392 ;
     RECT  76.421 13.632 77.497 14.088 ;
     RECT  77.497 13.632 77.797 14.664 ;
     RECT  77.221 3.168 78.008 3.192 ;
     RECT  76.597 4.512 78.008 5.112 ;
     RECT  77.797 13.632 78.008 15.576 ;
     RECT  76.597 18.192 78.008 71.496 ;
     RECT  72.904 78.912 78.008 78.936 ;
     RECT  77.201 86.016 78.008 88.392 ;
     RECT  74.725 89.52 78.008 89.544 ;
     RECT  78.008 2.148 78.112 89.652 ;
     RECT  78.112 2.418 78.304 89.652 ;
     RECT  78.304 86.016 78.563 86.04 ;
     RECT  76.405 1.152 78.905 1.176 ;
     RECT  78.304 4.272 78.947 4.872 ;
     RECT  78.304 14.64 79.549 15.576 ;
     RECT  78.304 87.024 79.625 88.824 ;
     RECT  79.621 0.192 79.733 0.216 ;
     RECT  79.549 14.208 79.861 15.576 ;
     RECT  79.625 87.024 79.909 87.576 ;
     RECT  79.909 86.64 79.993 87.576 ;
     RECT  78.865 90.048 80.051 90.072 ;
     RECT  79.861 14.112 80.381 15.576 ;
     RECT  79.909 3.408 80.525 3.432 ;
     RECT  79.993 87.024 80.665 87.576 ;
     RECT  79.625 88.8 80.665 88.824 ;
     RECT  80.629 13.008 80.915 13.032 ;
     RECT  80.869 4.848 80.956 4.872 ;
     RECT  80.725 1.152 80.993 1.176 ;
     RECT  80.665 87.024 81.02 88.824 ;
     RECT  81.02 87.024 81.107 89.544 ;
     RECT  78.304 18.768 81.241 71.496 ;
     RECT  81.241 18.72 81.589 71.496 ;
     RECT  80.381 14.208 81.713 15.576 ;
     RECT  81.107 87.024 81.749 88.824 ;
     RECT  81.749 87.024 81.997 87.576 ;
     RECT  81.745 3.552 82.105 3.576 ;
     RECT  82.105 90.048 82.189 90.072 ;
     RECT  81.673 17.088 82.309 17.112 ;
     RECT  81.589 18.24 82.309 71.496 ;
     RECT  82.105 3.312 82.355 3.576 ;
     RECT  82.309 17.088 82.396 71.496 ;
     RECT  81.713 14.208 82.607 14.664 ;
     RECT  82.396 17.088 82.645 17.112 ;
     RECT  82.429 4.8 82.885 4.824 ;
     RECT  82.645 15.696 82.885 15.72 ;
     RECT  82.645 17.04 82.885 17.112 ;
     RECT  81.997 86.736 82.885 87.576 ;
     RECT  81.781 0.192 82.973 0.216 ;
     RECT  81.749 88.8 83.113 88.824 ;
     RECT  82.885 4.272 83.408 4.824 ;
     RECT  82.607 14.112 83.408 14.664 ;
     RECT  82.885 15.696 83.408 17.112 ;
     RECT  82.396 18.144 83.408 71.496 ;
     RECT  78.304 78.912 83.408 78.936 ;
     RECT  82.885 86.064 83.408 87.576 ;
     RECT  83.113 88.8 83.408 89.544 ;
     RECT  83.408 2.148 83.512 89.652 ;
     RECT  83.512 2.418 83.704 89.544 ;
     RECT  83.704 17.088 83.765 71.496 ;
     RECT  83.704 86.736 84.053 87.816 ;
     RECT  83.941 0.576 84.161 0.6 ;
     RECT  83.704 3.408 84.413 3.72 ;
     RECT  84.413 3.696 84.419 3.72 ;
     RECT  83.765 17.28 84.701 71.496 ;
     RECT  84.701 18.192 84.745 71.496 ;
     RECT  83.704 14.64 84.949 14.664 ;
     RECT  84.949 14.64 85.285 15.48 ;
     RECT  84.053 86.736 85.417 87.768 ;
     RECT  85.417 86.64 85.501 87.768 ;
     RECT  85.045 1.152 85.565 1.176 ;
     RECT  85.501 86.688 85.637 87.768 ;
     RECT  85.309 4.848 85.669 4.872 ;
     RECT  85.285 14.64 85.717 16.008 ;
     RECT  85.669 4.272 85.763 4.872 ;
     RECT  85.717 3.168 85.961 3.192 ;
     RECT  84.745 18.768 86.005 71.496 ;
     RECT  85.717 14.256 86.051 16.008 ;
     RECT  86.051 15.36 86.353 16.008 ;
     RECT  83.704 89.52 86.387 89.544 ;
     RECT  85.637 86.736 86.885 87.768 ;
     RECT  86.885 86.64 86.969 87.768 ;
     RECT  86.353 15.36 87.068 16.824 ;
     RECT  87.068 15.36 87.116 17.016 ;
     RECT  86.005 18.144 87.116 71.496 ;
     RECT  87.116 15.36 87.155 71.496 ;
     RECT  87.116 3.744 87.203 3.768 ;
     RECT  86.969 86.736 87.205 87.768 ;
     RECT  86.749 88.896 87.205 88.92 ;
     RECT  87.205 86.736 87.251 88.92 ;
     RECT  87.251 88.56 87.292 88.92 ;
     RECT  87.397 90.048 87.481 90.072 ;
     RECT  86.101 0.192 87.617 0.216 ;
     RECT  87.251 86.736 87.973 87.576 ;
     RECT  87.829 3.936 88.364 3.96 ;
     RECT  88.261 1.152 88.373 1.176 ;
     RECT  87.292 88.896 88.405 88.92 ;
     RECT  88.364 3.936 88.808 4.824 ;
     RECT  87.155 15.456 88.808 71.496 ;
     RECT  83.704 78.912 88.808 78.936 ;
     RECT  87.973 86.64 88.808 87.576 ;
     RECT  88.405 88.896 88.808 89.544 ;
     RECT  88.808 2.148 88.912 89.652 ;
     RECT  88.912 2.418 89.104 89.544 ;
     RECT  89.365 0.192 89.489 0.216 ;
     RECT  89.104 4.272 89.747 4.296 ;
     RECT  89.104 14.784 89.747 16.776 ;
     RECT  89.104 86.64 90.179 89.544 ;
     RECT  89.747 15.456 90.277 16.776 ;
     RECT  90.277 15.456 90.601 17.064 ;
     RECT  89.104 18.096 90.601 71.496 ;
     RECT  90.601 15.456 90.611 71.496 ;
     RECT  90.529 5.088 90.613 5.112 ;
     RECT  90.611 17.664 90.713 71.496 ;
     RECT  90.421 1.152 90.857 1.176 ;
     RECT  90.713 18.384 91.228 71.496 ;
     RECT  91.525 0.192 91.613 0.216 ;
     RECT  90.179 86.736 91.667 89.544 ;
     RECT  90.611 15.456 91.717 16.392 ;
     RECT  91.717 14.784 91.811 16.392 ;
     RECT  91.811 14.784 91.861 15.864 ;
     RECT  91.82 17.856 91.907 17.88 ;
     RECT  92.108 3.936 92.195 3.96 ;
     RECT  91.861 14.064 92.195 15.864 ;
     RECT  91.667 86.736 92.573 88.92 ;
     RECT  92.573 86.64 92.657 88.92 ;
     RECT  92.581 0.192 92.693 0.216 ;
     RECT  92.645 90.048 92.729 90.072 ;
     RECT  92.195 14.784 93.013 15.864 ;
     RECT  92.761 17.088 93.013 17.112 ;
     RECT  92.657 86.736 93.017 88.92 ;
     RECT  92.972 5.04 93.059 5.064 ;
     RECT  91.228 19.248 93.203 71.496 ;
     RECT  93.017 86.736 93.625 88.392 ;
     RECT  93.013 3.312 93.769 3.336 ;
     RECT  93.685 0.192 93.773 0.216 ;
     RECT  93.769 3.312 94.208 4.008 ;
     RECT  93.013 14.784 94.208 17.112 ;
     RECT  94.093 18.24 94.208 18.264 ;
     RECT  93.203 19.248 94.208 19.368 ;
     RECT  93.203 20.352 94.208 71.496 ;
     RECT  93.733 76.368 94.208 76.392 ;
     RECT  89.104 78.912 94.208 78.936 ;
     RECT  93.625 86.64 94.208 88.392 ;
     RECT  93.692 89.52 94.208 89.544 ;
     RECT  94.208 2.148 94.312 89.652 ;
     RECT  94.312 2.418 94.504 89.652 ;
     RECT  94.741 90.048 94.835 90.072 ;
     RECT  94.741 0.192 94.853 0.216 ;
     RECT  94.504 4.272 94.883 4.536 ;
     RECT  94.504 17.808 95.069 18.264 ;
     RECT  94.504 75.84 95.113 75.864 ;
     RECT  94.883 4.272 95.219 4.296 ;
     RECT  94.504 19.248 95.249 71.496 ;
     RECT  95.249 19.248 95.497 19.416 ;
     RECT  95.249 20.448 95.555 71.496 ;
     RECT  94.504 15.456 95.557 16.248 ;
     RECT  95.497 18.384 95.603 19.416 ;
     RECT  94.504 86.736 95.9 88.104 ;
     RECT  95.845 89.52 95.932 89.544 ;
     RECT  95.9 86.736 95.987 88.392 ;
     RECT  95.603 19.248 96.361 19.416 ;
     RECT  95.987 86.736 96.433 88.104 ;
     RECT  96.145 4.512 96.469 4.536 ;
     RECT  96.361 19.248 96.509 19.608 ;
     RECT  95.557 15.456 96.565 16.776 ;
     RECT  96.469 3.936 96.611 4.536 ;
     RECT  96.565 15.456 96.653 16.968 ;
     RECT  96.793 90.624 96.947 90.648 ;
     RECT  96.577 18.192 97.081 18.216 ;
     RECT  96.509 19.248 97.081 19.368 ;
     RECT  95.845 0.192 97.121 0.216 ;
     RECT  97.081 18.192 97.157 19.368 ;
     RECT  96.433 86.64 97.429 88.104 ;
     RECT  97.429 86.592 97.513 88.104 ;
     RECT  96.653 15.456 97.585 16.008 ;
     RECT  97.585 14.496 97.868 16.008 ;
     RECT  97.117 4.8 97.909 4.824 ;
     RECT  97.909 3.936 97.955 4.824 ;
     RECT  97.868 14.064 97.955 16.008 ;
     RECT  97.189 17.28 97.955 17.304 ;
     RECT  97.955 14.496 98.051 16.008 ;
     RECT  97.157 18.672 98.093 19.368 ;
     RECT  97.513 86.592 98.093 88.344 ;
     RECT  97.955 3.936 98.129 3.96 ;
     RECT  98.093 86.592 98.269 88.104 ;
     RECT  98.005 1.152 98.453 1.176 ;
     RECT  98.093 18.72 98.521 19.368 ;
     RECT  95.555 20.64 98.521 71.496 ;
     RECT  98.581 80.256 98.845 80.28 ;
     RECT  97.873 90.048 99.059 90.072 ;
     RECT  98.521 18.72 99.133 71.496 ;
     RECT  98.881 83.232 99.164 83.256 ;
     RECT  94.504 78.912 99.205 78.936 ;
     RECT  98.845 80.256 99.205 80.376 ;
     RECT  99.061 14.4 99.349 14.424 ;
     RECT  98.051 15.456 99.349 15.48 ;
     RECT  99.061 1.728 99.608 1.752 ;
     RECT  99.308 5.088 99.608 5.112 ;
     RECT  99.349 14.4 99.608 15.48 ;
     RECT  99.133 18.096 99.608 71.496 ;
     RECT  99.205 78.912 99.608 80.376 ;
     RECT  99.164 83.232 99.608 83.784 ;
     RECT  98.269 86.304 99.608 88.104 ;
     RECT  99.608 1.728 99.712 89.652 ;
     RECT  99.712 1.728 99.785 89.544 ;
     RECT  99.785 2.418 99.904 89.544 ;
     RECT  99.904 89.52 100.115 89.544 ;
     RECT  99.904 20.544 100.259 71.496 ;
     RECT  99.904 86.544 100.325 88.392 ;
     RECT  99.904 3.936 100.333 3.96 ;
     RECT  99.904 84.96 100.909 85.512 ;
     RECT  100.909 85.488 100.925 85.512 ;
     RECT  100.325 86.544 100.925 88.104 ;
     RECT  99.904 17.52 100.961 17.592 ;
     RECT  99.904 18.624 100.961 19.368 ;
     RECT  100.961 17.52 101.045 19.368 ;
     RECT  101.045 19.104 101.053 19.368 ;
     RECT  101.045 17.52 101.113 17.544 ;
     RECT  101.125 89.52 101.212 89.544 ;
     RECT  101.053 19.344 101.225 19.368 ;
     RECT  100.925 85.488 101.363 88.104 ;
     RECT  100.165 1.152 101.585 1.176 ;
     RECT  100.259 20.64 101.653 71.496 ;
     RECT  99.904 14.4 101.761 14.424 ;
     RECT  99.904 15.456 101.869 15.48 ;
     RECT  101.113 17.328 101.893 17.544 ;
     RECT  101.852 3.312 101.939 3.336 ;
     RECT  101.363 86.448 102.035 88.104 ;
     RECT  101.869 15.456 102.085 15.72 ;
     RECT  101.761 13.632 102.089 14.424 ;
     RECT  102.035 86.448 102.125 87.864 ;
     RECT  102.089 13.632 102.131 14.28 ;
     RECT  102.085 15.456 102.133 15.816 ;
     RECT  102.133 15.456 102.22 15.912 ;
     RECT  102.181 89.52 102.269 89.544 ;
     RECT  101.893 17.04 102.332 17.544 ;
     RECT  102.125 86.448 102.337 87.816 ;
     RECT  102.293 0.192 102.377 0.216 ;
     RECT  102.332 17.04 102.409 17.832 ;
     RECT  102.337 86.064 102.421 87.816 ;
     RECT  101.852 4.512 102.481 4.536 ;
     RECT  102.421 86.448 102.557 87.816 ;
     RECT  102.409 17.04 102.589 18.168 ;
     RECT  101.653 19.392 102.589 71.496 ;
     RECT  102.589 17.04 102.613 71.496 ;
     RECT  102.22 15.456 102.629 15.72 ;
     RECT  102.557 86.448 102.629 87.576 ;
     RECT  102.613 16.992 102.7 71.496 ;
     RECT  102.481 4.512 102.733 4.824 ;
     RECT  102.629 15.456 102.755 15.576 ;
     RECT  102.733 3.936 102.899 4.824 ;
     RECT  102.7 17.088 102.989 71.496 ;
     RECT  103.165 90.048 103.283 90.072 ;
     RECT  102.989 17.088 103.313 17.352 ;
     RECT  102.989 19.056 103.421 71.496 ;
     RECT  103.381 0.192 103.493 0.216 ;
     RECT  103.313 17.28 103.601 17.352 ;
     RECT  102.131 14.256 103.763 14.28 ;
     RECT  102.629 86.544 103.885 87.576 ;
     RECT  104.029 3.984 104.3 4.536 ;
     RECT  104.252 90.624 104.339 90.648 ;
     RECT  103.717 12.528 104.341 12.552 ;
     RECT  103.421 19.056 104.425 19.08 ;
     RECT  104.425 18.672 104.821 19.08 ;
     RECT  103.421 20.64 104.849 71.496 ;
     RECT  104.821 18.672 104.869 19.176 ;
     RECT  103.885 86.544 104.929 88.488 ;
     RECT  104.3 3.984 105.008 4.872 ;
     RECT  104.341 12.384 105.008 12.552 ;
     RECT  102.755 15.552 105.008 15.576 ;
     RECT  103.601 17.328 105.008 17.352 ;
     RECT  104.869 18.672 105.008 19.368 ;
     RECT  104.849 20.448 105.008 71.496 ;
     RECT  99.904 75.936 105.008 75.96 ;
     RECT  99.904 78.912 105.008 79.464 ;
     RECT  104.929 86.544 105.008 88.92 ;
     RECT  105.008 2.148 105.112 89.652 ;
     RECT  105.112 2.418 105.217 89.652 ;
     RECT  105.217 2.418 105.304 90.072 ;
     RECT  105.304 86.544 105.443 88.92 ;
     RECT  104.485 0.192 105.625 0.216 ;
     RECT  105.304 14.592 106.115 15.576 ;
     RECT  105.304 17.328 106.405 17.352 ;
     RECT  105.304 4.56 106.441 4.584 ;
     RECT  106.441 4.56 106.481 4.872 ;
     RECT  106.115 14.592 106.595 14.664 ;
     RECT  105.304 18.672 106.597 19.128 ;
     RECT  105.304 20.64 106.597 71.496 ;
     RECT  105.443 86.544 106.697 88.536 ;
     RECT  106.645 0.192 106.733 0.216 ;
     RECT  106.481 4.848 106.883 4.872 ;
     RECT  106.597 18.672 106.883 71.496 ;
     RECT  106.883 18.96 106.985 71.496 ;
     RECT  106.405 16.56 107.053 17.352 ;
     RECT  106.985 18.96 107.201 19.128 ;
     RECT  106.697 86.544 107.201 87.864 ;
     RECT  107.053 15.984 107.381 17.352 ;
     RECT  107.269 3.408 107.809 3.432 ;
     RECT  107.809 3.408 107.849 3.72 ;
     RECT  106.595 14.64 108.037 14.664 ;
     RECT  107.849 3.696 108.083 3.72 ;
     RECT  107.996 5.04 108.083 5.064 ;
     RECT  108.037 14.64 108.092 14.856 ;
     RECT  107.381 15.984 108.092 16.008 ;
     RECT  106.985 20.64 108.092 71.496 ;
     RECT  108.092 14.64 108.179 16.008 ;
     RECT  108.092 20.256 108.179 71.496 ;
     RECT  107.701 1.728 108.389 1.752 ;
     RECT  105.304 85.488 108.419 85.512 ;
     RECT  105.304 90.048 108.563 90.072 ;
     RECT  107.201 86.64 109.217 87.864 ;
     RECT  109.217 86.64 109.429 87.624 ;
     RECT  105.304 78.912 109.436 79.464 ;
     RECT  108.179 20.64 109.477 71.496 ;
     RECT  109.477 20.64 109.631 72.168 ;
     RECT  109.429 12.528 109.957 12.552 ;
     RECT  109.753 82.608 110.293 82.632 ;
     RECT  109.429 86.16 110.293 87.624 ;
     RECT  108.805 1.152 110.297 1.176 ;
     RECT  109.429 3.936 110.408 3.96 ;
     RECT  109.957 11.664 110.408 12.552 ;
     RECT  106.549 13.536 110.408 13.56 ;
     RECT  108.179 14.64 110.408 14.664 ;
     RECT  108.179 15.984 110.408 16.008 ;
     RECT  107.381 17.328 110.408 17.352 ;
     RECT  107.201 18.96 110.408 18.984 ;
     RECT  109.631 20.064 110.408 72.168 ;
     RECT  105.304 75.936 110.408 75.96 ;
     RECT  109.436 78.912 110.408 79.656 ;
     RECT  110.293 81.888 110.408 82.632 ;
     RECT  110.293 86.064 110.408 87.624 ;
     RECT  109.532 89.52 110.408 89.544 ;
     RECT  110.408 2.148 110.512 89.652 ;
     RECT  110.545 91.152 110.675 91.176 ;
     RECT  110.512 2.418 110.704 89.382 ;
     RECT  110.704 3.216 110.819 4.824 ;
     RECT  110.704 20.064 111.059 72.168 ;
     RECT  110.965 0.576 111.089 0.6 ;
     RECT  110.704 15.984 111.299 16.008 ;
     RECT  110.704 11.664 111.341 13.656 ;
     RECT  110.819 4.8 111.347 4.824 ;
     RECT  111.059 20.304 111.347 72.168 ;
     RECT  110.819 3.216 111.628 3.72 ;
     RECT  111.341 11.664 111.809 12.936 ;
     RECT  111.628 3.696 111.845 3.72 ;
     RECT  110.704 75.936 112.019 75.96 ;
     RECT  111.809 11.664 112.313 12.552 ;
     RECT  112.021 1.152 112.385 1.176 ;
     RECT  110.704 86.736 112.601 88.344 ;
     RECT  112.601 86.736 112.7 87.528 ;
     RECT  112.7 86.16 112.787 87.528 ;
     RECT  111.589 90.048 112.787 90.072 ;
     RECT  112.561 4.8 112.885 4.824 ;
     RECT  112.741 83.184 112.889 83.208 ;
     RECT  112.885 3.936 113.123 4.824 ;
     RECT  111.347 20.64 113.209 72.168 ;
     RECT  113.125 0.192 113.213 0.216 ;
     RECT  113.077 10.272 113.413 10.296 ;
     RECT  113.413 10.272 113.459 10.584 ;
     RECT  113.209 20.544 113.459 72.168 ;
     RECT  110.704 81.888 113.641 82.2 ;
     RECT  113.459 10.56 113.653 10.584 ;
     RECT  112.313 12.528 113.699 12.552 ;
     RECT  113.653 10.56 113.825 10.776 ;
     RECT  113.756 89.52 113.843 89.544 ;
     RECT  113.123 3.936 113.929 3.96 ;
     RECT  113.641 81.888 113.989 82.968 ;
     RECT  112.787 86.592 113.989 87.528 ;
     RECT  113.989 81.456 114.035 82.968 ;
     RECT  113.825 10.56 114.149 10.584 ;
     RECT  113.929 3.408 114.329 3.96 ;
     RECT  113.989 86.16 114.329 87.576 ;
     RECT  114.035 81.456 114.797 82.2 ;
     RECT  110.704 78.912 115.477 78.936 ;
     RECT  114.181 0.192 115.625 0.216 ;
     RECT  114.329 3.408 115.808 3.432 ;
     RECT  115.261 4.512 115.808 4.536 ;
     RECT  110.704 14.64 115.808 14.664 ;
     RECT  110.704 17.328 115.808 17.352 ;
     RECT  110.704 18.96 115.808 18.984 ;
     RECT  113.459 20.64 115.808 72.168 ;
     RECT  115.477 78.624 115.808 78.936 ;
     RECT  114.797 81.888 115.808 82.2 ;
     RECT  110.704 84.624 115.808 84.648 ;
     RECT  114.329 87.072 115.808 87.576 ;
     RECT  114.721 90.048 115.808 90.072 ;
     RECT  115.808 2.148 115.912 90.072 ;
     RECT  115.912 2.418 116.104 90.072 ;
     RECT  116.341 0.576 116.425 0.6 ;
     RECT  116.104 3.936 116.531 4.824 ;
     RECT  116.104 10.848 116.531 11.448 ;
     RECT  116.104 77.136 116.813 78.936 ;
     RECT  116.531 3.936 116.867 4.536 ;
     RECT  116.104 90.048 117.011 90.072 ;
     RECT  116.104 81.888 117.109 82.2 ;
     RECT  116.104 87.072 117.109 87.096 ;
     RECT  116.104 88.08 117.109 88.104 ;
     RECT  117.109 87.072 117.155 88.104 ;
     RECT  116.867 3.936 117.173 3.96 ;
     RECT  117.109 81.888 117.497 82.296 ;
     RECT  117.155 87.072 117.677 87.288 ;
     RECT  116.104 18.96 117.785 18.984 ;
     RECT  117.445 0.288 118.001 0.312 ;
     RECT  117.961 90.624 118.067 90.648 ;
     RECT  116.104 20.64 118.316 72.168 ;
     RECT  118.316 20.64 118.403 72.6 ;
     RECT  117.497 81.888 118.537 82.2 ;
     RECT  116.104 83.664 118.537 84.648 ;
     RECT  116.531 11.424 118.573 11.448 ;
     RECT  116.813 77.808 118.573 78.936 ;
     RECT  118.573 11.424 118.613 11.544 ;
     RECT  117.677 87.072 118.988 87.096 ;
     RECT  118.465 88.32 118.988 88.344 ;
     RECT  118.988 87.072 119.075 88.344 ;
     RECT  118.537 81.888 119.084 84.648 ;
     RECT  118.573 77.664 119.171 78.936 ;
     RECT  119.084 81.552 119.171 84.648 ;
     RECT  119.077 90.048 119.189 90.072 ;
     RECT  118.501 1.728 119.261 1.752 ;
     RECT  116.104 14.64 119.363 14.664 ;
     RECT  119.276 19.008 119.363 19.032 ;
     RECT  118.645 3.936 119.437 3.96 ;
     RECT  119.437 3.936 119.477 4.872 ;
     RECT  119.075 87.072 119.549 87.768 ;
     RECT  119.293 8.496 119.612 8.52 ;
     RECT  119.477 4.848 119.699 4.872 ;
     RECT  119.612 7.872 119.699 8.52 ;
     RECT  119.171 81.888 119.729 84.648 ;
     RECT  119.549 87.744 119.909 87.768 ;
     RECT  120.133 89.52 120.22 89.544 ;
     RECT  118.403 20.64 120.985 72.168 ;
     RECT  119.605 1.152 121.025 1.176 ;
     RECT  120.769 3.696 121.208 3.72 ;
     RECT  119.699 8.496 121.208 8.52 ;
     RECT  120.661 10.176 121.208 10.2 ;
     RECT  118.613 11.52 121.208 11.544 ;
     RECT  116.104 17.328 121.208 17.352 ;
     RECT  120.985 20.64 121.208 72.984 ;
     RECT  119.171 77.664 121.208 77.688 ;
     RECT  119.171 78.912 121.208 78.936 ;
     RECT  119.729 81.888 121.208 83.256 ;
     RECT  119.729 84.624 121.208 84.648 ;
     RECT  119.005 86.016 121.208 86.04 ;
     RECT  120.517 88.176 121.208 88.2 ;
     RECT  121.148 89.76 121.208 89.784 ;
     RECT  121.208 2.148 121.312 89.784 ;
     RECT  121.312 2.418 121.504 89.784 ;
     RECT  121.504 20.544 121.536 72.984 ;
     RECT  121.504 3.696 121.565 4.872 ;
     RECT  121.565 3.936 121.667 4.872 ;
     RECT  121.733 0.192 121.817 0.216 ;
     RECT  121.504 87.792 121.853 88.2 ;
     RECT  121.504 9.744 121.859 11.544 ;
     RECT  121.536 26.688 121.997 65.88 ;
     RECT  121.504 8.496 122.003 8.52 ;
     RECT  121.859 9.744 122.044 10.2 ;
     RECT  121.859 11.424 122.099 11.544 ;
     RECT  121.504 86.016 122.243 86.04 ;
     RECT  122.044 10.176 122.291 10.2 ;
     RECT  122.173 90.048 122.291 90.072 ;
     RECT  121.504 81.888 122.321 82.2 ;
     RECT  121.504 83.232 122.483 83.256 ;
     RECT  121.997 26.688 122.609 58.2 ;
     RECT  121.536 20.544 122.645 25.608 ;
     RECT  121.536 67.056 122.653 72.984 ;
     RECT  122.645 20.64 122.675 25.608 ;
     RECT  122.609 26.688 122.681 29.688 ;
     RECT  122.533 3.12 122.717 3.144 ;
     RECT  122.609 30.672 122.753 58.2 ;
     RECT  121.504 84.624 122.819 84.648 ;
     RECT  122.675 22.032 122.933 25.608 ;
     RECT  122.321 81.888 122.965 82.104 ;
     RECT  122.681 26.688 123.005 29.112 ;
     RECT  122.965 81.504 123.049 82.104 ;
     RECT  123.049 81.504 123.107 81.528 ;
     RECT  123.005 26.688 123.155 27 ;
     RECT  122.675 20.64 123.251 20.664 ;
     RECT  122.653 72.96 123.347 72.984 ;
     RECT  123.26 84.336 123.347 84.36 ;
     RECT  123.26 89.52 123.347 89.544 ;
     RECT  123.005 28.176 123.685 29.112 ;
     RECT  121.997 59.232 123.689 65.784 ;
     RECT  122.753 43.392 123.721 58.2 ;
     RECT  123.689 63.744 123.725 65.784 ;
     RECT  123.644 4.704 123.731 4.728 ;
     RECT  123.685 28.176 123.779 29.688 ;
     RECT  123.721 43.344 123.827 58.2 ;
     RECT  122.653 67.056 123.865 71.496 ;
     RECT  123.827 43.44 123.869 58.2 ;
     RECT  123.689 59.232 123.869 62.04 ;
     RECT  123.725 63.744 123.869 65.544 ;
     RECT  122.933 22.032 123.875 25.512 ;
     RECT  121.504 77.664 123.877 77.688 ;
     RECT  123.877 77.664 123.937 77.784 ;
     RECT  122.753 30.672 123.941 42.168 ;
     RECT  123.865 66.72 123.949 71.496 ;
     RECT  123.869 43.44 123.977 49.656 ;
     RECT  123.869 63.744 123.977 63.768 ;
     RECT  123.875 22.08 124.019 25.512 ;
     RECT  123.977 43.776 124.019 49.656 ;
     RECT  123.155 26.784 124.028 27 ;
     RECT  123.779 28.176 124.028 29.112 ;
     RECT  123.941 30.672 124.028 42.072 ;
     RECT  123.869 60.384 124.049 62.04 ;
     RECT  124.028 30.288 124.085 42.072 ;
     RECT  124.019 44.016 124.085 49.656 ;
     RECT  123.869 50.688 124.085 58.2 ;
     RECT  123.869 64.896 124.085 65.544 ;
     RECT  124.028 26.784 124.115 29.112 ;
     RECT  124.085 30.288 124.115 30.696 ;
     RECT  124.085 56.448 124.157 58.2 ;
     RECT  124.019 22.176 124.163 25.512 ;
     RECT  124.085 31.968 124.193 42.072 ;
     RECT  124.085 44.016 124.193 48.312 ;
     RECT  124.085 50.688 124.193 55.272 ;
     RECT  124.157 56.736 124.193 57.576 ;
     RECT  124.049 60.864 124.193 61.944 ;
     RECT  122.099 11.424 124.211 11.448 ;
     RECT  124.124 20.736 124.211 20.76 ;
     RECT  124.163 22.752 124.213 25.512 ;
     RECT  124.115 26.784 124.213 27.432 ;
     RECT  123.869 59.232 124.229 59.352 ;
     RECT  124.115 28.896 124.265 29.112 ;
     RECT  124.193 40.8 124.265 41.496 ;
     RECT  124.085 49.632 124.265 49.656 ;
     RECT  124.193 50.688 124.265 53.688 ;
     RECT  124.193 60.864 124.265 60.888 ;
     RECT  124.193 61.92 124.265 61.944 ;
     RECT  124.193 31.968 124.301 37.992 ;
     RECT  124.193 39.216 124.301 39.768 ;
     RECT  124.193 44.016 124.307 46.2 ;
     RECT  124.265 28.896 124.337 29.016 ;
     RECT  123.937 77.52 124.365 77.784 ;
     RECT  124.337 28.944 124.373 29.016 ;
     RECT  124.225 90.624 124.403 90.648 ;
     RECT  124.193 47.28 124.417 47.304 ;
     RECT  121.853 87.792 124.445 87.816 ;
     RECT  122.821 1.152 124.481 1.176 ;
     RECT  124.085 65.52 124.481 65.544 ;
     RECT  124.365 77.52 124.547 77.544 ;
     RECT  124.213 4.512 124.589 4.536 ;
     RECT  123.949 67.056 124.595 71.496 ;
     RECT  124.193 57.024 124.661 57.576 ;
     RECT  124.265 52.464 124.691 52.872 ;
     RECT  124.661 57.024 124.691 57.048 ;
     RECT  124.193 54.768 124.697 55.272 ;
     RECT  124.307 44.496 124.777 46.2 ;
     RECT  124.697 54.864 124.835 55.272 ;
     RECT  124.796 63.696 124.837 63.72 ;
     RECT  124.373 28.944 124.883 28.968 ;
     RECT  124.837 63.072 124.883 63.72 ;
     RECT  124.265 50.688 124.885 51.336 ;
     RECT  124.777 44.496 124.931 45.624 ;
     RECT  124.885 50.592 124.985 51.336 ;
     RECT  124.883 63.072 125.045 63.288 ;
     RECT  125.045 62.112 125.129 63.288 ;
     RECT  124.213 22.752 125.173 27.432 ;
     RECT  124.691 52.464 125.219 52.488 ;
     RECT  125.173 22.896 125.237 27.432 ;
     RECT  124.985 51.312 125.267 51.336 ;
     RECT  124.981 0.576 125.345 0.6 ;
     RECT  125.237 22.896 125.345 27.24 ;
     RECT  125.305 90.048 125.411 90.072 ;
     RECT  124.265 40.992 125.449 41.496 ;
     RECT  124.837 75.552 125.449 75.576 ;
     RECT  124.115 30.576 125.489 30.696 ;
     RECT  124.549 58.704 125.593 58.728 ;
     RECT  124.595 67.68 125.597 71.496 ;
     RECT  125.305 47.328 125.603 47.352 ;
     RECT  125.449 40.992 125.773 42.072 ;
     RECT  125.737 43.056 125.773 43.08 ;
     RECT  124.981 87.552 125.797 87.576 ;
     RECT  124.301 32.064 125.953 37.992 ;
     RECT  124.301 39.216 125.953 39.576 ;
     RECT  125.953 32.064 125.996 39.576 ;
     RECT  125.485 28.416 126.085 28.44 ;
     RECT  124.835 54.864 126.133 55.176 ;
     RECT  126.053 0.192 126.137 0.216 ;
     RECT  126.085 28.416 126.169 28.824 ;
     RECT  125.489 30.576 126.169 30.648 ;
     RECT  125.345 23.136 126.241 27.24 ;
     RECT  126.169 28.416 126.241 30.648 ;
     RECT  125.996 31.872 126.421 39.576 ;
     RECT  126.421 31.632 126.428 39.576 ;
     RECT  125.773 40.992 126.428 43.08 ;
     RECT  126.241 23.136 126.457 30.648 ;
     RECT  126.428 31.632 126.457 43.08 ;
     RECT  125.597 67.68 126.529 68.424 ;
     RECT  125.9 4.512 126.608 4.536 ;
     RECT  121.504 16.8 126.608 17.352 ;
     RECT  126.457 23.136 126.608 43.08 ;
     RECT  124.931 44.592 126.608 45.624 ;
     RECT  125.701 53.472 126.608 53.496 ;
     RECT  126.133 54.72 126.608 55.176 ;
     RECT  125.593 58.704 126.608 58.872 ;
     RECT  125.981 61.584 126.608 61.608 ;
     RECT  125.129 62.736 126.608 63.288 ;
     RECT  126.529 67.632 126.608 68.424 ;
     RECT  125.597 69.6 126.608 71.496 ;
     RECT  125.449 75.408 126.608 75.576 ;
     RECT  121.504 78.912 126.608 78.936 ;
     RECT  125.797 87.552 126.608 87.912 ;
     RECT  126.421 89.52 126.608 89.544 ;
     RECT  126.608 2.148 126.712 89.652 ;
     RECT  126.712 2.418 126.904 89.652 ;
     RECT  126.904 24.912 126.929 25.56 ;
     RECT  126.904 27.36 127.043 31.8 ;
     RECT  126.904 43.92 127.043 45.24 ;
     RECT  126.904 47.04 127.043 47.064 ;
     RECT  126.904 40.608 127.073 42.6 ;
     RECT  127.043 30.432 127.091 31.8 ;
     RECT  127.073 40.608 127.091 42.456 ;
     RECT  127.043 44.064 127.091 45.24 ;
     RECT  126.904 3.36 127.109 4.536 ;
     RECT  126.904 33.36 127.109 39.576 ;
     RECT  126.929 24.912 127.117 25.416 ;
     RECT  127.109 33.36 127.217 34.2 ;
     RECT  126.904 54.72 127.217 54.744 ;
     RECT  127.141 0.192 127.225 0.216 ;
     RECT  126.904 81.504 127.235 81.528 ;
     RECT  127.217 33.36 127.523 33.432 ;
     RECT  127.465 90.048 127.549 90.072 ;
     RECT  127.117 24.912 127.764 24.936 ;
     RECT  127.091 30.672 127.821 31.8 ;
     RECT  127.043 27.36 127.852 28.824 ;
     RECT  127.109 3.36 127.859 3.384 ;
     RECT  127.109 4.512 127.859 4.536 ;
     RECT  127.852 27.36 127.865 27.864 ;
     RECT  127.091 44.448 127.937 45.24 ;
     RECT  127.821 31.776 128.245 31.8 ;
     RECT  127.821 30.672 128.291 30.696 ;
     RECT  127.865 27.648 128.297 27.864 ;
     RECT  128.185 87.744 128.333 87.768 ;
     RECT  127.523 33.36 128.401 33.384 ;
     RECT  128.401 33.024 128.405 33.384 ;
     RECT  128.365 4.272 128.483 4.296 ;
     RECT  128.245 31.776 128.485 31.896 ;
     RECT  128.405 33.024 128.485 33.096 ;
     RECT  127.109 35.232 128.533 39.576 ;
     RECT  127.091 40.608 128.533 42.216 ;
     RECT  128.533 35.232 128.579 42.216 ;
     RECT  128.473 89.52 128.579 89.544 ;
     RECT  128.245 0.192 128.585 0.216 ;
     RECT  128.579 35.232 128.62 41.64 ;
     RECT  126.904 16.8 128.627 17.352 ;
     RECT  128.365 29.616 128.723 29.64 ;
     RECT  128.62 35.232 128.725 40.008 ;
     RECT  128.437 26.256 128.757 26.28 ;
     RECT  126.904 75.408 128.771 75.432 ;
     RECT  128.684 81.552 128.771 81.576 ;
     RECT  128.62 40.992 128.801 41.64 ;
     RECT  128.485 31.776 128.905 33.096 ;
     RECT  128.725 87.792 128.909 87.864 ;
     RECT  128.869 4.512 128.953 4.536 ;
     RECT  128.581 42.96 129.049 43.08 ;
     RECT  128.869 26.496 129.081 26.52 ;
     RECT  129.049 42.96 129.133 43.368 ;
     RECT  128.905 30.816 129.305 33.096 ;
     RECT  126.904 23.28 129.341 23.304 ;
     RECT  128.801 41.136 129.347 41.64 ;
     RECT  129.305 30.816 129.356 31.896 ;
     RECT  128.725 34.8 129.356 40.008 ;
     RECT  129.013 29.184 129.397 29.208 ;
     RECT  128.909 87.792 129.413 87.816 ;
     RECT  128.297 27.84 129.517 27.864 ;
     RECT  126.904 67.296 129.521 68.424 ;
     RECT  129.133 42.96 129.557 42.984 ;
     RECT  129.521 67.296 129.557 67.848 ;
     RECT  129.305 32.976 129.733 33.096 ;
     RECT  129.356 34.32 129.733 40.008 ;
     RECT  129.733 32.976 129.769 40.008 ;
     RECT  129.347 41.136 129.769 41.4 ;
     RECT  129.769 32.976 129.82 41.4 ;
     RECT  129.517 27.6 129.829 27.864 ;
     RECT  129.82 34.8 129.845 41.4 ;
     RECT  129.589 3.744 129.875 3.768 ;
     RECT  129.788 5.088 129.875 5.112 ;
     RECT  129.397 28.896 129.875 29.208 ;
     RECT  129.829 27.552 129.916 27.864 ;
     RECT  126.904 69.6 130.025 71.496 ;
     RECT  129.875 29.184 130.165 29.208 ;
     RECT  129.356 30.528 130.165 31.896 ;
     RECT  129.845 35.52 130.241 41.4 ;
     RECT  130.241 35.52 130.313 39.672 ;
     RECT  130.165 43.92 130.349 43.944 ;
     RECT  130.381 3.936 130.465 3.96 ;
     RECT  130.165 29.184 130.492 31.896 ;
     RECT  130.201 57.456 130.541 57.48 ;
     RECT  130.492 29.52 130.547 31.896 ;
     RECT  130.547 30.912 130.549 31.896 ;
     RECT  129.82 32.976 130.549 33.624 ;
     RECT  129.301 1.152 130.565 1.176 ;
     RECT  130.313 35.52 130.595 39.576 ;
     RECT  130.541 57.456 130.633 57.528 ;
     RECT  130.633 57.36 130.636 57.528 ;
     RECT  130.241 41.136 130.669 41.4 ;
     RECT  130.633 43.008 130.669 43.368 ;
     RECT  130.636 57.36 130.673 57.48 ;
     RECT  130.025 69.6 130.673 71.448 ;
     RECT  129.589 89.52 130.691 89.544 ;
     RECT  130.547 29.52 130.745 29.544 ;
     RECT  130.669 41.136 130.817 43.368 ;
     RECT  129.916 27.6 130.885 27.864 ;
     RECT  128.627 16.8 130.931 16.824 ;
     RECT  130.844 23.328 130.931 23.352 ;
     RECT  131.065 35.328 131.077 35.352 ;
     RECT  130.549 30.912 131.461 33.624 ;
     RECT  131.077 34.704 131.461 35.352 ;
     RECT  130.817 41.136 131.461 42.36 ;
     RECT  127.937 45.216 131.461 45.24 ;
     RECT  130.885 27.6 131.497 28.536 ;
     RECT  130.595 36.528 131.569 39.576 ;
     RECT  131.461 0.576 131.573 0.6 ;
     RECT  130.817 43.344 131.701 43.368 ;
     RECT  131.461 44.448 131.701 45.24 ;
     RECT  131.677 90.048 131.761 90.072 ;
     RECT  131.461 30.912 131.845 35.352 ;
     RECT  131.569 36.528 131.845 39.624 ;
     RECT  130.597 4.512 131.893 4.536 ;
     RECT  130.549 76.944 131.893 76.968 ;
     RECT  131.353 88.368 131.893 88.392 ;
     RECT  131.893 3.84 132.008 4.536 ;
     RECT  131.497 26.784 132.008 28.536 ;
     RECT  131.845 30.912 132.008 39.624 ;
     RECT  131.461 40.848 132.008 42.36 ;
     RECT  131.701 43.344 132.008 45.24 ;
     RECT  130.673 57.36 132.008 57.384 ;
     RECT  129.557 67.296 132.008 67.32 ;
     RECT  130.673 69.84 132.008 71.448 ;
     RECT  131.893 76.944 132.008 77.16 ;
     RECT  126.904 78.912 132.008 78.936 ;
     RECT  131.893 88.368 132.008 88.488 ;
     RECT  132.008 2.148 132.112 89.652 ;
     RECT  132.112 2.418 132.304 89.544 ;
     RECT  132.304 88.368 132.401 89.544 ;
     RECT  132.304 31.056 132.419 31.8 ;
     RECT  132.304 41.136 132.437 42.264 ;
     RECT  132.437 41.136 132.473 41.976 ;
     RECT  132.304 33.792 132.509 37.992 ;
     RECT  132.509 34.8 132.515 37.992 ;
     RECT  132.304 57.36 132.515 57.384 ;
     RECT  132.401 88.608 132.803 89.544 ;
     RECT  132.304 45.12 132.833 45.624 ;
     RECT  132.515 34.896 132.869 37.992 ;
     RECT  132.304 39.216 132.905 39.624 ;
     RECT  132.304 27.6 133.043 28.632 ;
     RECT  133.043 28.272 133.084 28.632 ;
     RECT  132.869 35.328 133.091 37.992 ;
     RECT  132.304 4.512 133.139 4.68 ;
     RECT  132.509 33.792 133.139 33.816 ;
     RECT  132.833 45.6 133.331 45.624 ;
     RECT  133.091 35.664 133.369 37.992 ;
     RECT  132.905 39.216 133.369 39.576 ;
     RECT  133.285 43.296 133.372 43.32 ;
     RECT  132.304 30.048 133.436 30.072 ;
     RECT  132.419 31.056 133.436 31.608 ;
     RECT  133.436 30.048 133.477 31.608 ;
     RECT  133.477 30.048 133.523 31.656 ;
     RECT  133.369 35.664 133.553 39.576 ;
     RECT  132.473 41.136 133.621 41.64 ;
     RECT  133.553 35.664 133.725 38.424 ;
     RECT  133.523 30.048 133.765 30.072 ;
     RECT  133.724 4.8 133.811 4.824 ;
     RECT  133.765 3.744 133.852 3.768 ;
     RECT  133.621 40.8 133.869 41.64 ;
     RECT  132.565 1.152 133.985 1.176 ;
     RECT  133.725 35.664 134.057 37.992 ;
     RECT  133.869 41.136 134.197 41.64 ;
     RECT  133.813 45.024 134.345 45.048 ;
     RECT  133.765 30 134.409 30.072 ;
     RECT  134.057 35.664 134.525 35.688 ;
     RECT  134.341 34.608 134.557 34.632 ;
     RECT  132.304 70.32 134.561 71.448 ;
     RECT  134.557 34.608 134.633 35.592 ;
     RECT  134.197 41.136 134.773 42.072 ;
     RECT  133.553 39.552 134.78 39.576 ;
     RECT  133.523 31.584 134.821 31.656 ;
     RECT  134.773 41.136 134.821 42.168 ;
     RECT  134.633 34.848 134.849 35.592 ;
     RECT  134.849 35.568 134.867 35.592 ;
     RECT  133.729 90.048 134.915 90.072 ;
     RECT  134.821 41.136 135.133 42.456 ;
     RECT  134.821 31.584 135.169 32.472 ;
     RECT  133.084 28.272 135.281 28.44 ;
     RECT  134.561 70.608 135.281 71.448 ;
     RECT  134.809 3.936 135.308 3.96 ;
     RECT  135.308 3.936 135.395 4.872 ;
     RECT  135.133 41.136 135.443 43.32 ;
     RECT  135.397 44.448 135.497 44.472 ;
     RECT  134.057 37.104 135.529 37.992 ;
     RECT  134.78 39.216 135.529 39.576 ;
     RECT  132.803 88.608 135.529 88.92 ;
     RECT  135.529 37.104 135.677 39.576 ;
     RECT  135.169 31.584 135.683 32.52 ;
     RECT  135.683 31.584 135.713 31.8 ;
     RECT  135.281 70.608 135.713 71.4 ;
     RECT  135.529 87.792 135.884 88.92 ;
     RECT  135.677 37.344 135.889 39.576 ;
     RECT  135.443 41.136 135.889 42.792 ;
     RECT  134.409 30.048 135.965 30.072 ;
     RECT  135.884 87.792 135.971 89.544 ;
     RECT  135.889 37.344 136.001 42.792 ;
     RECT  136.001 37.344 136.037 42.168 ;
     RECT  135.971 87.792 136.109 88.92 ;
     RECT  136.037 37.344 136.115 42.072 ;
     RECT  136.115 37.344 136.211 41.64 ;
     RECT  135.395 3.936 136.213 4.296 ;
     RECT  136.211 37.344 136.217 39.624 ;
     RECT  136.217 39.552 136.253 39.624 ;
     RECT  136.213 3.312 136.307 4.296 ;
     RECT  135.565 35.664 136.307 35.688 ;
     RECT  136.249 30.192 136.333 30.216 ;
     RECT  136.069 46.224 136.501 46.248 ;
     RECT  136.217 37.344 136.741 38.04 ;
     RECT  135.713 31.632 136.837 31.8 ;
     RECT  136.969 90.048 137.053 90.072 ;
     RECT  136.307 3.936 137.18 4.296 ;
     RECT  136.109 88.608 137.329 88.92 ;
     RECT  137.18 3.936 137.408 4.536 ;
     RECT  135.281 28.416 137.408 28.44 ;
     RECT  136.837 31.632 137.408 32.376 ;
     RECT  136.741 36.144 137.408 36.168 ;
     RECT  136.741 37.2 137.408 38.04 ;
     RECT  136.253 39.552 137.408 39.576 ;
     RECT  136.211 41.136 137.408 41.64 ;
     RECT  136.46 43.296 137.408 43.32 ;
     RECT  136.501 45.264 137.408 46.248 ;
     RECT  135.713 70.848 137.408 71.4 ;
     RECT  132.304 78.912 137.408 78.936 ;
     RECT  137.329 88.176 137.408 88.92 ;
     RECT  137.408 2.148 137.512 89.652 ;
     RECT  137.512 2.418 137.704 89.544 ;
     RECT  137.704 70.848 137.801 71.4 ;
     RECT  137.704 36.528 137.981 37.992 ;
     RECT  137.704 46.224 138.017 46.248 ;
     RECT  137.704 88.176 138.083 89.544 ;
     RECT  137.704 31.776 138.089 31.944 ;
     RECT  137.704 39.072 138.089 40.632 ;
     RECT  138.083 88.176 138.197 88.92 ;
     RECT  137.981 36.528 138.227 37.896 ;
     RECT  134.725 0.192 138.269 0.216 ;
     RECT  137.704 4.512 138.419 4.536 ;
     RECT  137.704 30 138.419 30.36 ;
     RECT  138.227 37.344 138.449 37.896 ;
     RECT  138.197 88.32 138.737 88.92 ;
     RECT  138.449 37.344 138.809 37.608 ;
     RECT  138.089 39.072 138.913 39.816 ;
     RECT  138.809 37.344 138.917 37.368 ;
     RECT  138.913 38.928 138.953 39.816 ;
     RECT  138.737 88.848 139.093 88.92 ;
     RECT  138.953 38.928 139.097 39.288 ;
     RECT  138.089 31.92 139.133 31.944 ;
     RECT  138.697 3.408 139.165 3.432 ;
     RECT  139.165 3.408 139.205 3.96 ;
     RECT  139.097 39.12 139.205 39.288 ;
     RECT  137.801 70.848 139.277 70.872 ;
     RECT  139.205 3.936 139.283 3.96 ;
     RECT  138.877 41.808 139.283 41.832 ;
     RECT  139.201 45.024 139.285 45.048 ;
     RECT  139.309 35.328 139.393 35.352 ;
     RECT  139.205 39.264 139.449 39.288 ;
     RECT  138.419 30.24 139.565 30.36 ;
     RECT  139.381 37.2 139.601 37.224 ;
     RECT  139.561 36 139.781 36.024 ;
     RECT  137.704 28.416 139.817 28.44 ;
     RECT  139.093 88.848 140.195 89.544 ;
     RECT  139.565 30.336 140.243 30.36 ;
     RECT  140.197 27.312 140.245 27.336 ;
     RECT  140.197 28.32 140.284 28.344 ;
     RECT  140.204 4.272 140.291 4.296 ;
     RECT  139.045 1.152 140.573 1.176 ;
     RECT  140.245 26.784 140.609 27.336 ;
     RECT  139.669 40.56 140.627 40.584 ;
     RECT  140.581 39.456 140.681 39.48 ;
     RECT  139.741 87.696 140.861 87.72 ;
     RECT  140.195 88.848 140.933 88.872 ;
     RECT  137.704 78.912 141.005 78.936 ;
     RECT  140.713 38.976 141.113 39 ;
     RECT  141.205 89.52 141.292 89.544 ;
     RECT  141.205 0.192 141.293 0.216 ;
     RECT  141.26 38.112 141.347 38.136 ;
     RECT  141.289 3.696 141.356 3.72 ;
     RECT  140.609 27.312 141.397 27.336 ;
     RECT  141.397 27.312 141.437 27.768 ;
     RECT  141.356 3.696 141.443 4.536 ;
     RECT  141.301 37.008 141.539 37.032 ;
     RECT  141.437 27.744 141.725 27.768 ;
     RECT  142.261 0.192 142.345 0.216 ;
     RECT  142.261 90.576 142.345 90.6 ;
     RECT  140.749 40.416 142.808 40.44 ;
     RECT  141.289 88.368 142.808 88.392 ;
     RECT  142.808 2.148 142.912 89.652 ;
     RECT  142.912 2.418 143.104 89.382 ;
    LAYER M5 ;
     RECT  2.4 2.137 2.52 2.151 ;
     RECT  7.8 2.137 7.92 2.151 ;
     RECT  13.2 2.137 13.32 2.151 ;
     RECT  18.6 2.137 18.72 2.151 ;
     RECT  24 2.137 24.12 2.151 ;
     RECT  29.4 2.137 29.52 2.151 ;
     RECT  34.8 2.137 34.92 2.151 ;
     RECT  40.2 2.137 40.32 2.151 ;
     RECT  45.6 2.137 45.72 2.151 ;
     RECT  51 2.137 51.12 2.151 ;
     RECT  56.4 2.137 56.52 2.151 ;
     RECT  61.8 2.137 61.92 2.151 ;
     RECT  67.2 2.137 67.32 2.151 ;
     RECT  72.6 2.137 72.72 2.151 ;
     RECT  78 2.137 78.12 2.151 ;
     RECT  83.4 2.137 83.52 2.151 ;
     RECT  88.8 2.137 88.92 2.151 ;
     RECT  94.2 2.137 94.32 2.151 ;
     RECT  99.6 2.137 99.72 2.151 ;
     RECT  105 2.137 105.12 2.151 ;
     RECT  110.4 2.137 110.52 2.151 ;
     RECT  115.8 2.137 115.92 2.151 ;
     RECT  121.2 2.137 121.32 2.151 ;
     RECT  126.6 2.137 126.72 2.151 ;
     RECT  132 2.137 132.12 2.151 ;
     RECT  137.4 2.137 137.52 2.151 ;
     RECT  142.8 2.137 142.92 2.151 ;
     RECT  78 2.151 78.312 3.157 ;
     RECT  110.4 2.151 110.712 3.205 ;
     RECT  7.8 2.151 8.112 3.301 ;
     RECT  21.888 3.301 21.912 3.349 ;
     RECT  24 2.151 24.312 3.349 ;
     RECT  126.6 2.151 126.912 3.349 ;
     RECT  34.8 2.151 35.112 3.397 ;
     RECT  56.4 2.151 56.712 3.541 ;
     RECT  42.432 3.397 42.456 3.589 ;
     RECT  24 3.349 24.408 3.637 ;
     RECT  13.2 2.151 13.512 3.685 ;
     RECT  18.6 2.151 18.912 3.685 ;
     RECT  83.4 2.151 83.712 3.685 ;
     RECT  42.432 3.589 42.552 3.731 ;
     RECT  110.4 3.205 111.576 3.731 ;
     RECT  18.6 3.685 19.704 3.733 ;
     RECT  71.232 3.157 71.256 3.733 ;
     RECT  72.6 2.151 72.912 3.733 ;
     RECT  17.952 3.733 19.704 3.781 ;
     RECT  132 2.151 132.312 3.829 ;
     RECT  42.432 3.731 42.456 3.877 ;
     RECT  56.304 3.541 56.712 3.877 ;
     RECT  7.8 3.301 9.048 3.925 ;
     RECT  17.952 3.781 19.944 3.925 ;
     RECT  29.4 2.151 29.712 3.925 ;
     RECT  34.56 3.397 35.112 3.925 ;
     RECT  88.8 2.151 89.112 3.925 ;
     RECT  93.024 3.301 93.048 3.925 ;
     RECT  99.6 2.151 99.912 3.925 ;
     RECT  101.904 3.301 101.928 3.925 ;
     RECT  115.8 2.151 116.112 3.925 ;
     RECT  121.2 2.151 121.512 3.925 ;
     RECT  129.84 3.733 129.864 3.925 ;
     RECT  136.272 3.301 136.296 3.925 ;
     RECT  71.232 3.733 72.912 4.019 ;
     RECT  6.24 3.397 6.264 4.117 ;
     RECT  55.92 3.877 56.712 4.117 ;
     RECT  6.24 4.117 6.36 4.163 ;
     RECT  15.6 3.925 16.152 4.261 ;
     RECT  40.2 2.151 40.512 4.261 ;
     RECT  45.6 2.151 45.912 4.261 ;
     RECT  77.232 3.157 78.312 4.261 ;
     RECT  82.32 3.301 82.344 4.261 ;
     RECT  83.4 3.685 84.408 4.261 ;
     RECT  88.416 3.925 89.112 4.261 ;
     RECT  94.2 2.151 94.512 4.261 ;
     RECT  126.6 3.349 127.848 4.261 ;
     RECT  58.656 3.397 58.68 4.355 ;
     RECT  21.024 3.349 21.912 4.453 ;
     RECT  12.24 3.685 13.512 4.501 ;
     RECT  20.976 4.453 21.912 4.501 ;
     RECT  23.136 3.637 24.408 4.501 ;
     RECT  67.2 2.151 67.512 4.501 ;
     RECT  126.6 4.261 128.472 4.501 ;
     RECT  129.84 3.925 130.44 4.501 ;
     RECT  131.904 3.829 132.312 4.501 ;
     RECT  133.776 3.733 133.8 4.501 ;
     RECT  135.36 3.925 136.296 4.501 ;
     RECT  137.4 2.151 137.712 4.501 ;
     RECT  139.248 3.925 139.272 4.501 ;
     RECT  115.8 3.925 116.856 4.547 ;
     RECT  54.336 3.877 54.36 4.595 ;
     RECT  55.872 4.117 56.712 4.643 ;
     RECT  60.768 3.877 60.792 4.643 ;
     RECT  124.224 4.501 124.248 4.693 ;
     RECT  105 2.151 105.312 4.837 ;
     RECT  67.2 4.501 68.088 4.933 ;
     RECT  76.08 3.925 76.104 5.077 ;
     RECT  77.232 4.261 78.936 5.077 ;
     RECT  88.416 4.261 89.736 5.077 ;
     RECT  99.6 3.925 100.296 5.077 ;
     RECT  17.856 3.925 19.944 5.509 ;
     RECT  20.976 4.501 24.408 5.509 ;
     RECT  61.8 2.151 62.112 5.701 ;
     RECT  61.008 5.701 62.112 8.003 ;
     RECT  121.2 3.925 121.656 8.485 ;
     RECT  52.752 3.733 52.776 8.579 ;
     RECT  55.92 4.643 56.712 9.059 ;
     RECT  61.536 8.003 62.112 9.827 ;
     RECT  121.2 8.485 121.992 10.165 ;
     RECT  113.088 3.925 113.112 10.261 ;
     RECT  113.088 10.261 113.448 10.307 ;
     RECT  113.424 10.307 113.448 10.741 ;
     RECT  115.8 4.547 116.52 10.883 ;
     RECT  45.6 4.261 46.008 11.125 ;
     RECT  54.864 7.957 54.888 11.317 ;
     RECT  54.72 11.317 54.888 11.363 ;
     RECT  76.08 5.077 78.936 11.459 ;
     RECT  17.856 5.509 24.408 11.653 ;
     RECT  110.4 3.731 111.336 11.653 ;
     RECT  44.112 3.925 44.136 12.373 ;
     RECT  71.952 4.019 72.912 12.373 ;
     RECT  74.208 3.925 74.232 12.373 ;
     RECT  43.584 12.373 44.136 12.419 ;
     RECT  71.952 12.373 74.232 12.419 ;
     RECT  104.352 4.837 105.312 12.419 ;
     RECT  76.08 11.459 76.104 12.469 ;
     RECT  39.792 4.261 40.512 12.517 ;
     RECT  101.904 3.925 102.888 12.517 ;
     RECT  66.384 4.933 68.088 12.563 ;
     RECT  109.968 11.653 111.336 12.563 ;
     RECT  113.424 10.741 113.688 12.563 ;
     RECT  65.184 4.501 65.208 12.949 ;
     RECT  65.184 12.949 65.448 12.995 ;
     RECT  67.2 12.563 68.088 12.995 ;
     RECT  80.88 4.837 80.904 12.997 ;
     RECT  80.64 12.997 80.904 13.043 ;
     RECT  71.952 12.419 73.896 13.045 ;
     RECT  31.008 3.925 31.512 13.285 ;
     RECT  32.976 4.261 33 13.285 ;
     RECT  75.84 12.469 76.104 13.525 ;
     RECT  106.848 4.837 106.872 13.525 ;
     RECT  31.008 13.285 33 13.667 ;
     RECT  75.744 13.525 76.104 13.667 ;
     RECT  14.976 4.261 16.152 13.909 ;
     RECT  17.376 11.653 24.408 13.909 ;
     RECT  92.16 3.925 93.048 14.053 ;
     RECT  77.232 11.459 78.936 14.099 ;
     RECT  91.872 14.053 93.048 14.099 ;
     RECT  77.472 14.099 78.936 14.101 ;
     RECT  80.64 13.043 80.664 14.101 ;
     RECT  85.728 3.157 85.752 14.245 ;
     RECT  101.904 12.517 103.752 14.291 ;
     RECT  41.616 3.877 42.456 14.293 ;
     RECT  43.584 12.419 43.944 14.293 ;
     RECT  41.616 14.293 43.944 14.339 ;
     RECT  75.84 13.667 76.104 14.339 ;
     RECT  28.656 3.925 29.712 14.387 ;
     RECT  97.92 3.925 97.944 14.485 ;
     RECT  99.36 5.077 100.296 14.531 ;
     RECT  104.832 12.419 105.312 14.581 ;
     RECT  106.56 13.525 106.872 14.581 ;
     RECT  82.32 4.261 84.408 14.629 ;
     RECT  85.728 14.245 86.04 14.629 ;
     RECT  119.664 4.837 119.688 14.629 ;
     RECT  54.72 11.363 54.744 14.675 ;
     RECT  42.96 14.339 43.944 14.723 ;
     RECT  28.752 14.387 29.712 14.725 ;
     RECT  31.008 13.667 32.904 14.725 ;
     RECT  34.56 3.925 36.024 14.725 ;
     RECT  14.976 13.909 24.408 14.773 ;
     RECT  38.448 4.501 38.472 14.773 ;
     RECT  93.024 14.099 93.048 14.773 ;
     RECT  94.2 4.261 95.208 14.773 ;
     RECT  49.536 3.301 49.56 14.821 ;
     RECT  69.456 3.349 69.48 14.821 ;
     RECT  108.048 3.685 108.072 14.821 ;
     RECT  49.344 14.821 49.56 14.867 ;
     RECT  69.456 14.821 69.768 14.867 ;
     RECT  71.376 13.045 73.896 14.867 ;
     RECT  108.048 14.821 108.168 14.867 ;
     RECT  47.376 3.925 47.4 15.349 ;
     RECT  87.168 3.733 87.192 15.349 ;
     RECT  77.472 14.101 80.664 15.443 ;
     RECT  104.832 14.581 106.872 15.587 ;
     RECT  45.6 11.125 46.056 15.683 ;
     RECT  47.376 15.349 47.928 15.683 ;
     RECT  91.872 14.099 91.896 15.829 ;
     RECT  10.944 3.301 10.968 16.019 ;
     RECT  28.752 14.725 36.024 16.019 ;
     RECT  38.448 14.773 38.664 16.019 ;
     RECT  39.696 12.517 40.512 16.019 ;
     RECT  82.32 14.629 86.04 16.019 ;
     RECT  97.92 14.485 98.04 16.019 ;
     RECT  6.336 4.163 6.36 16.165 ;
     RECT  5.76 16.165 6.36 16.211 ;
     RECT  93.024 14.773 95.208 16.213 ;
     RECT  28.752 16.019 30.84 16.259 ;
     RECT  93.024 16.213 95.592 16.259 ;
     RECT  12.24 4.501 13.896 16.261 ;
     RECT  14.976 14.773 24.936 16.261 ;
     RECT  91.776 15.829 91.896 16.403 ;
     RECT  7.68 3.925 9.048 16.453 ;
     RECT  93.168 16.259 95.592 16.499 ;
     RECT  125.952 4.501 130.632 16.789 ;
     RECT  131.616 4.501 133.8 16.789 ;
     RECT  101.904 14.291 102.888 17.075 ;
     RECT  31.872 16.019 36.024 17.171 ;
     RECT  47.808 15.683 47.928 17.219 ;
     RECT  102.144 17.075 102.888 17.219 ;
     RECT  97.92 16.019 97.944 17.315 ;
     RECT  10.992 16.405 11.016 17.605 ;
     RECT  12.24 16.261 24.936 17.605 ;
     RECT  34.56 17.171 36.024 17.651 ;
     RECT  99.408 14.531 100.296 18.131 ;
     RECT  87.12 15.349 87.192 18.133 ;
     RECT  99.6 18.131 100.296 18.133 ;
     RECT  30.816 16.259 30.84 18.179 ;
     RECT  82.32 16.019 84.408 18.181 ;
     RECT  77.472 15.443 79.032 18.227 ;
     RECT  76.08 14.339 76.104 18.229 ;
     RECT  80.64 15.443 80.664 18.229 ;
     RECT  82.32 18.181 84.696 18.229 ;
     RECT  75.648 18.229 76.104 18.275 ;
     RECT  80.64 18.229 84.696 18.275 ;
     RECT  87.12 18.133 87.24 18.275 ;
     RECT  94.2 16.499 95.592 18.275 ;
     RECT  27.36 3.925 27.384 18.373 ;
     RECT  88.416 5.077 90.6 18.419 ;
     RECT  91.872 16.403 91.896 18.805 ;
     RECT  10.992 17.605 24.936 18.851 ;
     RECT  77.808 18.227 79.032 18.851 ;
     RECT  88.56 18.419 90.072 18.851 ;
     RECT  106.848 15.587 106.872 18.851 ;
     RECT  28.752 16.259 29.712 18.901 ;
     RECT  12.24 18.851 24.936 18.947 ;
     RECT  34.8 17.651 36.024 18.995 ;
     RECT  41.616 14.339 41.64 18.995 ;
     RECT  99.6 18.133 101.016 19.093 ;
     RECT  98.736 19.093 101.016 19.139 ;
     RECT  104.832 15.587 105.312 19.187 ;
     RECT  26.112 3.925 26.136 19.237 ;
     RECT  27.36 18.373 27.48 19.237 ;
     RECT  91.152 18.805 91.896 19.237 ;
     RECT  93.168 16.499 93.192 19.237 ;
     RECT  96.576 3.925 96.6 19.237 ;
     RECT  97.584 18.661 97.608 19.237 ;
     RECT  26.112 19.237 27.48 19.283 ;
     RECT  91.152 19.237 93.192 19.283 ;
     RECT  31.872 17.171 32.76 19.333 ;
     RECT  78 18.851 79.032 19.333 ;
     RECT  87.216 18.275 87.24 19.333 ;
     RECT  92.256 19.283 93.192 19.333 ;
     RECT  94.2 18.275 94.512 19.333 ;
     RECT  37.296 5.077 37.32 19.379 ;
     RECT  78 19.333 79.464 19.379 ;
     RECT  87.216 19.333 87.384 19.379 ;
     RECT  96.576 19.237 97.608 19.379 ;
     RECT  26.112 19.283 26.904 19.427 ;
     RECT  28.752 18.901 30.6 19.427 ;
     RECT  95.568 18.275 95.592 19.427 ;
     RECT  39.84 16.019 40.512 19.475 ;
     RECT  7.44 16.453 9.048 19.571 ;
     RECT  45.6 15.683 46.008 19.571 ;
     RECT  71.952 14.867 73.896 19.763 ;
     RECT  47.808 17.219 47.832 19.765 ;
     RECT  47.808 19.765 48.216 19.811 ;
     RECT  102.384 17.219 102.888 19.811 ;
     RECT  78 19.379 78.312 19.861 ;
     RECT  65.424 12.995 65.448 19.909 ;
     RECT  65.424 19.909 65.544 19.955 ;
     RECT  26.88 19.427 26.904 20.003 ;
     RECT  31.872 19.333 33.624 20.003 ;
     RECT  42.96 14.723 43.608 20.003 ;
     RECT  80.64 18.275 81.624 20.003 ;
     RECT  67.2 12.995 67.992 20.051 ;
     RECT  110.4 12.563 111.336 20.053 ;
     RECT  40.2 19.475 40.512 20.149 ;
     RECT  83.28 18.275 84.696 20.197 ;
     RECT  71.952 19.763 73.56 20.245 ;
     RECT  71.28 20.245 73.56 20.291 ;
     RECT  31.872 20.003 33.192 20.531 ;
     RECT  65.52 19.955 65.544 20.579 ;
     RECT  69.744 14.867 69.768 20.579 ;
     RECT  92.256 19.333 94.512 20.627 ;
     RECT  121.2 10.165 122.28 20.629 ;
     RECT  123.696 4.693 124.248 20.629 ;
     RECT  25.632 20.149 25.656 20.677 ;
     RECT  42.96 20.003 42.984 20.867 ;
     RECT  12.24 18.947 24.6 20.869 ;
     RECT  25.632 20.677 25.896 20.869 ;
     RECT  28.944 19.427 30.6 20.869 ;
     RECT  31.872 20.531 32.76 20.869 ;
     RECT  96.576 20.725 96.6 20.965 ;
     RECT  97.584 19.379 97.608 20.965 ;
     RECT  80.64 20.003 81.576 21.011 ;
     RECT  96.576 20.965 97.608 21.107 ;
     RECT  75.648 18.275 75.672 21.155 ;
     RECT  108.144 14.867 108.168 21.155 ;
     RECT  109.68 20.053 111.336 21.155 ;
     RECT  119.328 14.629 119.688 21.157 ;
     RECT  34.8 18.995 35.352 21.251 ;
     RECT  80.832 21.011 81.576 21.253 ;
     RECT  80.832 21.253 82.104 21.299 ;
     RECT  48.192 19.811 48.216 21.349 ;
     RECT  49.344 14.867 49.368 21.349 ;
     RECT  48.192 21.349 49.368 21.395 ;
     RECT  72.6 20.291 73.56 21.395 ;
     RECT  40.2 20.149 41.016 21.445 ;
     RECT  45.6 19.571 45.912 21.445 ;
     RECT  118.56 21.157 119.688 21.491 ;
     RECT  40.2 21.445 41.496 21.493 ;
     RECT  98.736 19.139 100.248 21.493 ;
     RECT  40.2 21.493 41.592 21.541 ;
     RECT  45.6 21.445 46.44 21.541 ;
     RECT  28.944 20.869 32.76 21.589 ;
     RECT  39.84 21.541 41.592 21.635 ;
     RECT  83.232 20.197 84.696 21.637 ;
     RECT  109.68 21.155 110.712 21.683 ;
     RECT  119.328 21.491 119.688 21.683 ;
     RECT  83.232 21.637 84.792 21.779 ;
     RECT  45.6 21.541 47.112 21.781 ;
     RECT  28.896 21.589 32.76 21.827 ;
     RECT  67.2 20.051 67.608 21.827 ;
     RECT  77.712 19.861 78.312 21.827 ;
     RECT  37.008 21.541 37.032 21.829 ;
     RECT  28.896 21.827 29.928 21.875 ;
     RECT  31.056 21.827 32.76 21.877 ;
     RECT  33.792 21.781 33.816 21.877 ;
     RECT  27.312 21.109 27.336 21.923 ;
     RECT  38.448 16.019 38.472 21.923 ;
     RECT  37.008 21.829 37.08 21.925 ;
     RECT  44.88 21.781 47.112 21.925 ;
     RECT  48.192 21.395 48.552 21.925 ;
     RECT  71.28 20.291 71.304 21.971 ;
     RECT  113.424 12.563 113.448 21.971 ;
     RECT  36.912 21.925 37.08 22.019 ;
     RECT  94.2 20.627 94.512 22.069 ;
     RECT  95.52 20.437 95.544 22.069 ;
     RECT  103.488 21.061 103.512 22.165 ;
     RECT  104.88 19.187 105.312 22.165 ;
     RECT  36.912 22.019 37.032 22.213 ;
     RECT  36.432 22.213 37.032 22.309 ;
     RECT  44.88 21.925 48.552 22.309 ;
     RECT  82.08 21.299 82.104 22.309 ;
     RECT  83.232 21.779 84.408 22.309 ;
     RECT  86.016 16.019 86.04 22.309 ;
     RECT  34.8 21.251 35.112 22.357 ;
     RECT  36.384 22.309 37.032 22.357 ;
     RECT  88.56 18.851 89.736 22.453 ;
     RECT  28.944 21.875 29.928 22.499 ;
     RECT  31.056 21.877 33.816 22.499 ;
     RECT  12.24 20.869 25.896 22.549 ;
     RECT  86.016 22.309 86.232 22.549 ;
     RECT  98.736 21.493 100.296 22.597 ;
     RECT  29.04 22.499 29.928 22.739 ;
     RECT  31.872 22.499 33.816 22.739 ;
     RECT  32.4 22.739 33.816 22.741 ;
     RECT  34.8 22.357 37.032 22.741 ;
     RECT  85.536 22.549 86.232 22.741 ;
     RECT  87.36 19.379 87.384 22.741 ;
     RECT  92.256 20.627 93.192 22.741 ;
     RECT  94.2 22.069 95.544 22.741 ;
     RECT  96.576 21.107 96.6 22.741 ;
     RECT  98.592 22.597 100.296 22.741 ;
     RECT  101.952 20.149 101.976 22.741 ;
     RECT  121.2 20.629 124.248 22.741 ;
     RECT  125.952 16.789 133.8 22.741 ;
     RECT  7.68 19.571 9.048 22.787 ;
     RECT  12.144 22.549 25.896 22.787 ;
     RECT  67.2 21.827 67.512 22.789 ;
     RECT  92.256 22.741 96.6 22.835 ;
     RECT  103.488 22.165 105.312 22.835 ;
     RECT  39.84 21.635 41.496 22.837 ;
     RECT  32.4 22.741 37.032 22.883 ;
     RECT  110.4 21.683 110.712 22.885 ;
     RECT  119.328 21.683 119.352 22.933 ;
     RECT  39.84 22.837 41.592 22.979 ;
     RECT  85.536 22.741 87.384 22.981 ;
     RECT  88.56 22.453 89.832 22.981 ;
     RECT  91.152 19.283 91.176 22.981 ;
     RECT  92.256 22.835 95.256 23.027 ;
     RECT  29.136 22.739 29.928 23.075 ;
     RECT  52.704 8.869 52.728 23.075 ;
     RECT  115.8 10.883 116.424 23.077 ;
     RECT  64.656 22.741 64.68 23.125 ;
     RECT  70.176 21.541 70.2 23.125 ;
     RECT  27.168 22.741 27.192 23.171 ;
     RECT  118.56 22.933 119.352 23.171 ;
     RECT  42.816 21.061 42.84 23.173 ;
     RECT  85.536 22.981 91.176 23.173 ;
     RECT  108.384 22.741 108.408 23.173 ;
     RECT  115.8 23.077 116.904 23.221 ;
     RECT  70.08 23.125 70.248 23.267 ;
     RECT  29.4 23.075 29.928 23.315 ;
     RECT  42.72 23.173 43.512 23.315 ;
     RECT  80.832 21.299 80.856 23.315 ;
     RECT  115.536 23.221 116.904 23.315 ;
     RECT  70.08 23.267 70.2 23.317 ;
     RECT  72.6 21.395 72.912 23.317 ;
     RECT  79.44 19.379 79.464 23.317 ;
     RECT  82.08 22.309 84.408 23.317 ;
     RECT  85.536 23.173 91.272 23.317 ;
     RECT  96.48 22.835 96.6 23.317 ;
     RECT  97.584 21.107 97.608 23.317 ;
     RECT  98.592 22.741 100.872 23.317 ;
     RECT  101.952 22.741 102.456 23.317 ;
     RECT  115.536 23.315 116.112 23.317 ;
     RECT  44.64 22.309 48.552 23.411 ;
     RECT  106.608 19.909 106.632 23.411 ;
     RECT  43.008 23.315 43.512 23.413 ;
     RECT  44.64 23.411 48.168 23.413 ;
     RECT  110.4 22.885 110.808 23.459 ;
     RECT  12.48 22.787 25.896 23.461 ;
     RECT  114.144 23.317 114.168 23.701 ;
     RECT  78 21.827 78.312 23.797 ;
     RECT  79.44 23.317 79.944 23.797 ;
     RECT  81.072 23.653 81.096 23.845 ;
     RECT  82.08 23.317 91.272 23.845 ;
     RECT  81.072 23.845 91.272 23.893 ;
     RECT  92.256 23.027 92.664 23.893 ;
     RECT  118.56 23.171 118.584 23.939 ;
     RECT  93.792 23.027 95.256 23.941 ;
     RECT  96.48 23.317 100.872 23.941 ;
     RECT  12.48 23.461 26.616 24.709 ;
     RECT  29.4 23.315 29.832 24.947 ;
     RECT  7.68 22.787 8.472 25.715 ;
     RECT  12.48 24.709 26.664 25.813 ;
     RECT  10.992 18.851 11.016 25.861 ;
     RECT  10.416 25.861 11.016 25.907 ;
     RECT  5.76 16.211 5.784 26.531 ;
     RECT  7.68 25.715 8.112 26.725 ;
     RECT  12.48 25.813 26.712 27.299 ;
     RECT  10.416 25.907 10.44 27.301 ;
     RECT  135.36 4.501 139.272 27.301 ;
     RECT  140.256 4.261 140.28 27.301 ;
     RECT  141.408 3.685 141.432 27.301 ;
     RECT  135.36 27.301 141.432 27.733 ;
     RECT  10.416 27.301 10.728 27.779 ;
     RECT  13.008 27.299 26.712 27.779 ;
     RECT  13.008 27.779 14.28 28.453 ;
     RECT  121.2 22.741 133.8 28.547 ;
     RECT  7.68 26.725 8.232 28.645 ;
     RECT  7.68 28.645 9.192 28.691 ;
     RECT  121.2 28.547 130.632 28.931 ;
     RECT  10.416 27.779 10.584 29.123 ;
     RECT  130.416 28.931 130.632 29.219 ;
     RECT  10.56 29.123 10.584 29.747 ;
     RECT  7.68 28.691 8.112 29.795 ;
     RECT  131.616 28.547 133.8 29.989 ;
     RECT  135.36 27.733 141.528 30.035 ;
     RECT  139.248 30.035 141.528 30.275 ;
     RECT  139.344 30.275 141.528 30.371 ;
     RECT  9.168 28.691 9.192 30.803 ;
     RECT  130.512 29.219 130.632 30.901 ;
     RECT  131.616 29.989 134.376 30.901 ;
     RECT  15.264 27.779 26.712 31.043 ;
     RECT  12.336 28.453 14.28 31.379 ;
     RECT  130.512 30.901 134.376 31.667 ;
     RECT  121.2 28.931 129.432 31.861 ;
     RECT  130.512 31.667 133.128 31.861 ;
     RECT  121.2 31.861 133.128 31.907 ;
     RECT  15.456 31.043 26.712 32.195 ;
     RECT  134.352 31.667 134.376 32.437 ;
     RECT  135.36 30.035 138.216 32.437 ;
     RECT  134.352 32.437 138.216 32.531 ;
     RECT  128.496 31.907 133.128 33.827 ;
     RECT  128.496 33.827 132.84 34.067 ;
     RECT  15.456 32.195 26.664 35.317 ;
     RECT  130.608 34.067 132.84 35.317 ;
     RECT  139.344 30.371 139.368 35.363 ;
     RECT  130.608 35.317 133.08 35.653 ;
     RECT  134.352 32.531 134.856 35.653 ;
     RECT  136.272 32.531 138.216 35.653 ;
     RECT  130.608 35.653 138.216 35.699 ;
     RECT  130.608 35.699 133.512 35.845 ;
     RECT  128.496 34.067 129.432 36.133 ;
     RECT  130.56 35.845 133.512 36.133 ;
     RECT  13.056 31.379 14.28 36.227 ;
     RECT  121.2 31.907 127.512 36.709 ;
     RECT  128.496 36.133 133.512 36.709 ;
     RECT  140.592 30.371 141.528 37.043 ;
     RECT  15.36 35.317 26.664 37.091 ;
     RECT  136.752 35.699 138.216 37.619 ;
     RECT  134.832 35.699 135.72 38.149 ;
     RECT  121.2 36.709 133.512 38.389 ;
     RECT  134.832 38.149 135.768 38.389 ;
     RECT  136.752 37.619 138.072 38.389 ;
     RECT  15.984 37.091 26.664 39.013 ;
     RECT  134.832 38.389 138.072 39.107 ;
     RECT  15.984 39.013 26.712 39.203 ;
     RECT  139.392 37.189 139.416 39.253 ;
     RECT  121.2 38.389 133.656 39.299 ;
     RECT  139.248 39.253 139.416 39.299 ;
     RECT  136.08 39.107 137.976 39.923 ;
     RECT  140.592 37.043 141.336 40.451 ;
     RECT  140.592 40.451 140.616 40.595 ;
     RECT  121.2 39.299 127.512 40.789 ;
     RECT  128.544 39.299 133.656 40.789 ;
     RECT  13.2 36.227 14.28 41.075 ;
     RECT  15.984 39.203 26.664 41.075 ;
     RECT  134.832 39.107 134.856 41.509 ;
     RECT  136.08 39.923 137.712 41.509 ;
     RECT  121.2 40.789 133.848 41.651 ;
     RECT  134.832 41.509 137.712 41.651 ;
     RECT  16.08 41.075 26.664 41.795 ;
     RECT  134.832 41.651 136.104 42.467 ;
     RECT  135.36 42.467 136.104 42.803 ;
     RECT  130.176 41.651 132.408 43.285 ;
     RECT  133.824 41.651 133.848 43.285 ;
     RECT  135.408 42.803 136.104 43.285 ;
     RECT  137.4 41.651 137.712 43.285 ;
     RECT  121.2 41.651 129.096 43.379 ;
     RECT  130.176 43.285 133.848 43.379 ;
     RECT  130.176 43.379 130.584 43.955 ;
     RECT  121.2 43.379 128.616 44.483 ;
     RECT  131.712 43.379 133.848 44.483 ;
     RECT  135.408 43.285 137.712 44.483 ;
     RECT  132 44.483 133.848 45.059 ;
     RECT  139.248 39.299 139.272 45.059 ;
     RECT  136.08 44.483 137.712 45.299 ;
     RECT  121.2 44.483 127.224 45.635 ;
     RECT  132 45.059 133.32 45.635 ;
     RECT  137.28 45.299 137.712 46.211 ;
     RECT  136.08 45.299 136.104 46.259 ;
     RECT  16.08 41.795 26.328 46.357 ;
     RECT  121.2 45.635 123.432 47.269 ;
     RECT  124.56 45.635 127.224 47.269 ;
     RECT  16.08 46.357 26.664 49.861 ;
     RECT  16.08 49.861 26.712 50.051 ;
     RECT  121.2 47.269 127.224 55.283 ;
     RECT  121.2 55.283 124.68 57.059 ;
     RECT  132 45.635 132.504 57.395 ;
     RECT  16.08 50.051 26.664 57.781 ;
     RECT  121.2 57.059 124.632 58.739 ;
     RECT  125.76 55.283 127.224 58.739 ;
     RECT  16.08 57.781 26.712 60.707 ;
     RECT  121.2 58.739 124.584 62.101 ;
     RECT  125.808 58.739 127.224 62.101 ;
     RECT  121.2 62.101 127.224 63.299 ;
     RECT  17.376 60.707 26.712 67.093 ;
     RECT  39.84 22.979 41.496 67.237 ;
     RECT  32.976 22.883 37.032 67.283 ;
     RECT  78 23.797 79.944 67.283 ;
     RECT  81.072 23.893 92.664 67.283 ;
     RECT  17.376 67.093 26.808 67.285 ;
     RECT  132 57.395 132.312 67.285 ;
     RECT  43.008 23.413 48.168 67.427 ;
     RECT  47.04 67.427 48.168 67.525 ;
     RECT  43.008 67.427 45.912 67.811 ;
     RECT  103.632 22.835 105.312 67.811 ;
     RECT  43.488 67.811 45.912 68.099 ;
     RECT  43.488 68.099 43.896 68.387 ;
     RECT  93.792 23.941 100.92 68.963 ;
     RECT  113.904 23.701 114.168 68.963 ;
     RECT  115.44 23.317 116.112 68.963 ;
     RECT  32.976 67.283 36.936 69.011 ;
     RECT  47.04 67.525 48.216 69.013 ;
     RECT  108.384 23.173 108.84 69.107 ;
     RECT  67.2 22.789 68.088 69.155 ;
     RECT  69.312 23.317 70.2 69.155 ;
     RECT  64.464 23.125 64.68 69.251 ;
     RECT  64.656 69.251 64.68 69.347 ;
     RECT  70.08 69.155 70.2 69.347 ;
     RECT  71.328 23.317 72.912 69.347 ;
     RECT  47.04 69.013 48.312 69.349 ;
     RECT  108.384 69.107 108.408 69.349 ;
     RECT  65.952 23.317 65.976 69.539 ;
     RECT  33.408 69.011 36.936 69.587 ;
     RECT  44.88 68.099 45.912 69.587 ;
     RECT  74.112 23.125 74.136 69.587 ;
     RECT  43.872 68.387 43.896 69.683 ;
     RECT  17.376 67.285 27.192 69.875 ;
     RECT  33.408 69.587 36.024 70.115 ;
     RECT  17.376 69.875 21.48 70.163 ;
     RECT  128.592 44.483 128.616 70.163 ;
     RECT  33.408 70.115 33.816 70.211 ;
     RECT  33.408 70.211 33.432 70.261 ;
     RECT  22.512 69.875 27.192 70.739 ;
     RECT  39.6 67.237 41.496 70.739 ;
     RECT  34.8 70.115 36.024 71.267 ;
     RECT  22.512 70.739 26.616 71.411 ;
     RECT  17.376 70.163 21.096 71.459 ;
     RECT  118.56 70.357 118.584 71.651 ;
     RECT  45.36 69.587 45.912 71.797 ;
     RECT  110.4 23.459 110.712 72.133 ;
     RECT  17.376 71.459 20.856 73.139 ;
     RECT  17.376 73.139 20.136 73.283 ;
     RECT  121.2 63.299 124.872 75.541 ;
     RECT  126.6 63.299 127.224 75.541 ;
     RECT  121.2 75.541 127.224 75.587 ;
     RECT  111.984 24.805 112.008 75.971 ;
     RECT  93.792 68.963 96.504 76.357 ;
     RECT  130.56 43.955 130.584 76.979 ;
     RECT  115.8 68.963 116.112 77.125 ;
     RECT  121.2 75.587 124.536 77.555 ;
     RECT  118.368 72.565 118.392 78.229 ;
     RECT  118.368 78.229 119.16 78.275 ;
     RECT  115.8 77.125 116.232 78.613 ;
     RECT  115.8 78.613 117.144 78.659 ;
     RECT  17.712 73.283 20.136 78.947 ;
     RECT  23.04 71.411 26.616 79.763 ;
     RECT  39.6 70.739 41.256 79.859 ;
     RECT  46.944 69.349 48.312 79.859 ;
     RECT  97.776 68.963 100.92 80.291 ;
     RECT  40.08 79.859 41.256 80.341 ;
     RECT  47.04 79.859 48.312 80.341 ;
     RECT  23.136 79.763 26.616 81.203 ;
     RECT  33.36 70.261 33.432 81.203 ;
     RECT  113.904 68.963 113.928 81.445 ;
     RECT  125.808 75.587 127.224 81.539 ;
     RECT  23.184 81.203 26.616 82.259 ;
     RECT  17.712 78.947 19.32 82.691 ;
     RECT  113.904 81.445 114.024 82.691 ;
     RECT  119.136 78.275 119.16 82.691 ;
     RECT  33.408 81.203 33.432 82.979 ;
     RECT  17.76 82.691 19.32 83.171 ;
     RECT  44.688 71.797 45.912 83.267 ;
     RECT  47.04 80.341 48.408 83.267 ;
     RECT  23.232 82.259 26.616 83.507 ;
     RECT  43.056 81.445 43.08 83.843 ;
     RECT  121.2 77.555 124.296 84.659 ;
     RECT  56.4 9.059 56.712 84.901 ;
     RECT  72.6 69.347 72.912 84.901 ;
     RECT  40.08 80.341 41.352 84.995 ;
     RECT  44.784 83.267 45.912 85.043 ;
     RECT  56.4 84.901 57.624 85.477 ;
     RECT  98.784 80.291 100.92 85.477 ;
     RECT  101.904 23.317 102.456 85.477 ;
     RECT  108.144 69.349 108.408 85.523 ;
     RECT  23.232 83.507 26.568 85.571 ;
     RECT  23.232 85.571 26.376 85.667 ;
     RECT  32.16 73.237 32.184 85.765 ;
     RECT  45.504 85.043 45.912 85.765 ;
     RECT  23.232 85.667 26.184 85.811 ;
     RECT  43.248 84.181 43.272 85.909 ;
     RECT  16.08 60.707 16.104 86.005 ;
     RECT  47.088 83.267 48.408 86.005 ;
     RECT  61.8 9.827 62.112 86.005 ;
     RECT  78 67.283 78.312 86.005 ;
     RECT  121.2 84.659 122.232 86.051 ;
     RECT  47.088 86.005 48.888 86.099 ;
     RECT  47.232 86.099 48.888 86.147 ;
     RECT  51 2.151 51.312 86.485 ;
     RECT  15.216 86.005 16.104 86.531 ;
     RECT  13.2 41.075 13.512 86.581 ;
     RECT  18 83.171 19.32 86.581 ;
     RECT  42.48 85.909 43.272 86.581 ;
     RECT  50.736 86.485 51.312 86.581 ;
     RECT  52.8 85.909 52.824 86.581 ;
     RECT  60.816 86.005 62.112 86.581 ;
     RECT  93.744 76.357 96.504 86.581 ;
     RECT  97.776 80.291 97.8 86.581 ;
     RECT  112.752 83.173 112.776 86.581 ;
     RECT  114 82.691 114.024 86.581 ;
     RECT  24 85.811 26.184 86.629 ;
     RECT  47.232 86.147 47.64 86.675 ;
     RECT  72.6 84.901 73.224 86.675 ;
     RECT  79.92 67.283 79.944 86.675 ;
     RECT  81.408 67.283 92.664 86.675 ;
     RECT  93.744 86.581 97.8 86.675 ;
     RECT  109.488 72.133 110.712 86.675 ;
     RECT  81.408 86.675 86.376 86.723 ;
     RECT  97.44 86.675 97.8 86.723 ;
     RECT  98.784 85.477 102.456 86.723 ;
     RECT  103.968 67.811 105.312 86.723 ;
     RECT  106.896 23.701 106.92 86.723 ;
     RECT  32.16 85.765 33.096 86.725 ;
     RECT  32.16 86.725 33.624 86.771 ;
     RECT  45.504 85.765 46.056 86.771 ;
     RECT  97.44 86.723 97.464 86.771 ;
     RECT  98.784 86.723 101.016 86.771 ;
     RECT  112.752 86.581 114.024 86.771 ;
     RECT  24 86.629 26.808 86.819 ;
     RECT  45.504 86.771 45.912 86.819 ;
     RECT  47.616 86.675 47.64 86.915 ;
     RECT  77.232 86.005 78.552 87.011 ;
     RECT  115.8 78.659 116.112 87.061 ;
     RECT  7.8 29.795 8.112 87.109 ;
     RECT  67.2 69.155 67.512 87.109 ;
     RECT  24 86.819 26.184 87.155 ;
     RECT  32.16 86.771 32.232 87.155 ;
     RECT  42.48 86.581 43.368 87.155 ;
     RECT  29.4 24.947 29.712 87.157 ;
     RECT  40.2 84.995 41.064 87.157 ;
     RECT  42.624 87.155 43.368 87.157 ;
     RECT  44.592 87.109 44.616 87.157 ;
     RECT  59.616 86.533 59.64 87.157 ;
     RECT  60.816 86.581 62.232 87.157 ;
     RECT  81.408 86.723 84.744 87.157 ;
     RECT  56.208 85.477 57.624 87.203 ;
     RECT  15.216 86.531 15.24 87.251 ;
     RECT  42.624 87.157 44.616 87.251 ;
     RECT  81.216 87.157 84.744 87.251 ;
     RECT  86.352 86.723 86.376 87.251 ;
     RECT  87.696 86.675 91.656 87.251 ;
     RECT  93.744 86.675 95.832 87.251 ;
     RECT  98.784 86.771 100.968 87.251 ;
     RECT  103.968 86.723 103.992 87.251 ;
     RECT  50.688 86.581 51.312 87.299 ;
     RECT  59.616 87.157 62.232 87.299 ;
     RECT  79.632 87.157 79.656 87.299 ;
     RECT  112.752 86.771 112.776 87.299 ;
     RECT  115.152 87.061 116.112 87.347 ;
     RECT  24 87.155 26.136 87.395 ;
     RECT  32.16 87.155 32.184 87.397 ;
     RECT  52.8 86.581 53.784 87.491 ;
     RECT  17.04 86.581 19.32 87.539 ;
     RECT  31.296 87.397 32.184 87.587 ;
     RECT  114 86.771 114.024 87.587 ;
     RECT  105 86.723 105.312 87.589 ;
     RECT  13.2 86.581 13.608 87.685 ;
     RECT  59.616 87.299 62.112 87.685 ;
     RECT  72.6 86.675 72.912 87.685 ;
     RECT  59.28 87.685 62.112 87.731 ;
     RECT  7.8 87.109 9.096 87.779 ;
     RECT  24 87.395 25.272 87.827 ;
     RECT  33.6 86.771 33.624 87.827 ;
     RECT  43.344 87.251 44.616 87.827 ;
     RECT  48.864 86.147 48.888 87.827 ;
     RECT  56.4 87.203 57.624 87.827 ;
     RECT  66.096 86.725 66.12 87.827 ;
     RECT  67.2 87.109 68.136 87.827 ;
     RECT  83.4 87.251 84.024 87.827 ;
     RECT  92.64 86.675 92.664 87.827 ;
     RECT  99.168 87.251 100.968 87.827 ;
     RECT  108.144 85.523 108.168 87.827 ;
     RECT  123.312 84.659 124.296 87.827 ;
     RECT  50.736 87.299 51.312 87.875 ;
     RECT  128.736 75.397 128.76 87.875 ;
     RECT  63.36 86.629 63.384 87.923 ;
     RECT  88.8 87.251 90.696 87.923 ;
     RECT  125.808 81.539 126.912 87.923 ;
     RECT  40.2 87.157 41.256 87.971 ;
     RECT  88.8 87.923 90.408 87.971 ;
     RECT  36.432 87.157 36.456 88.115 ;
     RECT  52.992 87.491 53.784 88.115 ;
     RECT  102 86.723 102.024 88.115 ;
     RECT  117.12 78.659 117.144 88.115 ;
     RECT  78 87.011 78.552 88.211 ;
     RECT  60.384 87.731 62.112 88.355 ;
     RECT  93.744 87.251 94.512 88.355 ;
     RECT  119.04 83.125 119.064 88.355 ;
     RECT  24 87.827 24.456 88.403 ;
     RECT  37.632 86.485 37.656 88.403 ;
     RECT  43.872 87.827 44.616 88.403 ;
     RECT  52.992 88.115 53.016 88.403 ;
     RECT  72.096 87.685 73.464 88.403 ;
     RECT  76.992 87.685 77.016 88.403 ;
     RECT  94.08 88.355 94.512 88.403 ;
     RECT  95.952 87.781 95.976 88.403 ;
     RECT  99.6 87.827 100.008 88.403 ;
     RECT  17.616 87.539 19.32 88.451 ;
     RECT  59.28 87.731 59.304 88.499 ;
     RECT  131.904 67.285 132.312 88.499 ;
     RECT  15.408 88.165 15.432 88.547 ;
     RECT  61.056 88.355 62.112 88.547 ;
     RECT  87.216 87.733 87.24 88.595 ;
     RECT  13.2 87.685 14.376 88.643 ;
     RECT  17.616 88.451 19.032 88.643 ;
     RECT  28.464 87.157 29.712 88.643 ;
     RECT  88.8 87.971 89.688 88.643 ;
     RECT  48.816 88.213 48.84 88.691 ;
     RECT  22.656 85.861 22.68 88.739 ;
     RECT  17.616 88.643 18.912 88.787 ;
     RECT  81.216 87.251 81.24 88.835 ;
     RECT  31.296 87.587 31.32 88.883 ;
     RECT  43.872 88.403 43.896 88.931 ;
     RECT  105 87.589 105.432 88.931 ;
     RECT  7.8 87.779 8.112 89.509 ;
     RECT  24 88.403 24.312 89.509 ;
     RECT  29.4 88.643 29.712 89.509 ;
     RECT  34.8 71.267 35.112 89.509 ;
     RECT  40.2 87.971 40.512 89.509 ;
     RECT  45.6 86.819 45.912 89.509 ;
     RECT  51 87.875 51.312 89.509 ;
     RECT  56.4 87.827 56.712 89.509 ;
     RECT  67.2 87.827 67.512 89.509 ;
     RECT  70.176 69.347 70.2 89.509 ;
     RECT  78 88.211 78.312 89.509 ;
     RECT  83.4 87.827 83.712 89.509 ;
     RECT  88.8 88.643 89.544 89.509 ;
     RECT  94.2 88.403 94.512 89.509 ;
     RECT  99.6 88.403 99.912 89.509 ;
     RECT  110.4 86.675 110.712 89.509 ;
     RECT  126.6 87.923 126.912 89.509 ;
     RECT  132 88.499 132.312 89.509 ;
     RECT  137.4 46.211 137.712 89.509 ;
     RECT  2.4 2.151 2.712 89.649 ;
     RECT  18.6 88.787 18.912 89.649 ;
     RECT  23.04 89.509 24.312 89.649 ;
     RECT  45.216 89.509 45.912 89.649 ;
     RECT  61.8 88.547 62.112 89.649 ;
     RECT  66.288 89.509 67.512 89.649 ;
     RECT  72.6 88.403 72.912 89.649 ;
     RECT  109.584 89.509 110.712 89.649 ;
     RECT  115.8 87.347 116.112 89.649 ;
     RECT  142.8 2.151 143.112 89.649 ;
     RECT  2.4 89.649 2.52 89.663 ;
     RECT  7.8 89.509 8.28 89.663 ;
     RECT  13.2 88.643 13.512 89.663 ;
     RECT  18.6 89.649 18.72 89.663 ;
     RECT  23.04 89.649 24.12 89.663 ;
     RECT  29.4 89.509 30.456 89.663 ;
     RECT  34.656 89.509 35.736 89.663 ;
     RECT  39.936 89.509 40.512 89.663 ;
     RECT  45.216 89.649 45.72 89.663 ;
     RECT  51 89.509 51.576 89.663 ;
     RECT  56.4 89.509 56.808 89.663 ;
     RECT  61.8 89.649 62.088 89.663 ;
     RECT  66.288 89.649 67.368 89.663 ;
     RECT  72.6 89.649 72.72 89.663 ;
     RECT  77.904 89.509 78.312 89.663 ;
     RECT  83.184 89.509 84.264 89.663 ;
     RECT  88.464 89.509 89.544 89.663 ;
     RECT  93.744 89.509 94.512 89.663 ;
     RECT  99.6 89.509 100.104 89.663 ;
     RECT  105 88.931 105.312 89.663 ;
     RECT  109.584 89.649 110.52 89.663 ;
     RECT  115.8 89.649 115.944 89.663 ;
     RECT  121.2 86.051 121.512 89.663 ;
     RECT  126.432 89.509 126.912 89.663 ;
     RECT  132 89.509 132.792 89.663 ;
     RECT  137.4 89.509 138.072 89.663 ;
     RECT  142.8 89.649 142.92 89.663 ;
     RECT  69.456 89.509 70.536 91.608 ;
     RECT  69.48 91.608 70.512 91.619 ;
     RECT  71.256 3.157 72.6 3.733 ;
     RECT  49.56 3.301 51 14.867 ;
     RECT  82.344 3.301 83.4 4.261 ;
     RECT  93.048 3.301 94.2 14.773 ;
     RECT  136.296 3.301 137.4 4.501 ;
     RECT  21.912 3.637 23.136 4.501 ;
     RECT  10.968 3.685 12.24 16.019 ;
     RECT  19.704 3.685 21.024 3.781 ;
     RECT  84.408 3.685 85.728 14.629 ;
     RECT  141.432 3.685 142.8 27.733 ;
     RECT  51.312 3.733 52.752 8.579 ;
     RECT  85.752 3.733 87.168 14.245 ;
     RECT  132.312 3.733 133.776 4.501 ;
     RECT  19.944 3.781 21.024 4.453 ;
     RECT  40.512 3.877 41.616 18.995 ;
     RECT  60.792 3.877 61.8 4.643 ;
     RECT  6.264 3.925 7.68 4.117 ;
     RECT  26.136 3.925 27.36 19.237 ;
     RECT  27.384 3.925 28.656 14.387 ;
     RECT  29.712 3.925 31.008 14.725 ;
     RECT  44.136 3.925 45.6 12.419 ;
     RECT  45.912 3.925 47.376 4.261 ;
     RECT  72.912 3.925 74.208 12.373 ;
     RECT  76.104 3.925 77.232 5.077 ;
     RECT  87.192 3.925 88.416 18.133 ;
     RECT  96.6 3.925 97.92 17.315 ;
     RECT  130.44 3.925 131.904 4.501 ;
     RECT  6.36 4.117 7.68 16.211 ;
     RECT  54.36 4.117 55.872 4.595 ;
     RECT  13.512 4.261 14.976 4.501 ;
     RECT  31.512 4.261 32.976 13.285 ;
     RECT  46.008 4.261 47.376 11.125 ;
     RECT  95.208 4.261 96.576 16.213 ;
     RECT  128.472 4.261 129.84 4.501 ;
     RECT  139.272 4.261 140.256 27.301 ;
     RECT  140.28 4.261 141.408 27.301 ;
     RECT  19.944 4.453 20.976 5.509 ;
     RECT  13.896 4.501 14.976 16.261 ;
     RECT  38.472 4.501 39.792 12.517 ;
     RECT  68.088 4.501 69.456 12.995 ;
     RECT  130.632 4.501 131.616 16.789 ;
     RECT  61.008 4.643 61.8 5.701 ;
     RECT  80.904 4.837 82.32 13.043 ;
     RECT  102.888 4.837 104.352 12.419 ;
     RECT  106.872 4.837 108.048 14.867 ;
     RECT  119.688 4.837 121.2 21.683 ;
     RECT  65.208 4.933 66.384 12.563 ;
     RECT  36.024 5.077 37.296 18.995 ;
     RECT  37.32 5.077 38.448 19.379 ;
     RECT  97.944 5.077 99.36 14.485 ;
     RECT  54.888 7.957 55.92 9.059 ;
     RECT  51.312 8.579 52.728 8.869 ;
     RECT  51.312 8.869 52.704 23.075 ;
     RECT  54.888 9.059 56.4 11.363 ;
     RECT  122.28 10.165 123.696 20.629 ;
     RECT  46.056 11.125 47.376 15.683 ;
     RECT  76.104 11.459 77.232 14.099 ;
     RECT  16.152 11.653 17.376 13.909 ;
     RECT  42.456 12.373 43.584 14.293 ;
     RECT  102.888 12.419 104.832 12.517 ;
     RECT  38.472 12.517 39.696 14.773 ;
     RECT  103.752 12.517 104.832 14.291 ;
     RECT  65.208 12.563 65.448 12.949 ;
     RECT  67.992 12.995 69.456 14.867 ;
     RECT  105.312 13.525 106.56 14.581 ;
     RECT  32.904 13.667 33 14.725 ;
     RECT  90.6 14.053 91.872 15.829 ;
     RECT  76.104 14.099 77.472 18.227 ;
     RECT  91.896 14.099 93.024 16.259 ;
     RECT  86.04 14.245 87.168 15.349 ;
     RECT  41.64 14.339 42.96 18.995 ;
     RECT  27.384 14.387 28.752 18.373 ;
     RECT  98.04 14.485 99.36 14.531 ;
     RECT  98.04 14.531 99.408 16.019 ;
     RECT  24.936 14.773 26.112 18.947 ;
     RECT  38.664 14.773 39.696 16.019 ;
     RECT  106.872 14.867 108.144 18.851 ;
     RECT  47.928 15.349 49.344 17.219 ;
     RECT  86.04 15.349 87.12 18.275 ;
     RECT  90.6 15.829 91.776 16.403 ;
     RECT  10.992 16.019 12.24 16.405 ;
     RECT  30.84 16.019 31.872 18.179 ;
     RECT  38.472 16.019 39.84 19.475 ;
     RECT  97.944 16.019 99.408 17.315 ;
     RECT  7.44 16.211 7.68 16.453 ;
     RECT  95.592 16.213 96.576 19.379 ;
     RECT  29.712 16.259 30.816 18.179 ;
     RECT  91.896 16.259 93.168 19.237 ;
     RECT  90.6 16.403 91.872 18.419 ;
     RECT  11.016 16.405 12.24 17.605 ;
     RECT  93.192 16.499 94.2 19.333 ;
     RECT  101.904 17.075 102.144 17.219 ;
     RECT  47.832 17.219 49.344 19.765 ;
     RECT  101.904 17.219 102.384 18.133 ;
     RECT  96.6 17.315 97.608 18.661 ;
     RECT  99.408 18.131 99.6 19.093 ;
     RECT  87.24 18.133 88.416 18.419 ;
     RECT  101.016 18.133 102.384 19.139 ;
     RECT  29.712 18.179 31.872 18.901 ;
     RECT  84.696 18.181 86.016 21.637 ;
     RECT  86.04 18.275 87.216 19.379 ;
     RECT  94.512 18.275 95.568 19.427 ;
     RECT  27.48 18.373 28.752 19.283 ;
     RECT  87.24 18.419 88.56 19.333 ;
     RECT  90.072 18.419 91.872 18.805 ;
     RECT  96.6 18.661 97.584 19.237 ;
     RECT  90.072 18.805 91.152 18.851 ;
     RECT  11.016 18.851 12.24 22.549 ;
     RECT  77.808 18.851 78 19.861 ;
     RECT  89.736 18.851 91.152 22.453 ;
     RECT  106.848 18.851 108.144 19.909 ;
     RECT  30.6 18.901 31.872 20.869 ;
     RECT  24.6 18.947 26.112 19.427 ;
     RECT  40.512 18.995 41.016 20.149 ;
     RECT  97.608 19.093 98.736 22.597 ;
     RECT  101.952 19.139 102.384 19.811 ;
     RECT  91.176 19.283 92.256 23.173 ;
     RECT  33.624 19.333 34.8 20.003 ;
     RECT  79.464 19.333 80.64 21.011 ;
     RECT  87.384 19.333 88.56 22.981 ;
     RECT  78.312 19.379 79.44 23.797 ;
     RECT  86.04 19.379 87.36 22.309 ;
     RECT  95.592 19.379 97.584 19.427 ;
     RECT  24.6 19.427 26.88 20.003 ;
     RECT  94.512 19.427 97.584 20.437 ;
     RECT  48.216 19.765 49.344 21.349 ;
     RECT  101.952 19.811 102.888 20.149 ;
     RECT  105.312 19.909 106.608 23.411 ;
     RECT  106.632 19.909 108.144 21.155 ;
     RECT  24.6 20.003 26.904 20.149 ;
     RECT  81.576 20.003 81.624 21.253 ;
     RECT  108.168 20.053 109.68 21.155 ;
     RECT  24.6 20.149 25.632 20.869 ;
     RECT  25.656 20.149 26.904 20.677 ;
     RECT  101.976 20.149 102.888 21.061 ;
     RECT  69.768 20.245 71.28 20.579 ;
     RECT  71.304 20.291 72.6 21.971 ;
     RECT  94.512 20.437 95.52 22.069 ;
     RECT  95.544 20.437 97.584 20.725 ;
     RECT  32.76 20.531 33.192 21.781 ;
     RECT  70.176 20.579 71.28 21.541 ;
     RECT  93.192 20.627 94.2 22.741 ;
     RECT  25.896 20.677 26.904 21.109 ;
     RECT  95.544 20.725 96.576 22.741 ;
     RECT  96.6 20.725 97.584 20.965 ;
     RECT  79.464 21.011 80.832 23.315 ;
     RECT  101.976 21.061 103.488 22.741 ;
     RECT  103.512 21.061 104.88 22.165 ;
     RECT  96.6 21.107 97.584 23.317 ;
     RECT  25.896 21.109 27.312 21.923 ;
     RECT  35.112 21.251 35.352 22.213 ;
     RECT  82.104 21.253 83.232 22.309 ;
     RECT  80.856 21.299 82.08 23.315 ;
     RECT  41.496 21.445 42.816 21.493 ;
     RECT  118.56 21.491 119.328 22.933 ;
     RECT  41.592 21.493 42.816 21.635 ;
     RECT  37.032 21.541 38.448 21.829 ;
     RECT  38.472 21.541 39.84 21.923 ;
     RECT  47.112 21.541 48.192 21.925 ;
     RECT  70.2 21.541 71.28 21.971 ;
     RECT  41.496 21.635 42.816 22.837 ;
     RECT  84.792 21.637 86.016 21.779 ;
     RECT  84.408 21.779 86.016 22.549 ;
     RECT  32.76 21.781 33.792 21.877 ;
     RECT  33.816 21.781 34.8 22.741 ;
     RECT  29.928 21.827 31.056 22.499 ;
     RECT  67.512 21.827 67.608 22.789 ;
     RECT  37.08 21.829 38.448 21.923 ;
     RECT  25.896 21.923 27.192 22.741 ;
     RECT  70.2 21.971 72.6 23.125 ;
     RECT  35.112 22.213 36.432 22.309 ;
     RECT  35.112 22.309 36.384 22.357 ;
     RECT  86.232 22.309 87.36 22.741 ;
     RECT  89.832 22.453 91.152 22.981 ;
     RECT  11.016 22.549 12.144 22.787 ;
     RECT  84.408 22.549 85.536 23.317 ;
     RECT  97.608 22.597 98.592 23.317 ;
     RECT  25.896 22.741 27.168 23.171 ;
     RECT  100.872 22.741 101.952 23.317 ;
     RECT  102.456 22.741 103.488 22.835 ;
     RECT  11.016 22.787 12.48 25.907 ;
     RECT  95.256 22.835 96.48 23.941 ;
     RECT  102.456 22.835 103.632 67.811 ;
     RECT  41.592 22.837 42.816 22.979 ;
     RECT  41.496 22.979 42.816 23.173 ;
     RECT  92.664 23.027 93.792 76.357 ;
     RECT  70.248 23.125 72.6 23.267 ;
     RECT  72.912 23.125 74.112 69.587 ;
     RECT  25.896 23.171 26.616 23.461 ;
     RECT  41.496 23.173 42.72 23.315 ;
     RECT  43.512 23.173 44.64 23.413 ;
     RECT  91.272 23.173 92.256 23.893 ;
     RECT  70.2 23.267 72.6 23.317 ;
     RECT  41.496 23.315 43.008 67.811 ;
     RECT  79.464 23.315 82.08 23.317 ;
     RECT  64.68 23.317 65.952 69.347 ;
     RECT  65.976 23.317 67.2 69.539 ;
     RECT  68.088 23.317 69.312 69.155 ;
     RECT  70.2 23.317 71.328 69.347 ;
     RECT  79.944 23.317 82.08 23.653 ;
     RECT  100.872 23.317 101.904 23.941 ;
     RECT  114.168 23.317 115.44 68.963 ;
     RECT  110.712 23.459 110.808 24.805 ;
     RECT  79.944 23.653 81.072 67.283 ;
     RECT  81.096 23.653 82.08 23.845 ;
     RECT  106.92 23.701 108.384 69.349 ;
     RECT  100.92 23.941 101.904 85.477 ;
     RECT  110.712 24.805 111.984 75.971 ;
     RECT  8.112 25.715 8.232 26.725 ;
     RECT  10.44 25.907 10.728 27.301 ;
     RECT  12.48 27.299 13.008 28.453 ;
     RECT  141.528 27.733 142.8 37.043 ;
     RECT  14.28 27.779 15.264 31.043 ;
     RECT  130.632 28.547 131.616 30.901 ;
     RECT  9.192 28.645 10.416 29.123 ;
     RECT  8.112 28.691 9.168 30.803 ;
     RECT  129.432 28.931 130.416 29.219 ;
     RECT  9.192 29.123 10.56 29.747 ;
     RECT  129.432 29.219 130.512 31.861 ;
     RECT  134.376 29.989 135.36 32.437 ;
     RECT  138.216 30.035 139.248 30.275 ;
     RECT  138.216 30.275 139.344 35.363 ;
     RECT  139.368 30.371 140.592 35.363 ;
     RECT  14.28 31.043 15.456 35.317 ;
     RECT  133.128 31.667 134.352 33.827 ;
     RECT  127.512 31.907 128.496 36.709 ;
     RECT  134.856 32.531 136.272 35.653 ;
     RECT  132.84 33.827 134.352 35.317 ;
     RECT  129.432 34.067 130.608 35.845 ;
     RECT  14.28 35.317 15.36 37.091 ;
     RECT  133.08 35.317 134.352 35.653 ;
     RECT  133.512 35.699 134.832 38.389 ;
     RECT  135.72 35.699 136.752 38.149 ;
     RECT  129.432 35.845 130.56 36.133 ;
     RECT  141.336 37.043 142.8 40.451 ;
     RECT  138.216 37.189 139.392 37.619 ;
     RECT  139.416 37.189 140.592 39.299 ;
     RECT  138.072 37.619 139.392 39.107 ;
     RECT  135.768 38.149 136.752 38.389 ;
     RECT  133.656 38.389 134.832 40.789 ;
     RECT  134.856 39.107 136.08 41.509 ;
     RECT  137.976 39.107 139.392 39.253 ;
     RECT  137.976 39.253 139.248 39.923 ;
     RECT  127.512 39.299 128.544 40.789 ;
     RECT  139.272 39.299 140.592 40.595 ;
     RECT  133.848 40.789 134.832 42.467 ;
     RECT  129.096 41.651 130.176 43.379 ;
     RECT  132.408 41.651 133.824 43.285 ;
     RECT  136.104 41.651 137.4 43.285 ;
     RECT  133.848 42.467 135.36 42.803 ;
     RECT  130.584 43.379 131.712 44.483 ;
     RECT  127.224 44.483 128.592 70.163 ;
     RECT  130.584 44.483 132 67.285 ;
     RECT  136.104 45.299 137.28 46.211 ;
     RECT  123.432 45.635 124.56 47.269 ;
     RECT  136.104 46.211 137.4 46.259 ;
     RECT  124.68 55.283 125.76 57.059 ;
     RECT  124.632 57.059 125.76 58.739 ;
     RECT  124.584 58.739 125.808 62.101 ;
     RECT  16.104 60.707 17.376 73.283 ;
     RECT  79.944 67.283 81.408 86.675 ;
     RECT  130.584 67.285 131.904 76.979 ;
     RECT  45.912 67.427 47.04 69.349 ;
     RECT  102.456 67.811 103.968 86.723 ;
     RECT  43.896 68.099 44.88 69.587 ;
     RECT  96.504 68.963 97.776 86.581 ;
     RECT  33.36 69.011 33.408 70.261 ;
     RECT  45.912 69.349 46.944 79.859 ;
     RECT  106.92 69.349 108.144 86.723 ;
     RECT  43.896 69.587 45.36 69.683 ;
     RECT  21.48 69.875 22.512 70.163 ;
     RECT  33.816 70.115 34.8 70.211 ;
     RECT  21.096 70.163 22.512 71.411 ;
     RECT  33.432 70.211 34.8 82.979 ;
     RECT  108.408 72.133 109.488 85.523 ;
     RECT  32.184 73.237 33.36 81.203 ;
     RECT  127.224 75.397 128.736 81.539 ;
     RECT  124.536 75.587 125.808 77.555 ;
     RECT  92.664 76.357 93.744 87.827 ;
     RECT  124.296 77.555 125.808 87.827 ;
     RECT  116.112 78.659 117.12 88.115 ;
     RECT  45.912 79.859 47.04 83.267 ;
     RECT  97.8 80.291 98.784 86.723 ;
     RECT  32.184 81.203 33.408 82.979 ;
     RECT  113.904 82.691 114 83.173 ;
     RECT  112.776 83.173 114 86.581 ;
     RECT  44.688 83.267 44.784 84.181 ;
     RECT  45.912 83.267 47.088 85.765 ;
     RECT  43.272 84.181 44.784 85.043 ;
     RECT  122.232 84.659 123.312 86.051 ;
     RECT  41.064 84.995 41.352 85.909 ;
     RECT  108.168 85.523 109.488 86.675 ;
     RECT  26.376 85.571 26.568 85.667 ;
     RECT  26.184 85.667 26.568 86.629 ;
     RECT  46.056 85.765 47.088 86.099 ;
     RECT  23.232 85.811 24 85.861 ;
     RECT  22.68 85.861 24 88.739 ;
     RECT  41.064 85.909 42.48 87.155 ;
     RECT  51.312 85.909 52.8 87.491 ;
     RECT  78.552 86.005 79.92 86.675 ;
     RECT  46.056 86.099 47.232 86.675 ;
     RECT  47.64 86.147 48.864 86.915 ;
     RECT  59.64 86.533 60.816 87.157 ;
     RECT  62.232 86.629 63.36 87.299 ;
     RECT  72.912 86.675 73.224 87.685 ;
     RECT  78.552 86.675 79.656 87.157 ;
     RECT  81.216 86.675 81.408 87.157 ;
     RECT  86.376 86.675 87.696 87.251 ;
     RECT  91.656 86.675 92.64 87.251 ;
     RECT  95.832 86.675 97.44 86.771 ;
     RECT  97.464 86.723 98.784 86.771 ;
     RECT  101.016 86.723 102 86.771 ;
     RECT  103.992 86.723 105 87.251 ;
     RECT  33.624 86.725 34.8 87.827 ;
     RECT  66.12 86.725 67.2 87.827 ;
     RECT  32.232 86.771 33.6 87.155 ;
     RECT  95.832 86.771 95.976 87.251 ;
     RECT  100.968 86.771 102 87.827 ;
     RECT  112.776 86.771 114 87.299 ;
     RECT  45.504 86.819 45.6 87.109 ;
     RECT  48.816 86.915 48.864 87.827 ;
     RECT  77.232 87.011 78 87.685 ;
     RECT  114.024 87.061 115.152 87.347 ;
     RECT  43.368 87.109 44.592 87.157 ;
     RECT  44.616 87.109 45.6 88.403 ;
     RECT  32.184 87.155 33.6 87.587 ;
     RECT  41.064 87.155 42.624 87.157 ;
     RECT  35.112 87.157 36.432 88.115 ;
     RECT  36.456 87.157 37.632 88.115 ;
     RECT  41.256 87.157 42.624 87.251 ;
     RECT  78.552 87.157 79.632 87.299 ;
     RECT  15.216 87.251 15.24 87.685 ;
     RECT  87.216 87.251 87.24 87.733 ;
     RECT  94.512 87.251 95.976 87.781 ;
     RECT  62.112 87.299 63.36 87.923 ;
     RECT  14.376 87.685 15.24 88.165 ;
     RECT  77.016 87.685 78 88.403 ;
     RECT  59.304 87.731 60.384 88.355 ;
     RECT  94.512 87.781 95.952 88.403 ;
     RECT  48.816 87.827 48.84 88.213 ;
     RECT  35.112 88.115 35.736 89.509 ;
     RECT  14.376 88.165 15.408 88.547 ;
     RECT  93.744 88.355 94.08 88.403 ;
     RECT  43.896 88.403 45.6 88.931 ;
     RECT  77.904 88.403 78 89.509 ;
     RECT  93.744 88.403 94.2 89.509 ;
     RECT  99.912 88.403 100.008 89.509 ;
     RECT  23.04 88.739 24 89.509 ;
     RECT  45.216 88.931 45.6 89.509 ;
  END
END ot_s81_hc_ccf_bankpipe_bank256
END LIBRARY
